VERSION 5.7 ;
BUSBITCHARS "[]" ;
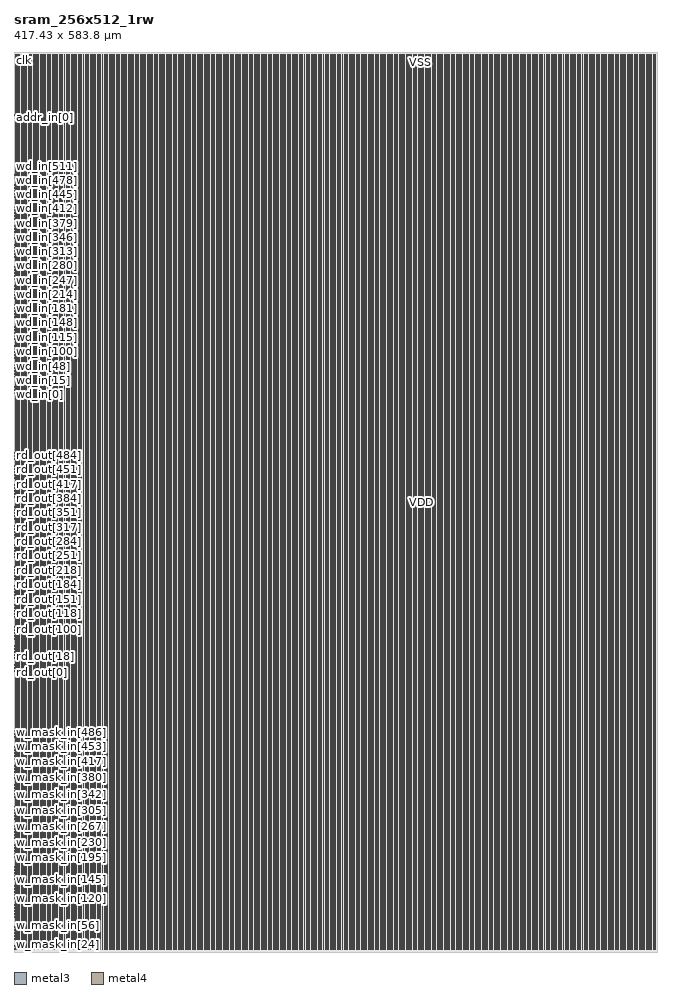
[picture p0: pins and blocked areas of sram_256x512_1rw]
MACRO sram_256x512_1rw
  FOREIGN sram_256x512_1rw 0 0 ;
  SYMMETRY X Y R90 ;
  SIZE 417.430 BY 583.800 ;
  CLASS BLOCK ;
  PIN w_mask_in[0]
    DIRECTION INPUT ;
    USE SIGNAL ;
    SHAPE ABUTMENT ;
    PORT
      LAYER metal3 ;
      RECT 0.000 1.365 0.070 1.435 ;
    END
  END w_mask_in[0]
  PIN w_mask_in[1]
    DIRECTION INPUT ;
    USE SIGNAL ;
    SHAPE ABUTMENT ;
    PORT
      LAYER metal3 ;
      RECT 0.000 1.645 0.070 1.715 ;
    END
  END w_mask_in[1]
  PIN w_mask_in[2]
    DIRECTION INPUT ;
    USE SIGNAL ;
    SHAPE ABUTMENT ;
    PORT
      LAYER metal3 ;
      RECT 0.000 1.925 0.070 1.995 ;
    END
  END w_mask_in[2]
  PIN w_mask_in[3]
    DIRECTION INPUT ;
    USE SIGNAL ;
    SHAPE ABUTMENT ;
    PORT
      LAYER metal3 ;
      RECT 0.000 2.205 0.070 2.275 ;
    END
  END w_mask_in[3]
  PIN w_mask_in[4]
    DIRECTION INPUT ;
    USE SIGNAL ;
    SHAPE ABUTMENT ;
    PORT
      LAYER metal3 ;
      RECT 0.000 2.485 0.070 2.555 ;
    END
  END w_mask_in[4]
  PIN w_mask_in[5]
    DIRECTION INPUT ;
    USE SIGNAL ;
    SHAPE ABUTMENT ;
    PORT
      LAYER metal3 ;
      RECT 0.000 2.765 0.070 2.835 ;
    END
  END w_mask_in[5]
  PIN w_mask_in[6]
    DIRECTION INPUT ;
    USE SIGNAL ;
    SHAPE ABUTMENT ;
    PORT
      LAYER metal3 ;
      RECT 0.000 3.045 0.070 3.115 ;
    END
  END w_mask_in[6]
  PIN w_mask_in[7]
    DIRECTION INPUT ;
    USE SIGNAL ;
    SHAPE ABUTMENT ;
    PORT
      LAYER metal3 ;
      RECT 0.000 3.325 0.070 3.395 ;
    END
  END w_mask_in[7]
  PIN w_mask_in[8]
    DIRECTION INPUT ;
    USE SIGNAL ;
    SHAPE ABUTMENT ;
    PORT
      LAYER metal3 ;
      RECT 0.000 3.605 0.070 3.675 ;
    END
  END w_mask_in[8]
  PIN w_mask_in[9]
    DIRECTION INPUT ;
    USE SIGNAL ;
    SHAPE ABUTMENT ;
    PORT
      LAYER metal3 ;
      RECT 0.000 3.885 0.070 3.955 ;
    END
  END w_mask_in[9]
  PIN w_mask_in[10]
    DIRECTION INPUT ;
    USE SIGNAL ;
    SHAPE ABUTMENT ;
    PORT
      LAYER metal3 ;
      RECT 0.000 4.165 0.070 4.235 ;
    END
  END w_mask_in[10]
  PIN w_mask_in[11]
    DIRECTION INPUT ;
    USE SIGNAL ;
    SHAPE ABUTMENT ;
    PORT
      LAYER metal3 ;
      RECT 0.000 4.445 0.070 4.515 ;
    END
  END w_mask_in[11]
  PIN w_mask_in[12]
    DIRECTION INPUT ;
    USE SIGNAL ;
    SHAPE ABUTMENT ;
    PORT
      LAYER metal3 ;
      RECT 0.000 4.725 0.070 4.795 ;
    END
  END w_mask_in[12]
  PIN w_mask_in[13]
    DIRECTION INPUT ;
    USE SIGNAL ;
    SHAPE ABUTMENT ;
    PORT
      LAYER metal3 ;
      RECT 0.000 5.005 0.070 5.075 ;
    END
  END w_mask_in[13]
  PIN w_mask_in[14]
    DIRECTION INPUT ;
    USE SIGNAL ;
    SHAPE ABUTMENT ;
    PORT
      LAYER metal3 ;
      RECT 0.000 5.285 0.070 5.355 ;
    END
  END w_mask_in[14]
  PIN w_mask_in[15]
    DIRECTION INPUT ;
    USE SIGNAL ;
    SHAPE ABUTMENT ;
    PORT
      LAYER metal3 ;
      RECT 0.000 5.565 0.070 5.635 ;
    END
  END w_mask_in[15]
  PIN w_mask_in[16]
    DIRECTION INPUT ;
    USE SIGNAL ;
    SHAPE ABUTMENT ;
    PORT
      LAYER metal3 ;
      RECT 0.000 5.845 0.070 5.915 ;
    END
  END w_mask_in[16]
  PIN w_mask_in[17]
    DIRECTION INPUT ;
    USE SIGNAL ;
    SHAPE ABUTMENT ;
    PORT
      LAYER metal3 ;
      RECT 0.000 6.125 0.070 6.195 ;
    END
  END w_mask_in[17]
  PIN w_mask_in[18]
    DIRECTION INPUT ;
    USE SIGNAL ;
    SHAPE ABUTMENT ;
    PORT
      LAYER metal3 ;
      RECT 0.000 6.405 0.070 6.475 ;
    END
  END w_mask_in[18]
  PIN w_mask_in[19]
    DIRECTION INPUT ;
    USE SIGNAL ;
    SHAPE ABUTMENT ;
    PORT
      LAYER metal3 ;
      RECT 0.000 6.685 0.070 6.755 ;
    END
  END w_mask_in[19]
  PIN w_mask_in[20]
    DIRECTION INPUT ;
    USE SIGNAL ;
    SHAPE ABUTMENT ;
    PORT
      LAYER metal3 ;
      RECT 0.000 6.965 0.070 7.035 ;
    END
  END w_mask_in[20]
  PIN w_mask_in[21]
    DIRECTION INPUT ;
    USE SIGNAL ;
    SHAPE ABUTMENT ;
    PORT
      LAYER metal3 ;
      RECT 0.000 7.245 0.070 7.315 ;
    END
  END w_mask_in[21]
  PIN w_mask_in[22]
    DIRECTION INPUT ;
    USE SIGNAL ;
    SHAPE ABUTMENT ;
    PORT
      LAYER metal3 ;
      RECT 0.000 7.525 0.070 7.595 ;
    END
  END w_mask_in[22]
  PIN w_mask_in[23]
    DIRECTION INPUT ;
    USE SIGNAL ;
    SHAPE ABUTMENT ;
    PORT
      LAYER metal3 ;
      RECT 0.000 7.805 0.070 7.875 ;
    END
  END w_mask_in[23]
  PIN w_mask_in[24]
    DIRECTION INPUT ;
    USE SIGNAL ;
    SHAPE ABUTMENT ;
    PORT
      LAYER metal3 ;
      RECT 0.000 8.085 0.070 8.155 ;
    END
  END w_mask_in[24]
  PIN w_mask_in[25]
    DIRECTION INPUT ;
    USE SIGNAL ;
    SHAPE ABUTMENT ;
    PORT
      LAYER metal3 ;
      RECT 0.000 8.365 0.070 8.435 ;
    END
  END w_mask_in[25]
  PIN w_mask_in[26]
    DIRECTION INPUT ;
    USE SIGNAL ;
    SHAPE ABUTMENT ;
    PORT
      LAYER metal3 ;
      RECT 0.000 8.645 0.070 8.715 ;
    END
  END w_mask_in[26]
  PIN w_mask_in[27]
    DIRECTION INPUT ;
    USE SIGNAL ;
    SHAPE ABUTMENT ;
    PORT
      LAYER metal3 ;
      RECT 0.000 8.925 0.070 8.995 ;
    END
  END w_mask_in[27]
  PIN w_mask_in[28]
    DIRECTION INPUT ;
    USE SIGNAL ;
    SHAPE ABUTMENT ;
    PORT
      LAYER metal3 ;
      RECT 0.000 9.205 0.070 9.275 ;
    END
  END w_mask_in[28]
  PIN w_mask_in[29]
    DIRECTION INPUT ;
    USE SIGNAL ;
    SHAPE ABUTMENT ;
    PORT
      LAYER metal3 ;
      RECT 0.000 9.485 0.070 9.555 ;
    END
  END w_mask_in[29]
  PIN w_mask_in[30]
    DIRECTION INPUT ;
    USE SIGNAL ;
    SHAPE ABUTMENT ;
    PORT
      LAYER metal3 ;
      RECT 0.000 9.765 0.070 9.835 ;
    END
  END w_mask_in[30]
  PIN w_mask_in[31]
    DIRECTION INPUT ;
    USE SIGNAL ;
    SHAPE ABUTMENT ;
    PORT
      LAYER metal3 ;
      RECT 0.000 10.045 0.070 10.115 ;
    END
  END w_mask_in[31]
  PIN w_mask_in[32]
    DIRECTION INPUT ;
    USE SIGNAL ;
    SHAPE ABUTMENT ;
    PORT
      LAYER metal3 ;
      RECT 0.000 10.325 0.070 10.395 ;
    END
  END w_mask_in[32]
  PIN w_mask_in[33]
    DIRECTION INPUT ;
    USE SIGNAL ;
    SHAPE ABUTMENT ;
    PORT
      LAYER metal3 ;
      RECT 0.000 10.605 0.070 10.675 ;
    END
  END w_mask_in[33]
  PIN w_mask_in[34]
    DIRECTION INPUT ;
    USE SIGNAL ;
    SHAPE ABUTMENT ;
    PORT
      LAYER metal3 ;
      RECT 0.000 10.885 0.070 10.955 ;
    END
  END w_mask_in[34]
  PIN w_mask_in[35]
    DIRECTION INPUT ;
    USE SIGNAL ;
    SHAPE ABUTMENT ;
    PORT
      LAYER metal3 ;
      RECT 0.000 11.165 0.070 11.235 ;
    END
  END w_mask_in[35]
  PIN w_mask_in[36]
    DIRECTION INPUT ;
    USE SIGNAL ;
    SHAPE ABUTMENT ;
    PORT
      LAYER metal3 ;
      RECT 0.000 11.445 0.070 11.515 ;
    END
  END w_mask_in[36]
  PIN w_mask_in[37]
    DIRECTION INPUT ;
    USE SIGNAL ;
    SHAPE ABUTMENT ;
    PORT
      LAYER metal3 ;
      RECT 0.000 11.725 0.070 11.795 ;
    END
  END w_mask_in[37]
  PIN w_mask_in[38]
    DIRECTION INPUT ;
    USE SIGNAL ;
    SHAPE ABUTMENT ;
    PORT
      LAYER metal3 ;
      RECT 0.000 12.005 0.070 12.075 ;
    END
  END w_mask_in[38]
  PIN w_mask_in[39]
    DIRECTION INPUT ;
    USE SIGNAL ;
    SHAPE ABUTMENT ;
    PORT
      LAYER metal3 ;
      RECT 0.000 12.285 0.070 12.355 ;
    END
  END w_mask_in[39]
  PIN w_mask_in[40]
    DIRECTION INPUT ;
    USE SIGNAL ;
    SHAPE ABUTMENT ;
    PORT
      LAYER metal3 ;
      RECT 0.000 12.565 0.070 12.635 ;
    END
  END w_mask_in[40]
  PIN w_mask_in[41]
    DIRECTION INPUT ;
    USE SIGNAL ;
    SHAPE ABUTMENT ;
    PORT
      LAYER metal3 ;
      RECT 0.000 12.845 0.070 12.915 ;
    END
  END w_mask_in[41]
  PIN w_mask_in[42]
    DIRECTION INPUT ;
    USE SIGNAL ;
    SHAPE ABUTMENT ;
    PORT
      LAYER metal3 ;
      RECT 0.000 13.125 0.070 13.195 ;
    END
  END w_mask_in[42]
  PIN w_mask_in[43]
    DIRECTION INPUT ;
    USE SIGNAL ;
    SHAPE ABUTMENT ;
    PORT
      LAYER metal3 ;
      RECT 0.000 13.405 0.070 13.475 ;
    END
  END w_mask_in[43]
  PIN w_mask_in[44]
    DIRECTION INPUT ;
    USE SIGNAL ;
    SHAPE ABUTMENT ;
    PORT
      LAYER metal3 ;
      RECT 0.000 13.685 0.070 13.755 ;
    END
  END w_mask_in[44]
  PIN w_mask_in[45]
    DIRECTION INPUT ;
    USE SIGNAL ;
    SHAPE ABUTMENT ;
    PORT
      LAYER metal3 ;
      RECT 0.000 13.965 0.070 14.035 ;
    END
  END w_mask_in[45]
  PIN w_mask_in[46]
    DIRECTION INPUT ;
    USE SIGNAL ;
    SHAPE ABUTMENT ;
    PORT
      LAYER metal3 ;
      RECT 0.000 14.245 0.070 14.315 ;
    END
  END w_mask_in[46]
  PIN w_mask_in[47]
    DIRECTION INPUT ;
    USE SIGNAL ;
    SHAPE ABUTMENT ;
    PORT
      LAYER metal3 ;
      RECT 0.000 14.525 0.070 14.595 ;
    END
  END w_mask_in[47]
  PIN w_mask_in[48]
    DIRECTION INPUT ;
    USE SIGNAL ;
    SHAPE ABUTMENT ;
    PORT
      LAYER metal3 ;
      RECT 0.000 14.805 0.070 14.875 ;
    END
  END w_mask_in[48]
  PIN w_mask_in[49]
    DIRECTION INPUT ;
    USE SIGNAL ;
    SHAPE ABUTMENT ;
    PORT
      LAYER metal3 ;
      RECT 0.000 15.085 0.070 15.155 ;
    END
  END w_mask_in[49]
  PIN w_mask_in[50]
    DIRECTION INPUT ;
    USE SIGNAL ;
    SHAPE ABUTMENT ;
    PORT
      LAYER metal3 ;
      RECT 0.000 15.365 0.070 15.435 ;
    END
  END w_mask_in[50]
  PIN w_mask_in[51]
    DIRECTION INPUT ;
    USE SIGNAL ;
    SHAPE ABUTMENT ;
    PORT
      LAYER metal3 ;
      RECT 0.000 15.645 0.070 15.715 ;
    END
  END w_mask_in[51]
  PIN w_mask_in[52]
    DIRECTION INPUT ;
    USE SIGNAL ;
    SHAPE ABUTMENT ;
    PORT
      LAYER metal3 ;
      RECT 0.000 15.925 0.070 15.995 ;
    END
  END w_mask_in[52]
  PIN w_mask_in[53]
    DIRECTION INPUT ;
    USE SIGNAL ;
    SHAPE ABUTMENT ;
    PORT
      LAYER metal3 ;
      RECT 0.000 16.205 0.070 16.275 ;
    END
  END w_mask_in[53]
  PIN w_mask_in[54]
    DIRECTION INPUT ;
    USE SIGNAL ;
    SHAPE ABUTMENT ;
    PORT
      LAYER metal3 ;
      RECT 0.000 16.485 0.070 16.555 ;
    END
  END w_mask_in[54]
  PIN w_mask_in[55]
    DIRECTION INPUT ;
    USE SIGNAL ;
    SHAPE ABUTMENT ;
    PORT
      LAYER metal3 ;
      RECT 0.000 16.765 0.070 16.835 ;
    END
  END w_mask_in[55]
  PIN w_mask_in[56]
    DIRECTION INPUT ;
    USE SIGNAL ;
    SHAPE ABUTMENT ;
    PORT
      LAYER metal3 ;
      RECT 0.000 17.045 0.070 17.115 ;
    END
  END w_mask_in[56]
  PIN w_mask_in[57]
    DIRECTION INPUT ;
    USE SIGNAL ;
    SHAPE ABUTMENT ;
    PORT
      LAYER metal3 ;
      RECT 0.000 17.325 0.070 17.395 ;
    END
  END w_mask_in[57]
  PIN w_mask_in[58]
    DIRECTION INPUT ;
    USE SIGNAL ;
    SHAPE ABUTMENT ;
    PORT
      LAYER metal3 ;
      RECT 0.000 17.605 0.070 17.675 ;
    END
  END w_mask_in[58]
  PIN w_mask_in[59]
    DIRECTION INPUT ;
    USE SIGNAL ;
    SHAPE ABUTMENT ;
    PORT
      LAYER metal3 ;
      RECT 0.000 17.885 0.070 17.955 ;
    END
  END w_mask_in[59]
  PIN w_mask_in[60]
    DIRECTION INPUT ;
    USE SIGNAL ;
    SHAPE ABUTMENT ;
    PORT
      LAYER metal3 ;
      RECT 0.000 18.165 0.070 18.235 ;
    END
  END w_mask_in[60]
  PIN w_mask_in[61]
    DIRECTION INPUT ;
    USE SIGNAL ;
    SHAPE ABUTMENT ;
    PORT
      LAYER metal3 ;
      RECT 0.000 18.445 0.070 18.515 ;
    END
  END w_mask_in[61]
  PIN w_mask_in[62]
    DIRECTION INPUT ;
    USE SIGNAL ;
    SHAPE ABUTMENT ;
    PORT
      LAYER metal3 ;
      RECT 0.000 18.725 0.070 18.795 ;
    END
  END w_mask_in[62]
  PIN w_mask_in[63]
    DIRECTION INPUT ;
    USE SIGNAL ;
    SHAPE ABUTMENT ;
    PORT
      LAYER metal3 ;
      RECT 0.000 19.005 0.070 19.075 ;
    END
  END w_mask_in[63]
  PIN w_mask_in[64]
    DIRECTION INPUT ;
    USE SIGNAL ;
    SHAPE ABUTMENT ;
    PORT
      LAYER metal3 ;
      RECT 0.000 19.285 0.070 19.355 ;
    END
  END w_mask_in[64]
  PIN w_mask_in[65]
    DIRECTION INPUT ;
    USE SIGNAL ;
    SHAPE ABUTMENT ;
    PORT
      LAYER metal3 ;
      RECT 0.000 19.565 0.070 19.635 ;
    END
  END w_mask_in[65]
  PIN w_mask_in[66]
    DIRECTION INPUT ;
    USE SIGNAL ;
    SHAPE ABUTMENT ;
    PORT
      LAYER metal3 ;
      RECT 0.000 19.845 0.070 19.915 ;
    END
  END w_mask_in[66]
  PIN w_mask_in[67]
    DIRECTION INPUT ;
    USE SIGNAL ;
    SHAPE ABUTMENT ;
    PORT
      LAYER metal3 ;
      RECT 0.000 20.125 0.070 20.195 ;
    END
  END w_mask_in[67]
  PIN w_mask_in[68]
    DIRECTION INPUT ;
    USE SIGNAL ;
    SHAPE ABUTMENT ;
    PORT
      LAYER metal3 ;
      RECT 0.000 20.405 0.070 20.475 ;
    END
  END w_mask_in[68]
  PIN w_mask_in[69]
    DIRECTION INPUT ;
    USE SIGNAL ;
    SHAPE ABUTMENT ;
    PORT
      LAYER metal3 ;
      RECT 0.000 20.685 0.070 20.755 ;
    END
  END w_mask_in[69]
  PIN w_mask_in[70]
    DIRECTION INPUT ;
    USE SIGNAL ;
    SHAPE ABUTMENT ;
    PORT
      LAYER metal3 ;
      RECT 0.000 20.965 0.070 21.035 ;
    END
  END w_mask_in[70]
  PIN w_mask_in[71]
    DIRECTION INPUT ;
    USE SIGNAL ;
    SHAPE ABUTMENT ;
    PORT
      LAYER metal3 ;
      RECT 0.000 21.245 0.070 21.315 ;
    END
  END w_mask_in[71]
  PIN w_mask_in[72]
    DIRECTION INPUT ;
    USE SIGNAL ;
    SHAPE ABUTMENT ;
    PORT
      LAYER metal3 ;
      RECT 0.000 21.525 0.070 21.595 ;
    END
  END w_mask_in[72]
  PIN w_mask_in[73]
    DIRECTION INPUT ;
    USE SIGNAL ;
    SHAPE ABUTMENT ;
    PORT
      LAYER metal3 ;
      RECT 0.000 21.805 0.070 21.875 ;
    END
  END w_mask_in[73]
  PIN w_mask_in[74]
    DIRECTION INPUT ;
    USE SIGNAL ;
    SHAPE ABUTMENT ;
    PORT
      LAYER metal3 ;
      RECT 0.000 22.085 0.070 22.155 ;
    END
  END w_mask_in[74]
  PIN w_mask_in[75]
    DIRECTION INPUT ;
    USE SIGNAL ;
    SHAPE ABUTMENT ;
    PORT
      LAYER metal3 ;
      RECT 0.000 22.365 0.070 22.435 ;
    END
  END w_mask_in[75]
  PIN w_mask_in[76]
    DIRECTION INPUT ;
    USE SIGNAL ;
    SHAPE ABUTMENT ;
    PORT
      LAYER metal3 ;
      RECT 0.000 22.645 0.070 22.715 ;
    END
  END w_mask_in[76]
  PIN w_mask_in[77]
    DIRECTION INPUT ;
    USE SIGNAL ;
    SHAPE ABUTMENT ;
    PORT
      LAYER metal3 ;
      RECT 0.000 22.925 0.070 22.995 ;
    END
  END w_mask_in[77]
  PIN w_mask_in[78]
    DIRECTION INPUT ;
    USE SIGNAL ;
    SHAPE ABUTMENT ;
    PORT
      LAYER metal3 ;
      RECT 0.000 23.205 0.070 23.275 ;
    END
  END w_mask_in[78]
  PIN w_mask_in[79]
    DIRECTION INPUT ;
    USE SIGNAL ;
    SHAPE ABUTMENT ;
    PORT
      LAYER metal3 ;
      RECT 0.000 23.485 0.070 23.555 ;
    END
  END w_mask_in[79]
  PIN w_mask_in[80]
    DIRECTION INPUT ;
    USE SIGNAL ;
    SHAPE ABUTMENT ;
    PORT
      LAYER metal3 ;
      RECT 0.000 23.765 0.070 23.835 ;
    END
  END w_mask_in[80]
  PIN w_mask_in[81]
    DIRECTION INPUT ;
    USE SIGNAL ;
    SHAPE ABUTMENT ;
    PORT
      LAYER metal3 ;
      RECT 0.000 24.045 0.070 24.115 ;
    END
  END w_mask_in[81]
  PIN w_mask_in[82]
    DIRECTION INPUT ;
    USE SIGNAL ;
    SHAPE ABUTMENT ;
    PORT
      LAYER metal3 ;
      RECT 0.000 24.325 0.070 24.395 ;
    END
  END w_mask_in[82]
  PIN w_mask_in[83]
    DIRECTION INPUT ;
    USE SIGNAL ;
    SHAPE ABUTMENT ;
    PORT
      LAYER metal3 ;
      RECT 0.000 24.605 0.070 24.675 ;
    END
  END w_mask_in[83]
  PIN w_mask_in[84]
    DIRECTION INPUT ;
    USE SIGNAL ;
    SHAPE ABUTMENT ;
    PORT
      LAYER metal3 ;
      RECT 0.000 24.885 0.070 24.955 ;
    END
  END w_mask_in[84]
  PIN w_mask_in[85]
    DIRECTION INPUT ;
    USE SIGNAL ;
    SHAPE ABUTMENT ;
    PORT
      LAYER metal3 ;
      RECT 0.000 25.165 0.070 25.235 ;
    END
  END w_mask_in[85]
  PIN w_mask_in[86]
    DIRECTION INPUT ;
    USE SIGNAL ;
    SHAPE ABUTMENT ;
    PORT
      LAYER metal3 ;
      RECT 0.000 25.445 0.070 25.515 ;
    END
  END w_mask_in[86]
  PIN w_mask_in[87]
    DIRECTION INPUT ;
    USE SIGNAL ;
    SHAPE ABUTMENT ;
    PORT
      LAYER metal3 ;
      RECT 0.000 25.725 0.070 25.795 ;
    END
  END w_mask_in[87]
  PIN w_mask_in[88]
    DIRECTION INPUT ;
    USE SIGNAL ;
    SHAPE ABUTMENT ;
    PORT
      LAYER metal3 ;
      RECT 0.000 26.005 0.070 26.075 ;
    END
  END w_mask_in[88]
  PIN w_mask_in[89]
    DIRECTION INPUT ;
    USE SIGNAL ;
    SHAPE ABUTMENT ;
    PORT
      LAYER metal3 ;
      RECT 0.000 26.285 0.070 26.355 ;
    END
  END w_mask_in[89]
  PIN w_mask_in[90]
    DIRECTION INPUT ;
    USE SIGNAL ;
    SHAPE ABUTMENT ;
    PORT
      LAYER metal3 ;
      RECT 0.000 26.565 0.070 26.635 ;
    END
  END w_mask_in[90]
  PIN w_mask_in[91]
    DIRECTION INPUT ;
    USE SIGNAL ;
    SHAPE ABUTMENT ;
    PORT
      LAYER metal3 ;
      RECT 0.000 26.845 0.070 26.915 ;
    END
  END w_mask_in[91]
  PIN w_mask_in[92]
    DIRECTION INPUT ;
    USE SIGNAL ;
    SHAPE ABUTMENT ;
    PORT
      LAYER metal3 ;
      RECT 0.000 27.125 0.070 27.195 ;
    END
  END w_mask_in[92]
  PIN w_mask_in[93]
    DIRECTION INPUT ;
    USE SIGNAL ;
    SHAPE ABUTMENT ;
    PORT
      LAYER metal3 ;
      RECT 0.000 27.405 0.070 27.475 ;
    END
  END w_mask_in[93]
  PIN w_mask_in[94]
    DIRECTION INPUT ;
    USE SIGNAL ;
    SHAPE ABUTMENT ;
    PORT
      LAYER metal3 ;
      RECT 0.000 27.685 0.070 27.755 ;
    END
  END w_mask_in[94]
  PIN w_mask_in[95]
    DIRECTION INPUT ;
    USE SIGNAL ;
    SHAPE ABUTMENT ;
    PORT
      LAYER metal3 ;
      RECT 0.000 27.965 0.070 28.035 ;
    END
  END w_mask_in[95]
  PIN w_mask_in[96]
    DIRECTION INPUT ;
    USE SIGNAL ;
    SHAPE ABUTMENT ;
    PORT
      LAYER metal3 ;
      RECT 0.000 28.245 0.070 28.315 ;
    END
  END w_mask_in[96]
  PIN w_mask_in[97]
    DIRECTION INPUT ;
    USE SIGNAL ;
    SHAPE ABUTMENT ;
    PORT
      LAYER metal3 ;
      RECT 0.000 28.525 0.070 28.595 ;
    END
  END w_mask_in[97]
  PIN w_mask_in[98]
    DIRECTION INPUT ;
    USE SIGNAL ;
    SHAPE ABUTMENT ;
    PORT
      LAYER metal3 ;
      RECT 0.000 28.805 0.070 28.875 ;
    END
  END w_mask_in[98]
  PIN w_mask_in[99]
    DIRECTION INPUT ;
    USE SIGNAL ;
    SHAPE ABUTMENT ;
    PORT
      LAYER metal3 ;
      RECT 0.000 29.085 0.070 29.155 ;
    END
  END w_mask_in[99]
  PIN w_mask_in[100]
    DIRECTION INPUT ;
    USE SIGNAL ;
    SHAPE ABUTMENT ;
    PORT
      LAYER metal3 ;
      RECT 0.000 29.365 0.070 29.435 ;
    END
  END w_mask_in[100]
  PIN w_mask_in[101]
    DIRECTION INPUT ;
    USE SIGNAL ;
    SHAPE ABUTMENT ;
    PORT
      LAYER metal3 ;
      RECT 0.000 29.645 0.070 29.715 ;
    END
  END w_mask_in[101]
  PIN w_mask_in[102]
    DIRECTION INPUT ;
    USE SIGNAL ;
    SHAPE ABUTMENT ;
    PORT
      LAYER metal3 ;
      RECT 0.000 29.925 0.070 29.995 ;
    END
  END w_mask_in[102]
  PIN w_mask_in[103]
    DIRECTION INPUT ;
    USE SIGNAL ;
    SHAPE ABUTMENT ;
    PORT
      LAYER metal3 ;
      RECT 0.000 30.205 0.070 30.275 ;
    END
  END w_mask_in[103]
  PIN w_mask_in[104]
    DIRECTION INPUT ;
    USE SIGNAL ;
    SHAPE ABUTMENT ;
    PORT
      LAYER metal3 ;
      RECT 0.000 30.485 0.070 30.555 ;
    END
  END w_mask_in[104]
  PIN w_mask_in[105]
    DIRECTION INPUT ;
    USE SIGNAL ;
    SHAPE ABUTMENT ;
    PORT
      LAYER metal3 ;
      RECT 0.000 30.765 0.070 30.835 ;
    END
  END w_mask_in[105]
  PIN w_mask_in[106]
    DIRECTION INPUT ;
    USE SIGNAL ;
    SHAPE ABUTMENT ;
    PORT
      LAYER metal3 ;
      RECT 0.000 31.045 0.070 31.115 ;
    END
  END w_mask_in[106]
  PIN w_mask_in[107]
    DIRECTION INPUT ;
    USE SIGNAL ;
    SHAPE ABUTMENT ;
    PORT
      LAYER metal3 ;
      RECT 0.000 31.325 0.070 31.395 ;
    END
  END w_mask_in[107]
  PIN w_mask_in[108]
    DIRECTION INPUT ;
    USE SIGNAL ;
    SHAPE ABUTMENT ;
    PORT
      LAYER metal3 ;
      RECT 0.000 31.605 0.070 31.675 ;
    END
  END w_mask_in[108]
  PIN w_mask_in[109]
    DIRECTION INPUT ;
    USE SIGNAL ;
    SHAPE ABUTMENT ;
    PORT
      LAYER metal3 ;
      RECT 0.000 31.885 0.070 31.955 ;
    END
  END w_mask_in[109]
  PIN w_mask_in[110]
    DIRECTION INPUT ;
    USE SIGNAL ;
    SHAPE ABUTMENT ;
    PORT
      LAYER metal3 ;
      RECT 0.000 32.165 0.070 32.235 ;
    END
  END w_mask_in[110]
  PIN w_mask_in[111]
    DIRECTION INPUT ;
    USE SIGNAL ;
    SHAPE ABUTMENT ;
    PORT
      LAYER metal3 ;
      RECT 0.000 32.445 0.070 32.515 ;
    END
  END w_mask_in[111]
  PIN w_mask_in[112]
    DIRECTION INPUT ;
    USE SIGNAL ;
    SHAPE ABUTMENT ;
    PORT
      LAYER metal3 ;
      RECT 0.000 32.725 0.070 32.795 ;
    END
  END w_mask_in[112]
  PIN w_mask_in[113]
    DIRECTION INPUT ;
    USE SIGNAL ;
    SHAPE ABUTMENT ;
    PORT
      LAYER metal3 ;
      RECT 0.000 33.005 0.070 33.075 ;
    END
  END w_mask_in[113]
  PIN w_mask_in[114]
    DIRECTION INPUT ;
    USE SIGNAL ;
    SHAPE ABUTMENT ;
    PORT
      LAYER metal3 ;
      RECT 0.000 33.285 0.070 33.355 ;
    END
  END w_mask_in[114]
  PIN w_mask_in[115]
    DIRECTION INPUT ;
    USE SIGNAL ;
    SHAPE ABUTMENT ;
    PORT
      LAYER metal3 ;
      RECT 0.000 33.565 0.070 33.635 ;
    END
  END w_mask_in[115]
  PIN w_mask_in[116]
    DIRECTION INPUT ;
    USE SIGNAL ;
    SHAPE ABUTMENT ;
    PORT
      LAYER metal3 ;
      RECT 0.000 33.845 0.070 33.915 ;
    END
  END w_mask_in[116]
  PIN w_mask_in[117]
    DIRECTION INPUT ;
    USE SIGNAL ;
    SHAPE ABUTMENT ;
    PORT
      LAYER metal3 ;
      RECT 0.000 34.125 0.070 34.195 ;
    END
  END w_mask_in[117]
  PIN w_mask_in[118]
    DIRECTION INPUT ;
    USE SIGNAL ;
    SHAPE ABUTMENT ;
    PORT
      LAYER metal3 ;
      RECT 0.000 34.405 0.070 34.475 ;
    END
  END w_mask_in[118]
  PIN w_mask_in[119]
    DIRECTION INPUT ;
    USE SIGNAL ;
    SHAPE ABUTMENT ;
    PORT
      LAYER metal3 ;
      RECT 0.000 34.685 0.070 34.755 ;
    END
  END w_mask_in[119]
  PIN w_mask_in[120]
    DIRECTION INPUT ;
    USE SIGNAL ;
    SHAPE ABUTMENT ;
    PORT
      LAYER metal3 ;
      RECT 0.000 34.965 0.070 35.035 ;
    END
  END w_mask_in[120]
  PIN w_mask_in[121]
    DIRECTION INPUT ;
    USE SIGNAL ;
    SHAPE ABUTMENT ;
    PORT
      LAYER metal3 ;
      RECT 0.000 35.245 0.070 35.315 ;
    END
  END w_mask_in[121]
  PIN w_mask_in[122]
    DIRECTION INPUT ;
    USE SIGNAL ;
    SHAPE ABUTMENT ;
    PORT
      LAYER metal3 ;
      RECT 0.000 35.525 0.070 35.595 ;
    END
  END w_mask_in[122]
  PIN w_mask_in[123]
    DIRECTION INPUT ;
    USE SIGNAL ;
    SHAPE ABUTMENT ;
    PORT
      LAYER metal3 ;
      RECT 0.000 35.805 0.070 35.875 ;
    END
  END w_mask_in[123]
  PIN w_mask_in[124]
    DIRECTION INPUT ;
    USE SIGNAL ;
    SHAPE ABUTMENT ;
    PORT
      LAYER metal3 ;
      RECT 0.000 36.085 0.070 36.155 ;
    END
  END w_mask_in[124]
  PIN w_mask_in[125]
    DIRECTION INPUT ;
    USE SIGNAL ;
    SHAPE ABUTMENT ;
    PORT
      LAYER metal3 ;
      RECT 0.000 36.365 0.070 36.435 ;
    END
  END w_mask_in[125]
  PIN w_mask_in[126]
    DIRECTION INPUT ;
    USE SIGNAL ;
    SHAPE ABUTMENT ;
    PORT
      LAYER metal3 ;
      RECT 0.000 36.645 0.070 36.715 ;
    END
  END w_mask_in[126]
  PIN w_mask_in[127]
    DIRECTION INPUT ;
    USE SIGNAL ;
    SHAPE ABUTMENT ;
    PORT
      LAYER metal3 ;
      RECT 0.000 36.925 0.070 36.995 ;
    END
  END w_mask_in[127]
  PIN w_mask_in[128]
    DIRECTION INPUT ;
    USE SIGNAL ;
    SHAPE ABUTMENT ;
    PORT
      LAYER metal3 ;
      RECT 0.000 37.205 0.070 37.275 ;
    END
  END w_mask_in[128]
  PIN w_mask_in[129]
    DIRECTION INPUT ;
    USE SIGNAL ;
    SHAPE ABUTMENT ;
    PORT
      LAYER metal3 ;
      RECT 0.000 37.485 0.070 37.555 ;
    END
  END w_mask_in[129]
  PIN w_mask_in[130]
    DIRECTION INPUT ;
    USE SIGNAL ;
    SHAPE ABUTMENT ;
    PORT
      LAYER metal3 ;
      RECT 0.000 37.765 0.070 37.835 ;
    END
  END w_mask_in[130]
  PIN w_mask_in[131]
    DIRECTION INPUT ;
    USE SIGNAL ;
    SHAPE ABUTMENT ;
    PORT
      LAYER metal3 ;
      RECT 0.000 38.045 0.070 38.115 ;
    END
  END w_mask_in[131]
  PIN w_mask_in[132]
    DIRECTION INPUT ;
    USE SIGNAL ;
    SHAPE ABUTMENT ;
    PORT
      LAYER metal3 ;
      RECT 0.000 38.325 0.070 38.395 ;
    END
  END w_mask_in[132]
  PIN w_mask_in[133]
    DIRECTION INPUT ;
    USE SIGNAL ;
    SHAPE ABUTMENT ;
    PORT
      LAYER metal3 ;
      RECT 0.000 38.605 0.070 38.675 ;
    END
  END w_mask_in[133]
  PIN w_mask_in[134]
    DIRECTION INPUT ;
    USE SIGNAL ;
    SHAPE ABUTMENT ;
    PORT
      LAYER metal3 ;
      RECT 0.000 38.885 0.070 38.955 ;
    END
  END w_mask_in[134]
  PIN w_mask_in[135]
    DIRECTION INPUT ;
    USE SIGNAL ;
    SHAPE ABUTMENT ;
    PORT
      LAYER metal3 ;
      RECT 0.000 39.165 0.070 39.235 ;
    END
  END w_mask_in[135]
  PIN w_mask_in[136]
    DIRECTION INPUT ;
    USE SIGNAL ;
    SHAPE ABUTMENT ;
    PORT
      LAYER metal3 ;
      RECT 0.000 39.445 0.070 39.515 ;
    END
  END w_mask_in[136]
  PIN w_mask_in[137]
    DIRECTION INPUT ;
    USE SIGNAL ;
    SHAPE ABUTMENT ;
    PORT
      LAYER metal3 ;
      RECT 0.000 39.725 0.070 39.795 ;
    END
  END w_mask_in[137]
  PIN w_mask_in[138]
    DIRECTION INPUT ;
    USE SIGNAL ;
    SHAPE ABUTMENT ;
    PORT
      LAYER metal3 ;
      RECT 0.000 40.005 0.070 40.075 ;
    END
  END w_mask_in[138]
  PIN w_mask_in[139]
    DIRECTION INPUT ;
    USE SIGNAL ;
    SHAPE ABUTMENT ;
    PORT
      LAYER metal3 ;
      RECT 0.000 40.285 0.070 40.355 ;
    END
  END w_mask_in[139]
  PIN w_mask_in[140]
    DIRECTION INPUT ;
    USE SIGNAL ;
    SHAPE ABUTMENT ;
    PORT
      LAYER metal3 ;
      RECT 0.000 40.565 0.070 40.635 ;
    END
  END w_mask_in[140]
  PIN w_mask_in[141]
    DIRECTION INPUT ;
    USE SIGNAL ;
    SHAPE ABUTMENT ;
    PORT
      LAYER metal3 ;
      RECT 0.000 40.845 0.070 40.915 ;
    END
  END w_mask_in[141]
  PIN w_mask_in[142]
    DIRECTION INPUT ;
    USE SIGNAL ;
    SHAPE ABUTMENT ;
    PORT
      LAYER metal3 ;
      RECT 0.000 41.125 0.070 41.195 ;
    END
  END w_mask_in[142]
  PIN w_mask_in[143]
    DIRECTION INPUT ;
    USE SIGNAL ;
    SHAPE ABUTMENT ;
    PORT
      LAYER metal3 ;
      RECT 0.000 41.405 0.070 41.475 ;
    END
  END w_mask_in[143]
  PIN w_mask_in[144]
    DIRECTION INPUT ;
    USE SIGNAL ;
    SHAPE ABUTMENT ;
    PORT
      LAYER metal3 ;
      RECT 0.000 41.685 0.070 41.755 ;
    END
  END w_mask_in[144]
  PIN w_mask_in[145]
    DIRECTION INPUT ;
    USE SIGNAL ;
    SHAPE ABUTMENT ;
    PORT
      LAYER metal3 ;
      RECT 0.000 41.965 0.070 42.035 ;
    END
  END w_mask_in[145]
  PIN w_mask_in[146]
    DIRECTION INPUT ;
    USE SIGNAL ;
    SHAPE ABUTMENT ;
    PORT
      LAYER metal3 ;
      RECT 0.000 42.245 0.070 42.315 ;
    END
  END w_mask_in[146]
  PIN w_mask_in[147]
    DIRECTION INPUT ;
    USE SIGNAL ;
    SHAPE ABUTMENT ;
    PORT
      LAYER metal3 ;
      RECT 0.000 42.525 0.070 42.595 ;
    END
  END w_mask_in[147]
  PIN w_mask_in[148]
    DIRECTION INPUT ;
    USE SIGNAL ;
    SHAPE ABUTMENT ;
    PORT
      LAYER metal3 ;
      RECT 0.000 42.805 0.070 42.875 ;
    END
  END w_mask_in[148]
  PIN w_mask_in[149]
    DIRECTION INPUT ;
    USE SIGNAL ;
    SHAPE ABUTMENT ;
    PORT
      LAYER metal3 ;
      RECT 0.000 43.085 0.070 43.155 ;
    END
  END w_mask_in[149]
  PIN w_mask_in[150]
    DIRECTION INPUT ;
    USE SIGNAL ;
    SHAPE ABUTMENT ;
    PORT
      LAYER metal3 ;
      RECT 0.000 43.365 0.070 43.435 ;
    END
  END w_mask_in[150]
  PIN w_mask_in[151]
    DIRECTION INPUT ;
    USE SIGNAL ;
    SHAPE ABUTMENT ;
    PORT
      LAYER metal3 ;
      RECT 0.000 43.645 0.070 43.715 ;
    END
  END w_mask_in[151]
  PIN w_mask_in[152]
    DIRECTION INPUT ;
    USE SIGNAL ;
    SHAPE ABUTMENT ;
    PORT
      LAYER metal3 ;
      RECT 0.000 43.925 0.070 43.995 ;
    END
  END w_mask_in[152]
  PIN w_mask_in[153]
    DIRECTION INPUT ;
    USE SIGNAL ;
    SHAPE ABUTMENT ;
    PORT
      LAYER metal3 ;
      RECT 0.000 44.205 0.070 44.275 ;
    END
  END w_mask_in[153]
  PIN w_mask_in[154]
    DIRECTION INPUT ;
    USE SIGNAL ;
    SHAPE ABUTMENT ;
    PORT
      LAYER metal3 ;
      RECT 0.000 44.485 0.070 44.555 ;
    END
  END w_mask_in[154]
  PIN w_mask_in[155]
    DIRECTION INPUT ;
    USE SIGNAL ;
    SHAPE ABUTMENT ;
    PORT
      LAYER metal3 ;
      RECT 0.000 44.765 0.070 44.835 ;
    END
  END w_mask_in[155]
  PIN w_mask_in[156]
    DIRECTION INPUT ;
    USE SIGNAL ;
    SHAPE ABUTMENT ;
    PORT
      LAYER metal3 ;
      RECT 0.000 45.045 0.070 45.115 ;
    END
  END w_mask_in[156]
  PIN w_mask_in[157]
    DIRECTION INPUT ;
    USE SIGNAL ;
    SHAPE ABUTMENT ;
    PORT
      LAYER metal3 ;
      RECT 0.000 45.325 0.070 45.395 ;
    END
  END w_mask_in[157]
  PIN w_mask_in[158]
    DIRECTION INPUT ;
    USE SIGNAL ;
    SHAPE ABUTMENT ;
    PORT
      LAYER metal3 ;
      RECT 0.000 45.605 0.070 45.675 ;
    END
  END w_mask_in[158]
  PIN w_mask_in[159]
    DIRECTION INPUT ;
    USE SIGNAL ;
    SHAPE ABUTMENT ;
    PORT
      LAYER metal3 ;
      RECT 0.000 45.885 0.070 45.955 ;
    END
  END w_mask_in[159]
  PIN w_mask_in[160]
    DIRECTION INPUT ;
    USE SIGNAL ;
    SHAPE ABUTMENT ;
    PORT
      LAYER metal3 ;
      RECT 0.000 46.165 0.070 46.235 ;
    END
  END w_mask_in[160]
  PIN w_mask_in[161]
    DIRECTION INPUT ;
    USE SIGNAL ;
    SHAPE ABUTMENT ;
    PORT
      LAYER metal3 ;
      RECT 0.000 46.445 0.070 46.515 ;
    END
  END w_mask_in[161]
  PIN w_mask_in[162]
    DIRECTION INPUT ;
    USE SIGNAL ;
    SHAPE ABUTMENT ;
    PORT
      LAYER metal3 ;
      RECT 0.000 46.725 0.070 46.795 ;
    END
  END w_mask_in[162]
  PIN w_mask_in[163]
    DIRECTION INPUT ;
    USE SIGNAL ;
    SHAPE ABUTMENT ;
    PORT
      LAYER metal3 ;
      RECT 0.000 47.005 0.070 47.075 ;
    END
  END w_mask_in[163]
  PIN w_mask_in[164]
    DIRECTION INPUT ;
    USE SIGNAL ;
    SHAPE ABUTMENT ;
    PORT
      LAYER metal3 ;
      RECT 0.000 47.285 0.070 47.355 ;
    END
  END w_mask_in[164]
  PIN w_mask_in[165]
    DIRECTION INPUT ;
    USE SIGNAL ;
    SHAPE ABUTMENT ;
    PORT
      LAYER metal3 ;
      RECT 0.000 47.565 0.070 47.635 ;
    END
  END w_mask_in[165]
  PIN w_mask_in[166]
    DIRECTION INPUT ;
    USE SIGNAL ;
    SHAPE ABUTMENT ;
    PORT
      LAYER metal3 ;
      RECT 0.000 47.845 0.070 47.915 ;
    END
  END w_mask_in[166]
  PIN w_mask_in[167]
    DIRECTION INPUT ;
    USE SIGNAL ;
    SHAPE ABUTMENT ;
    PORT
      LAYER metal3 ;
      RECT 0.000 48.125 0.070 48.195 ;
    END
  END w_mask_in[167]
  PIN w_mask_in[168]
    DIRECTION INPUT ;
    USE SIGNAL ;
    SHAPE ABUTMENT ;
    PORT
      LAYER metal3 ;
      RECT 0.000 48.405 0.070 48.475 ;
    END
  END w_mask_in[168]
  PIN w_mask_in[169]
    DIRECTION INPUT ;
    USE SIGNAL ;
    SHAPE ABUTMENT ;
    PORT
      LAYER metal3 ;
      RECT 0.000 48.685 0.070 48.755 ;
    END
  END w_mask_in[169]
  PIN w_mask_in[170]
    DIRECTION INPUT ;
    USE SIGNAL ;
    SHAPE ABUTMENT ;
    PORT
      LAYER metal3 ;
      RECT 0.000 48.965 0.070 49.035 ;
    END
  END w_mask_in[170]
  PIN w_mask_in[171]
    DIRECTION INPUT ;
    USE SIGNAL ;
    SHAPE ABUTMENT ;
    PORT
      LAYER metal3 ;
      RECT 0.000 49.245 0.070 49.315 ;
    END
  END w_mask_in[171]
  PIN w_mask_in[172]
    DIRECTION INPUT ;
    USE SIGNAL ;
    SHAPE ABUTMENT ;
    PORT
      LAYER metal3 ;
      RECT 0.000 49.525 0.070 49.595 ;
    END
  END w_mask_in[172]
  PIN w_mask_in[173]
    DIRECTION INPUT ;
    USE SIGNAL ;
    SHAPE ABUTMENT ;
    PORT
      LAYER metal3 ;
      RECT 0.000 49.805 0.070 49.875 ;
    END
  END w_mask_in[173]
  PIN w_mask_in[174]
    DIRECTION INPUT ;
    USE SIGNAL ;
    SHAPE ABUTMENT ;
    PORT
      LAYER metal3 ;
      RECT 0.000 50.085 0.070 50.155 ;
    END
  END w_mask_in[174]
  PIN w_mask_in[175]
    DIRECTION INPUT ;
    USE SIGNAL ;
    SHAPE ABUTMENT ;
    PORT
      LAYER metal3 ;
      RECT 0.000 50.365 0.070 50.435 ;
    END
  END w_mask_in[175]
  PIN w_mask_in[176]
    DIRECTION INPUT ;
    USE SIGNAL ;
    SHAPE ABUTMENT ;
    PORT
      LAYER metal3 ;
      RECT 0.000 50.645 0.070 50.715 ;
    END
  END w_mask_in[176]
  PIN w_mask_in[177]
    DIRECTION INPUT ;
    USE SIGNAL ;
    SHAPE ABUTMENT ;
    PORT
      LAYER metal3 ;
      RECT 0.000 50.925 0.070 50.995 ;
    END
  END w_mask_in[177]
  PIN w_mask_in[178]
    DIRECTION INPUT ;
    USE SIGNAL ;
    SHAPE ABUTMENT ;
    PORT
      LAYER metal3 ;
      RECT 0.000 51.205 0.070 51.275 ;
    END
  END w_mask_in[178]
  PIN w_mask_in[179]
    DIRECTION INPUT ;
    USE SIGNAL ;
    SHAPE ABUTMENT ;
    PORT
      LAYER metal3 ;
      RECT 0.000 51.485 0.070 51.555 ;
    END
  END w_mask_in[179]
  PIN w_mask_in[180]
    DIRECTION INPUT ;
    USE SIGNAL ;
    SHAPE ABUTMENT ;
    PORT
      LAYER metal3 ;
      RECT 0.000 51.765 0.070 51.835 ;
    END
  END w_mask_in[180]
  PIN w_mask_in[181]
    DIRECTION INPUT ;
    USE SIGNAL ;
    SHAPE ABUTMENT ;
    PORT
      LAYER metal3 ;
      RECT 0.000 52.045 0.070 52.115 ;
    END
  END w_mask_in[181]
  PIN w_mask_in[182]
    DIRECTION INPUT ;
    USE SIGNAL ;
    SHAPE ABUTMENT ;
    PORT
      LAYER metal3 ;
      RECT 0.000 52.325 0.070 52.395 ;
    END
  END w_mask_in[182]
  PIN w_mask_in[183]
    DIRECTION INPUT ;
    USE SIGNAL ;
    SHAPE ABUTMENT ;
    PORT
      LAYER metal3 ;
      RECT 0.000 52.605 0.070 52.675 ;
    END
  END w_mask_in[183]
  PIN w_mask_in[184]
    DIRECTION INPUT ;
    USE SIGNAL ;
    SHAPE ABUTMENT ;
    PORT
      LAYER metal3 ;
      RECT 0.000 52.885 0.070 52.955 ;
    END
  END w_mask_in[184]
  PIN w_mask_in[185]
    DIRECTION INPUT ;
    USE SIGNAL ;
    SHAPE ABUTMENT ;
    PORT
      LAYER metal3 ;
      RECT 0.000 53.165 0.070 53.235 ;
    END
  END w_mask_in[185]
  PIN w_mask_in[186]
    DIRECTION INPUT ;
    USE SIGNAL ;
    SHAPE ABUTMENT ;
    PORT
      LAYER metal3 ;
      RECT 0.000 53.445 0.070 53.515 ;
    END
  END w_mask_in[186]
  PIN w_mask_in[187]
    DIRECTION INPUT ;
    USE SIGNAL ;
    SHAPE ABUTMENT ;
    PORT
      LAYER metal3 ;
      RECT 0.000 53.725 0.070 53.795 ;
    END
  END w_mask_in[187]
  PIN w_mask_in[188]
    DIRECTION INPUT ;
    USE SIGNAL ;
    SHAPE ABUTMENT ;
    PORT
      LAYER metal3 ;
      RECT 0.000 54.005 0.070 54.075 ;
    END
  END w_mask_in[188]
  PIN w_mask_in[189]
    DIRECTION INPUT ;
    USE SIGNAL ;
    SHAPE ABUTMENT ;
    PORT
      LAYER metal3 ;
      RECT 0.000 54.285 0.070 54.355 ;
    END
  END w_mask_in[189]
  PIN w_mask_in[190]
    DIRECTION INPUT ;
    USE SIGNAL ;
    SHAPE ABUTMENT ;
    PORT
      LAYER metal3 ;
      RECT 0.000 54.565 0.070 54.635 ;
    END
  END w_mask_in[190]
  PIN w_mask_in[191]
    DIRECTION INPUT ;
    USE SIGNAL ;
    SHAPE ABUTMENT ;
    PORT
      LAYER metal3 ;
      RECT 0.000 54.845 0.070 54.915 ;
    END
  END w_mask_in[191]
  PIN w_mask_in[192]
    DIRECTION INPUT ;
    USE SIGNAL ;
    SHAPE ABUTMENT ;
    PORT
      LAYER metal3 ;
      RECT 0.000 55.125 0.070 55.195 ;
    END
  END w_mask_in[192]
  PIN w_mask_in[193]
    DIRECTION INPUT ;
    USE SIGNAL ;
    SHAPE ABUTMENT ;
    PORT
      LAYER metal3 ;
      RECT 0.000 55.405 0.070 55.475 ;
    END
  END w_mask_in[193]
  PIN w_mask_in[194]
    DIRECTION INPUT ;
    USE SIGNAL ;
    SHAPE ABUTMENT ;
    PORT
      LAYER metal3 ;
      RECT 0.000 55.685 0.070 55.755 ;
    END
  END w_mask_in[194]
  PIN w_mask_in[195]
    DIRECTION INPUT ;
    USE SIGNAL ;
    SHAPE ABUTMENT ;
    PORT
      LAYER metal3 ;
      RECT 0.000 55.965 0.070 56.035 ;
    END
  END w_mask_in[195]
  PIN w_mask_in[196]
    DIRECTION INPUT ;
    USE SIGNAL ;
    SHAPE ABUTMENT ;
    PORT
      LAYER metal3 ;
      RECT 0.000 56.245 0.070 56.315 ;
    END
  END w_mask_in[196]
  PIN w_mask_in[197]
    DIRECTION INPUT ;
    USE SIGNAL ;
    SHAPE ABUTMENT ;
    PORT
      LAYER metal3 ;
      RECT 0.000 56.525 0.070 56.595 ;
    END
  END w_mask_in[197]
  PIN w_mask_in[198]
    DIRECTION INPUT ;
    USE SIGNAL ;
    SHAPE ABUTMENT ;
    PORT
      LAYER metal3 ;
      RECT 0.000 56.805 0.070 56.875 ;
    END
  END w_mask_in[198]
  PIN w_mask_in[199]
    DIRECTION INPUT ;
    USE SIGNAL ;
    SHAPE ABUTMENT ;
    PORT
      LAYER metal3 ;
      RECT 0.000 57.085 0.070 57.155 ;
    END
  END w_mask_in[199]
  PIN w_mask_in[200]
    DIRECTION INPUT ;
    USE SIGNAL ;
    SHAPE ABUTMENT ;
    PORT
      LAYER metal3 ;
      RECT 0.000 57.365 0.070 57.435 ;
    END
  END w_mask_in[200]
  PIN w_mask_in[201]
    DIRECTION INPUT ;
    USE SIGNAL ;
    SHAPE ABUTMENT ;
    PORT
      LAYER metal3 ;
      RECT 0.000 57.645 0.070 57.715 ;
    END
  END w_mask_in[201]
  PIN w_mask_in[202]
    DIRECTION INPUT ;
    USE SIGNAL ;
    SHAPE ABUTMENT ;
    PORT
      LAYER metal3 ;
      RECT 0.000 57.925 0.070 57.995 ;
    END
  END w_mask_in[202]
  PIN w_mask_in[203]
    DIRECTION INPUT ;
    USE SIGNAL ;
    SHAPE ABUTMENT ;
    PORT
      LAYER metal3 ;
      RECT 0.000 58.205 0.070 58.275 ;
    END
  END w_mask_in[203]
  PIN w_mask_in[204]
    DIRECTION INPUT ;
    USE SIGNAL ;
    SHAPE ABUTMENT ;
    PORT
      LAYER metal3 ;
      RECT 0.000 58.485 0.070 58.555 ;
    END
  END w_mask_in[204]
  PIN w_mask_in[205]
    DIRECTION INPUT ;
    USE SIGNAL ;
    SHAPE ABUTMENT ;
    PORT
      LAYER metal3 ;
      RECT 0.000 58.765 0.070 58.835 ;
    END
  END w_mask_in[205]
  PIN w_mask_in[206]
    DIRECTION INPUT ;
    USE SIGNAL ;
    SHAPE ABUTMENT ;
    PORT
      LAYER metal3 ;
      RECT 0.000 59.045 0.070 59.115 ;
    END
  END w_mask_in[206]
  PIN w_mask_in[207]
    DIRECTION INPUT ;
    USE SIGNAL ;
    SHAPE ABUTMENT ;
    PORT
      LAYER metal3 ;
      RECT 0.000 59.325 0.070 59.395 ;
    END
  END w_mask_in[207]
  PIN w_mask_in[208]
    DIRECTION INPUT ;
    USE SIGNAL ;
    SHAPE ABUTMENT ;
    PORT
      LAYER metal3 ;
      RECT 0.000 59.605 0.070 59.675 ;
    END
  END w_mask_in[208]
  PIN w_mask_in[209]
    DIRECTION INPUT ;
    USE SIGNAL ;
    SHAPE ABUTMENT ;
    PORT
      LAYER metal3 ;
      RECT 0.000 59.885 0.070 59.955 ;
    END
  END w_mask_in[209]
  PIN w_mask_in[210]
    DIRECTION INPUT ;
    USE SIGNAL ;
    SHAPE ABUTMENT ;
    PORT
      LAYER metal3 ;
      RECT 0.000 60.165 0.070 60.235 ;
    END
  END w_mask_in[210]
  PIN w_mask_in[211]
    DIRECTION INPUT ;
    USE SIGNAL ;
    SHAPE ABUTMENT ;
    PORT
      LAYER metal3 ;
      RECT 0.000 60.445 0.070 60.515 ;
    END
  END w_mask_in[211]
  PIN w_mask_in[212]
    DIRECTION INPUT ;
    USE SIGNAL ;
    SHAPE ABUTMENT ;
    PORT
      LAYER metal3 ;
      RECT 0.000 60.725 0.070 60.795 ;
    END
  END w_mask_in[212]
  PIN w_mask_in[213]
    DIRECTION INPUT ;
    USE SIGNAL ;
    SHAPE ABUTMENT ;
    PORT
      LAYER metal3 ;
      RECT 0.000 61.005 0.070 61.075 ;
    END
  END w_mask_in[213]
  PIN w_mask_in[214]
    DIRECTION INPUT ;
    USE SIGNAL ;
    SHAPE ABUTMENT ;
    PORT
      LAYER metal3 ;
      RECT 0.000 61.285 0.070 61.355 ;
    END
  END w_mask_in[214]
  PIN w_mask_in[215]
    DIRECTION INPUT ;
    USE SIGNAL ;
    SHAPE ABUTMENT ;
    PORT
      LAYER metal3 ;
      RECT 0.000 61.565 0.070 61.635 ;
    END
  END w_mask_in[215]
  PIN w_mask_in[216]
    DIRECTION INPUT ;
    USE SIGNAL ;
    SHAPE ABUTMENT ;
    PORT
      LAYER metal3 ;
      RECT 0.000 61.845 0.070 61.915 ;
    END
  END w_mask_in[216]
  PIN w_mask_in[217]
    DIRECTION INPUT ;
    USE SIGNAL ;
    SHAPE ABUTMENT ;
    PORT
      LAYER metal3 ;
      RECT 0.000 62.125 0.070 62.195 ;
    END
  END w_mask_in[217]
  PIN w_mask_in[218]
    DIRECTION INPUT ;
    USE SIGNAL ;
    SHAPE ABUTMENT ;
    PORT
      LAYER metal3 ;
      RECT 0.000 62.405 0.070 62.475 ;
    END
  END w_mask_in[218]
  PIN w_mask_in[219]
    DIRECTION INPUT ;
    USE SIGNAL ;
    SHAPE ABUTMENT ;
    PORT
      LAYER metal3 ;
      RECT 0.000 62.685 0.070 62.755 ;
    END
  END w_mask_in[219]
  PIN w_mask_in[220]
    DIRECTION INPUT ;
    USE SIGNAL ;
    SHAPE ABUTMENT ;
    PORT
      LAYER metal3 ;
      RECT 0.000 62.965 0.070 63.035 ;
    END
  END w_mask_in[220]
  PIN w_mask_in[221]
    DIRECTION INPUT ;
    USE SIGNAL ;
    SHAPE ABUTMENT ;
    PORT
      LAYER metal3 ;
      RECT 0.000 63.245 0.070 63.315 ;
    END
  END w_mask_in[221]
  PIN w_mask_in[222]
    DIRECTION INPUT ;
    USE SIGNAL ;
    SHAPE ABUTMENT ;
    PORT
      LAYER metal3 ;
      RECT 0.000 63.525 0.070 63.595 ;
    END
  END w_mask_in[222]
  PIN w_mask_in[223]
    DIRECTION INPUT ;
    USE SIGNAL ;
    SHAPE ABUTMENT ;
    PORT
      LAYER metal3 ;
      RECT 0.000 63.805 0.070 63.875 ;
    END
  END w_mask_in[223]
  PIN w_mask_in[224]
    DIRECTION INPUT ;
    USE SIGNAL ;
    SHAPE ABUTMENT ;
    PORT
      LAYER metal3 ;
      RECT 0.000 64.085 0.070 64.155 ;
    END
  END w_mask_in[224]
  PIN w_mask_in[225]
    DIRECTION INPUT ;
    USE SIGNAL ;
    SHAPE ABUTMENT ;
    PORT
      LAYER metal3 ;
      RECT 0.000 64.365 0.070 64.435 ;
    END
  END w_mask_in[225]
  PIN w_mask_in[226]
    DIRECTION INPUT ;
    USE SIGNAL ;
    SHAPE ABUTMENT ;
    PORT
      LAYER metal3 ;
      RECT 0.000 64.645 0.070 64.715 ;
    END
  END w_mask_in[226]
  PIN w_mask_in[227]
    DIRECTION INPUT ;
    USE SIGNAL ;
    SHAPE ABUTMENT ;
    PORT
      LAYER metal3 ;
      RECT 0.000 64.925 0.070 64.995 ;
    END
  END w_mask_in[227]
  PIN w_mask_in[228]
    DIRECTION INPUT ;
    USE SIGNAL ;
    SHAPE ABUTMENT ;
    PORT
      LAYER metal3 ;
      RECT 0.000 65.205 0.070 65.275 ;
    END
  END w_mask_in[228]
  PIN w_mask_in[229]
    DIRECTION INPUT ;
    USE SIGNAL ;
    SHAPE ABUTMENT ;
    PORT
      LAYER metal3 ;
      RECT 0.000 65.485 0.070 65.555 ;
    END
  END w_mask_in[229]
  PIN w_mask_in[230]
    DIRECTION INPUT ;
    USE SIGNAL ;
    SHAPE ABUTMENT ;
    PORT
      LAYER metal3 ;
      RECT 0.000 65.765 0.070 65.835 ;
    END
  END w_mask_in[230]
  PIN w_mask_in[231]
    DIRECTION INPUT ;
    USE SIGNAL ;
    SHAPE ABUTMENT ;
    PORT
      LAYER metal3 ;
      RECT 0.000 66.045 0.070 66.115 ;
    END
  END w_mask_in[231]
  PIN w_mask_in[232]
    DIRECTION INPUT ;
    USE SIGNAL ;
    SHAPE ABUTMENT ;
    PORT
      LAYER metal3 ;
      RECT 0.000 66.325 0.070 66.395 ;
    END
  END w_mask_in[232]
  PIN w_mask_in[233]
    DIRECTION INPUT ;
    USE SIGNAL ;
    SHAPE ABUTMENT ;
    PORT
      LAYER metal3 ;
      RECT 0.000 66.605 0.070 66.675 ;
    END
  END w_mask_in[233]
  PIN w_mask_in[234]
    DIRECTION INPUT ;
    USE SIGNAL ;
    SHAPE ABUTMENT ;
    PORT
      LAYER metal3 ;
      RECT 0.000 66.885 0.070 66.955 ;
    END
  END w_mask_in[234]
  PIN w_mask_in[235]
    DIRECTION INPUT ;
    USE SIGNAL ;
    SHAPE ABUTMENT ;
    PORT
      LAYER metal3 ;
      RECT 0.000 67.165 0.070 67.235 ;
    END
  END w_mask_in[235]
  PIN w_mask_in[236]
    DIRECTION INPUT ;
    USE SIGNAL ;
    SHAPE ABUTMENT ;
    PORT
      LAYER metal3 ;
      RECT 0.000 67.445 0.070 67.515 ;
    END
  END w_mask_in[236]
  PIN w_mask_in[237]
    DIRECTION INPUT ;
    USE SIGNAL ;
    SHAPE ABUTMENT ;
    PORT
      LAYER metal3 ;
      RECT 0.000 67.725 0.070 67.795 ;
    END
  END w_mask_in[237]
  PIN w_mask_in[238]
    DIRECTION INPUT ;
    USE SIGNAL ;
    SHAPE ABUTMENT ;
    PORT
      LAYER metal3 ;
      RECT 0.000 68.005 0.070 68.075 ;
    END
  END w_mask_in[238]
  PIN w_mask_in[239]
    DIRECTION INPUT ;
    USE SIGNAL ;
    SHAPE ABUTMENT ;
    PORT
      LAYER metal3 ;
      RECT 0.000 68.285 0.070 68.355 ;
    END
  END w_mask_in[239]
  PIN w_mask_in[240]
    DIRECTION INPUT ;
    USE SIGNAL ;
    SHAPE ABUTMENT ;
    PORT
      LAYER metal3 ;
      RECT 0.000 68.565 0.070 68.635 ;
    END
  END w_mask_in[240]
  PIN w_mask_in[241]
    DIRECTION INPUT ;
    USE SIGNAL ;
    SHAPE ABUTMENT ;
    PORT
      LAYER metal3 ;
      RECT 0.000 68.845 0.070 68.915 ;
    END
  END w_mask_in[241]
  PIN w_mask_in[242]
    DIRECTION INPUT ;
    USE SIGNAL ;
    SHAPE ABUTMENT ;
    PORT
      LAYER metal3 ;
      RECT 0.000 69.125 0.070 69.195 ;
    END
  END w_mask_in[242]
  PIN w_mask_in[243]
    DIRECTION INPUT ;
    USE SIGNAL ;
    SHAPE ABUTMENT ;
    PORT
      LAYER metal3 ;
      RECT 0.000 69.405 0.070 69.475 ;
    END
  END w_mask_in[243]
  PIN w_mask_in[244]
    DIRECTION INPUT ;
    USE SIGNAL ;
    SHAPE ABUTMENT ;
    PORT
      LAYER metal3 ;
      RECT 0.000 69.685 0.070 69.755 ;
    END
  END w_mask_in[244]
  PIN w_mask_in[245]
    DIRECTION INPUT ;
    USE SIGNAL ;
    SHAPE ABUTMENT ;
    PORT
      LAYER metal3 ;
      RECT 0.000 69.965 0.070 70.035 ;
    END
  END w_mask_in[245]
  PIN w_mask_in[246]
    DIRECTION INPUT ;
    USE SIGNAL ;
    SHAPE ABUTMENT ;
    PORT
      LAYER metal3 ;
      RECT 0.000 70.245 0.070 70.315 ;
    END
  END w_mask_in[246]
  PIN w_mask_in[247]
    DIRECTION INPUT ;
    USE SIGNAL ;
    SHAPE ABUTMENT ;
    PORT
      LAYER metal3 ;
      RECT 0.000 70.525 0.070 70.595 ;
    END
  END w_mask_in[247]
  PIN w_mask_in[248]
    DIRECTION INPUT ;
    USE SIGNAL ;
    SHAPE ABUTMENT ;
    PORT
      LAYER metal3 ;
      RECT 0.000 70.805 0.070 70.875 ;
    END
  END w_mask_in[248]
  PIN w_mask_in[249]
    DIRECTION INPUT ;
    USE SIGNAL ;
    SHAPE ABUTMENT ;
    PORT
      LAYER metal3 ;
      RECT 0.000 71.085 0.070 71.155 ;
    END
  END w_mask_in[249]
  PIN w_mask_in[250]
    DIRECTION INPUT ;
    USE SIGNAL ;
    SHAPE ABUTMENT ;
    PORT
      LAYER metal3 ;
      RECT 0.000 71.365 0.070 71.435 ;
    END
  END w_mask_in[250]
  PIN w_mask_in[251]
    DIRECTION INPUT ;
    USE SIGNAL ;
    SHAPE ABUTMENT ;
    PORT
      LAYER metal3 ;
      RECT 0.000 71.645 0.070 71.715 ;
    END
  END w_mask_in[251]
  PIN w_mask_in[252]
    DIRECTION INPUT ;
    USE SIGNAL ;
    SHAPE ABUTMENT ;
    PORT
      LAYER metal3 ;
      RECT 0.000 71.925 0.070 71.995 ;
    END
  END w_mask_in[252]
  PIN w_mask_in[253]
    DIRECTION INPUT ;
    USE SIGNAL ;
    SHAPE ABUTMENT ;
    PORT
      LAYER metal3 ;
      RECT 0.000 72.205 0.070 72.275 ;
    END
  END w_mask_in[253]
  PIN w_mask_in[254]
    DIRECTION INPUT ;
    USE SIGNAL ;
    SHAPE ABUTMENT ;
    PORT
      LAYER metal3 ;
      RECT 0.000 72.485 0.070 72.555 ;
    END
  END w_mask_in[254]
  PIN w_mask_in[255]
    DIRECTION INPUT ;
    USE SIGNAL ;
    SHAPE ABUTMENT ;
    PORT
      LAYER metal3 ;
      RECT 0.000 72.765 0.070 72.835 ;
    END
  END w_mask_in[255]
  PIN w_mask_in[256]
    DIRECTION INPUT ;
    USE SIGNAL ;
    SHAPE ABUTMENT ;
    PORT
      LAYER metal3 ;
      RECT 0.000 73.045 0.070 73.115 ;
    END
  END w_mask_in[256]
  PIN w_mask_in[257]
    DIRECTION INPUT ;
    USE SIGNAL ;
    SHAPE ABUTMENT ;
    PORT
      LAYER metal3 ;
      RECT 0.000 73.325 0.070 73.395 ;
    END
  END w_mask_in[257]
  PIN w_mask_in[258]
    DIRECTION INPUT ;
    USE SIGNAL ;
    SHAPE ABUTMENT ;
    PORT
      LAYER metal3 ;
      RECT 0.000 73.605 0.070 73.675 ;
    END
  END w_mask_in[258]
  PIN w_mask_in[259]
    DIRECTION INPUT ;
    USE SIGNAL ;
    SHAPE ABUTMENT ;
    PORT
      LAYER metal3 ;
      RECT 0.000 73.885 0.070 73.955 ;
    END
  END w_mask_in[259]
  PIN w_mask_in[260]
    DIRECTION INPUT ;
    USE SIGNAL ;
    SHAPE ABUTMENT ;
    PORT
      LAYER metal3 ;
      RECT 0.000 74.165 0.070 74.235 ;
    END
  END w_mask_in[260]
  PIN w_mask_in[261]
    DIRECTION INPUT ;
    USE SIGNAL ;
    SHAPE ABUTMENT ;
    PORT
      LAYER metal3 ;
      RECT 0.000 74.445 0.070 74.515 ;
    END
  END w_mask_in[261]
  PIN w_mask_in[262]
    DIRECTION INPUT ;
    USE SIGNAL ;
    SHAPE ABUTMENT ;
    PORT
      LAYER metal3 ;
      RECT 0.000 74.725 0.070 74.795 ;
    END
  END w_mask_in[262]
  PIN w_mask_in[263]
    DIRECTION INPUT ;
    USE SIGNAL ;
    SHAPE ABUTMENT ;
    PORT
      LAYER metal3 ;
      RECT 0.000 75.005 0.070 75.075 ;
    END
  END w_mask_in[263]
  PIN w_mask_in[264]
    DIRECTION INPUT ;
    USE SIGNAL ;
    SHAPE ABUTMENT ;
    PORT
      LAYER metal3 ;
      RECT 0.000 75.285 0.070 75.355 ;
    END
  END w_mask_in[264]
  PIN w_mask_in[265]
    DIRECTION INPUT ;
    USE SIGNAL ;
    SHAPE ABUTMENT ;
    PORT
      LAYER metal3 ;
      RECT 0.000 75.565 0.070 75.635 ;
    END
  END w_mask_in[265]
  PIN w_mask_in[266]
    DIRECTION INPUT ;
    USE SIGNAL ;
    SHAPE ABUTMENT ;
    PORT
      LAYER metal3 ;
      RECT 0.000 75.845 0.070 75.915 ;
    END
  END w_mask_in[266]
  PIN w_mask_in[267]
    DIRECTION INPUT ;
    USE SIGNAL ;
    SHAPE ABUTMENT ;
    PORT
      LAYER metal3 ;
      RECT 0.000 76.125 0.070 76.195 ;
    END
  END w_mask_in[267]
  PIN w_mask_in[268]
    DIRECTION INPUT ;
    USE SIGNAL ;
    SHAPE ABUTMENT ;
    PORT
      LAYER metal3 ;
      RECT 0.000 76.405 0.070 76.475 ;
    END
  END w_mask_in[268]
  PIN w_mask_in[269]
    DIRECTION INPUT ;
    USE SIGNAL ;
    SHAPE ABUTMENT ;
    PORT
      LAYER metal3 ;
      RECT 0.000 76.685 0.070 76.755 ;
    END
  END w_mask_in[269]
  PIN w_mask_in[270]
    DIRECTION INPUT ;
    USE SIGNAL ;
    SHAPE ABUTMENT ;
    PORT
      LAYER metal3 ;
      RECT 0.000 76.965 0.070 77.035 ;
    END
  END w_mask_in[270]
  PIN w_mask_in[271]
    DIRECTION INPUT ;
    USE SIGNAL ;
    SHAPE ABUTMENT ;
    PORT
      LAYER metal3 ;
      RECT 0.000 77.245 0.070 77.315 ;
    END
  END w_mask_in[271]
  PIN w_mask_in[272]
    DIRECTION INPUT ;
    USE SIGNAL ;
    SHAPE ABUTMENT ;
    PORT
      LAYER metal3 ;
      RECT 0.000 77.525 0.070 77.595 ;
    END
  END w_mask_in[272]
  PIN w_mask_in[273]
    DIRECTION INPUT ;
    USE SIGNAL ;
    SHAPE ABUTMENT ;
    PORT
      LAYER metal3 ;
      RECT 0.000 77.805 0.070 77.875 ;
    END
  END w_mask_in[273]
  PIN w_mask_in[274]
    DIRECTION INPUT ;
    USE SIGNAL ;
    SHAPE ABUTMENT ;
    PORT
      LAYER metal3 ;
      RECT 0.000 78.085 0.070 78.155 ;
    END
  END w_mask_in[274]
  PIN w_mask_in[275]
    DIRECTION INPUT ;
    USE SIGNAL ;
    SHAPE ABUTMENT ;
    PORT
      LAYER metal3 ;
      RECT 0.000 78.365 0.070 78.435 ;
    END
  END w_mask_in[275]
  PIN w_mask_in[276]
    DIRECTION INPUT ;
    USE SIGNAL ;
    SHAPE ABUTMENT ;
    PORT
      LAYER metal3 ;
      RECT 0.000 78.645 0.070 78.715 ;
    END
  END w_mask_in[276]
  PIN w_mask_in[277]
    DIRECTION INPUT ;
    USE SIGNAL ;
    SHAPE ABUTMENT ;
    PORT
      LAYER metal3 ;
      RECT 0.000 78.925 0.070 78.995 ;
    END
  END w_mask_in[277]
  PIN w_mask_in[278]
    DIRECTION INPUT ;
    USE SIGNAL ;
    SHAPE ABUTMENT ;
    PORT
      LAYER metal3 ;
      RECT 0.000 79.205 0.070 79.275 ;
    END
  END w_mask_in[278]
  PIN w_mask_in[279]
    DIRECTION INPUT ;
    USE SIGNAL ;
    SHAPE ABUTMENT ;
    PORT
      LAYER metal3 ;
      RECT 0.000 79.485 0.070 79.555 ;
    END
  END w_mask_in[279]
  PIN w_mask_in[280]
    DIRECTION INPUT ;
    USE SIGNAL ;
    SHAPE ABUTMENT ;
    PORT
      LAYER metal3 ;
      RECT 0.000 79.765 0.070 79.835 ;
    END
  END w_mask_in[280]
  PIN w_mask_in[281]
    DIRECTION INPUT ;
    USE SIGNAL ;
    SHAPE ABUTMENT ;
    PORT
      LAYER metal3 ;
      RECT 0.000 80.045 0.070 80.115 ;
    END
  END w_mask_in[281]
  PIN w_mask_in[282]
    DIRECTION INPUT ;
    USE SIGNAL ;
    SHAPE ABUTMENT ;
    PORT
      LAYER metal3 ;
      RECT 0.000 80.325 0.070 80.395 ;
    END
  END w_mask_in[282]
  PIN w_mask_in[283]
    DIRECTION INPUT ;
    USE SIGNAL ;
    SHAPE ABUTMENT ;
    PORT
      LAYER metal3 ;
      RECT 0.000 80.605 0.070 80.675 ;
    END
  END w_mask_in[283]
  PIN w_mask_in[284]
    DIRECTION INPUT ;
    USE SIGNAL ;
    SHAPE ABUTMENT ;
    PORT
      LAYER metal3 ;
      RECT 0.000 80.885 0.070 80.955 ;
    END
  END w_mask_in[284]
  PIN w_mask_in[285]
    DIRECTION INPUT ;
    USE SIGNAL ;
    SHAPE ABUTMENT ;
    PORT
      LAYER metal3 ;
      RECT 0.000 81.165 0.070 81.235 ;
    END
  END w_mask_in[285]
  PIN w_mask_in[286]
    DIRECTION INPUT ;
    USE SIGNAL ;
    SHAPE ABUTMENT ;
    PORT
      LAYER metal3 ;
      RECT 0.000 81.445 0.070 81.515 ;
    END
  END w_mask_in[286]
  PIN w_mask_in[287]
    DIRECTION INPUT ;
    USE SIGNAL ;
    SHAPE ABUTMENT ;
    PORT
      LAYER metal3 ;
      RECT 0.000 81.725 0.070 81.795 ;
    END
  END w_mask_in[287]
  PIN w_mask_in[288]
    DIRECTION INPUT ;
    USE SIGNAL ;
    SHAPE ABUTMENT ;
    PORT
      LAYER metal3 ;
      RECT 0.000 82.005 0.070 82.075 ;
    END
  END w_mask_in[288]
  PIN w_mask_in[289]
    DIRECTION INPUT ;
    USE SIGNAL ;
    SHAPE ABUTMENT ;
    PORT
      LAYER metal3 ;
      RECT 0.000 82.285 0.070 82.355 ;
    END
  END w_mask_in[289]
  PIN w_mask_in[290]
    DIRECTION INPUT ;
    USE SIGNAL ;
    SHAPE ABUTMENT ;
    PORT
      LAYER metal3 ;
      RECT 0.000 82.565 0.070 82.635 ;
    END
  END w_mask_in[290]
  PIN w_mask_in[291]
    DIRECTION INPUT ;
    USE SIGNAL ;
    SHAPE ABUTMENT ;
    PORT
      LAYER metal3 ;
      RECT 0.000 82.845 0.070 82.915 ;
    END
  END w_mask_in[291]
  PIN w_mask_in[292]
    DIRECTION INPUT ;
    USE SIGNAL ;
    SHAPE ABUTMENT ;
    PORT
      LAYER metal3 ;
      RECT 0.000 83.125 0.070 83.195 ;
    END
  END w_mask_in[292]
  PIN w_mask_in[293]
    DIRECTION INPUT ;
    USE SIGNAL ;
    SHAPE ABUTMENT ;
    PORT
      LAYER metal3 ;
      RECT 0.000 83.405 0.070 83.475 ;
    END
  END w_mask_in[293]
  PIN w_mask_in[294]
    DIRECTION INPUT ;
    USE SIGNAL ;
    SHAPE ABUTMENT ;
    PORT
      LAYER metal3 ;
      RECT 0.000 83.685 0.070 83.755 ;
    END
  END w_mask_in[294]
  PIN w_mask_in[295]
    DIRECTION INPUT ;
    USE SIGNAL ;
    SHAPE ABUTMENT ;
    PORT
      LAYER metal3 ;
      RECT 0.000 83.965 0.070 84.035 ;
    END
  END w_mask_in[295]
  PIN w_mask_in[296]
    DIRECTION INPUT ;
    USE SIGNAL ;
    SHAPE ABUTMENT ;
    PORT
      LAYER metal3 ;
      RECT 0.000 84.245 0.070 84.315 ;
    END
  END w_mask_in[296]
  PIN w_mask_in[297]
    DIRECTION INPUT ;
    USE SIGNAL ;
    SHAPE ABUTMENT ;
    PORT
      LAYER metal3 ;
      RECT 0.000 84.525 0.070 84.595 ;
    END
  END w_mask_in[297]
  PIN w_mask_in[298]
    DIRECTION INPUT ;
    USE SIGNAL ;
    SHAPE ABUTMENT ;
    PORT
      LAYER metal3 ;
      RECT 0.000 84.805 0.070 84.875 ;
    END
  END w_mask_in[298]
  PIN w_mask_in[299]
    DIRECTION INPUT ;
    USE SIGNAL ;
    SHAPE ABUTMENT ;
    PORT
      LAYER metal3 ;
      RECT 0.000 85.085 0.070 85.155 ;
    END
  END w_mask_in[299]
  PIN w_mask_in[300]
    DIRECTION INPUT ;
    USE SIGNAL ;
    SHAPE ABUTMENT ;
    PORT
      LAYER metal3 ;
      RECT 0.000 85.365 0.070 85.435 ;
    END
  END w_mask_in[300]
  PIN w_mask_in[301]
    DIRECTION INPUT ;
    USE SIGNAL ;
    SHAPE ABUTMENT ;
    PORT
      LAYER metal3 ;
      RECT 0.000 85.645 0.070 85.715 ;
    END
  END w_mask_in[301]
  PIN w_mask_in[302]
    DIRECTION INPUT ;
    USE SIGNAL ;
    SHAPE ABUTMENT ;
    PORT
      LAYER metal3 ;
      RECT 0.000 85.925 0.070 85.995 ;
    END
  END w_mask_in[302]
  PIN w_mask_in[303]
    DIRECTION INPUT ;
    USE SIGNAL ;
    SHAPE ABUTMENT ;
    PORT
      LAYER metal3 ;
      RECT 0.000 86.205 0.070 86.275 ;
    END
  END w_mask_in[303]
  PIN w_mask_in[304]
    DIRECTION INPUT ;
    USE SIGNAL ;
    SHAPE ABUTMENT ;
    PORT
      LAYER metal3 ;
      RECT 0.000 86.485 0.070 86.555 ;
    END
  END w_mask_in[304]
  PIN w_mask_in[305]
    DIRECTION INPUT ;
    USE SIGNAL ;
    SHAPE ABUTMENT ;
    PORT
      LAYER metal3 ;
      RECT 0.000 86.765 0.070 86.835 ;
    END
  END w_mask_in[305]
  PIN w_mask_in[306]
    DIRECTION INPUT ;
    USE SIGNAL ;
    SHAPE ABUTMENT ;
    PORT
      LAYER metal3 ;
      RECT 0.000 87.045 0.070 87.115 ;
    END
  END w_mask_in[306]
  PIN w_mask_in[307]
    DIRECTION INPUT ;
    USE SIGNAL ;
    SHAPE ABUTMENT ;
    PORT
      LAYER metal3 ;
      RECT 0.000 87.325 0.070 87.395 ;
    END
  END w_mask_in[307]
  PIN w_mask_in[308]
    DIRECTION INPUT ;
    USE SIGNAL ;
    SHAPE ABUTMENT ;
    PORT
      LAYER metal3 ;
      RECT 0.000 87.605 0.070 87.675 ;
    END
  END w_mask_in[308]
  PIN w_mask_in[309]
    DIRECTION INPUT ;
    USE SIGNAL ;
    SHAPE ABUTMENT ;
    PORT
      LAYER metal3 ;
      RECT 0.000 87.885 0.070 87.955 ;
    END
  END w_mask_in[309]
  PIN w_mask_in[310]
    DIRECTION INPUT ;
    USE SIGNAL ;
    SHAPE ABUTMENT ;
    PORT
      LAYER metal3 ;
      RECT 0.000 88.165 0.070 88.235 ;
    END
  END w_mask_in[310]
  PIN w_mask_in[311]
    DIRECTION INPUT ;
    USE SIGNAL ;
    SHAPE ABUTMENT ;
    PORT
      LAYER metal3 ;
      RECT 0.000 88.445 0.070 88.515 ;
    END
  END w_mask_in[311]
  PIN w_mask_in[312]
    DIRECTION INPUT ;
    USE SIGNAL ;
    SHAPE ABUTMENT ;
    PORT
      LAYER metal3 ;
      RECT 0.000 88.725 0.070 88.795 ;
    END
  END w_mask_in[312]
  PIN w_mask_in[313]
    DIRECTION INPUT ;
    USE SIGNAL ;
    SHAPE ABUTMENT ;
    PORT
      LAYER metal3 ;
      RECT 0.000 89.005 0.070 89.075 ;
    END
  END w_mask_in[313]
  PIN w_mask_in[314]
    DIRECTION INPUT ;
    USE SIGNAL ;
    SHAPE ABUTMENT ;
    PORT
      LAYER metal3 ;
      RECT 0.000 89.285 0.070 89.355 ;
    END
  END w_mask_in[314]
  PIN w_mask_in[315]
    DIRECTION INPUT ;
    USE SIGNAL ;
    SHAPE ABUTMENT ;
    PORT
      LAYER metal3 ;
      RECT 0.000 89.565 0.070 89.635 ;
    END
  END w_mask_in[315]
  PIN w_mask_in[316]
    DIRECTION INPUT ;
    USE SIGNAL ;
    SHAPE ABUTMENT ;
    PORT
      LAYER metal3 ;
      RECT 0.000 89.845 0.070 89.915 ;
    END
  END w_mask_in[316]
  PIN w_mask_in[317]
    DIRECTION INPUT ;
    USE SIGNAL ;
    SHAPE ABUTMENT ;
    PORT
      LAYER metal3 ;
      RECT 0.000 90.125 0.070 90.195 ;
    END
  END w_mask_in[317]
  PIN w_mask_in[318]
    DIRECTION INPUT ;
    USE SIGNAL ;
    SHAPE ABUTMENT ;
    PORT
      LAYER metal3 ;
      RECT 0.000 90.405 0.070 90.475 ;
    END
  END w_mask_in[318]
  PIN w_mask_in[319]
    DIRECTION INPUT ;
    USE SIGNAL ;
    SHAPE ABUTMENT ;
    PORT
      LAYER metal3 ;
      RECT 0.000 90.685 0.070 90.755 ;
    END
  END w_mask_in[319]
  PIN w_mask_in[320]
    DIRECTION INPUT ;
    USE SIGNAL ;
    SHAPE ABUTMENT ;
    PORT
      LAYER metal3 ;
      RECT 0.000 90.965 0.070 91.035 ;
    END
  END w_mask_in[320]
  PIN w_mask_in[321]
    DIRECTION INPUT ;
    USE SIGNAL ;
    SHAPE ABUTMENT ;
    PORT
      LAYER metal3 ;
      RECT 0.000 91.245 0.070 91.315 ;
    END
  END w_mask_in[321]
  PIN w_mask_in[322]
    DIRECTION INPUT ;
    USE SIGNAL ;
    SHAPE ABUTMENT ;
    PORT
      LAYER metal3 ;
      RECT 0.000 91.525 0.070 91.595 ;
    END
  END w_mask_in[322]
  PIN w_mask_in[323]
    DIRECTION INPUT ;
    USE SIGNAL ;
    SHAPE ABUTMENT ;
    PORT
      LAYER metal3 ;
      RECT 0.000 91.805 0.070 91.875 ;
    END
  END w_mask_in[323]
  PIN w_mask_in[324]
    DIRECTION INPUT ;
    USE SIGNAL ;
    SHAPE ABUTMENT ;
    PORT
      LAYER metal3 ;
      RECT 0.000 92.085 0.070 92.155 ;
    END
  END w_mask_in[324]
  PIN w_mask_in[325]
    DIRECTION INPUT ;
    USE SIGNAL ;
    SHAPE ABUTMENT ;
    PORT
      LAYER metal3 ;
      RECT 0.000 92.365 0.070 92.435 ;
    END
  END w_mask_in[325]
  PIN w_mask_in[326]
    DIRECTION INPUT ;
    USE SIGNAL ;
    SHAPE ABUTMENT ;
    PORT
      LAYER metal3 ;
      RECT 0.000 92.645 0.070 92.715 ;
    END
  END w_mask_in[326]
  PIN w_mask_in[327]
    DIRECTION INPUT ;
    USE SIGNAL ;
    SHAPE ABUTMENT ;
    PORT
      LAYER metal3 ;
      RECT 0.000 92.925 0.070 92.995 ;
    END
  END w_mask_in[327]
  PIN w_mask_in[328]
    DIRECTION INPUT ;
    USE SIGNAL ;
    SHAPE ABUTMENT ;
    PORT
      LAYER metal3 ;
      RECT 0.000 93.205 0.070 93.275 ;
    END
  END w_mask_in[328]
  PIN w_mask_in[329]
    DIRECTION INPUT ;
    USE SIGNAL ;
    SHAPE ABUTMENT ;
    PORT
      LAYER metal3 ;
      RECT 0.000 93.485 0.070 93.555 ;
    END
  END w_mask_in[329]
  PIN w_mask_in[330]
    DIRECTION INPUT ;
    USE SIGNAL ;
    SHAPE ABUTMENT ;
    PORT
      LAYER metal3 ;
      RECT 0.000 93.765 0.070 93.835 ;
    END
  END w_mask_in[330]
  PIN w_mask_in[331]
    DIRECTION INPUT ;
    USE SIGNAL ;
    SHAPE ABUTMENT ;
    PORT
      LAYER metal3 ;
      RECT 0.000 94.045 0.070 94.115 ;
    END
  END w_mask_in[331]
  PIN w_mask_in[332]
    DIRECTION INPUT ;
    USE SIGNAL ;
    SHAPE ABUTMENT ;
    PORT
      LAYER metal3 ;
      RECT 0.000 94.325 0.070 94.395 ;
    END
  END w_mask_in[332]
  PIN w_mask_in[333]
    DIRECTION INPUT ;
    USE SIGNAL ;
    SHAPE ABUTMENT ;
    PORT
      LAYER metal3 ;
      RECT 0.000 94.605 0.070 94.675 ;
    END
  END w_mask_in[333]
  PIN w_mask_in[334]
    DIRECTION INPUT ;
    USE SIGNAL ;
    SHAPE ABUTMENT ;
    PORT
      LAYER metal3 ;
      RECT 0.000 94.885 0.070 94.955 ;
    END
  END w_mask_in[334]
  PIN w_mask_in[335]
    DIRECTION INPUT ;
    USE SIGNAL ;
    SHAPE ABUTMENT ;
    PORT
      LAYER metal3 ;
      RECT 0.000 95.165 0.070 95.235 ;
    END
  END w_mask_in[335]
  PIN w_mask_in[336]
    DIRECTION INPUT ;
    USE SIGNAL ;
    SHAPE ABUTMENT ;
    PORT
      LAYER metal3 ;
      RECT 0.000 95.445 0.070 95.515 ;
    END
  END w_mask_in[336]
  PIN w_mask_in[337]
    DIRECTION INPUT ;
    USE SIGNAL ;
    SHAPE ABUTMENT ;
    PORT
      LAYER metal3 ;
      RECT 0.000 95.725 0.070 95.795 ;
    END
  END w_mask_in[337]
  PIN w_mask_in[338]
    DIRECTION INPUT ;
    USE SIGNAL ;
    SHAPE ABUTMENT ;
    PORT
      LAYER metal3 ;
      RECT 0.000 96.005 0.070 96.075 ;
    END
  END w_mask_in[338]
  PIN w_mask_in[339]
    DIRECTION INPUT ;
    USE SIGNAL ;
    SHAPE ABUTMENT ;
    PORT
      LAYER metal3 ;
      RECT 0.000 96.285 0.070 96.355 ;
    END
  END w_mask_in[339]
  PIN w_mask_in[340]
    DIRECTION INPUT ;
    USE SIGNAL ;
    SHAPE ABUTMENT ;
    PORT
      LAYER metal3 ;
      RECT 0.000 96.565 0.070 96.635 ;
    END
  END w_mask_in[340]
  PIN w_mask_in[341]
    DIRECTION INPUT ;
    USE SIGNAL ;
    SHAPE ABUTMENT ;
    PORT
      LAYER metal3 ;
      RECT 0.000 96.845 0.070 96.915 ;
    END
  END w_mask_in[341]
  PIN w_mask_in[342]
    DIRECTION INPUT ;
    USE SIGNAL ;
    SHAPE ABUTMENT ;
    PORT
      LAYER metal3 ;
      RECT 0.000 97.125 0.070 97.195 ;
    END
  END w_mask_in[342]
  PIN w_mask_in[343]
    DIRECTION INPUT ;
    USE SIGNAL ;
    SHAPE ABUTMENT ;
    PORT
      LAYER metal3 ;
      RECT 0.000 97.405 0.070 97.475 ;
    END
  END w_mask_in[343]
  PIN w_mask_in[344]
    DIRECTION INPUT ;
    USE SIGNAL ;
    SHAPE ABUTMENT ;
    PORT
      LAYER metal3 ;
      RECT 0.000 97.685 0.070 97.755 ;
    END
  END w_mask_in[344]
  PIN w_mask_in[345]
    DIRECTION INPUT ;
    USE SIGNAL ;
    SHAPE ABUTMENT ;
    PORT
      LAYER metal3 ;
      RECT 0.000 97.965 0.070 98.035 ;
    END
  END w_mask_in[345]
  PIN w_mask_in[346]
    DIRECTION INPUT ;
    USE SIGNAL ;
    SHAPE ABUTMENT ;
    PORT
      LAYER metal3 ;
      RECT 0.000 98.245 0.070 98.315 ;
    END
  END w_mask_in[346]
  PIN w_mask_in[347]
    DIRECTION INPUT ;
    USE SIGNAL ;
    SHAPE ABUTMENT ;
    PORT
      LAYER metal3 ;
      RECT 0.000 98.525 0.070 98.595 ;
    END
  END w_mask_in[347]
  PIN w_mask_in[348]
    DIRECTION INPUT ;
    USE SIGNAL ;
    SHAPE ABUTMENT ;
    PORT
      LAYER metal3 ;
      RECT 0.000 98.805 0.070 98.875 ;
    END
  END w_mask_in[348]
  PIN w_mask_in[349]
    DIRECTION INPUT ;
    USE SIGNAL ;
    SHAPE ABUTMENT ;
    PORT
      LAYER metal3 ;
      RECT 0.000 99.085 0.070 99.155 ;
    END
  END w_mask_in[349]
  PIN w_mask_in[350]
    DIRECTION INPUT ;
    USE SIGNAL ;
    SHAPE ABUTMENT ;
    PORT
      LAYER metal3 ;
      RECT 0.000 99.365 0.070 99.435 ;
    END
  END w_mask_in[350]
  PIN w_mask_in[351]
    DIRECTION INPUT ;
    USE SIGNAL ;
    SHAPE ABUTMENT ;
    PORT
      LAYER metal3 ;
      RECT 0.000 99.645 0.070 99.715 ;
    END
  END w_mask_in[351]
  PIN w_mask_in[352]
    DIRECTION INPUT ;
    USE SIGNAL ;
    SHAPE ABUTMENT ;
    PORT
      LAYER metal3 ;
      RECT 0.000 99.925 0.070 99.995 ;
    END
  END w_mask_in[352]
  PIN w_mask_in[353]
    DIRECTION INPUT ;
    USE SIGNAL ;
    SHAPE ABUTMENT ;
    PORT
      LAYER metal3 ;
      RECT 0.000 100.205 0.070 100.275 ;
    END
  END w_mask_in[353]
  PIN w_mask_in[354]
    DIRECTION INPUT ;
    USE SIGNAL ;
    SHAPE ABUTMENT ;
    PORT
      LAYER metal3 ;
      RECT 0.000 100.485 0.070 100.555 ;
    END
  END w_mask_in[354]
  PIN w_mask_in[355]
    DIRECTION INPUT ;
    USE SIGNAL ;
    SHAPE ABUTMENT ;
    PORT
      LAYER metal3 ;
      RECT 0.000 100.765 0.070 100.835 ;
    END
  END w_mask_in[355]
  PIN w_mask_in[356]
    DIRECTION INPUT ;
    USE SIGNAL ;
    SHAPE ABUTMENT ;
    PORT
      LAYER metal3 ;
      RECT 0.000 101.045 0.070 101.115 ;
    END
  END w_mask_in[356]
  PIN w_mask_in[357]
    DIRECTION INPUT ;
    USE SIGNAL ;
    SHAPE ABUTMENT ;
    PORT
      LAYER metal3 ;
      RECT 0.000 101.325 0.070 101.395 ;
    END
  END w_mask_in[357]
  PIN w_mask_in[358]
    DIRECTION INPUT ;
    USE SIGNAL ;
    SHAPE ABUTMENT ;
    PORT
      LAYER metal3 ;
      RECT 0.000 101.605 0.070 101.675 ;
    END
  END w_mask_in[358]
  PIN w_mask_in[359]
    DIRECTION INPUT ;
    USE SIGNAL ;
    SHAPE ABUTMENT ;
    PORT
      LAYER metal3 ;
      RECT 0.000 101.885 0.070 101.955 ;
    END
  END w_mask_in[359]
  PIN w_mask_in[360]
    DIRECTION INPUT ;
    USE SIGNAL ;
    SHAPE ABUTMENT ;
    PORT
      LAYER metal3 ;
      RECT 0.000 102.165 0.070 102.235 ;
    END
  END w_mask_in[360]
  PIN w_mask_in[361]
    DIRECTION INPUT ;
    USE SIGNAL ;
    SHAPE ABUTMENT ;
    PORT
      LAYER metal3 ;
      RECT 0.000 102.445 0.070 102.515 ;
    END
  END w_mask_in[361]
  PIN w_mask_in[362]
    DIRECTION INPUT ;
    USE SIGNAL ;
    SHAPE ABUTMENT ;
    PORT
      LAYER metal3 ;
      RECT 0.000 102.725 0.070 102.795 ;
    END
  END w_mask_in[362]
  PIN w_mask_in[363]
    DIRECTION INPUT ;
    USE SIGNAL ;
    SHAPE ABUTMENT ;
    PORT
      LAYER metal3 ;
      RECT 0.000 103.005 0.070 103.075 ;
    END
  END w_mask_in[363]
  PIN w_mask_in[364]
    DIRECTION INPUT ;
    USE SIGNAL ;
    SHAPE ABUTMENT ;
    PORT
      LAYER metal3 ;
      RECT 0.000 103.285 0.070 103.355 ;
    END
  END w_mask_in[364]
  PIN w_mask_in[365]
    DIRECTION INPUT ;
    USE SIGNAL ;
    SHAPE ABUTMENT ;
    PORT
      LAYER metal3 ;
      RECT 0.000 103.565 0.070 103.635 ;
    END
  END w_mask_in[365]
  PIN w_mask_in[366]
    DIRECTION INPUT ;
    USE SIGNAL ;
    SHAPE ABUTMENT ;
    PORT
      LAYER metal3 ;
      RECT 0.000 103.845 0.070 103.915 ;
    END
  END w_mask_in[366]
  PIN w_mask_in[367]
    DIRECTION INPUT ;
    USE SIGNAL ;
    SHAPE ABUTMENT ;
    PORT
      LAYER metal3 ;
      RECT 0.000 104.125 0.070 104.195 ;
    END
  END w_mask_in[367]
  PIN w_mask_in[368]
    DIRECTION INPUT ;
    USE SIGNAL ;
    SHAPE ABUTMENT ;
    PORT
      LAYER metal3 ;
      RECT 0.000 104.405 0.070 104.475 ;
    END
  END w_mask_in[368]
  PIN w_mask_in[369]
    DIRECTION INPUT ;
    USE SIGNAL ;
    SHAPE ABUTMENT ;
    PORT
      LAYER metal3 ;
      RECT 0.000 104.685 0.070 104.755 ;
    END
  END w_mask_in[369]
  PIN w_mask_in[370]
    DIRECTION INPUT ;
    USE SIGNAL ;
    SHAPE ABUTMENT ;
    PORT
      LAYER metal3 ;
      RECT 0.000 104.965 0.070 105.035 ;
    END
  END w_mask_in[370]
  PIN w_mask_in[371]
    DIRECTION INPUT ;
    USE SIGNAL ;
    SHAPE ABUTMENT ;
    PORT
      LAYER metal3 ;
      RECT 0.000 105.245 0.070 105.315 ;
    END
  END w_mask_in[371]
  PIN w_mask_in[372]
    DIRECTION INPUT ;
    USE SIGNAL ;
    SHAPE ABUTMENT ;
    PORT
      LAYER metal3 ;
      RECT 0.000 105.525 0.070 105.595 ;
    END
  END w_mask_in[372]
  PIN w_mask_in[373]
    DIRECTION INPUT ;
    USE SIGNAL ;
    SHAPE ABUTMENT ;
    PORT
      LAYER metal3 ;
      RECT 0.000 105.805 0.070 105.875 ;
    END
  END w_mask_in[373]
  PIN w_mask_in[374]
    DIRECTION INPUT ;
    USE SIGNAL ;
    SHAPE ABUTMENT ;
    PORT
      LAYER metal3 ;
      RECT 0.000 106.085 0.070 106.155 ;
    END
  END w_mask_in[374]
  PIN w_mask_in[375]
    DIRECTION INPUT ;
    USE SIGNAL ;
    SHAPE ABUTMENT ;
    PORT
      LAYER metal3 ;
      RECT 0.000 106.365 0.070 106.435 ;
    END
  END w_mask_in[375]
  PIN w_mask_in[376]
    DIRECTION INPUT ;
    USE SIGNAL ;
    SHAPE ABUTMENT ;
    PORT
      LAYER metal3 ;
      RECT 0.000 106.645 0.070 106.715 ;
    END
  END w_mask_in[376]
  PIN w_mask_in[377]
    DIRECTION INPUT ;
    USE SIGNAL ;
    SHAPE ABUTMENT ;
    PORT
      LAYER metal3 ;
      RECT 0.000 106.925 0.070 106.995 ;
    END
  END w_mask_in[377]
  PIN w_mask_in[378]
    DIRECTION INPUT ;
    USE SIGNAL ;
    SHAPE ABUTMENT ;
    PORT
      LAYER metal3 ;
      RECT 0.000 107.205 0.070 107.275 ;
    END
  END w_mask_in[378]
  PIN w_mask_in[379]
    DIRECTION INPUT ;
    USE SIGNAL ;
    SHAPE ABUTMENT ;
    PORT
      LAYER metal3 ;
      RECT 0.000 107.485 0.070 107.555 ;
    END
  END w_mask_in[379]
  PIN w_mask_in[380]
    DIRECTION INPUT ;
    USE SIGNAL ;
    SHAPE ABUTMENT ;
    PORT
      LAYER metal3 ;
      RECT 0.000 107.765 0.070 107.835 ;
    END
  END w_mask_in[380]
  PIN w_mask_in[381]
    DIRECTION INPUT ;
    USE SIGNAL ;
    SHAPE ABUTMENT ;
    PORT
      LAYER metal3 ;
      RECT 0.000 108.045 0.070 108.115 ;
    END
  END w_mask_in[381]
  PIN w_mask_in[382]
    DIRECTION INPUT ;
    USE SIGNAL ;
    SHAPE ABUTMENT ;
    PORT
      LAYER metal3 ;
      RECT 0.000 108.325 0.070 108.395 ;
    END
  END w_mask_in[382]
  PIN w_mask_in[383]
    DIRECTION INPUT ;
    USE SIGNAL ;
    SHAPE ABUTMENT ;
    PORT
      LAYER metal3 ;
      RECT 0.000 108.605 0.070 108.675 ;
    END
  END w_mask_in[383]
  PIN w_mask_in[384]
    DIRECTION INPUT ;
    USE SIGNAL ;
    SHAPE ABUTMENT ;
    PORT
      LAYER metal3 ;
      RECT 0.000 108.885 0.070 108.955 ;
    END
  END w_mask_in[384]
  PIN w_mask_in[385]
    DIRECTION INPUT ;
    USE SIGNAL ;
    SHAPE ABUTMENT ;
    PORT
      LAYER metal3 ;
      RECT 0.000 109.165 0.070 109.235 ;
    END
  END w_mask_in[385]
  PIN w_mask_in[386]
    DIRECTION INPUT ;
    USE SIGNAL ;
    SHAPE ABUTMENT ;
    PORT
      LAYER metal3 ;
      RECT 0.000 109.445 0.070 109.515 ;
    END
  END w_mask_in[386]
  PIN w_mask_in[387]
    DIRECTION INPUT ;
    USE SIGNAL ;
    SHAPE ABUTMENT ;
    PORT
      LAYER metal3 ;
      RECT 0.000 109.725 0.070 109.795 ;
    END
  END w_mask_in[387]
  PIN w_mask_in[388]
    DIRECTION INPUT ;
    USE SIGNAL ;
    SHAPE ABUTMENT ;
    PORT
      LAYER metal3 ;
      RECT 0.000 110.005 0.070 110.075 ;
    END
  END w_mask_in[388]
  PIN w_mask_in[389]
    DIRECTION INPUT ;
    USE SIGNAL ;
    SHAPE ABUTMENT ;
    PORT
      LAYER metal3 ;
      RECT 0.000 110.285 0.070 110.355 ;
    END
  END w_mask_in[389]
  PIN w_mask_in[390]
    DIRECTION INPUT ;
    USE SIGNAL ;
    SHAPE ABUTMENT ;
    PORT
      LAYER metal3 ;
      RECT 0.000 110.565 0.070 110.635 ;
    END
  END w_mask_in[390]
  PIN w_mask_in[391]
    DIRECTION INPUT ;
    USE SIGNAL ;
    SHAPE ABUTMENT ;
    PORT
      LAYER metal3 ;
      RECT 0.000 110.845 0.070 110.915 ;
    END
  END w_mask_in[391]
  PIN w_mask_in[392]
    DIRECTION INPUT ;
    USE SIGNAL ;
    SHAPE ABUTMENT ;
    PORT
      LAYER metal3 ;
      RECT 0.000 111.125 0.070 111.195 ;
    END
  END w_mask_in[392]
  PIN w_mask_in[393]
    DIRECTION INPUT ;
    USE SIGNAL ;
    SHAPE ABUTMENT ;
    PORT
      LAYER metal3 ;
      RECT 0.000 111.405 0.070 111.475 ;
    END
  END w_mask_in[393]
  PIN w_mask_in[394]
    DIRECTION INPUT ;
    USE SIGNAL ;
    SHAPE ABUTMENT ;
    PORT
      LAYER metal3 ;
      RECT 0.000 111.685 0.070 111.755 ;
    END
  END w_mask_in[394]
  PIN w_mask_in[395]
    DIRECTION INPUT ;
    USE SIGNAL ;
    SHAPE ABUTMENT ;
    PORT
      LAYER metal3 ;
      RECT 0.000 111.965 0.070 112.035 ;
    END
  END w_mask_in[395]
  PIN w_mask_in[396]
    DIRECTION INPUT ;
    USE SIGNAL ;
    SHAPE ABUTMENT ;
    PORT
      LAYER metal3 ;
      RECT 0.000 112.245 0.070 112.315 ;
    END
  END w_mask_in[396]
  PIN w_mask_in[397]
    DIRECTION INPUT ;
    USE SIGNAL ;
    SHAPE ABUTMENT ;
    PORT
      LAYER metal3 ;
      RECT 0.000 112.525 0.070 112.595 ;
    END
  END w_mask_in[397]
  PIN w_mask_in[398]
    DIRECTION INPUT ;
    USE SIGNAL ;
    SHAPE ABUTMENT ;
    PORT
      LAYER metal3 ;
      RECT 0.000 112.805 0.070 112.875 ;
    END
  END w_mask_in[398]
  PIN w_mask_in[399]
    DIRECTION INPUT ;
    USE SIGNAL ;
    SHAPE ABUTMENT ;
    PORT
      LAYER metal3 ;
      RECT 0.000 113.085 0.070 113.155 ;
    END
  END w_mask_in[399]
  PIN w_mask_in[400]
    DIRECTION INPUT ;
    USE SIGNAL ;
    SHAPE ABUTMENT ;
    PORT
      LAYER metal3 ;
      RECT 0.000 113.365 0.070 113.435 ;
    END
  END w_mask_in[400]
  PIN w_mask_in[401]
    DIRECTION INPUT ;
    USE SIGNAL ;
    SHAPE ABUTMENT ;
    PORT
      LAYER metal3 ;
      RECT 0.000 113.645 0.070 113.715 ;
    END
  END w_mask_in[401]
  PIN w_mask_in[402]
    DIRECTION INPUT ;
    USE SIGNAL ;
    SHAPE ABUTMENT ;
    PORT
      LAYER metal3 ;
      RECT 0.000 113.925 0.070 113.995 ;
    END
  END w_mask_in[402]
  PIN w_mask_in[403]
    DIRECTION INPUT ;
    USE SIGNAL ;
    SHAPE ABUTMENT ;
    PORT
      LAYER metal3 ;
      RECT 0.000 114.205 0.070 114.275 ;
    END
  END w_mask_in[403]
  PIN w_mask_in[404]
    DIRECTION INPUT ;
    USE SIGNAL ;
    SHAPE ABUTMENT ;
    PORT
      LAYER metal3 ;
      RECT 0.000 114.485 0.070 114.555 ;
    END
  END w_mask_in[404]
  PIN w_mask_in[405]
    DIRECTION INPUT ;
    USE SIGNAL ;
    SHAPE ABUTMENT ;
    PORT
      LAYER metal3 ;
      RECT 0.000 114.765 0.070 114.835 ;
    END
  END w_mask_in[405]
  PIN w_mask_in[406]
    DIRECTION INPUT ;
    USE SIGNAL ;
    SHAPE ABUTMENT ;
    PORT
      LAYER metal3 ;
      RECT 0.000 115.045 0.070 115.115 ;
    END
  END w_mask_in[406]
  PIN w_mask_in[407]
    DIRECTION INPUT ;
    USE SIGNAL ;
    SHAPE ABUTMENT ;
    PORT
      LAYER metal3 ;
      RECT 0.000 115.325 0.070 115.395 ;
    END
  END w_mask_in[407]
  PIN w_mask_in[408]
    DIRECTION INPUT ;
    USE SIGNAL ;
    SHAPE ABUTMENT ;
    PORT
      LAYER metal3 ;
      RECT 0.000 115.605 0.070 115.675 ;
    END
  END w_mask_in[408]
  PIN w_mask_in[409]
    DIRECTION INPUT ;
    USE SIGNAL ;
    SHAPE ABUTMENT ;
    PORT
      LAYER metal3 ;
      RECT 0.000 115.885 0.070 115.955 ;
    END
  END w_mask_in[409]
  PIN w_mask_in[410]
    DIRECTION INPUT ;
    USE SIGNAL ;
    SHAPE ABUTMENT ;
    PORT
      LAYER metal3 ;
      RECT 0.000 116.165 0.070 116.235 ;
    END
  END w_mask_in[410]
  PIN w_mask_in[411]
    DIRECTION INPUT ;
    USE SIGNAL ;
    SHAPE ABUTMENT ;
    PORT
      LAYER metal3 ;
      RECT 0.000 116.445 0.070 116.515 ;
    END
  END w_mask_in[411]
  PIN w_mask_in[412]
    DIRECTION INPUT ;
    USE SIGNAL ;
    SHAPE ABUTMENT ;
    PORT
      LAYER metal3 ;
      RECT 0.000 116.725 0.070 116.795 ;
    END
  END w_mask_in[412]
  PIN w_mask_in[413]
    DIRECTION INPUT ;
    USE SIGNAL ;
    SHAPE ABUTMENT ;
    PORT
      LAYER metal3 ;
      RECT 0.000 117.005 0.070 117.075 ;
    END
  END w_mask_in[413]
  PIN w_mask_in[414]
    DIRECTION INPUT ;
    USE SIGNAL ;
    SHAPE ABUTMENT ;
    PORT
      LAYER metal3 ;
      RECT 0.000 117.285 0.070 117.355 ;
    END
  END w_mask_in[414]
  PIN w_mask_in[415]
    DIRECTION INPUT ;
    USE SIGNAL ;
    SHAPE ABUTMENT ;
    PORT
      LAYER metal3 ;
      RECT 0.000 117.565 0.070 117.635 ;
    END
  END w_mask_in[415]
  PIN w_mask_in[416]
    DIRECTION INPUT ;
    USE SIGNAL ;
    SHAPE ABUTMENT ;
    PORT
      LAYER metal3 ;
      RECT 0.000 117.845 0.070 117.915 ;
    END
  END w_mask_in[416]
  PIN w_mask_in[417]
    DIRECTION INPUT ;
    USE SIGNAL ;
    SHAPE ABUTMENT ;
    PORT
      LAYER metal3 ;
      RECT 0.000 118.125 0.070 118.195 ;
    END
  END w_mask_in[417]
  PIN w_mask_in[418]
    DIRECTION INPUT ;
    USE SIGNAL ;
    SHAPE ABUTMENT ;
    PORT
      LAYER metal3 ;
      RECT 0.000 118.405 0.070 118.475 ;
    END
  END w_mask_in[418]
  PIN w_mask_in[419]
    DIRECTION INPUT ;
    USE SIGNAL ;
    SHAPE ABUTMENT ;
    PORT
      LAYER metal3 ;
      RECT 0.000 118.685 0.070 118.755 ;
    END
  END w_mask_in[419]
  PIN w_mask_in[420]
    DIRECTION INPUT ;
    USE SIGNAL ;
    SHAPE ABUTMENT ;
    PORT
      LAYER metal3 ;
      RECT 0.000 118.965 0.070 119.035 ;
    END
  END w_mask_in[420]
  PIN w_mask_in[421]
    DIRECTION INPUT ;
    USE SIGNAL ;
    SHAPE ABUTMENT ;
    PORT
      LAYER metal3 ;
      RECT 0.000 119.245 0.070 119.315 ;
    END
  END w_mask_in[421]
  PIN w_mask_in[422]
    DIRECTION INPUT ;
    USE SIGNAL ;
    SHAPE ABUTMENT ;
    PORT
      LAYER metal3 ;
      RECT 0.000 119.525 0.070 119.595 ;
    END
  END w_mask_in[422]
  PIN w_mask_in[423]
    DIRECTION INPUT ;
    USE SIGNAL ;
    SHAPE ABUTMENT ;
    PORT
      LAYER metal3 ;
      RECT 0.000 119.805 0.070 119.875 ;
    END
  END w_mask_in[423]
  PIN w_mask_in[424]
    DIRECTION INPUT ;
    USE SIGNAL ;
    SHAPE ABUTMENT ;
    PORT
      LAYER metal3 ;
      RECT 0.000 120.085 0.070 120.155 ;
    END
  END w_mask_in[424]
  PIN w_mask_in[425]
    DIRECTION INPUT ;
    USE SIGNAL ;
    SHAPE ABUTMENT ;
    PORT
      LAYER metal3 ;
      RECT 0.000 120.365 0.070 120.435 ;
    END
  END w_mask_in[425]
  PIN w_mask_in[426]
    DIRECTION INPUT ;
    USE SIGNAL ;
    SHAPE ABUTMENT ;
    PORT
      LAYER metal3 ;
      RECT 0.000 120.645 0.070 120.715 ;
    END
  END w_mask_in[426]
  PIN w_mask_in[427]
    DIRECTION INPUT ;
    USE SIGNAL ;
    SHAPE ABUTMENT ;
    PORT
      LAYER metal3 ;
      RECT 0.000 120.925 0.070 120.995 ;
    END
  END w_mask_in[427]
  PIN w_mask_in[428]
    DIRECTION INPUT ;
    USE SIGNAL ;
    SHAPE ABUTMENT ;
    PORT
      LAYER metal3 ;
      RECT 0.000 121.205 0.070 121.275 ;
    END
  END w_mask_in[428]
  PIN w_mask_in[429]
    DIRECTION INPUT ;
    USE SIGNAL ;
    SHAPE ABUTMENT ;
    PORT
      LAYER metal3 ;
      RECT 0.000 121.485 0.070 121.555 ;
    END
  END w_mask_in[429]
  PIN w_mask_in[430]
    DIRECTION INPUT ;
    USE SIGNAL ;
    SHAPE ABUTMENT ;
    PORT
      LAYER metal3 ;
      RECT 0.000 121.765 0.070 121.835 ;
    END
  END w_mask_in[430]
  PIN w_mask_in[431]
    DIRECTION INPUT ;
    USE SIGNAL ;
    SHAPE ABUTMENT ;
    PORT
      LAYER metal3 ;
      RECT 0.000 122.045 0.070 122.115 ;
    END
  END w_mask_in[431]
  PIN w_mask_in[432]
    DIRECTION INPUT ;
    USE SIGNAL ;
    SHAPE ABUTMENT ;
    PORT
      LAYER metal3 ;
      RECT 0.000 122.325 0.070 122.395 ;
    END
  END w_mask_in[432]
  PIN w_mask_in[433]
    DIRECTION INPUT ;
    USE SIGNAL ;
    SHAPE ABUTMENT ;
    PORT
      LAYER metal3 ;
      RECT 0.000 122.605 0.070 122.675 ;
    END
  END w_mask_in[433]
  PIN w_mask_in[434]
    DIRECTION INPUT ;
    USE SIGNAL ;
    SHAPE ABUTMENT ;
    PORT
      LAYER metal3 ;
      RECT 0.000 122.885 0.070 122.955 ;
    END
  END w_mask_in[434]
  PIN w_mask_in[435]
    DIRECTION INPUT ;
    USE SIGNAL ;
    SHAPE ABUTMENT ;
    PORT
      LAYER metal3 ;
      RECT 0.000 123.165 0.070 123.235 ;
    END
  END w_mask_in[435]
  PIN w_mask_in[436]
    DIRECTION INPUT ;
    USE SIGNAL ;
    SHAPE ABUTMENT ;
    PORT
      LAYER metal3 ;
      RECT 0.000 123.445 0.070 123.515 ;
    END
  END w_mask_in[436]
  PIN w_mask_in[437]
    DIRECTION INPUT ;
    USE SIGNAL ;
    SHAPE ABUTMENT ;
    PORT
      LAYER metal3 ;
      RECT 0.000 123.725 0.070 123.795 ;
    END
  END w_mask_in[437]
  PIN w_mask_in[438]
    DIRECTION INPUT ;
    USE SIGNAL ;
    SHAPE ABUTMENT ;
    PORT
      LAYER metal3 ;
      RECT 0.000 124.005 0.070 124.075 ;
    END
  END w_mask_in[438]
  PIN w_mask_in[439]
    DIRECTION INPUT ;
    USE SIGNAL ;
    SHAPE ABUTMENT ;
    PORT
      LAYER metal3 ;
      RECT 0.000 124.285 0.070 124.355 ;
    END
  END w_mask_in[439]
  PIN w_mask_in[440]
    DIRECTION INPUT ;
    USE SIGNAL ;
    SHAPE ABUTMENT ;
    PORT
      LAYER metal3 ;
      RECT 0.000 124.565 0.070 124.635 ;
    END
  END w_mask_in[440]
  PIN w_mask_in[441]
    DIRECTION INPUT ;
    USE SIGNAL ;
    SHAPE ABUTMENT ;
    PORT
      LAYER metal3 ;
      RECT 0.000 124.845 0.070 124.915 ;
    END
  END w_mask_in[441]
  PIN w_mask_in[442]
    DIRECTION INPUT ;
    USE SIGNAL ;
    SHAPE ABUTMENT ;
    PORT
      LAYER metal3 ;
      RECT 0.000 125.125 0.070 125.195 ;
    END
  END w_mask_in[442]
  PIN w_mask_in[443]
    DIRECTION INPUT ;
    USE SIGNAL ;
    SHAPE ABUTMENT ;
    PORT
      LAYER metal3 ;
      RECT 0.000 125.405 0.070 125.475 ;
    END
  END w_mask_in[443]
  PIN w_mask_in[444]
    DIRECTION INPUT ;
    USE SIGNAL ;
    SHAPE ABUTMENT ;
    PORT
      LAYER metal3 ;
      RECT 0.000 125.685 0.070 125.755 ;
    END
  END w_mask_in[444]
  PIN w_mask_in[445]
    DIRECTION INPUT ;
    USE SIGNAL ;
    SHAPE ABUTMENT ;
    PORT
      LAYER metal3 ;
      RECT 0.000 125.965 0.070 126.035 ;
    END
  END w_mask_in[445]
  PIN w_mask_in[446]
    DIRECTION INPUT ;
    USE SIGNAL ;
    SHAPE ABUTMENT ;
    PORT
      LAYER metal3 ;
      RECT 0.000 126.245 0.070 126.315 ;
    END
  END w_mask_in[446]
  PIN w_mask_in[447]
    DIRECTION INPUT ;
    USE SIGNAL ;
    SHAPE ABUTMENT ;
    PORT
      LAYER metal3 ;
      RECT 0.000 126.525 0.070 126.595 ;
    END
  END w_mask_in[447]
  PIN w_mask_in[448]
    DIRECTION INPUT ;
    USE SIGNAL ;
    SHAPE ABUTMENT ;
    PORT
      LAYER metal3 ;
      RECT 0.000 126.805 0.070 126.875 ;
    END
  END w_mask_in[448]
  PIN w_mask_in[449]
    DIRECTION INPUT ;
    USE SIGNAL ;
    SHAPE ABUTMENT ;
    PORT
      LAYER metal3 ;
      RECT 0.000 127.085 0.070 127.155 ;
    END
  END w_mask_in[449]
  PIN w_mask_in[450]
    DIRECTION INPUT ;
    USE SIGNAL ;
    SHAPE ABUTMENT ;
    PORT
      LAYER metal3 ;
      RECT 0.000 127.365 0.070 127.435 ;
    END
  END w_mask_in[450]
  PIN w_mask_in[451]
    DIRECTION INPUT ;
    USE SIGNAL ;
    SHAPE ABUTMENT ;
    PORT
      LAYER metal3 ;
      RECT 0.000 127.645 0.070 127.715 ;
    END
  END w_mask_in[451]
  PIN w_mask_in[452]
    DIRECTION INPUT ;
    USE SIGNAL ;
    SHAPE ABUTMENT ;
    PORT
      LAYER metal3 ;
      RECT 0.000 127.925 0.070 127.995 ;
    END
  END w_mask_in[452]
  PIN w_mask_in[453]
    DIRECTION INPUT ;
    USE SIGNAL ;
    SHAPE ABUTMENT ;
    PORT
      LAYER metal3 ;
      RECT 0.000 128.205 0.070 128.275 ;
    END
  END w_mask_in[453]
  PIN w_mask_in[454]
    DIRECTION INPUT ;
    USE SIGNAL ;
    SHAPE ABUTMENT ;
    PORT
      LAYER metal3 ;
      RECT 0.000 128.485 0.070 128.555 ;
    END
  END w_mask_in[454]
  PIN w_mask_in[455]
    DIRECTION INPUT ;
    USE SIGNAL ;
    SHAPE ABUTMENT ;
    PORT
      LAYER metal3 ;
      RECT 0.000 128.765 0.070 128.835 ;
    END
  END w_mask_in[455]
  PIN w_mask_in[456]
    DIRECTION INPUT ;
    USE SIGNAL ;
    SHAPE ABUTMENT ;
    PORT
      LAYER metal3 ;
      RECT 0.000 129.045 0.070 129.115 ;
    END
  END w_mask_in[456]
  PIN w_mask_in[457]
    DIRECTION INPUT ;
    USE SIGNAL ;
    SHAPE ABUTMENT ;
    PORT
      LAYER metal3 ;
      RECT 0.000 129.325 0.070 129.395 ;
    END
  END w_mask_in[457]
  PIN w_mask_in[458]
    DIRECTION INPUT ;
    USE SIGNAL ;
    SHAPE ABUTMENT ;
    PORT
      LAYER metal3 ;
      RECT 0.000 129.605 0.070 129.675 ;
    END
  END w_mask_in[458]
  PIN w_mask_in[459]
    DIRECTION INPUT ;
    USE SIGNAL ;
    SHAPE ABUTMENT ;
    PORT
      LAYER metal3 ;
      RECT 0.000 129.885 0.070 129.955 ;
    END
  END w_mask_in[459]
  PIN w_mask_in[460]
    DIRECTION INPUT ;
    USE SIGNAL ;
    SHAPE ABUTMENT ;
    PORT
      LAYER metal3 ;
      RECT 0.000 130.165 0.070 130.235 ;
    END
  END w_mask_in[460]
  PIN w_mask_in[461]
    DIRECTION INPUT ;
    USE SIGNAL ;
    SHAPE ABUTMENT ;
    PORT
      LAYER metal3 ;
      RECT 0.000 130.445 0.070 130.515 ;
    END
  END w_mask_in[461]
  PIN w_mask_in[462]
    DIRECTION INPUT ;
    USE SIGNAL ;
    SHAPE ABUTMENT ;
    PORT
      LAYER metal3 ;
      RECT 0.000 130.725 0.070 130.795 ;
    END
  END w_mask_in[462]
  PIN w_mask_in[463]
    DIRECTION INPUT ;
    USE SIGNAL ;
    SHAPE ABUTMENT ;
    PORT
      LAYER metal3 ;
      RECT 0.000 131.005 0.070 131.075 ;
    END
  END w_mask_in[463]
  PIN w_mask_in[464]
    DIRECTION INPUT ;
    USE SIGNAL ;
    SHAPE ABUTMENT ;
    PORT
      LAYER metal3 ;
      RECT 0.000 131.285 0.070 131.355 ;
    END
  END w_mask_in[464]
  PIN w_mask_in[465]
    DIRECTION INPUT ;
    USE SIGNAL ;
    SHAPE ABUTMENT ;
    PORT
      LAYER metal3 ;
      RECT 0.000 131.565 0.070 131.635 ;
    END
  END w_mask_in[465]
  PIN w_mask_in[466]
    DIRECTION INPUT ;
    USE SIGNAL ;
    SHAPE ABUTMENT ;
    PORT
      LAYER metal3 ;
      RECT 0.000 131.845 0.070 131.915 ;
    END
  END w_mask_in[466]
  PIN w_mask_in[467]
    DIRECTION INPUT ;
    USE SIGNAL ;
    SHAPE ABUTMENT ;
    PORT
      LAYER metal3 ;
      RECT 0.000 132.125 0.070 132.195 ;
    END
  END w_mask_in[467]
  PIN w_mask_in[468]
    DIRECTION INPUT ;
    USE SIGNAL ;
    SHAPE ABUTMENT ;
    PORT
      LAYER metal3 ;
      RECT 0.000 132.405 0.070 132.475 ;
    END
  END w_mask_in[468]
  PIN w_mask_in[469]
    DIRECTION INPUT ;
    USE SIGNAL ;
    SHAPE ABUTMENT ;
    PORT
      LAYER metal3 ;
      RECT 0.000 132.685 0.070 132.755 ;
    END
  END w_mask_in[469]
  PIN w_mask_in[470]
    DIRECTION INPUT ;
    USE SIGNAL ;
    SHAPE ABUTMENT ;
    PORT
      LAYER metal3 ;
      RECT 0.000 132.965 0.070 133.035 ;
    END
  END w_mask_in[470]
  PIN w_mask_in[471]
    DIRECTION INPUT ;
    USE SIGNAL ;
    SHAPE ABUTMENT ;
    PORT
      LAYER metal3 ;
      RECT 0.000 133.245 0.070 133.315 ;
    END
  END w_mask_in[471]
  PIN w_mask_in[472]
    DIRECTION INPUT ;
    USE SIGNAL ;
    SHAPE ABUTMENT ;
    PORT
      LAYER metal3 ;
      RECT 0.000 133.525 0.070 133.595 ;
    END
  END w_mask_in[472]
  PIN w_mask_in[473]
    DIRECTION INPUT ;
    USE SIGNAL ;
    SHAPE ABUTMENT ;
    PORT
      LAYER metal3 ;
      RECT 0.000 133.805 0.070 133.875 ;
    END
  END w_mask_in[473]
  PIN w_mask_in[474]
    DIRECTION INPUT ;
    USE SIGNAL ;
    SHAPE ABUTMENT ;
    PORT
      LAYER metal3 ;
      RECT 0.000 134.085 0.070 134.155 ;
    END
  END w_mask_in[474]
  PIN w_mask_in[475]
    DIRECTION INPUT ;
    USE SIGNAL ;
    SHAPE ABUTMENT ;
    PORT
      LAYER metal3 ;
      RECT 0.000 134.365 0.070 134.435 ;
    END
  END w_mask_in[475]
  PIN w_mask_in[476]
    DIRECTION INPUT ;
    USE SIGNAL ;
    SHAPE ABUTMENT ;
    PORT
      LAYER metal3 ;
      RECT 0.000 134.645 0.070 134.715 ;
    END
  END w_mask_in[476]
  PIN w_mask_in[477]
    DIRECTION INPUT ;
    USE SIGNAL ;
    SHAPE ABUTMENT ;
    PORT
      LAYER metal3 ;
      RECT 0.000 134.925 0.070 134.995 ;
    END
  END w_mask_in[477]
  PIN w_mask_in[478]
    DIRECTION INPUT ;
    USE SIGNAL ;
    SHAPE ABUTMENT ;
    PORT
      LAYER metal3 ;
      RECT 0.000 135.205 0.070 135.275 ;
    END
  END w_mask_in[478]
  PIN w_mask_in[479]
    DIRECTION INPUT ;
    USE SIGNAL ;
    SHAPE ABUTMENT ;
    PORT
      LAYER metal3 ;
      RECT 0.000 135.485 0.070 135.555 ;
    END
  END w_mask_in[479]
  PIN w_mask_in[480]
    DIRECTION INPUT ;
    USE SIGNAL ;
    SHAPE ABUTMENT ;
    PORT
      LAYER metal3 ;
      RECT 0.000 135.765 0.070 135.835 ;
    END
  END w_mask_in[480]
  PIN w_mask_in[481]
    DIRECTION INPUT ;
    USE SIGNAL ;
    SHAPE ABUTMENT ;
    PORT
      LAYER metal3 ;
      RECT 0.000 136.045 0.070 136.115 ;
    END
  END w_mask_in[481]
  PIN w_mask_in[482]
    DIRECTION INPUT ;
    USE SIGNAL ;
    SHAPE ABUTMENT ;
    PORT
      LAYER metal3 ;
      RECT 0.000 136.325 0.070 136.395 ;
    END
  END w_mask_in[482]
  PIN w_mask_in[483]
    DIRECTION INPUT ;
    USE SIGNAL ;
    SHAPE ABUTMENT ;
    PORT
      LAYER metal3 ;
      RECT 0.000 136.605 0.070 136.675 ;
    END
  END w_mask_in[483]
  PIN w_mask_in[484]
    DIRECTION INPUT ;
    USE SIGNAL ;
    SHAPE ABUTMENT ;
    PORT
      LAYER metal3 ;
      RECT 0.000 136.885 0.070 136.955 ;
    END
  END w_mask_in[484]
  PIN w_mask_in[485]
    DIRECTION INPUT ;
    USE SIGNAL ;
    SHAPE ABUTMENT ;
    PORT
      LAYER metal3 ;
      RECT 0.000 137.165 0.070 137.235 ;
    END
  END w_mask_in[485]
  PIN w_mask_in[486]
    DIRECTION INPUT ;
    USE SIGNAL ;
    SHAPE ABUTMENT ;
    PORT
      LAYER metal3 ;
      RECT 0.000 137.445 0.070 137.515 ;
    END
  END w_mask_in[486]
  PIN w_mask_in[487]
    DIRECTION INPUT ;
    USE SIGNAL ;
    SHAPE ABUTMENT ;
    PORT
      LAYER metal3 ;
      RECT 0.000 137.725 0.070 137.795 ;
    END
  END w_mask_in[487]
  PIN w_mask_in[488]
    DIRECTION INPUT ;
    USE SIGNAL ;
    SHAPE ABUTMENT ;
    PORT
      LAYER metal3 ;
      RECT 0.000 138.005 0.070 138.075 ;
    END
  END w_mask_in[488]
  PIN w_mask_in[489]
    DIRECTION INPUT ;
    USE SIGNAL ;
    SHAPE ABUTMENT ;
    PORT
      LAYER metal3 ;
      RECT 0.000 138.285 0.070 138.355 ;
    END
  END w_mask_in[489]
  PIN w_mask_in[490]
    DIRECTION INPUT ;
    USE SIGNAL ;
    SHAPE ABUTMENT ;
    PORT
      LAYER metal3 ;
      RECT 0.000 138.565 0.070 138.635 ;
    END
  END w_mask_in[490]
  PIN w_mask_in[491]
    DIRECTION INPUT ;
    USE SIGNAL ;
    SHAPE ABUTMENT ;
    PORT
      LAYER metal3 ;
      RECT 0.000 138.845 0.070 138.915 ;
    END
  END w_mask_in[491]
  PIN w_mask_in[492]
    DIRECTION INPUT ;
    USE SIGNAL ;
    SHAPE ABUTMENT ;
    PORT
      LAYER metal3 ;
      RECT 0.000 139.125 0.070 139.195 ;
    END
  END w_mask_in[492]
  PIN w_mask_in[493]
    DIRECTION INPUT ;
    USE SIGNAL ;
    SHAPE ABUTMENT ;
    PORT
      LAYER metal3 ;
      RECT 0.000 139.405 0.070 139.475 ;
    END
  END w_mask_in[493]
  PIN w_mask_in[494]
    DIRECTION INPUT ;
    USE SIGNAL ;
    SHAPE ABUTMENT ;
    PORT
      LAYER metal3 ;
      RECT 0.000 139.685 0.070 139.755 ;
    END
  END w_mask_in[494]
  PIN w_mask_in[495]
    DIRECTION INPUT ;
    USE SIGNAL ;
    SHAPE ABUTMENT ;
    PORT
      LAYER metal3 ;
      RECT 0.000 139.965 0.070 140.035 ;
    END
  END w_mask_in[495]
  PIN w_mask_in[496]
    DIRECTION INPUT ;
    USE SIGNAL ;
    SHAPE ABUTMENT ;
    PORT
      LAYER metal3 ;
      RECT 0.000 140.245 0.070 140.315 ;
    END
  END w_mask_in[496]
  PIN w_mask_in[497]
    DIRECTION INPUT ;
    USE SIGNAL ;
    SHAPE ABUTMENT ;
    PORT
      LAYER metal3 ;
      RECT 0.000 140.525 0.070 140.595 ;
    END
  END w_mask_in[497]
  PIN w_mask_in[498]
    DIRECTION INPUT ;
    USE SIGNAL ;
    SHAPE ABUTMENT ;
    PORT
      LAYER metal3 ;
      RECT 0.000 140.805 0.070 140.875 ;
    END
  END w_mask_in[498]
  PIN w_mask_in[499]
    DIRECTION INPUT ;
    USE SIGNAL ;
    SHAPE ABUTMENT ;
    PORT
      LAYER metal3 ;
      RECT 0.000 141.085 0.070 141.155 ;
    END
  END w_mask_in[499]
  PIN w_mask_in[500]
    DIRECTION INPUT ;
    USE SIGNAL ;
    SHAPE ABUTMENT ;
    PORT
      LAYER metal3 ;
      RECT 0.000 141.365 0.070 141.435 ;
    END
  END w_mask_in[500]
  PIN w_mask_in[501]
    DIRECTION INPUT ;
    USE SIGNAL ;
    SHAPE ABUTMENT ;
    PORT
      LAYER metal3 ;
      RECT 0.000 141.645 0.070 141.715 ;
    END
  END w_mask_in[501]
  PIN w_mask_in[502]
    DIRECTION INPUT ;
    USE SIGNAL ;
    SHAPE ABUTMENT ;
    PORT
      LAYER metal3 ;
      RECT 0.000 141.925 0.070 141.995 ;
    END
  END w_mask_in[502]
  PIN w_mask_in[503]
    DIRECTION INPUT ;
    USE SIGNAL ;
    SHAPE ABUTMENT ;
    PORT
      LAYER metal3 ;
      RECT 0.000 142.205 0.070 142.275 ;
    END
  END w_mask_in[503]
  PIN w_mask_in[504]
    DIRECTION INPUT ;
    USE SIGNAL ;
    SHAPE ABUTMENT ;
    PORT
      LAYER metal3 ;
      RECT 0.000 142.485 0.070 142.555 ;
    END
  END w_mask_in[504]
  PIN w_mask_in[505]
    DIRECTION INPUT ;
    USE SIGNAL ;
    SHAPE ABUTMENT ;
    PORT
      LAYER metal3 ;
      RECT 0.000 142.765 0.070 142.835 ;
    END
  END w_mask_in[505]
  PIN w_mask_in[506]
    DIRECTION INPUT ;
    USE SIGNAL ;
    SHAPE ABUTMENT ;
    PORT
      LAYER metal3 ;
      RECT 0.000 143.045 0.070 143.115 ;
    END
  END w_mask_in[506]
  PIN w_mask_in[507]
    DIRECTION INPUT ;
    USE SIGNAL ;
    SHAPE ABUTMENT ;
    PORT
      LAYER metal3 ;
      RECT 0.000 143.325 0.070 143.395 ;
    END
  END w_mask_in[507]
  PIN w_mask_in[508]
    DIRECTION INPUT ;
    USE SIGNAL ;
    SHAPE ABUTMENT ;
    PORT
      LAYER metal3 ;
      RECT 0.000 143.605 0.070 143.675 ;
    END
  END w_mask_in[508]
  PIN w_mask_in[509]
    DIRECTION INPUT ;
    USE SIGNAL ;
    SHAPE ABUTMENT ;
    PORT
      LAYER metal3 ;
      RECT 0.000 143.885 0.070 143.955 ;
    END
  END w_mask_in[509]
  PIN w_mask_in[510]
    DIRECTION INPUT ;
    USE SIGNAL ;
    SHAPE ABUTMENT ;
    PORT
      LAYER metal3 ;
      RECT 0.000 144.165 0.070 144.235 ;
    END
  END w_mask_in[510]
  PIN w_mask_in[511]
    DIRECTION INPUT ;
    USE SIGNAL ;
    SHAPE ABUTMENT ;
    PORT
      LAYER metal3 ;
      RECT 0.000 144.445 0.070 144.515 ;
    END
  END w_mask_in[511]
  PIN rd_out[0]
    DIRECTION OUTPUT ;
    USE SIGNAL ;
    SHAPE ABUTMENT ;
    PORT
      LAYER metal3 ;
      RECT 0.000 181.405 0.070 181.475 ;
    END
  END rd_out[0]
  PIN rd_out[1]
    DIRECTION OUTPUT ;
    USE SIGNAL ;
    SHAPE ABUTMENT ;
    PORT
      LAYER metal3 ;
      RECT 0.000 181.685 0.070 181.755 ;
    END
  END rd_out[1]
  PIN rd_out[2]
    DIRECTION OUTPUT ;
    USE SIGNAL ;
    SHAPE ABUTMENT ;
    PORT
      LAYER metal3 ;
      RECT 0.000 181.965 0.070 182.035 ;
    END
  END rd_out[2]
  PIN rd_out[3]
    DIRECTION OUTPUT ;
    USE SIGNAL ;
    SHAPE ABUTMENT ;
    PORT
      LAYER metal3 ;
      RECT 0.000 182.245 0.070 182.315 ;
    END
  END rd_out[3]
  PIN rd_out[4]
    DIRECTION OUTPUT ;
    USE SIGNAL ;
    SHAPE ABUTMENT ;
    PORT
      LAYER metal3 ;
      RECT 0.000 182.525 0.070 182.595 ;
    END
  END rd_out[4]
  PIN rd_out[5]
    DIRECTION OUTPUT ;
    USE SIGNAL ;
    SHAPE ABUTMENT ;
    PORT
      LAYER metal3 ;
      RECT 0.000 182.805 0.070 182.875 ;
    END
  END rd_out[5]
  PIN rd_out[6]
    DIRECTION OUTPUT ;
    USE SIGNAL ;
    SHAPE ABUTMENT ;
    PORT
      LAYER metal3 ;
      RECT 0.000 183.085 0.070 183.155 ;
    END
  END rd_out[6]
  PIN rd_out[7]
    DIRECTION OUTPUT ;
    USE SIGNAL ;
    SHAPE ABUTMENT ;
    PORT
      LAYER metal3 ;
      RECT 0.000 183.365 0.070 183.435 ;
    END
  END rd_out[7]
  PIN rd_out[8]
    DIRECTION OUTPUT ;
    USE SIGNAL ;
    SHAPE ABUTMENT ;
    PORT
      LAYER metal3 ;
      RECT 0.000 183.645 0.070 183.715 ;
    END
  END rd_out[8]
  PIN rd_out[9]
    DIRECTION OUTPUT ;
    USE SIGNAL ;
    SHAPE ABUTMENT ;
    PORT
      LAYER metal3 ;
      RECT 0.000 183.925 0.070 183.995 ;
    END
  END rd_out[9]
  PIN rd_out[10]
    DIRECTION OUTPUT ;
    USE SIGNAL ;
    SHAPE ABUTMENT ;
    PORT
      LAYER metal3 ;
      RECT 0.000 184.205 0.070 184.275 ;
    END
  END rd_out[10]
  PIN rd_out[11]
    DIRECTION OUTPUT ;
    USE SIGNAL ;
    SHAPE ABUTMENT ;
    PORT
      LAYER metal3 ;
      RECT 0.000 184.485 0.070 184.555 ;
    END
  END rd_out[11]
  PIN rd_out[12]
    DIRECTION OUTPUT ;
    USE SIGNAL ;
    SHAPE ABUTMENT ;
    PORT
      LAYER metal3 ;
      RECT 0.000 184.765 0.070 184.835 ;
    END
  END rd_out[12]
  PIN rd_out[13]
    DIRECTION OUTPUT ;
    USE SIGNAL ;
    SHAPE ABUTMENT ;
    PORT
      LAYER metal3 ;
      RECT 0.000 185.045 0.070 185.115 ;
    END
  END rd_out[13]
  PIN rd_out[14]
    DIRECTION OUTPUT ;
    USE SIGNAL ;
    SHAPE ABUTMENT ;
    PORT
      LAYER metal3 ;
      RECT 0.000 185.325 0.070 185.395 ;
    END
  END rd_out[14]
  PIN rd_out[15]
    DIRECTION OUTPUT ;
    USE SIGNAL ;
    SHAPE ABUTMENT ;
    PORT
      LAYER metal3 ;
      RECT 0.000 185.605 0.070 185.675 ;
    END
  END rd_out[15]
  PIN rd_out[16]
    DIRECTION OUTPUT ;
    USE SIGNAL ;
    SHAPE ABUTMENT ;
    PORT
      LAYER metal3 ;
      RECT 0.000 185.885 0.070 185.955 ;
    END
  END rd_out[16]
  PIN rd_out[17]
    DIRECTION OUTPUT ;
    USE SIGNAL ;
    SHAPE ABUTMENT ;
    PORT
      LAYER metal3 ;
      RECT 0.000 186.165 0.070 186.235 ;
    END
  END rd_out[17]
  PIN rd_out[18]
    DIRECTION OUTPUT ;
    USE SIGNAL ;
    SHAPE ABUTMENT ;
    PORT
      LAYER metal3 ;
      RECT 0.000 186.445 0.070 186.515 ;
    END
  END rd_out[18]
  PIN rd_out[19]
    DIRECTION OUTPUT ;
    USE SIGNAL ;
    SHAPE ABUTMENT ;
    PORT
      LAYER metal3 ;
      RECT 0.000 186.725 0.070 186.795 ;
    END
  END rd_out[19]
  PIN rd_out[20]
    DIRECTION OUTPUT ;
    USE SIGNAL ;
    SHAPE ABUTMENT ;
    PORT
      LAYER metal3 ;
      RECT 0.000 187.005 0.070 187.075 ;
    END
  END rd_out[20]
  PIN rd_out[21]
    DIRECTION OUTPUT ;
    USE SIGNAL ;
    SHAPE ABUTMENT ;
    PORT
      LAYER metal3 ;
      RECT 0.000 187.285 0.070 187.355 ;
    END
  END rd_out[21]
  PIN rd_out[22]
    DIRECTION OUTPUT ;
    USE SIGNAL ;
    SHAPE ABUTMENT ;
    PORT
      LAYER metal3 ;
      RECT 0.000 187.565 0.070 187.635 ;
    END
  END rd_out[22]
  PIN rd_out[23]
    DIRECTION OUTPUT ;
    USE SIGNAL ;
    SHAPE ABUTMENT ;
    PORT
      LAYER metal3 ;
      RECT 0.000 187.845 0.070 187.915 ;
    END
  END rd_out[23]
  PIN rd_out[24]
    DIRECTION OUTPUT ;
    USE SIGNAL ;
    SHAPE ABUTMENT ;
    PORT
      LAYER metal3 ;
      RECT 0.000 188.125 0.070 188.195 ;
    END
  END rd_out[24]
  PIN rd_out[25]
    DIRECTION OUTPUT ;
    USE SIGNAL ;
    SHAPE ABUTMENT ;
    PORT
      LAYER metal3 ;
      RECT 0.000 188.405 0.070 188.475 ;
    END
  END rd_out[25]
  PIN rd_out[26]
    DIRECTION OUTPUT ;
    USE SIGNAL ;
    SHAPE ABUTMENT ;
    PORT
      LAYER metal3 ;
      RECT 0.000 188.685 0.070 188.755 ;
    END
  END rd_out[26]
  PIN rd_out[27]
    DIRECTION OUTPUT ;
    USE SIGNAL ;
    SHAPE ABUTMENT ;
    PORT
      LAYER metal3 ;
      RECT 0.000 188.965 0.070 189.035 ;
    END
  END rd_out[27]
  PIN rd_out[28]
    DIRECTION OUTPUT ;
    USE SIGNAL ;
    SHAPE ABUTMENT ;
    PORT
      LAYER metal3 ;
      RECT 0.000 189.245 0.070 189.315 ;
    END
  END rd_out[28]
  PIN rd_out[29]
    DIRECTION OUTPUT ;
    USE SIGNAL ;
    SHAPE ABUTMENT ;
    PORT
      LAYER metal3 ;
      RECT 0.000 189.525 0.070 189.595 ;
    END
  END rd_out[29]
  PIN rd_out[30]
    DIRECTION OUTPUT ;
    USE SIGNAL ;
    SHAPE ABUTMENT ;
    PORT
      LAYER metal3 ;
      RECT 0.000 189.805 0.070 189.875 ;
    END
  END rd_out[30]
  PIN rd_out[31]
    DIRECTION OUTPUT ;
    USE SIGNAL ;
    SHAPE ABUTMENT ;
    PORT
      LAYER metal3 ;
      RECT 0.000 190.085 0.070 190.155 ;
    END
  END rd_out[31]
  PIN rd_out[32]
    DIRECTION OUTPUT ;
    USE SIGNAL ;
    SHAPE ABUTMENT ;
    PORT
      LAYER metal3 ;
      RECT 0.000 190.365 0.070 190.435 ;
    END
  END rd_out[32]
  PIN rd_out[33]
    DIRECTION OUTPUT ;
    USE SIGNAL ;
    SHAPE ABUTMENT ;
    PORT
      LAYER metal3 ;
      RECT 0.000 190.645 0.070 190.715 ;
    END
  END rd_out[33]
  PIN rd_out[34]
    DIRECTION OUTPUT ;
    USE SIGNAL ;
    SHAPE ABUTMENT ;
    PORT
      LAYER metal3 ;
      RECT 0.000 190.925 0.070 190.995 ;
    END
  END rd_out[34]
  PIN rd_out[35]
    DIRECTION OUTPUT ;
    USE SIGNAL ;
    SHAPE ABUTMENT ;
    PORT
      LAYER metal3 ;
      RECT 0.000 191.205 0.070 191.275 ;
    END
  END rd_out[35]
  PIN rd_out[36]
    DIRECTION OUTPUT ;
    USE SIGNAL ;
    SHAPE ABUTMENT ;
    PORT
      LAYER metal3 ;
      RECT 0.000 191.485 0.070 191.555 ;
    END
  END rd_out[36]
  PIN rd_out[37]
    DIRECTION OUTPUT ;
    USE SIGNAL ;
    SHAPE ABUTMENT ;
    PORT
      LAYER metal3 ;
      RECT 0.000 191.765 0.070 191.835 ;
    END
  END rd_out[37]
  PIN rd_out[38]
    DIRECTION OUTPUT ;
    USE SIGNAL ;
    SHAPE ABUTMENT ;
    PORT
      LAYER metal3 ;
      RECT 0.000 192.045 0.070 192.115 ;
    END
  END rd_out[38]
  PIN rd_out[39]
    DIRECTION OUTPUT ;
    USE SIGNAL ;
    SHAPE ABUTMENT ;
    PORT
      LAYER metal3 ;
      RECT 0.000 192.325 0.070 192.395 ;
    END
  END rd_out[39]
  PIN rd_out[40]
    DIRECTION OUTPUT ;
    USE SIGNAL ;
    SHAPE ABUTMENT ;
    PORT
      LAYER metal3 ;
      RECT 0.000 192.605 0.070 192.675 ;
    END
  END rd_out[40]
  PIN rd_out[41]
    DIRECTION OUTPUT ;
    USE SIGNAL ;
    SHAPE ABUTMENT ;
    PORT
      LAYER metal3 ;
      RECT 0.000 192.885 0.070 192.955 ;
    END
  END rd_out[41]
  PIN rd_out[42]
    DIRECTION OUTPUT ;
    USE SIGNAL ;
    SHAPE ABUTMENT ;
    PORT
      LAYER metal3 ;
      RECT 0.000 193.165 0.070 193.235 ;
    END
  END rd_out[42]
  PIN rd_out[43]
    DIRECTION OUTPUT ;
    USE SIGNAL ;
    SHAPE ABUTMENT ;
    PORT
      LAYER metal3 ;
      RECT 0.000 193.445 0.070 193.515 ;
    END
  END rd_out[43]
  PIN rd_out[44]
    DIRECTION OUTPUT ;
    USE SIGNAL ;
    SHAPE ABUTMENT ;
    PORT
      LAYER metal3 ;
      RECT 0.000 193.725 0.070 193.795 ;
    END
  END rd_out[44]
  PIN rd_out[45]
    DIRECTION OUTPUT ;
    USE SIGNAL ;
    SHAPE ABUTMENT ;
    PORT
      LAYER metal3 ;
      RECT 0.000 194.005 0.070 194.075 ;
    END
  END rd_out[45]
  PIN rd_out[46]
    DIRECTION OUTPUT ;
    USE SIGNAL ;
    SHAPE ABUTMENT ;
    PORT
      LAYER metal3 ;
      RECT 0.000 194.285 0.070 194.355 ;
    END
  END rd_out[46]
  PIN rd_out[47]
    DIRECTION OUTPUT ;
    USE SIGNAL ;
    SHAPE ABUTMENT ;
    PORT
      LAYER metal3 ;
      RECT 0.000 194.565 0.070 194.635 ;
    END
  END rd_out[47]
  PIN rd_out[48]
    DIRECTION OUTPUT ;
    USE SIGNAL ;
    SHAPE ABUTMENT ;
    PORT
      LAYER metal3 ;
      RECT 0.000 194.845 0.070 194.915 ;
    END
  END rd_out[48]
  PIN rd_out[49]
    DIRECTION OUTPUT ;
    USE SIGNAL ;
    SHAPE ABUTMENT ;
    PORT
      LAYER metal3 ;
      RECT 0.000 195.125 0.070 195.195 ;
    END
  END rd_out[49]
  PIN rd_out[50]
    DIRECTION OUTPUT ;
    USE SIGNAL ;
    SHAPE ABUTMENT ;
    PORT
      LAYER metal3 ;
      RECT 0.000 195.405 0.070 195.475 ;
    END
  END rd_out[50]
  PIN rd_out[51]
    DIRECTION OUTPUT ;
    USE SIGNAL ;
    SHAPE ABUTMENT ;
    PORT
      LAYER metal3 ;
      RECT 0.000 195.685 0.070 195.755 ;
    END
  END rd_out[51]
  PIN rd_out[52]
    DIRECTION OUTPUT ;
    USE SIGNAL ;
    SHAPE ABUTMENT ;
    PORT
      LAYER metal3 ;
      RECT 0.000 195.965 0.070 196.035 ;
    END
  END rd_out[52]
  PIN rd_out[53]
    DIRECTION OUTPUT ;
    USE SIGNAL ;
    SHAPE ABUTMENT ;
    PORT
      LAYER metal3 ;
      RECT 0.000 196.245 0.070 196.315 ;
    END
  END rd_out[53]
  PIN rd_out[54]
    DIRECTION OUTPUT ;
    USE SIGNAL ;
    SHAPE ABUTMENT ;
    PORT
      LAYER metal3 ;
      RECT 0.000 196.525 0.070 196.595 ;
    END
  END rd_out[54]
  PIN rd_out[55]
    DIRECTION OUTPUT ;
    USE SIGNAL ;
    SHAPE ABUTMENT ;
    PORT
      LAYER metal3 ;
      RECT 0.000 196.805 0.070 196.875 ;
    END
  END rd_out[55]
  PIN rd_out[56]
    DIRECTION OUTPUT ;
    USE SIGNAL ;
    SHAPE ABUTMENT ;
    PORT
      LAYER metal3 ;
      RECT 0.000 197.085 0.070 197.155 ;
    END
  END rd_out[56]
  PIN rd_out[57]
    DIRECTION OUTPUT ;
    USE SIGNAL ;
    SHAPE ABUTMENT ;
    PORT
      LAYER metal3 ;
      RECT 0.000 197.365 0.070 197.435 ;
    END
  END rd_out[57]
  PIN rd_out[58]
    DIRECTION OUTPUT ;
    USE SIGNAL ;
    SHAPE ABUTMENT ;
    PORT
      LAYER metal3 ;
      RECT 0.000 197.645 0.070 197.715 ;
    END
  END rd_out[58]
  PIN rd_out[59]
    DIRECTION OUTPUT ;
    USE SIGNAL ;
    SHAPE ABUTMENT ;
    PORT
      LAYER metal3 ;
      RECT 0.000 197.925 0.070 197.995 ;
    END
  END rd_out[59]
  PIN rd_out[60]
    DIRECTION OUTPUT ;
    USE SIGNAL ;
    SHAPE ABUTMENT ;
    PORT
      LAYER metal3 ;
      RECT 0.000 198.205 0.070 198.275 ;
    END
  END rd_out[60]
  PIN rd_out[61]
    DIRECTION OUTPUT ;
    USE SIGNAL ;
    SHAPE ABUTMENT ;
    PORT
      LAYER metal3 ;
      RECT 0.000 198.485 0.070 198.555 ;
    END
  END rd_out[61]
  PIN rd_out[62]
    DIRECTION OUTPUT ;
    USE SIGNAL ;
    SHAPE ABUTMENT ;
    PORT
      LAYER metal3 ;
      RECT 0.000 198.765 0.070 198.835 ;
    END
  END rd_out[62]
  PIN rd_out[63]
    DIRECTION OUTPUT ;
    USE SIGNAL ;
    SHAPE ABUTMENT ;
    PORT
      LAYER metal3 ;
      RECT 0.000 199.045 0.070 199.115 ;
    END
  END rd_out[63]
  PIN rd_out[64]
    DIRECTION OUTPUT ;
    USE SIGNAL ;
    SHAPE ABUTMENT ;
    PORT
      LAYER metal3 ;
      RECT 0.000 199.325 0.070 199.395 ;
    END
  END rd_out[64]
  PIN rd_out[65]
    DIRECTION OUTPUT ;
    USE SIGNAL ;
    SHAPE ABUTMENT ;
    PORT
      LAYER metal3 ;
      RECT 0.000 199.605 0.070 199.675 ;
    END
  END rd_out[65]
  PIN rd_out[66]
    DIRECTION OUTPUT ;
    USE SIGNAL ;
    SHAPE ABUTMENT ;
    PORT
      LAYER metal3 ;
      RECT 0.000 199.885 0.070 199.955 ;
    END
  END rd_out[66]
  PIN rd_out[67]
    DIRECTION OUTPUT ;
    USE SIGNAL ;
    SHAPE ABUTMENT ;
    PORT
      LAYER metal3 ;
      RECT 0.000 200.165 0.070 200.235 ;
    END
  END rd_out[67]
  PIN rd_out[68]
    DIRECTION OUTPUT ;
    USE SIGNAL ;
    SHAPE ABUTMENT ;
    PORT
      LAYER metal3 ;
      RECT 0.000 200.445 0.070 200.515 ;
    END
  END rd_out[68]
  PIN rd_out[69]
    DIRECTION OUTPUT ;
    USE SIGNAL ;
    SHAPE ABUTMENT ;
    PORT
      LAYER metal3 ;
      RECT 0.000 200.725 0.070 200.795 ;
    END
  END rd_out[69]
  PIN rd_out[70]
    DIRECTION OUTPUT ;
    USE SIGNAL ;
    SHAPE ABUTMENT ;
    PORT
      LAYER metal3 ;
      RECT 0.000 201.005 0.070 201.075 ;
    END
  END rd_out[70]
  PIN rd_out[71]
    DIRECTION OUTPUT ;
    USE SIGNAL ;
    SHAPE ABUTMENT ;
    PORT
      LAYER metal3 ;
      RECT 0.000 201.285 0.070 201.355 ;
    END
  END rd_out[71]
  PIN rd_out[72]
    DIRECTION OUTPUT ;
    USE SIGNAL ;
    SHAPE ABUTMENT ;
    PORT
      LAYER metal3 ;
      RECT 0.000 201.565 0.070 201.635 ;
    END
  END rd_out[72]
  PIN rd_out[73]
    DIRECTION OUTPUT ;
    USE SIGNAL ;
    SHAPE ABUTMENT ;
    PORT
      LAYER metal3 ;
      RECT 0.000 201.845 0.070 201.915 ;
    END
  END rd_out[73]
  PIN rd_out[74]
    DIRECTION OUTPUT ;
    USE SIGNAL ;
    SHAPE ABUTMENT ;
    PORT
      LAYER metal3 ;
      RECT 0.000 202.125 0.070 202.195 ;
    END
  END rd_out[74]
  PIN rd_out[75]
    DIRECTION OUTPUT ;
    USE SIGNAL ;
    SHAPE ABUTMENT ;
    PORT
      LAYER metal3 ;
      RECT 0.000 202.405 0.070 202.475 ;
    END
  END rd_out[75]
  PIN rd_out[76]
    DIRECTION OUTPUT ;
    USE SIGNAL ;
    SHAPE ABUTMENT ;
    PORT
      LAYER metal3 ;
      RECT 0.000 202.685 0.070 202.755 ;
    END
  END rd_out[76]
  PIN rd_out[77]
    DIRECTION OUTPUT ;
    USE SIGNAL ;
    SHAPE ABUTMENT ;
    PORT
      LAYER metal3 ;
      RECT 0.000 202.965 0.070 203.035 ;
    END
  END rd_out[77]
  PIN rd_out[78]
    DIRECTION OUTPUT ;
    USE SIGNAL ;
    SHAPE ABUTMENT ;
    PORT
      LAYER metal3 ;
      RECT 0.000 203.245 0.070 203.315 ;
    END
  END rd_out[78]
  PIN rd_out[79]
    DIRECTION OUTPUT ;
    USE SIGNAL ;
    SHAPE ABUTMENT ;
    PORT
      LAYER metal3 ;
      RECT 0.000 203.525 0.070 203.595 ;
    END
  END rd_out[79]
  PIN rd_out[80]
    DIRECTION OUTPUT ;
    USE SIGNAL ;
    SHAPE ABUTMENT ;
    PORT
      LAYER metal3 ;
      RECT 0.000 203.805 0.070 203.875 ;
    END
  END rd_out[80]
  PIN rd_out[81]
    DIRECTION OUTPUT ;
    USE SIGNAL ;
    SHAPE ABUTMENT ;
    PORT
      LAYER metal3 ;
      RECT 0.000 204.085 0.070 204.155 ;
    END
  END rd_out[81]
  PIN rd_out[82]
    DIRECTION OUTPUT ;
    USE SIGNAL ;
    SHAPE ABUTMENT ;
    PORT
      LAYER metal3 ;
      RECT 0.000 204.365 0.070 204.435 ;
    END
  END rd_out[82]
  PIN rd_out[83]
    DIRECTION OUTPUT ;
    USE SIGNAL ;
    SHAPE ABUTMENT ;
    PORT
      LAYER metal3 ;
      RECT 0.000 204.645 0.070 204.715 ;
    END
  END rd_out[83]
  PIN rd_out[84]
    DIRECTION OUTPUT ;
    USE SIGNAL ;
    SHAPE ABUTMENT ;
    PORT
      LAYER metal3 ;
      RECT 0.000 204.925 0.070 204.995 ;
    END
  END rd_out[84]
  PIN rd_out[85]
    DIRECTION OUTPUT ;
    USE SIGNAL ;
    SHAPE ABUTMENT ;
    PORT
      LAYER metal3 ;
      RECT 0.000 205.205 0.070 205.275 ;
    END
  END rd_out[85]
  PIN rd_out[86]
    DIRECTION OUTPUT ;
    USE SIGNAL ;
    SHAPE ABUTMENT ;
    PORT
      LAYER metal3 ;
      RECT 0.000 205.485 0.070 205.555 ;
    END
  END rd_out[86]
  PIN rd_out[87]
    DIRECTION OUTPUT ;
    USE SIGNAL ;
    SHAPE ABUTMENT ;
    PORT
      LAYER metal3 ;
      RECT 0.000 205.765 0.070 205.835 ;
    END
  END rd_out[87]
  PIN rd_out[88]
    DIRECTION OUTPUT ;
    USE SIGNAL ;
    SHAPE ABUTMENT ;
    PORT
      LAYER metal3 ;
      RECT 0.000 206.045 0.070 206.115 ;
    END
  END rd_out[88]
  PIN rd_out[89]
    DIRECTION OUTPUT ;
    USE SIGNAL ;
    SHAPE ABUTMENT ;
    PORT
      LAYER metal3 ;
      RECT 0.000 206.325 0.070 206.395 ;
    END
  END rd_out[89]
  PIN rd_out[90]
    DIRECTION OUTPUT ;
    USE SIGNAL ;
    SHAPE ABUTMENT ;
    PORT
      LAYER metal3 ;
      RECT 0.000 206.605 0.070 206.675 ;
    END
  END rd_out[90]
  PIN rd_out[91]
    DIRECTION OUTPUT ;
    USE SIGNAL ;
    SHAPE ABUTMENT ;
    PORT
      LAYER metal3 ;
      RECT 0.000 206.885 0.070 206.955 ;
    END
  END rd_out[91]
  PIN rd_out[92]
    DIRECTION OUTPUT ;
    USE SIGNAL ;
    SHAPE ABUTMENT ;
    PORT
      LAYER metal3 ;
      RECT 0.000 207.165 0.070 207.235 ;
    END
  END rd_out[92]
  PIN rd_out[93]
    DIRECTION OUTPUT ;
    USE SIGNAL ;
    SHAPE ABUTMENT ;
    PORT
      LAYER metal3 ;
      RECT 0.000 207.445 0.070 207.515 ;
    END
  END rd_out[93]
  PIN rd_out[94]
    DIRECTION OUTPUT ;
    USE SIGNAL ;
    SHAPE ABUTMENT ;
    PORT
      LAYER metal3 ;
      RECT 0.000 207.725 0.070 207.795 ;
    END
  END rd_out[94]
  PIN rd_out[95]
    DIRECTION OUTPUT ;
    USE SIGNAL ;
    SHAPE ABUTMENT ;
    PORT
      LAYER metal3 ;
      RECT 0.000 208.005 0.070 208.075 ;
    END
  END rd_out[95]
  PIN rd_out[96]
    DIRECTION OUTPUT ;
    USE SIGNAL ;
    SHAPE ABUTMENT ;
    PORT
      LAYER metal3 ;
      RECT 0.000 208.285 0.070 208.355 ;
    END
  END rd_out[96]
  PIN rd_out[97]
    DIRECTION OUTPUT ;
    USE SIGNAL ;
    SHAPE ABUTMENT ;
    PORT
      LAYER metal3 ;
      RECT 0.000 208.565 0.070 208.635 ;
    END
  END rd_out[97]
  PIN rd_out[98]
    DIRECTION OUTPUT ;
    USE SIGNAL ;
    SHAPE ABUTMENT ;
    PORT
      LAYER metal3 ;
      RECT 0.000 208.845 0.070 208.915 ;
    END
  END rd_out[98]
  PIN rd_out[99]
    DIRECTION OUTPUT ;
    USE SIGNAL ;
    SHAPE ABUTMENT ;
    PORT
      LAYER metal3 ;
      RECT 0.000 209.125 0.070 209.195 ;
    END
  END rd_out[99]
  PIN rd_out[100]
    DIRECTION OUTPUT ;
    USE SIGNAL ;
    SHAPE ABUTMENT ;
    PORT
      LAYER metal3 ;
      RECT 0.000 209.405 0.070 209.475 ;
    END
  END rd_out[100]
  PIN rd_out[101]
    DIRECTION OUTPUT ;
    USE SIGNAL ;
    SHAPE ABUTMENT ;
    PORT
      LAYER metal3 ;
      RECT 0.000 209.685 0.070 209.755 ;
    END
  END rd_out[101]
  PIN rd_out[102]
    DIRECTION OUTPUT ;
    USE SIGNAL ;
    SHAPE ABUTMENT ;
    PORT
      LAYER metal3 ;
      RECT 0.000 209.965 0.070 210.035 ;
    END
  END rd_out[102]
  PIN rd_out[103]
    DIRECTION OUTPUT ;
    USE SIGNAL ;
    SHAPE ABUTMENT ;
    PORT
      LAYER metal3 ;
      RECT 0.000 210.245 0.070 210.315 ;
    END
  END rd_out[103]
  PIN rd_out[104]
    DIRECTION OUTPUT ;
    USE SIGNAL ;
    SHAPE ABUTMENT ;
    PORT
      LAYER metal3 ;
      RECT 0.000 210.525 0.070 210.595 ;
    END
  END rd_out[104]
  PIN rd_out[105]
    DIRECTION OUTPUT ;
    USE SIGNAL ;
    SHAPE ABUTMENT ;
    PORT
      LAYER metal3 ;
      RECT 0.000 210.805 0.070 210.875 ;
    END
  END rd_out[105]
  PIN rd_out[106]
    DIRECTION OUTPUT ;
    USE SIGNAL ;
    SHAPE ABUTMENT ;
    PORT
      LAYER metal3 ;
      RECT 0.000 211.085 0.070 211.155 ;
    END
  END rd_out[106]
  PIN rd_out[107]
    DIRECTION OUTPUT ;
    USE SIGNAL ;
    SHAPE ABUTMENT ;
    PORT
      LAYER metal3 ;
      RECT 0.000 211.365 0.070 211.435 ;
    END
  END rd_out[107]
  PIN rd_out[108]
    DIRECTION OUTPUT ;
    USE SIGNAL ;
    SHAPE ABUTMENT ;
    PORT
      LAYER metal3 ;
      RECT 0.000 211.645 0.070 211.715 ;
    END
  END rd_out[108]
  PIN rd_out[109]
    DIRECTION OUTPUT ;
    USE SIGNAL ;
    SHAPE ABUTMENT ;
    PORT
      LAYER metal3 ;
      RECT 0.000 211.925 0.070 211.995 ;
    END
  END rd_out[109]
  PIN rd_out[110]
    DIRECTION OUTPUT ;
    USE SIGNAL ;
    SHAPE ABUTMENT ;
    PORT
      LAYER metal3 ;
      RECT 0.000 212.205 0.070 212.275 ;
    END
  END rd_out[110]
  PIN rd_out[111]
    DIRECTION OUTPUT ;
    USE SIGNAL ;
    SHAPE ABUTMENT ;
    PORT
      LAYER metal3 ;
      RECT 0.000 212.485 0.070 212.555 ;
    END
  END rd_out[111]
  PIN rd_out[112]
    DIRECTION OUTPUT ;
    USE SIGNAL ;
    SHAPE ABUTMENT ;
    PORT
      LAYER metal3 ;
      RECT 0.000 212.765 0.070 212.835 ;
    END
  END rd_out[112]
  PIN rd_out[113]
    DIRECTION OUTPUT ;
    USE SIGNAL ;
    SHAPE ABUTMENT ;
    PORT
      LAYER metal3 ;
      RECT 0.000 213.045 0.070 213.115 ;
    END
  END rd_out[113]
  PIN rd_out[114]
    DIRECTION OUTPUT ;
    USE SIGNAL ;
    SHAPE ABUTMENT ;
    PORT
      LAYER metal3 ;
      RECT 0.000 213.325 0.070 213.395 ;
    END
  END rd_out[114]
  PIN rd_out[115]
    DIRECTION OUTPUT ;
    USE SIGNAL ;
    SHAPE ABUTMENT ;
    PORT
      LAYER metal3 ;
      RECT 0.000 213.605 0.070 213.675 ;
    END
  END rd_out[115]
  PIN rd_out[116]
    DIRECTION OUTPUT ;
    USE SIGNAL ;
    SHAPE ABUTMENT ;
    PORT
      LAYER metal3 ;
      RECT 0.000 213.885 0.070 213.955 ;
    END
  END rd_out[116]
  PIN rd_out[117]
    DIRECTION OUTPUT ;
    USE SIGNAL ;
    SHAPE ABUTMENT ;
    PORT
      LAYER metal3 ;
      RECT 0.000 214.165 0.070 214.235 ;
    END
  END rd_out[117]
  PIN rd_out[118]
    DIRECTION OUTPUT ;
    USE SIGNAL ;
    SHAPE ABUTMENT ;
    PORT
      LAYER metal3 ;
      RECT 0.000 214.445 0.070 214.515 ;
    END
  END rd_out[118]
  PIN rd_out[119]
    DIRECTION OUTPUT ;
    USE SIGNAL ;
    SHAPE ABUTMENT ;
    PORT
      LAYER metal3 ;
      RECT 0.000 214.725 0.070 214.795 ;
    END
  END rd_out[119]
  PIN rd_out[120]
    DIRECTION OUTPUT ;
    USE SIGNAL ;
    SHAPE ABUTMENT ;
    PORT
      LAYER metal3 ;
      RECT 0.000 215.005 0.070 215.075 ;
    END
  END rd_out[120]
  PIN rd_out[121]
    DIRECTION OUTPUT ;
    USE SIGNAL ;
    SHAPE ABUTMENT ;
    PORT
      LAYER metal3 ;
      RECT 0.000 215.285 0.070 215.355 ;
    END
  END rd_out[121]
  PIN rd_out[122]
    DIRECTION OUTPUT ;
    USE SIGNAL ;
    SHAPE ABUTMENT ;
    PORT
      LAYER metal3 ;
      RECT 0.000 215.565 0.070 215.635 ;
    END
  END rd_out[122]
  PIN rd_out[123]
    DIRECTION OUTPUT ;
    USE SIGNAL ;
    SHAPE ABUTMENT ;
    PORT
      LAYER metal3 ;
      RECT 0.000 215.845 0.070 215.915 ;
    END
  END rd_out[123]
  PIN rd_out[124]
    DIRECTION OUTPUT ;
    USE SIGNAL ;
    SHAPE ABUTMENT ;
    PORT
      LAYER metal3 ;
      RECT 0.000 216.125 0.070 216.195 ;
    END
  END rd_out[124]
  PIN rd_out[125]
    DIRECTION OUTPUT ;
    USE SIGNAL ;
    SHAPE ABUTMENT ;
    PORT
      LAYER metal3 ;
      RECT 0.000 216.405 0.070 216.475 ;
    END
  END rd_out[125]
  PIN rd_out[126]
    DIRECTION OUTPUT ;
    USE SIGNAL ;
    SHAPE ABUTMENT ;
    PORT
      LAYER metal3 ;
      RECT 0.000 216.685 0.070 216.755 ;
    END
  END rd_out[126]
  PIN rd_out[127]
    DIRECTION OUTPUT ;
    USE SIGNAL ;
    SHAPE ABUTMENT ;
    PORT
      LAYER metal3 ;
      RECT 0.000 216.965 0.070 217.035 ;
    END
  END rd_out[127]
  PIN rd_out[128]
    DIRECTION OUTPUT ;
    USE SIGNAL ;
    SHAPE ABUTMENT ;
    PORT
      LAYER metal3 ;
      RECT 0.000 217.245 0.070 217.315 ;
    END
  END rd_out[128]
  PIN rd_out[129]
    DIRECTION OUTPUT ;
    USE SIGNAL ;
    SHAPE ABUTMENT ;
    PORT
      LAYER metal3 ;
      RECT 0.000 217.525 0.070 217.595 ;
    END
  END rd_out[129]
  PIN rd_out[130]
    DIRECTION OUTPUT ;
    USE SIGNAL ;
    SHAPE ABUTMENT ;
    PORT
      LAYER metal3 ;
      RECT 0.000 217.805 0.070 217.875 ;
    END
  END rd_out[130]
  PIN rd_out[131]
    DIRECTION OUTPUT ;
    USE SIGNAL ;
    SHAPE ABUTMENT ;
    PORT
      LAYER metal3 ;
      RECT 0.000 218.085 0.070 218.155 ;
    END
  END rd_out[131]
  PIN rd_out[132]
    DIRECTION OUTPUT ;
    USE SIGNAL ;
    SHAPE ABUTMENT ;
    PORT
      LAYER metal3 ;
      RECT 0.000 218.365 0.070 218.435 ;
    END
  END rd_out[132]
  PIN rd_out[133]
    DIRECTION OUTPUT ;
    USE SIGNAL ;
    SHAPE ABUTMENT ;
    PORT
      LAYER metal3 ;
      RECT 0.000 218.645 0.070 218.715 ;
    END
  END rd_out[133]
  PIN rd_out[134]
    DIRECTION OUTPUT ;
    USE SIGNAL ;
    SHAPE ABUTMENT ;
    PORT
      LAYER metal3 ;
      RECT 0.000 218.925 0.070 218.995 ;
    END
  END rd_out[134]
  PIN rd_out[135]
    DIRECTION OUTPUT ;
    USE SIGNAL ;
    SHAPE ABUTMENT ;
    PORT
      LAYER metal3 ;
      RECT 0.000 219.205 0.070 219.275 ;
    END
  END rd_out[135]
  PIN rd_out[136]
    DIRECTION OUTPUT ;
    USE SIGNAL ;
    SHAPE ABUTMENT ;
    PORT
      LAYER metal3 ;
      RECT 0.000 219.485 0.070 219.555 ;
    END
  END rd_out[136]
  PIN rd_out[137]
    DIRECTION OUTPUT ;
    USE SIGNAL ;
    SHAPE ABUTMENT ;
    PORT
      LAYER metal3 ;
      RECT 0.000 219.765 0.070 219.835 ;
    END
  END rd_out[137]
  PIN rd_out[138]
    DIRECTION OUTPUT ;
    USE SIGNAL ;
    SHAPE ABUTMENT ;
    PORT
      LAYER metal3 ;
      RECT 0.000 220.045 0.070 220.115 ;
    END
  END rd_out[138]
  PIN rd_out[139]
    DIRECTION OUTPUT ;
    USE SIGNAL ;
    SHAPE ABUTMENT ;
    PORT
      LAYER metal3 ;
      RECT 0.000 220.325 0.070 220.395 ;
    END
  END rd_out[139]
  PIN rd_out[140]
    DIRECTION OUTPUT ;
    USE SIGNAL ;
    SHAPE ABUTMENT ;
    PORT
      LAYER metal3 ;
      RECT 0.000 220.605 0.070 220.675 ;
    END
  END rd_out[140]
  PIN rd_out[141]
    DIRECTION OUTPUT ;
    USE SIGNAL ;
    SHAPE ABUTMENT ;
    PORT
      LAYER metal3 ;
      RECT 0.000 220.885 0.070 220.955 ;
    END
  END rd_out[141]
  PIN rd_out[142]
    DIRECTION OUTPUT ;
    USE SIGNAL ;
    SHAPE ABUTMENT ;
    PORT
      LAYER metal3 ;
      RECT 0.000 221.165 0.070 221.235 ;
    END
  END rd_out[142]
  PIN rd_out[143]
    DIRECTION OUTPUT ;
    USE SIGNAL ;
    SHAPE ABUTMENT ;
    PORT
      LAYER metal3 ;
      RECT 0.000 221.445 0.070 221.515 ;
    END
  END rd_out[143]
  PIN rd_out[144]
    DIRECTION OUTPUT ;
    USE SIGNAL ;
    SHAPE ABUTMENT ;
    PORT
      LAYER metal3 ;
      RECT 0.000 221.725 0.070 221.795 ;
    END
  END rd_out[144]
  PIN rd_out[145]
    DIRECTION OUTPUT ;
    USE SIGNAL ;
    SHAPE ABUTMENT ;
    PORT
      LAYER metal3 ;
      RECT 0.000 222.005 0.070 222.075 ;
    END
  END rd_out[145]
  PIN rd_out[146]
    DIRECTION OUTPUT ;
    USE SIGNAL ;
    SHAPE ABUTMENT ;
    PORT
      LAYER metal3 ;
      RECT 0.000 222.285 0.070 222.355 ;
    END
  END rd_out[146]
  PIN rd_out[147]
    DIRECTION OUTPUT ;
    USE SIGNAL ;
    SHAPE ABUTMENT ;
    PORT
      LAYER metal3 ;
      RECT 0.000 222.565 0.070 222.635 ;
    END
  END rd_out[147]
  PIN rd_out[148]
    DIRECTION OUTPUT ;
    USE SIGNAL ;
    SHAPE ABUTMENT ;
    PORT
      LAYER metal3 ;
      RECT 0.000 222.845 0.070 222.915 ;
    END
  END rd_out[148]
  PIN rd_out[149]
    DIRECTION OUTPUT ;
    USE SIGNAL ;
    SHAPE ABUTMENT ;
    PORT
      LAYER metal3 ;
      RECT 0.000 223.125 0.070 223.195 ;
    END
  END rd_out[149]
  PIN rd_out[150]
    DIRECTION OUTPUT ;
    USE SIGNAL ;
    SHAPE ABUTMENT ;
    PORT
      LAYER metal3 ;
      RECT 0.000 223.405 0.070 223.475 ;
    END
  END rd_out[150]
  PIN rd_out[151]
    DIRECTION OUTPUT ;
    USE SIGNAL ;
    SHAPE ABUTMENT ;
    PORT
      LAYER metal3 ;
      RECT 0.000 223.685 0.070 223.755 ;
    END
  END rd_out[151]
  PIN rd_out[152]
    DIRECTION OUTPUT ;
    USE SIGNAL ;
    SHAPE ABUTMENT ;
    PORT
      LAYER metal3 ;
      RECT 0.000 223.965 0.070 224.035 ;
    END
  END rd_out[152]
  PIN rd_out[153]
    DIRECTION OUTPUT ;
    USE SIGNAL ;
    SHAPE ABUTMENT ;
    PORT
      LAYER metal3 ;
      RECT 0.000 224.245 0.070 224.315 ;
    END
  END rd_out[153]
  PIN rd_out[154]
    DIRECTION OUTPUT ;
    USE SIGNAL ;
    SHAPE ABUTMENT ;
    PORT
      LAYER metal3 ;
      RECT 0.000 224.525 0.070 224.595 ;
    END
  END rd_out[154]
  PIN rd_out[155]
    DIRECTION OUTPUT ;
    USE SIGNAL ;
    SHAPE ABUTMENT ;
    PORT
      LAYER metal3 ;
      RECT 0.000 224.805 0.070 224.875 ;
    END
  END rd_out[155]
  PIN rd_out[156]
    DIRECTION OUTPUT ;
    USE SIGNAL ;
    SHAPE ABUTMENT ;
    PORT
      LAYER metal3 ;
      RECT 0.000 225.085 0.070 225.155 ;
    END
  END rd_out[156]
  PIN rd_out[157]
    DIRECTION OUTPUT ;
    USE SIGNAL ;
    SHAPE ABUTMENT ;
    PORT
      LAYER metal3 ;
      RECT 0.000 225.365 0.070 225.435 ;
    END
  END rd_out[157]
  PIN rd_out[158]
    DIRECTION OUTPUT ;
    USE SIGNAL ;
    SHAPE ABUTMENT ;
    PORT
      LAYER metal3 ;
      RECT 0.000 225.645 0.070 225.715 ;
    END
  END rd_out[158]
  PIN rd_out[159]
    DIRECTION OUTPUT ;
    USE SIGNAL ;
    SHAPE ABUTMENT ;
    PORT
      LAYER metal3 ;
      RECT 0.000 225.925 0.070 225.995 ;
    END
  END rd_out[159]
  PIN rd_out[160]
    DIRECTION OUTPUT ;
    USE SIGNAL ;
    SHAPE ABUTMENT ;
    PORT
      LAYER metal3 ;
      RECT 0.000 226.205 0.070 226.275 ;
    END
  END rd_out[160]
  PIN rd_out[161]
    DIRECTION OUTPUT ;
    USE SIGNAL ;
    SHAPE ABUTMENT ;
    PORT
      LAYER metal3 ;
      RECT 0.000 226.485 0.070 226.555 ;
    END
  END rd_out[161]
  PIN rd_out[162]
    DIRECTION OUTPUT ;
    USE SIGNAL ;
    SHAPE ABUTMENT ;
    PORT
      LAYER metal3 ;
      RECT 0.000 226.765 0.070 226.835 ;
    END
  END rd_out[162]
  PIN rd_out[163]
    DIRECTION OUTPUT ;
    USE SIGNAL ;
    SHAPE ABUTMENT ;
    PORT
      LAYER metal3 ;
      RECT 0.000 227.045 0.070 227.115 ;
    END
  END rd_out[163]
  PIN rd_out[164]
    DIRECTION OUTPUT ;
    USE SIGNAL ;
    SHAPE ABUTMENT ;
    PORT
      LAYER metal3 ;
      RECT 0.000 227.325 0.070 227.395 ;
    END
  END rd_out[164]
  PIN rd_out[165]
    DIRECTION OUTPUT ;
    USE SIGNAL ;
    SHAPE ABUTMENT ;
    PORT
      LAYER metal3 ;
      RECT 0.000 227.605 0.070 227.675 ;
    END
  END rd_out[165]
  PIN rd_out[166]
    DIRECTION OUTPUT ;
    USE SIGNAL ;
    SHAPE ABUTMENT ;
    PORT
      LAYER metal3 ;
      RECT 0.000 227.885 0.070 227.955 ;
    END
  END rd_out[166]
  PIN rd_out[167]
    DIRECTION OUTPUT ;
    USE SIGNAL ;
    SHAPE ABUTMENT ;
    PORT
      LAYER metal3 ;
      RECT 0.000 228.165 0.070 228.235 ;
    END
  END rd_out[167]
  PIN rd_out[168]
    DIRECTION OUTPUT ;
    USE SIGNAL ;
    SHAPE ABUTMENT ;
    PORT
      LAYER metal3 ;
      RECT 0.000 228.445 0.070 228.515 ;
    END
  END rd_out[168]
  PIN rd_out[169]
    DIRECTION OUTPUT ;
    USE SIGNAL ;
    SHAPE ABUTMENT ;
    PORT
      LAYER metal3 ;
      RECT 0.000 228.725 0.070 228.795 ;
    END
  END rd_out[169]
  PIN rd_out[170]
    DIRECTION OUTPUT ;
    USE SIGNAL ;
    SHAPE ABUTMENT ;
    PORT
      LAYER metal3 ;
      RECT 0.000 229.005 0.070 229.075 ;
    END
  END rd_out[170]
  PIN rd_out[171]
    DIRECTION OUTPUT ;
    USE SIGNAL ;
    SHAPE ABUTMENT ;
    PORT
      LAYER metal3 ;
      RECT 0.000 229.285 0.070 229.355 ;
    END
  END rd_out[171]
  PIN rd_out[172]
    DIRECTION OUTPUT ;
    USE SIGNAL ;
    SHAPE ABUTMENT ;
    PORT
      LAYER metal3 ;
      RECT 0.000 229.565 0.070 229.635 ;
    END
  END rd_out[172]
  PIN rd_out[173]
    DIRECTION OUTPUT ;
    USE SIGNAL ;
    SHAPE ABUTMENT ;
    PORT
      LAYER metal3 ;
      RECT 0.000 229.845 0.070 229.915 ;
    END
  END rd_out[173]
  PIN rd_out[174]
    DIRECTION OUTPUT ;
    USE SIGNAL ;
    SHAPE ABUTMENT ;
    PORT
      LAYER metal3 ;
      RECT 0.000 230.125 0.070 230.195 ;
    END
  END rd_out[174]
  PIN rd_out[175]
    DIRECTION OUTPUT ;
    USE SIGNAL ;
    SHAPE ABUTMENT ;
    PORT
      LAYER metal3 ;
      RECT 0.000 230.405 0.070 230.475 ;
    END
  END rd_out[175]
  PIN rd_out[176]
    DIRECTION OUTPUT ;
    USE SIGNAL ;
    SHAPE ABUTMENT ;
    PORT
      LAYER metal3 ;
      RECT 0.000 230.685 0.070 230.755 ;
    END
  END rd_out[176]
  PIN rd_out[177]
    DIRECTION OUTPUT ;
    USE SIGNAL ;
    SHAPE ABUTMENT ;
    PORT
      LAYER metal3 ;
      RECT 0.000 230.965 0.070 231.035 ;
    END
  END rd_out[177]
  PIN rd_out[178]
    DIRECTION OUTPUT ;
    USE SIGNAL ;
    SHAPE ABUTMENT ;
    PORT
      LAYER metal3 ;
      RECT 0.000 231.245 0.070 231.315 ;
    END
  END rd_out[178]
  PIN rd_out[179]
    DIRECTION OUTPUT ;
    USE SIGNAL ;
    SHAPE ABUTMENT ;
    PORT
      LAYER metal3 ;
      RECT 0.000 231.525 0.070 231.595 ;
    END
  END rd_out[179]
  PIN rd_out[180]
    DIRECTION OUTPUT ;
    USE SIGNAL ;
    SHAPE ABUTMENT ;
    PORT
      LAYER metal3 ;
      RECT 0.000 231.805 0.070 231.875 ;
    END
  END rd_out[180]
  PIN rd_out[181]
    DIRECTION OUTPUT ;
    USE SIGNAL ;
    SHAPE ABUTMENT ;
    PORT
      LAYER metal3 ;
      RECT 0.000 232.085 0.070 232.155 ;
    END
  END rd_out[181]
  PIN rd_out[182]
    DIRECTION OUTPUT ;
    USE SIGNAL ;
    SHAPE ABUTMENT ;
    PORT
      LAYER metal3 ;
      RECT 0.000 232.365 0.070 232.435 ;
    END
  END rd_out[182]
  PIN rd_out[183]
    DIRECTION OUTPUT ;
    USE SIGNAL ;
    SHAPE ABUTMENT ;
    PORT
      LAYER metal3 ;
      RECT 0.000 232.645 0.070 232.715 ;
    END
  END rd_out[183]
  PIN rd_out[184]
    DIRECTION OUTPUT ;
    USE SIGNAL ;
    SHAPE ABUTMENT ;
    PORT
      LAYER metal3 ;
      RECT 0.000 232.925 0.070 232.995 ;
    END
  END rd_out[184]
  PIN rd_out[185]
    DIRECTION OUTPUT ;
    USE SIGNAL ;
    SHAPE ABUTMENT ;
    PORT
      LAYER metal3 ;
      RECT 0.000 233.205 0.070 233.275 ;
    END
  END rd_out[185]
  PIN rd_out[186]
    DIRECTION OUTPUT ;
    USE SIGNAL ;
    SHAPE ABUTMENT ;
    PORT
      LAYER metal3 ;
      RECT 0.000 233.485 0.070 233.555 ;
    END
  END rd_out[186]
  PIN rd_out[187]
    DIRECTION OUTPUT ;
    USE SIGNAL ;
    SHAPE ABUTMENT ;
    PORT
      LAYER metal3 ;
      RECT 0.000 233.765 0.070 233.835 ;
    END
  END rd_out[187]
  PIN rd_out[188]
    DIRECTION OUTPUT ;
    USE SIGNAL ;
    SHAPE ABUTMENT ;
    PORT
      LAYER metal3 ;
      RECT 0.000 234.045 0.070 234.115 ;
    END
  END rd_out[188]
  PIN rd_out[189]
    DIRECTION OUTPUT ;
    USE SIGNAL ;
    SHAPE ABUTMENT ;
    PORT
      LAYER metal3 ;
      RECT 0.000 234.325 0.070 234.395 ;
    END
  END rd_out[189]
  PIN rd_out[190]
    DIRECTION OUTPUT ;
    USE SIGNAL ;
    SHAPE ABUTMENT ;
    PORT
      LAYER metal3 ;
      RECT 0.000 234.605 0.070 234.675 ;
    END
  END rd_out[190]
  PIN rd_out[191]
    DIRECTION OUTPUT ;
    USE SIGNAL ;
    SHAPE ABUTMENT ;
    PORT
      LAYER metal3 ;
      RECT 0.000 234.885 0.070 234.955 ;
    END
  END rd_out[191]
  PIN rd_out[192]
    DIRECTION OUTPUT ;
    USE SIGNAL ;
    SHAPE ABUTMENT ;
    PORT
      LAYER metal3 ;
      RECT 0.000 235.165 0.070 235.235 ;
    END
  END rd_out[192]
  PIN rd_out[193]
    DIRECTION OUTPUT ;
    USE SIGNAL ;
    SHAPE ABUTMENT ;
    PORT
      LAYER metal3 ;
      RECT 0.000 235.445 0.070 235.515 ;
    END
  END rd_out[193]
  PIN rd_out[194]
    DIRECTION OUTPUT ;
    USE SIGNAL ;
    SHAPE ABUTMENT ;
    PORT
      LAYER metal3 ;
      RECT 0.000 235.725 0.070 235.795 ;
    END
  END rd_out[194]
  PIN rd_out[195]
    DIRECTION OUTPUT ;
    USE SIGNAL ;
    SHAPE ABUTMENT ;
    PORT
      LAYER metal3 ;
      RECT 0.000 236.005 0.070 236.075 ;
    END
  END rd_out[195]
  PIN rd_out[196]
    DIRECTION OUTPUT ;
    USE SIGNAL ;
    SHAPE ABUTMENT ;
    PORT
      LAYER metal3 ;
      RECT 0.000 236.285 0.070 236.355 ;
    END
  END rd_out[196]
  PIN rd_out[197]
    DIRECTION OUTPUT ;
    USE SIGNAL ;
    SHAPE ABUTMENT ;
    PORT
      LAYER metal3 ;
      RECT 0.000 236.565 0.070 236.635 ;
    END
  END rd_out[197]
  PIN rd_out[198]
    DIRECTION OUTPUT ;
    USE SIGNAL ;
    SHAPE ABUTMENT ;
    PORT
      LAYER metal3 ;
      RECT 0.000 236.845 0.070 236.915 ;
    END
  END rd_out[198]
  PIN rd_out[199]
    DIRECTION OUTPUT ;
    USE SIGNAL ;
    SHAPE ABUTMENT ;
    PORT
      LAYER metal3 ;
      RECT 0.000 237.125 0.070 237.195 ;
    END
  END rd_out[199]
  PIN rd_out[200]
    DIRECTION OUTPUT ;
    USE SIGNAL ;
    SHAPE ABUTMENT ;
    PORT
      LAYER metal3 ;
      RECT 0.000 237.405 0.070 237.475 ;
    END
  END rd_out[200]
  PIN rd_out[201]
    DIRECTION OUTPUT ;
    USE SIGNAL ;
    SHAPE ABUTMENT ;
    PORT
      LAYER metal3 ;
      RECT 0.000 237.685 0.070 237.755 ;
    END
  END rd_out[201]
  PIN rd_out[202]
    DIRECTION OUTPUT ;
    USE SIGNAL ;
    SHAPE ABUTMENT ;
    PORT
      LAYER metal3 ;
      RECT 0.000 237.965 0.070 238.035 ;
    END
  END rd_out[202]
  PIN rd_out[203]
    DIRECTION OUTPUT ;
    USE SIGNAL ;
    SHAPE ABUTMENT ;
    PORT
      LAYER metal3 ;
      RECT 0.000 238.245 0.070 238.315 ;
    END
  END rd_out[203]
  PIN rd_out[204]
    DIRECTION OUTPUT ;
    USE SIGNAL ;
    SHAPE ABUTMENT ;
    PORT
      LAYER metal3 ;
      RECT 0.000 238.525 0.070 238.595 ;
    END
  END rd_out[204]
  PIN rd_out[205]
    DIRECTION OUTPUT ;
    USE SIGNAL ;
    SHAPE ABUTMENT ;
    PORT
      LAYER metal3 ;
      RECT 0.000 238.805 0.070 238.875 ;
    END
  END rd_out[205]
  PIN rd_out[206]
    DIRECTION OUTPUT ;
    USE SIGNAL ;
    SHAPE ABUTMENT ;
    PORT
      LAYER metal3 ;
      RECT 0.000 239.085 0.070 239.155 ;
    END
  END rd_out[206]
  PIN rd_out[207]
    DIRECTION OUTPUT ;
    USE SIGNAL ;
    SHAPE ABUTMENT ;
    PORT
      LAYER metal3 ;
      RECT 0.000 239.365 0.070 239.435 ;
    END
  END rd_out[207]
  PIN rd_out[208]
    DIRECTION OUTPUT ;
    USE SIGNAL ;
    SHAPE ABUTMENT ;
    PORT
      LAYER metal3 ;
      RECT 0.000 239.645 0.070 239.715 ;
    END
  END rd_out[208]
  PIN rd_out[209]
    DIRECTION OUTPUT ;
    USE SIGNAL ;
    SHAPE ABUTMENT ;
    PORT
      LAYER metal3 ;
      RECT 0.000 239.925 0.070 239.995 ;
    END
  END rd_out[209]
  PIN rd_out[210]
    DIRECTION OUTPUT ;
    USE SIGNAL ;
    SHAPE ABUTMENT ;
    PORT
      LAYER metal3 ;
      RECT 0.000 240.205 0.070 240.275 ;
    END
  END rd_out[210]
  PIN rd_out[211]
    DIRECTION OUTPUT ;
    USE SIGNAL ;
    SHAPE ABUTMENT ;
    PORT
      LAYER metal3 ;
      RECT 0.000 240.485 0.070 240.555 ;
    END
  END rd_out[211]
  PIN rd_out[212]
    DIRECTION OUTPUT ;
    USE SIGNAL ;
    SHAPE ABUTMENT ;
    PORT
      LAYER metal3 ;
      RECT 0.000 240.765 0.070 240.835 ;
    END
  END rd_out[212]
  PIN rd_out[213]
    DIRECTION OUTPUT ;
    USE SIGNAL ;
    SHAPE ABUTMENT ;
    PORT
      LAYER metal3 ;
      RECT 0.000 241.045 0.070 241.115 ;
    END
  END rd_out[213]
  PIN rd_out[214]
    DIRECTION OUTPUT ;
    USE SIGNAL ;
    SHAPE ABUTMENT ;
    PORT
      LAYER metal3 ;
      RECT 0.000 241.325 0.070 241.395 ;
    END
  END rd_out[214]
  PIN rd_out[215]
    DIRECTION OUTPUT ;
    USE SIGNAL ;
    SHAPE ABUTMENT ;
    PORT
      LAYER metal3 ;
      RECT 0.000 241.605 0.070 241.675 ;
    END
  END rd_out[215]
  PIN rd_out[216]
    DIRECTION OUTPUT ;
    USE SIGNAL ;
    SHAPE ABUTMENT ;
    PORT
      LAYER metal3 ;
      RECT 0.000 241.885 0.070 241.955 ;
    END
  END rd_out[216]
  PIN rd_out[217]
    DIRECTION OUTPUT ;
    USE SIGNAL ;
    SHAPE ABUTMENT ;
    PORT
      LAYER metal3 ;
      RECT 0.000 242.165 0.070 242.235 ;
    END
  END rd_out[217]
  PIN rd_out[218]
    DIRECTION OUTPUT ;
    USE SIGNAL ;
    SHAPE ABUTMENT ;
    PORT
      LAYER metal3 ;
      RECT 0.000 242.445 0.070 242.515 ;
    END
  END rd_out[218]
  PIN rd_out[219]
    DIRECTION OUTPUT ;
    USE SIGNAL ;
    SHAPE ABUTMENT ;
    PORT
      LAYER metal3 ;
      RECT 0.000 242.725 0.070 242.795 ;
    END
  END rd_out[219]
  PIN rd_out[220]
    DIRECTION OUTPUT ;
    USE SIGNAL ;
    SHAPE ABUTMENT ;
    PORT
      LAYER metal3 ;
      RECT 0.000 243.005 0.070 243.075 ;
    END
  END rd_out[220]
  PIN rd_out[221]
    DIRECTION OUTPUT ;
    USE SIGNAL ;
    SHAPE ABUTMENT ;
    PORT
      LAYER metal3 ;
      RECT 0.000 243.285 0.070 243.355 ;
    END
  END rd_out[221]
  PIN rd_out[222]
    DIRECTION OUTPUT ;
    USE SIGNAL ;
    SHAPE ABUTMENT ;
    PORT
      LAYER metal3 ;
      RECT 0.000 243.565 0.070 243.635 ;
    END
  END rd_out[222]
  PIN rd_out[223]
    DIRECTION OUTPUT ;
    USE SIGNAL ;
    SHAPE ABUTMENT ;
    PORT
      LAYER metal3 ;
      RECT 0.000 243.845 0.070 243.915 ;
    END
  END rd_out[223]
  PIN rd_out[224]
    DIRECTION OUTPUT ;
    USE SIGNAL ;
    SHAPE ABUTMENT ;
    PORT
      LAYER metal3 ;
      RECT 0.000 244.125 0.070 244.195 ;
    END
  END rd_out[224]
  PIN rd_out[225]
    DIRECTION OUTPUT ;
    USE SIGNAL ;
    SHAPE ABUTMENT ;
    PORT
      LAYER metal3 ;
      RECT 0.000 244.405 0.070 244.475 ;
    END
  END rd_out[225]
  PIN rd_out[226]
    DIRECTION OUTPUT ;
    USE SIGNAL ;
    SHAPE ABUTMENT ;
    PORT
      LAYER metal3 ;
      RECT 0.000 244.685 0.070 244.755 ;
    END
  END rd_out[226]
  PIN rd_out[227]
    DIRECTION OUTPUT ;
    USE SIGNAL ;
    SHAPE ABUTMENT ;
    PORT
      LAYER metal3 ;
      RECT 0.000 244.965 0.070 245.035 ;
    END
  END rd_out[227]
  PIN rd_out[228]
    DIRECTION OUTPUT ;
    USE SIGNAL ;
    SHAPE ABUTMENT ;
    PORT
      LAYER metal3 ;
      RECT 0.000 245.245 0.070 245.315 ;
    END
  END rd_out[228]
  PIN rd_out[229]
    DIRECTION OUTPUT ;
    USE SIGNAL ;
    SHAPE ABUTMENT ;
    PORT
      LAYER metal3 ;
      RECT 0.000 245.525 0.070 245.595 ;
    END
  END rd_out[229]
  PIN rd_out[230]
    DIRECTION OUTPUT ;
    USE SIGNAL ;
    SHAPE ABUTMENT ;
    PORT
      LAYER metal3 ;
      RECT 0.000 245.805 0.070 245.875 ;
    END
  END rd_out[230]
  PIN rd_out[231]
    DIRECTION OUTPUT ;
    USE SIGNAL ;
    SHAPE ABUTMENT ;
    PORT
      LAYER metal3 ;
      RECT 0.000 246.085 0.070 246.155 ;
    END
  END rd_out[231]
  PIN rd_out[232]
    DIRECTION OUTPUT ;
    USE SIGNAL ;
    SHAPE ABUTMENT ;
    PORT
      LAYER metal3 ;
      RECT 0.000 246.365 0.070 246.435 ;
    END
  END rd_out[232]
  PIN rd_out[233]
    DIRECTION OUTPUT ;
    USE SIGNAL ;
    SHAPE ABUTMENT ;
    PORT
      LAYER metal3 ;
      RECT 0.000 246.645 0.070 246.715 ;
    END
  END rd_out[233]
  PIN rd_out[234]
    DIRECTION OUTPUT ;
    USE SIGNAL ;
    SHAPE ABUTMENT ;
    PORT
      LAYER metal3 ;
      RECT 0.000 246.925 0.070 246.995 ;
    END
  END rd_out[234]
  PIN rd_out[235]
    DIRECTION OUTPUT ;
    USE SIGNAL ;
    SHAPE ABUTMENT ;
    PORT
      LAYER metal3 ;
      RECT 0.000 247.205 0.070 247.275 ;
    END
  END rd_out[235]
  PIN rd_out[236]
    DIRECTION OUTPUT ;
    USE SIGNAL ;
    SHAPE ABUTMENT ;
    PORT
      LAYER metal3 ;
      RECT 0.000 247.485 0.070 247.555 ;
    END
  END rd_out[236]
  PIN rd_out[237]
    DIRECTION OUTPUT ;
    USE SIGNAL ;
    SHAPE ABUTMENT ;
    PORT
      LAYER metal3 ;
      RECT 0.000 247.765 0.070 247.835 ;
    END
  END rd_out[237]
  PIN rd_out[238]
    DIRECTION OUTPUT ;
    USE SIGNAL ;
    SHAPE ABUTMENT ;
    PORT
      LAYER metal3 ;
      RECT 0.000 248.045 0.070 248.115 ;
    END
  END rd_out[238]
  PIN rd_out[239]
    DIRECTION OUTPUT ;
    USE SIGNAL ;
    SHAPE ABUTMENT ;
    PORT
      LAYER metal3 ;
      RECT 0.000 248.325 0.070 248.395 ;
    END
  END rd_out[239]
  PIN rd_out[240]
    DIRECTION OUTPUT ;
    USE SIGNAL ;
    SHAPE ABUTMENT ;
    PORT
      LAYER metal3 ;
      RECT 0.000 248.605 0.070 248.675 ;
    END
  END rd_out[240]
  PIN rd_out[241]
    DIRECTION OUTPUT ;
    USE SIGNAL ;
    SHAPE ABUTMENT ;
    PORT
      LAYER metal3 ;
      RECT 0.000 248.885 0.070 248.955 ;
    END
  END rd_out[241]
  PIN rd_out[242]
    DIRECTION OUTPUT ;
    USE SIGNAL ;
    SHAPE ABUTMENT ;
    PORT
      LAYER metal3 ;
      RECT 0.000 249.165 0.070 249.235 ;
    END
  END rd_out[242]
  PIN rd_out[243]
    DIRECTION OUTPUT ;
    USE SIGNAL ;
    SHAPE ABUTMENT ;
    PORT
      LAYER metal3 ;
      RECT 0.000 249.445 0.070 249.515 ;
    END
  END rd_out[243]
  PIN rd_out[244]
    DIRECTION OUTPUT ;
    USE SIGNAL ;
    SHAPE ABUTMENT ;
    PORT
      LAYER metal3 ;
      RECT 0.000 249.725 0.070 249.795 ;
    END
  END rd_out[244]
  PIN rd_out[245]
    DIRECTION OUTPUT ;
    USE SIGNAL ;
    SHAPE ABUTMENT ;
    PORT
      LAYER metal3 ;
      RECT 0.000 250.005 0.070 250.075 ;
    END
  END rd_out[245]
  PIN rd_out[246]
    DIRECTION OUTPUT ;
    USE SIGNAL ;
    SHAPE ABUTMENT ;
    PORT
      LAYER metal3 ;
      RECT 0.000 250.285 0.070 250.355 ;
    END
  END rd_out[246]
  PIN rd_out[247]
    DIRECTION OUTPUT ;
    USE SIGNAL ;
    SHAPE ABUTMENT ;
    PORT
      LAYER metal3 ;
      RECT 0.000 250.565 0.070 250.635 ;
    END
  END rd_out[247]
  PIN rd_out[248]
    DIRECTION OUTPUT ;
    USE SIGNAL ;
    SHAPE ABUTMENT ;
    PORT
      LAYER metal3 ;
      RECT 0.000 250.845 0.070 250.915 ;
    END
  END rd_out[248]
  PIN rd_out[249]
    DIRECTION OUTPUT ;
    USE SIGNAL ;
    SHAPE ABUTMENT ;
    PORT
      LAYER metal3 ;
      RECT 0.000 251.125 0.070 251.195 ;
    END
  END rd_out[249]
  PIN rd_out[250]
    DIRECTION OUTPUT ;
    USE SIGNAL ;
    SHAPE ABUTMENT ;
    PORT
      LAYER metal3 ;
      RECT 0.000 251.405 0.070 251.475 ;
    END
  END rd_out[250]
  PIN rd_out[251]
    DIRECTION OUTPUT ;
    USE SIGNAL ;
    SHAPE ABUTMENT ;
    PORT
      LAYER metal3 ;
      RECT 0.000 251.685 0.070 251.755 ;
    END
  END rd_out[251]
  PIN rd_out[252]
    DIRECTION OUTPUT ;
    USE SIGNAL ;
    SHAPE ABUTMENT ;
    PORT
      LAYER metal3 ;
      RECT 0.000 251.965 0.070 252.035 ;
    END
  END rd_out[252]
  PIN rd_out[253]
    DIRECTION OUTPUT ;
    USE SIGNAL ;
    SHAPE ABUTMENT ;
    PORT
      LAYER metal3 ;
      RECT 0.000 252.245 0.070 252.315 ;
    END
  END rd_out[253]
  PIN rd_out[254]
    DIRECTION OUTPUT ;
    USE SIGNAL ;
    SHAPE ABUTMENT ;
    PORT
      LAYER metal3 ;
      RECT 0.000 252.525 0.070 252.595 ;
    END
  END rd_out[254]
  PIN rd_out[255]
    DIRECTION OUTPUT ;
    USE SIGNAL ;
    SHAPE ABUTMENT ;
    PORT
      LAYER metal3 ;
      RECT 0.000 252.805 0.070 252.875 ;
    END
  END rd_out[255]
  PIN rd_out[256]
    DIRECTION OUTPUT ;
    USE SIGNAL ;
    SHAPE ABUTMENT ;
    PORT
      LAYER metal3 ;
      RECT 0.000 253.085 0.070 253.155 ;
    END
  END rd_out[256]
  PIN rd_out[257]
    DIRECTION OUTPUT ;
    USE SIGNAL ;
    SHAPE ABUTMENT ;
    PORT
      LAYER metal3 ;
      RECT 0.000 253.365 0.070 253.435 ;
    END
  END rd_out[257]
  PIN rd_out[258]
    DIRECTION OUTPUT ;
    USE SIGNAL ;
    SHAPE ABUTMENT ;
    PORT
      LAYER metal3 ;
      RECT 0.000 253.645 0.070 253.715 ;
    END
  END rd_out[258]
  PIN rd_out[259]
    DIRECTION OUTPUT ;
    USE SIGNAL ;
    SHAPE ABUTMENT ;
    PORT
      LAYER metal3 ;
      RECT 0.000 253.925 0.070 253.995 ;
    END
  END rd_out[259]
  PIN rd_out[260]
    DIRECTION OUTPUT ;
    USE SIGNAL ;
    SHAPE ABUTMENT ;
    PORT
      LAYER metal3 ;
      RECT 0.000 254.205 0.070 254.275 ;
    END
  END rd_out[260]
  PIN rd_out[261]
    DIRECTION OUTPUT ;
    USE SIGNAL ;
    SHAPE ABUTMENT ;
    PORT
      LAYER metal3 ;
      RECT 0.000 254.485 0.070 254.555 ;
    END
  END rd_out[261]
  PIN rd_out[262]
    DIRECTION OUTPUT ;
    USE SIGNAL ;
    SHAPE ABUTMENT ;
    PORT
      LAYER metal3 ;
      RECT 0.000 254.765 0.070 254.835 ;
    END
  END rd_out[262]
  PIN rd_out[263]
    DIRECTION OUTPUT ;
    USE SIGNAL ;
    SHAPE ABUTMENT ;
    PORT
      LAYER metal3 ;
      RECT 0.000 255.045 0.070 255.115 ;
    END
  END rd_out[263]
  PIN rd_out[264]
    DIRECTION OUTPUT ;
    USE SIGNAL ;
    SHAPE ABUTMENT ;
    PORT
      LAYER metal3 ;
      RECT 0.000 255.325 0.070 255.395 ;
    END
  END rd_out[264]
  PIN rd_out[265]
    DIRECTION OUTPUT ;
    USE SIGNAL ;
    SHAPE ABUTMENT ;
    PORT
      LAYER metal3 ;
      RECT 0.000 255.605 0.070 255.675 ;
    END
  END rd_out[265]
  PIN rd_out[266]
    DIRECTION OUTPUT ;
    USE SIGNAL ;
    SHAPE ABUTMENT ;
    PORT
      LAYER metal3 ;
      RECT 0.000 255.885 0.070 255.955 ;
    END
  END rd_out[266]
  PIN rd_out[267]
    DIRECTION OUTPUT ;
    USE SIGNAL ;
    SHAPE ABUTMENT ;
    PORT
      LAYER metal3 ;
      RECT 0.000 256.165 0.070 256.235 ;
    END
  END rd_out[267]
  PIN rd_out[268]
    DIRECTION OUTPUT ;
    USE SIGNAL ;
    SHAPE ABUTMENT ;
    PORT
      LAYER metal3 ;
      RECT 0.000 256.445 0.070 256.515 ;
    END
  END rd_out[268]
  PIN rd_out[269]
    DIRECTION OUTPUT ;
    USE SIGNAL ;
    SHAPE ABUTMENT ;
    PORT
      LAYER metal3 ;
      RECT 0.000 256.725 0.070 256.795 ;
    END
  END rd_out[269]
  PIN rd_out[270]
    DIRECTION OUTPUT ;
    USE SIGNAL ;
    SHAPE ABUTMENT ;
    PORT
      LAYER metal3 ;
      RECT 0.000 257.005 0.070 257.075 ;
    END
  END rd_out[270]
  PIN rd_out[271]
    DIRECTION OUTPUT ;
    USE SIGNAL ;
    SHAPE ABUTMENT ;
    PORT
      LAYER metal3 ;
      RECT 0.000 257.285 0.070 257.355 ;
    END
  END rd_out[271]
  PIN rd_out[272]
    DIRECTION OUTPUT ;
    USE SIGNAL ;
    SHAPE ABUTMENT ;
    PORT
      LAYER metal3 ;
      RECT 0.000 257.565 0.070 257.635 ;
    END
  END rd_out[272]
  PIN rd_out[273]
    DIRECTION OUTPUT ;
    USE SIGNAL ;
    SHAPE ABUTMENT ;
    PORT
      LAYER metal3 ;
      RECT 0.000 257.845 0.070 257.915 ;
    END
  END rd_out[273]
  PIN rd_out[274]
    DIRECTION OUTPUT ;
    USE SIGNAL ;
    SHAPE ABUTMENT ;
    PORT
      LAYER metal3 ;
      RECT 0.000 258.125 0.070 258.195 ;
    END
  END rd_out[274]
  PIN rd_out[275]
    DIRECTION OUTPUT ;
    USE SIGNAL ;
    SHAPE ABUTMENT ;
    PORT
      LAYER metal3 ;
      RECT 0.000 258.405 0.070 258.475 ;
    END
  END rd_out[275]
  PIN rd_out[276]
    DIRECTION OUTPUT ;
    USE SIGNAL ;
    SHAPE ABUTMENT ;
    PORT
      LAYER metal3 ;
      RECT 0.000 258.685 0.070 258.755 ;
    END
  END rd_out[276]
  PIN rd_out[277]
    DIRECTION OUTPUT ;
    USE SIGNAL ;
    SHAPE ABUTMENT ;
    PORT
      LAYER metal3 ;
      RECT 0.000 258.965 0.070 259.035 ;
    END
  END rd_out[277]
  PIN rd_out[278]
    DIRECTION OUTPUT ;
    USE SIGNAL ;
    SHAPE ABUTMENT ;
    PORT
      LAYER metal3 ;
      RECT 0.000 259.245 0.070 259.315 ;
    END
  END rd_out[278]
  PIN rd_out[279]
    DIRECTION OUTPUT ;
    USE SIGNAL ;
    SHAPE ABUTMENT ;
    PORT
      LAYER metal3 ;
      RECT 0.000 259.525 0.070 259.595 ;
    END
  END rd_out[279]
  PIN rd_out[280]
    DIRECTION OUTPUT ;
    USE SIGNAL ;
    SHAPE ABUTMENT ;
    PORT
      LAYER metal3 ;
      RECT 0.000 259.805 0.070 259.875 ;
    END
  END rd_out[280]
  PIN rd_out[281]
    DIRECTION OUTPUT ;
    USE SIGNAL ;
    SHAPE ABUTMENT ;
    PORT
      LAYER metal3 ;
      RECT 0.000 260.085 0.070 260.155 ;
    END
  END rd_out[281]
  PIN rd_out[282]
    DIRECTION OUTPUT ;
    USE SIGNAL ;
    SHAPE ABUTMENT ;
    PORT
      LAYER metal3 ;
      RECT 0.000 260.365 0.070 260.435 ;
    END
  END rd_out[282]
  PIN rd_out[283]
    DIRECTION OUTPUT ;
    USE SIGNAL ;
    SHAPE ABUTMENT ;
    PORT
      LAYER metal3 ;
      RECT 0.000 260.645 0.070 260.715 ;
    END
  END rd_out[283]
  PIN rd_out[284]
    DIRECTION OUTPUT ;
    USE SIGNAL ;
    SHAPE ABUTMENT ;
    PORT
      LAYER metal3 ;
      RECT 0.000 260.925 0.070 260.995 ;
    END
  END rd_out[284]
  PIN rd_out[285]
    DIRECTION OUTPUT ;
    USE SIGNAL ;
    SHAPE ABUTMENT ;
    PORT
      LAYER metal3 ;
      RECT 0.000 261.205 0.070 261.275 ;
    END
  END rd_out[285]
  PIN rd_out[286]
    DIRECTION OUTPUT ;
    USE SIGNAL ;
    SHAPE ABUTMENT ;
    PORT
      LAYER metal3 ;
      RECT 0.000 261.485 0.070 261.555 ;
    END
  END rd_out[286]
  PIN rd_out[287]
    DIRECTION OUTPUT ;
    USE SIGNAL ;
    SHAPE ABUTMENT ;
    PORT
      LAYER metal3 ;
      RECT 0.000 261.765 0.070 261.835 ;
    END
  END rd_out[287]
  PIN rd_out[288]
    DIRECTION OUTPUT ;
    USE SIGNAL ;
    SHAPE ABUTMENT ;
    PORT
      LAYER metal3 ;
      RECT 0.000 262.045 0.070 262.115 ;
    END
  END rd_out[288]
  PIN rd_out[289]
    DIRECTION OUTPUT ;
    USE SIGNAL ;
    SHAPE ABUTMENT ;
    PORT
      LAYER metal3 ;
      RECT 0.000 262.325 0.070 262.395 ;
    END
  END rd_out[289]
  PIN rd_out[290]
    DIRECTION OUTPUT ;
    USE SIGNAL ;
    SHAPE ABUTMENT ;
    PORT
      LAYER metal3 ;
      RECT 0.000 262.605 0.070 262.675 ;
    END
  END rd_out[290]
  PIN rd_out[291]
    DIRECTION OUTPUT ;
    USE SIGNAL ;
    SHAPE ABUTMENT ;
    PORT
      LAYER metal3 ;
      RECT 0.000 262.885 0.070 262.955 ;
    END
  END rd_out[291]
  PIN rd_out[292]
    DIRECTION OUTPUT ;
    USE SIGNAL ;
    SHAPE ABUTMENT ;
    PORT
      LAYER metal3 ;
      RECT 0.000 263.165 0.070 263.235 ;
    END
  END rd_out[292]
  PIN rd_out[293]
    DIRECTION OUTPUT ;
    USE SIGNAL ;
    SHAPE ABUTMENT ;
    PORT
      LAYER metal3 ;
      RECT 0.000 263.445 0.070 263.515 ;
    END
  END rd_out[293]
  PIN rd_out[294]
    DIRECTION OUTPUT ;
    USE SIGNAL ;
    SHAPE ABUTMENT ;
    PORT
      LAYER metal3 ;
      RECT 0.000 263.725 0.070 263.795 ;
    END
  END rd_out[294]
  PIN rd_out[295]
    DIRECTION OUTPUT ;
    USE SIGNAL ;
    SHAPE ABUTMENT ;
    PORT
      LAYER metal3 ;
      RECT 0.000 264.005 0.070 264.075 ;
    END
  END rd_out[295]
  PIN rd_out[296]
    DIRECTION OUTPUT ;
    USE SIGNAL ;
    SHAPE ABUTMENT ;
    PORT
      LAYER metal3 ;
      RECT 0.000 264.285 0.070 264.355 ;
    END
  END rd_out[296]
  PIN rd_out[297]
    DIRECTION OUTPUT ;
    USE SIGNAL ;
    SHAPE ABUTMENT ;
    PORT
      LAYER metal3 ;
      RECT 0.000 264.565 0.070 264.635 ;
    END
  END rd_out[297]
  PIN rd_out[298]
    DIRECTION OUTPUT ;
    USE SIGNAL ;
    SHAPE ABUTMENT ;
    PORT
      LAYER metal3 ;
      RECT 0.000 264.845 0.070 264.915 ;
    END
  END rd_out[298]
  PIN rd_out[299]
    DIRECTION OUTPUT ;
    USE SIGNAL ;
    SHAPE ABUTMENT ;
    PORT
      LAYER metal3 ;
      RECT 0.000 265.125 0.070 265.195 ;
    END
  END rd_out[299]
  PIN rd_out[300]
    DIRECTION OUTPUT ;
    USE SIGNAL ;
    SHAPE ABUTMENT ;
    PORT
      LAYER metal3 ;
      RECT 0.000 265.405 0.070 265.475 ;
    END
  END rd_out[300]
  PIN rd_out[301]
    DIRECTION OUTPUT ;
    USE SIGNAL ;
    SHAPE ABUTMENT ;
    PORT
      LAYER metal3 ;
      RECT 0.000 265.685 0.070 265.755 ;
    END
  END rd_out[301]
  PIN rd_out[302]
    DIRECTION OUTPUT ;
    USE SIGNAL ;
    SHAPE ABUTMENT ;
    PORT
      LAYER metal3 ;
      RECT 0.000 265.965 0.070 266.035 ;
    END
  END rd_out[302]
  PIN rd_out[303]
    DIRECTION OUTPUT ;
    USE SIGNAL ;
    SHAPE ABUTMENT ;
    PORT
      LAYER metal3 ;
      RECT 0.000 266.245 0.070 266.315 ;
    END
  END rd_out[303]
  PIN rd_out[304]
    DIRECTION OUTPUT ;
    USE SIGNAL ;
    SHAPE ABUTMENT ;
    PORT
      LAYER metal3 ;
      RECT 0.000 266.525 0.070 266.595 ;
    END
  END rd_out[304]
  PIN rd_out[305]
    DIRECTION OUTPUT ;
    USE SIGNAL ;
    SHAPE ABUTMENT ;
    PORT
      LAYER metal3 ;
      RECT 0.000 266.805 0.070 266.875 ;
    END
  END rd_out[305]
  PIN rd_out[306]
    DIRECTION OUTPUT ;
    USE SIGNAL ;
    SHAPE ABUTMENT ;
    PORT
      LAYER metal3 ;
      RECT 0.000 267.085 0.070 267.155 ;
    END
  END rd_out[306]
  PIN rd_out[307]
    DIRECTION OUTPUT ;
    USE SIGNAL ;
    SHAPE ABUTMENT ;
    PORT
      LAYER metal3 ;
      RECT 0.000 267.365 0.070 267.435 ;
    END
  END rd_out[307]
  PIN rd_out[308]
    DIRECTION OUTPUT ;
    USE SIGNAL ;
    SHAPE ABUTMENT ;
    PORT
      LAYER metal3 ;
      RECT 0.000 267.645 0.070 267.715 ;
    END
  END rd_out[308]
  PIN rd_out[309]
    DIRECTION OUTPUT ;
    USE SIGNAL ;
    SHAPE ABUTMENT ;
    PORT
      LAYER metal3 ;
      RECT 0.000 267.925 0.070 267.995 ;
    END
  END rd_out[309]
  PIN rd_out[310]
    DIRECTION OUTPUT ;
    USE SIGNAL ;
    SHAPE ABUTMENT ;
    PORT
      LAYER metal3 ;
      RECT 0.000 268.205 0.070 268.275 ;
    END
  END rd_out[310]
  PIN rd_out[311]
    DIRECTION OUTPUT ;
    USE SIGNAL ;
    SHAPE ABUTMENT ;
    PORT
      LAYER metal3 ;
      RECT 0.000 268.485 0.070 268.555 ;
    END
  END rd_out[311]
  PIN rd_out[312]
    DIRECTION OUTPUT ;
    USE SIGNAL ;
    SHAPE ABUTMENT ;
    PORT
      LAYER metal3 ;
      RECT 0.000 268.765 0.070 268.835 ;
    END
  END rd_out[312]
  PIN rd_out[313]
    DIRECTION OUTPUT ;
    USE SIGNAL ;
    SHAPE ABUTMENT ;
    PORT
      LAYER metal3 ;
      RECT 0.000 269.045 0.070 269.115 ;
    END
  END rd_out[313]
  PIN rd_out[314]
    DIRECTION OUTPUT ;
    USE SIGNAL ;
    SHAPE ABUTMENT ;
    PORT
      LAYER metal3 ;
      RECT 0.000 269.325 0.070 269.395 ;
    END
  END rd_out[314]
  PIN rd_out[315]
    DIRECTION OUTPUT ;
    USE SIGNAL ;
    SHAPE ABUTMENT ;
    PORT
      LAYER metal3 ;
      RECT 0.000 269.605 0.070 269.675 ;
    END
  END rd_out[315]
  PIN rd_out[316]
    DIRECTION OUTPUT ;
    USE SIGNAL ;
    SHAPE ABUTMENT ;
    PORT
      LAYER metal3 ;
      RECT 0.000 269.885 0.070 269.955 ;
    END
  END rd_out[316]
  PIN rd_out[317]
    DIRECTION OUTPUT ;
    USE SIGNAL ;
    SHAPE ABUTMENT ;
    PORT
      LAYER metal3 ;
      RECT 0.000 270.165 0.070 270.235 ;
    END
  END rd_out[317]
  PIN rd_out[318]
    DIRECTION OUTPUT ;
    USE SIGNAL ;
    SHAPE ABUTMENT ;
    PORT
      LAYER metal3 ;
      RECT 0.000 270.445 0.070 270.515 ;
    END
  END rd_out[318]
  PIN rd_out[319]
    DIRECTION OUTPUT ;
    USE SIGNAL ;
    SHAPE ABUTMENT ;
    PORT
      LAYER metal3 ;
      RECT 0.000 270.725 0.070 270.795 ;
    END
  END rd_out[319]
  PIN rd_out[320]
    DIRECTION OUTPUT ;
    USE SIGNAL ;
    SHAPE ABUTMENT ;
    PORT
      LAYER metal3 ;
      RECT 0.000 271.005 0.070 271.075 ;
    END
  END rd_out[320]
  PIN rd_out[321]
    DIRECTION OUTPUT ;
    USE SIGNAL ;
    SHAPE ABUTMENT ;
    PORT
      LAYER metal3 ;
      RECT 0.000 271.285 0.070 271.355 ;
    END
  END rd_out[321]
  PIN rd_out[322]
    DIRECTION OUTPUT ;
    USE SIGNAL ;
    SHAPE ABUTMENT ;
    PORT
      LAYER metal3 ;
      RECT 0.000 271.565 0.070 271.635 ;
    END
  END rd_out[322]
  PIN rd_out[323]
    DIRECTION OUTPUT ;
    USE SIGNAL ;
    SHAPE ABUTMENT ;
    PORT
      LAYER metal3 ;
      RECT 0.000 271.845 0.070 271.915 ;
    END
  END rd_out[323]
  PIN rd_out[324]
    DIRECTION OUTPUT ;
    USE SIGNAL ;
    SHAPE ABUTMENT ;
    PORT
      LAYER metal3 ;
      RECT 0.000 272.125 0.070 272.195 ;
    END
  END rd_out[324]
  PIN rd_out[325]
    DIRECTION OUTPUT ;
    USE SIGNAL ;
    SHAPE ABUTMENT ;
    PORT
      LAYER metal3 ;
      RECT 0.000 272.405 0.070 272.475 ;
    END
  END rd_out[325]
  PIN rd_out[326]
    DIRECTION OUTPUT ;
    USE SIGNAL ;
    SHAPE ABUTMENT ;
    PORT
      LAYER metal3 ;
      RECT 0.000 272.685 0.070 272.755 ;
    END
  END rd_out[326]
  PIN rd_out[327]
    DIRECTION OUTPUT ;
    USE SIGNAL ;
    SHAPE ABUTMENT ;
    PORT
      LAYER metal3 ;
      RECT 0.000 272.965 0.070 273.035 ;
    END
  END rd_out[327]
  PIN rd_out[328]
    DIRECTION OUTPUT ;
    USE SIGNAL ;
    SHAPE ABUTMENT ;
    PORT
      LAYER metal3 ;
      RECT 0.000 273.245 0.070 273.315 ;
    END
  END rd_out[328]
  PIN rd_out[329]
    DIRECTION OUTPUT ;
    USE SIGNAL ;
    SHAPE ABUTMENT ;
    PORT
      LAYER metal3 ;
      RECT 0.000 273.525 0.070 273.595 ;
    END
  END rd_out[329]
  PIN rd_out[330]
    DIRECTION OUTPUT ;
    USE SIGNAL ;
    SHAPE ABUTMENT ;
    PORT
      LAYER metal3 ;
      RECT 0.000 273.805 0.070 273.875 ;
    END
  END rd_out[330]
  PIN rd_out[331]
    DIRECTION OUTPUT ;
    USE SIGNAL ;
    SHAPE ABUTMENT ;
    PORT
      LAYER metal3 ;
      RECT 0.000 274.085 0.070 274.155 ;
    END
  END rd_out[331]
  PIN rd_out[332]
    DIRECTION OUTPUT ;
    USE SIGNAL ;
    SHAPE ABUTMENT ;
    PORT
      LAYER metal3 ;
      RECT 0.000 274.365 0.070 274.435 ;
    END
  END rd_out[332]
  PIN rd_out[333]
    DIRECTION OUTPUT ;
    USE SIGNAL ;
    SHAPE ABUTMENT ;
    PORT
      LAYER metal3 ;
      RECT 0.000 274.645 0.070 274.715 ;
    END
  END rd_out[333]
  PIN rd_out[334]
    DIRECTION OUTPUT ;
    USE SIGNAL ;
    SHAPE ABUTMENT ;
    PORT
      LAYER metal3 ;
      RECT 0.000 274.925 0.070 274.995 ;
    END
  END rd_out[334]
  PIN rd_out[335]
    DIRECTION OUTPUT ;
    USE SIGNAL ;
    SHAPE ABUTMENT ;
    PORT
      LAYER metal3 ;
      RECT 0.000 275.205 0.070 275.275 ;
    END
  END rd_out[335]
  PIN rd_out[336]
    DIRECTION OUTPUT ;
    USE SIGNAL ;
    SHAPE ABUTMENT ;
    PORT
      LAYER metal3 ;
      RECT 0.000 275.485 0.070 275.555 ;
    END
  END rd_out[336]
  PIN rd_out[337]
    DIRECTION OUTPUT ;
    USE SIGNAL ;
    SHAPE ABUTMENT ;
    PORT
      LAYER metal3 ;
      RECT 0.000 275.765 0.070 275.835 ;
    END
  END rd_out[337]
  PIN rd_out[338]
    DIRECTION OUTPUT ;
    USE SIGNAL ;
    SHAPE ABUTMENT ;
    PORT
      LAYER metal3 ;
      RECT 0.000 276.045 0.070 276.115 ;
    END
  END rd_out[338]
  PIN rd_out[339]
    DIRECTION OUTPUT ;
    USE SIGNAL ;
    SHAPE ABUTMENT ;
    PORT
      LAYER metal3 ;
      RECT 0.000 276.325 0.070 276.395 ;
    END
  END rd_out[339]
  PIN rd_out[340]
    DIRECTION OUTPUT ;
    USE SIGNAL ;
    SHAPE ABUTMENT ;
    PORT
      LAYER metal3 ;
      RECT 0.000 276.605 0.070 276.675 ;
    END
  END rd_out[340]
  PIN rd_out[341]
    DIRECTION OUTPUT ;
    USE SIGNAL ;
    SHAPE ABUTMENT ;
    PORT
      LAYER metal3 ;
      RECT 0.000 276.885 0.070 276.955 ;
    END
  END rd_out[341]
  PIN rd_out[342]
    DIRECTION OUTPUT ;
    USE SIGNAL ;
    SHAPE ABUTMENT ;
    PORT
      LAYER metal3 ;
      RECT 0.000 277.165 0.070 277.235 ;
    END
  END rd_out[342]
  PIN rd_out[343]
    DIRECTION OUTPUT ;
    USE SIGNAL ;
    SHAPE ABUTMENT ;
    PORT
      LAYER metal3 ;
      RECT 0.000 277.445 0.070 277.515 ;
    END
  END rd_out[343]
  PIN rd_out[344]
    DIRECTION OUTPUT ;
    USE SIGNAL ;
    SHAPE ABUTMENT ;
    PORT
      LAYER metal3 ;
      RECT 0.000 277.725 0.070 277.795 ;
    END
  END rd_out[344]
  PIN rd_out[345]
    DIRECTION OUTPUT ;
    USE SIGNAL ;
    SHAPE ABUTMENT ;
    PORT
      LAYER metal3 ;
      RECT 0.000 278.005 0.070 278.075 ;
    END
  END rd_out[345]
  PIN rd_out[346]
    DIRECTION OUTPUT ;
    USE SIGNAL ;
    SHAPE ABUTMENT ;
    PORT
      LAYER metal3 ;
      RECT 0.000 278.285 0.070 278.355 ;
    END
  END rd_out[346]
  PIN rd_out[347]
    DIRECTION OUTPUT ;
    USE SIGNAL ;
    SHAPE ABUTMENT ;
    PORT
      LAYER metal3 ;
      RECT 0.000 278.565 0.070 278.635 ;
    END
  END rd_out[347]
  PIN rd_out[348]
    DIRECTION OUTPUT ;
    USE SIGNAL ;
    SHAPE ABUTMENT ;
    PORT
      LAYER metal3 ;
      RECT 0.000 278.845 0.070 278.915 ;
    END
  END rd_out[348]
  PIN rd_out[349]
    DIRECTION OUTPUT ;
    USE SIGNAL ;
    SHAPE ABUTMENT ;
    PORT
      LAYER metal3 ;
      RECT 0.000 279.125 0.070 279.195 ;
    END
  END rd_out[349]
  PIN rd_out[350]
    DIRECTION OUTPUT ;
    USE SIGNAL ;
    SHAPE ABUTMENT ;
    PORT
      LAYER metal3 ;
      RECT 0.000 279.405 0.070 279.475 ;
    END
  END rd_out[350]
  PIN rd_out[351]
    DIRECTION OUTPUT ;
    USE SIGNAL ;
    SHAPE ABUTMENT ;
    PORT
      LAYER metal3 ;
      RECT 0.000 279.685 0.070 279.755 ;
    END
  END rd_out[351]
  PIN rd_out[352]
    DIRECTION OUTPUT ;
    USE SIGNAL ;
    SHAPE ABUTMENT ;
    PORT
      LAYER metal3 ;
      RECT 0.000 279.965 0.070 280.035 ;
    END
  END rd_out[352]
  PIN rd_out[353]
    DIRECTION OUTPUT ;
    USE SIGNAL ;
    SHAPE ABUTMENT ;
    PORT
      LAYER metal3 ;
      RECT 0.000 280.245 0.070 280.315 ;
    END
  END rd_out[353]
  PIN rd_out[354]
    DIRECTION OUTPUT ;
    USE SIGNAL ;
    SHAPE ABUTMENT ;
    PORT
      LAYER metal3 ;
      RECT 0.000 280.525 0.070 280.595 ;
    END
  END rd_out[354]
  PIN rd_out[355]
    DIRECTION OUTPUT ;
    USE SIGNAL ;
    SHAPE ABUTMENT ;
    PORT
      LAYER metal3 ;
      RECT 0.000 280.805 0.070 280.875 ;
    END
  END rd_out[355]
  PIN rd_out[356]
    DIRECTION OUTPUT ;
    USE SIGNAL ;
    SHAPE ABUTMENT ;
    PORT
      LAYER metal3 ;
      RECT 0.000 281.085 0.070 281.155 ;
    END
  END rd_out[356]
  PIN rd_out[357]
    DIRECTION OUTPUT ;
    USE SIGNAL ;
    SHAPE ABUTMENT ;
    PORT
      LAYER metal3 ;
      RECT 0.000 281.365 0.070 281.435 ;
    END
  END rd_out[357]
  PIN rd_out[358]
    DIRECTION OUTPUT ;
    USE SIGNAL ;
    SHAPE ABUTMENT ;
    PORT
      LAYER metal3 ;
      RECT 0.000 281.645 0.070 281.715 ;
    END
  END rd_out[358]
  PIN rd_out[359]
    DIRECTION OUTPUT ;
    USE SIGNAL ;
    SHAPE ABUTMENT ;
    PORT
      LAYER metal3 ;
      RECT 0.000 281.925 0.070 281.995 ;
    END
  END rd_out[359]
  PIN rd_out[360]
    DIRECTION OUTPUT ;
    USE SIGNAL ;
    SHAPE ABUTMENT ;
    PORT
      LAYER metal3 ;
      RECT 0.000 282.205 0.070 282.275 ;
    END
  END rd_out[360]
  PIN rd_out[361]
    DIRECTION OUTPUT ;
    USE SIGNAL ;
    SHAPE ABUTMENT ;
    PORT
      LAYER metal3 ;
      RECT 0.000 282.485 0.070 282.555 ;
    END
  END rd_out[361]
  PIN rd_out[362]
    DIRECTION OUTPUT ;
    USE SIGNAL ;
    SHAPE ABUTMENT ;
    PORT
      LAYER metal3 ;
      RECT 0.000 282.765 0.070 282.835 ;
    END
  END rd_out[362]
  PIN rd_out[363]
    DIRECTION OUTPUT ;
    USE SIGNAL ;
    SHAPE ABUTMENT ;
    PORT
      LAYER metal3 ;
      RECT 0.000 283.045 0.070 283.115 ;
    END
  END rd_out[363]
  PIN rd_out[364]
    DIRECTION OUTPUT ;
    USE SIGNAL ;
    SHAPE ABUTMENT ;
    PORT
      LAYER metal3 ;
      RECT 0.000 283.325 0.070 283.395 ;
    END
  END rd_out[364]
  PIN rd_out[365]
    DIRECTION OUTPUT ;
    USE SIGNAL ;
    SHAPE ABUTMENT ;
    PORT
      LAYER metal3 ;
      RECT 0.000 283.605 0.070 283.675 ;
    END
  END rd_out[365]
  PIN rd_out[366]
    DIRECTION OUTPUT ;
    USE SIGNAL ;
    SHAPE ABUTMENT ;
    PORT
      LAYER metal3 ;
      RECT 0.000 283.885 0.070 283.955 ;
    END
  END rd_out[366]
  PIN rd_out[367]
    DIRECTION OUTPUT ;
    USE SIGNAL ;
    SHAPE ABUTMENT ;
    PORT
      LAYER metal3 ;
      RECT 0.000 284.165 0.070 284.235 ;
    END
  END rd_out[367]
  PIN rd_out[368]
    DIRECTION OUTPUT ;
    USE SIGNAL ;
    SHAPE ABUTMENT ;
    PORT
      LAYER metal3 ;
      RECT 0.000 284.445 0.070 284.515 ;
    END
  END rd_out[368]
  PIN rd_out[369]
    DIRECTION OUTPUT ;
    USE SIGNAL ;
    SHAPE ABUTMENT ;
    PORT
      LAYER metal3 ;
      RECT 0.000 284.725 0.070 284.795 ;
    END
  END rd_out[369]
  PIN rd_out[370]
    DIRECTION OUTPUT ;
    USE SIGNAL ;
    SHAPE ABUTMENT ;
    PORT
      LAYER metal3 ;
      RECT 0.000 285.005 0.070 285.075 ;
    END
  END rd_out[370]
  PIN rd_out[371]
    DIRECTION OUTPUT ;
    USE SIGNAL ;
    SHAPE ABUTMENT ;
    PORT
      LAYER metal3 ;
      RECT 0.000 285.285 0.070 285.355 ;
    END
  END rd_out[371]
  PIN rd_out[372]
    DIRECTION OUTPUT ;
    USE SIGNAL ;
    SHAPE ABUTMENT ;
    PORT
      LAYER metal3 ;
      RECT 0.000 285.565 0.070 285.635 ;
    END
  END rd_out[372]
  PIN rd_out[373]
    DIRECTION OUTPUT ;
    USE SIGNAL ;
    SHAPE ABUTMENT ;
    PORT
      LAYER metal3 ;
      RECT 0.000 285.845 0.070 285.915 ;
    END
  END rd_out[373]
  PIN rd_out[374]
    DIRECTION OUTPUT ;
    USE SIGNAL ;
    SHAPE ABUTMENT ;
    PORT
      LAYER metal3 ;
      RECT 0.000 286.125 0.070 286.195 ;
    END
  END rd_out[374]
  PIN rd_out[375]
    DIRECTION OUTPUT ;
    USE SIGNAL ;
    SHAPE ABUTMENT ;
    PORT
      LAYER metal3 ;
      RECT 0.000 286.405 0.070 286.475 ;
    END
  END rd_out[375]
  PIN rd_out[376]
    DIRECTION OUTPUT ;
    USE SIGNAL ;
    SHAPE ABUTMENT ;
    PORT
      LAYER metal3 ;
      RECT 0.000 286.685 0.070 286.755 ;
    END
  END rd_out[376]
  PIN rd_out[377]
    DIRECTION OUTPUT ;
    USE SIGNAL ;
    SHAPE ABUTMENT ;
    PORT
      LAYER metal3 ;
      RECT 0.000 286.965 0.070 287.035 ;
    END
  END rd_out[377]
  PIN rd_out[378]
    DIRECTION OUTPUT ;
    USE SIGNAL ;
    SHAPE ABUTMENT ;
    PORT
      LAYER metal3 ;
      RECT 0.000 287.245 0.070 287.315 ;
    END
  END rd_out[378]
  PIN rd_out[379]
    DIRECTION OUTPUT ;
    USE SIGNAL ;
    SHAPE ABUTMENT ;
    PORT
      LAYER metal3 ;
      RECT 0.000 287.525 0.070 287.595 ;
    END
  END rd_out[379]
  PIN rd_out[380]
    DIRECTION OUTPUT ;
    USE SIGNAL ;
    SHAPE ABUTMENT ;
    PORT
      LAYER metal3 ;
      RECT 0.000 287.805 0.070 287.875 ;
    END
  END rd_out[380]
  PIN rd_out[381]
    DIRECTION OUTPUT ;
    USE SIGNAL ;
    SHAPE ABUTMENT ;
    PORT
      LAYER metal3 ;
      RECT 0.000 288.085 0.070 288.155 ;
    END
  END rd_out[381]
  PIN rd_out[382]
    DIRECTION OUTPUT ;
    USE SIGNAL ;
    SHAPE ABUTMENT ;
    PORT
      LAYER metal3 ;
      RECT 0.000 288.365 0.070 288.435 ;
    END
  END rd_out[382]
  PIN rd_out[383]
    DIRECTION OUTPUT ;
    USE SIGNAL ;
    SHAPE ABUTMENT ;
    PORT
      LAYER metal3 ;
      RECT 0.000 288.645 0.070 288.715 ;
    END
  END rd_out[383]
  PIN rd_out[384]
    DIRECTION OUTPUT ;
    USE SIGNAL ;
    SHAPE ABUTMENT ;
    PORT
      LAYER metal3 ;
      RECT 0.000 288.925 0.070 288.995 ;
    END
  END rd_out[384]
  PIN rd_out[385]
    DIRECTION OUTPUT ;
    USE SIGNAL ;
    SHAPE ABUTMENT ;
    PORT
      LAYER metal3 ;
      RECT 0.000 289.205 0.070 289.275 ;
    END
  END rd_out[385]
  PIN rd_out[386]
    DIRECTION OUTPUT ;
    USE SIGNAL ;
    SHAPE ABUTMENT ;
    PORT
      LAYER metal3 ;
      RECT 0.000 289.485 0.070 289.555 ;
    END
  END rd_out[386]
  PIN rd_out[387]
    DIRECTION OUTPUT ;
    USE SIGNAL ;
    SHAPE ABUTMENT ;
    PORT
      LAYER metal3 ;
      RECT 0.000 289.765 0.070 289.835 ;
    END
  END rd_out[387]
  PIN rd_out[388]
    DIRECTION OUTPUT ;
    USE SIGNAL ;
    SHAPE ABUTMENT ;
    PORT
      LAYER metal3 ;
      RECT 0.000 290.045 0.070 290.115 ;
    END
  END rd_out[388]
  PIN rd_out[389]
    DIRECTION OUTPUT ;
    USE SIGNAL ;
    SHAPE ABUTMENT ;
    PORT
      LAYER metal3 ;
      RECT 0.000 290.325 0.070 290.395 ;
    END
  END rd_out[389]
  PIN rd_out[390]
    DIRECTION OUTPUT ;
    USE SIGNAL ;
    SHAPE ABUTMENT ;
    PORT
      LAYER metal3 ;
      RECT 0.000 290.605 0.070 290.675 ;
    END
  END rd_out[390]
  PIN rd_out[391]
    DIRECTION OUTPUT ;
    USE SIGNAL ;
    SHAPE ABUTMENT ;
    PORT
      LAYER metal3 ;
      RECT 0.000 290.885 0.070 290.955 ;
    END
  END rd_out[391]
  PIN rd_out[392]
    DIRECTION OUTPUT ;
    USE SIGNAL ;
    SHAPE ABUTMENT ;
    PORT
      LAYER metal3 ;
      RECT 0.000 291.165 0.070 291.235 ;
    END
  END rd_out[392]
  PIN rd_out[393]
    DIRECTION OUTPUT ;
    USE SIGNAL ;
    SHAPE ABUTMENT ;
    PORT
      LAYER metal3 ;
      RECT 0.000 291.445 0.070 291.515 ;
    END
  END rd_out[393]
  PIN rd_out[394]
    DIRECTION OUTPUT ;
    USE SIGNAL ;
    SHAPE ABUTMENT ;
    PORT
      LAYER metal3 ;
      RECT 0.000 291.725 0.070 291.795 ;
    END
  END rd_out[394]
  PIN rd_out[395]
    DIRECTION OUTPUT ;
    USE SIGNAL ;
    SHAPE ABUTMENT ;
    PORT
      LAYER metal3 ;
      RECT 0.000 292.005 0.070 292.075 ;
    END
  END rd_out[395]
  PIN rd_out[396]
    DIRECTION OUTPUT ;
    USE SIGNAL ;
    SHAPE ABUTMENT ;
    PORT
      LAYER metal3 ;
      RECT 0.000 292.285 0.070 292.355 ;
    END
  END rd_out[396]
  PIN rd_out[397]
    DIRECTION OUTPUT ;
    USE SIGNAL ;
    SHAPE ABUTMENT ;
    PORT
      LAYER metal3 ;
      RECT 0.000 292.565 0.070 292.635 ;
    END
  END rd_out[397]
  PIN rd_out[398]
    DIRECTION OUTPUT ;
    USE SIGNAL ;
    SHAPE ABUTMENT ;
    PORT
      LAYER metal3 ;
      RECT 0.000 292.845 0.070 292.915 ;
    END
  END rd_out[398]
  PIN rd_out[399]
    DIRECTION OUTPUT ;
    USE SIGNAL ;
    SHAPE ABUTMENT ;
    PORT
      LAYER metal3 ;
      RECT 0.000 293.125 0.070 293.195 ;
    END
  END rd_out[399]
  PIN rd_out[400]
    DIRECTION OUTPUT ;
    USE SIGNAL ;
    SHAPE ABUTMENT ;
    PORT
      LAYER metal3 ;
      RECT 0.000 293.405 0.070 293.475 ;
    END
  END rd_out[400]
  PIN rd_out[401]
    DIRECTION OUTPUT ;
    USE SIGNAL ;
    SHAPE ABUTMENT ;
    PORT
      LAYER metal3 ;
      RECT 0.000 293.685 0.070 293.755 ;
    END
  END rd_out[401]
  PIN rd_out[402]
    DIRECTION OUTPUT ;
    USE SIGNAL ;
    SHAPE ABUTMENT ;
    PORT
      LAYER metal3 ;
      RECT 0.000 293.965 0.070 294.035 ;
    END
  END rd_out[402]
  PIN rd_out[403]
    DIRECTION OUTPUT ;
    USE SIGNAL ;
    SHAPE ABUTMENT ;
    PORT
      LAYER metal3 ;
      RECT 0.000 294.245 0.070 294.315 ;
    END
  END rd_out[403]
  PIN rd_out[404]
    DIRECTION OUTPUT ;
    USE SIGNAL ;
    SHAPE ABUTMENT ;
    PORT
      LAYER metal3 ;
      RECT 0.000 294.525 0.070 294.595 ;
    END
  END rd_out[404]
  PIN rd_out[405]
    DIRECTION OUTPUT ;
    USE SIGNAL ;
    SHAPE ABUTMENT ;
    PORT
      LAYER metal3 ;
      RECT 0.000 294.805 0.070 294.875 ;
    END
  END rd_out[405]
  PIN rd_out[406]
    DIRECTION OUTPUT ;
    USE SIGNAL ;
    SHAPE ABUTMENT ;
    PORT
      LAYER metal3 ;
      RECT 0.000 295.085 0.070 295.155 ;
    END
  END rd_out[406]
  PIN rd_out[407]
    DIRECTION OUTPUT ;
    USE SIGNAL ;
    SHAPE ABUTMENT ;
    PORT
      LAYER metal3 ;
      RECT 0.000 295.365 0.070 295.435 ;
    END
  END rd_out[407]
  PIN rd_out[408]
    DIRECTION OUTPUT ;
    USE SIGNAL ;
    SHAPE ABUTMENT ;
    PORT
      LAYER metal3 ;
      RECT 0.000 295.645 0.070 295.715 ;
    END
  END rd_out[408]
  PIN rd_out[409]
    DIRECTION OUTPUT ;
    USE SIGNAL ;
    SHAPE ABUTMENT ;
    PORT
      LAYER metal3 ;
      RECT 0.000 295.925 0.070 295.995 ;
    END
  END rd_out[409]
  PIN rd_out[410]
    DIRECTION OUTPUT ;
    USE SIGNAL ;
    SHAPE ABUTMENT ;
    PORT
      LAYER metal3 ;
      RECT 0.000 296.205 0.070 296.275 ;
    END
  END rd_out[410]
  PIN rd_out[411]
    DIRECTION OUTPUT ;
    USE SIGNAL ;
    SHAPE ABUTMENT ;
    PORT
      LAYER metal3 ;
      RECT 0.000 296.485 0.070 296.555 ;
    END
  END rd_out[411]
  PIN rd_out[412]
    DIRECTION OUTPUT ;
    USE SIGNAL ;
    SHAPE ABUTMENT ;
    PORT
      LAYER metal3 ;
      RECT 0.000 296.765 0.070 296.835 ;
    END
  END rd_out[412]
  PIN rd_out[413]
    DIRECTION OUTPUT ;
    USE SIGNAL ;
    SHAPE ABUTMENT ;
    PORT
      LAYER metal3 ;
      RECT 0.000 297.045 0.070 297.115 ;
    END
  END rd_out[413]
  PIN rd_out[414]
    DIRECTION OUTPUT ;
    USE SIGNAL ;
    SHAPE ABUTMENT ;
    PORT
      LAYER metal3 ;
      RECT 0.000 297.325 0.070 297.395 ;
    END
  END rd_out[414]
  PIN rd_out[415]
    DIRECTION OUTPUT ;
    USE SIGNAL ;
    SHAPE ABUTMENT ;
    PORT
      LAYER metal3 ;
      RECT 0.000 297.605 0.070 297.675 ;
    END
  END rd_out[415]
  PIN rd_out[416]
    DIRECTION OUTPUT ;
    USE SIGNAL ;
    SHAPE ABUTMENT ;
    PORT
      LAYER metal3 ;
      RECT 0.000 297.885 0.070 297.955 ;
    END
  END rd_out[416]
  PIN rd_out[417]
    DIRECTION OUTPUT ;
    USE SIGNAL ;
    SHAPE ABUTMENT ;
    PORT
      LAYER metal3 ;
      RECT 0.000 298.165 0.070 298.235 ;
    END
  END rd_out[417]
  PIN rd_out[418]
    DIRECTION OUTPUT ;
    USE SIGNAL ;
    SHAPE ABUTMENT ;
    PORT
      LAYER metal3 ;
      RECT 0.000 298.445 0.070 298.515 ;
    END
  END rd_out[418]
  PIN rd_out[419]
    DIRECTION OUTPUT ;
    USE SIGNAL ;
    SHAPE ABUTMENT ;
    PORT
      LAYER metal3 ;
      RECT 0.000 298.725 0.070 298.795 ;
    END
  END rd_out[419]
  PIN rd_out[420]
    DIRECTION OUTPUT ;
    USE SIGNAL ;
    SHAPE ABUTMENT ;
    PORT
      LAYER metal3 ;
      RECT 0.000 299.005 0.070 299.075 ;
    END
  END rd_out[420]
  PIN rd_out[421]
    DIRECTION OUTPUT ;
    USE SIGNAL ;
    SHAPE ABUTMENT ;
    PORT
      LAYER metal3 ;
      RECT 0.000 299.285 0.070 299.355 ;
    END
  END rd_out[421]
  PIN rd_out[422]
    DIRECTION OUTPUT ;
    USE SIGNAL ;
    SHAPE ABUTMENT ;
    PORT
      LAYER metal3 ;
      RECT 0.000 299.565 0.070 299.635 ;
    END
  END rd_out[422]
  PIN rd_out[423]
    DIRECTION OUTPUT ;
    USE SIGNAL ;
    SHAPE ABUTMENT ;
    PORT
      LAYER metal3 ;
      RECT 0.000 299.845 0.070 299.915 ;
    END
  END rd_out[423]
  PIN rd_out[424]
    DIRECTION OUTPUT ;
    USE SIGNAL ;
    SHAPE ABUTMENT ;
    PORT
      LAYER metal3 ;
      RECT 0.000 300.125 0.070 300.195 ;
    END
  END rd_out[424]
  PIN rd_out[425]
    DIRECTION OUTPUT ;
    USE SIGNAL ;
    SHAPE ABUTMENT ;
    PORT
      LAYER metal3 ;
      RECT 0.000 300.405 0.070 300.475 ;
    END
  END rd_out[425]
  PIN rd_out[426]
    DIRECTION OUTPUT ;
    USE SIGNAL ;
    SHAPE ABUTMENT ;
    PORT
      LAYER metal3 ;
      RECT 0.000 300.685 0.070 300.755 ;
    END
  END rd_out[426]
  PIN rd_out[427]
    DIRECTION OUTPUT ;
    USE SIGNAL ;
    SHAPE ABUTMENT ;
    PORT
      LAYER metal3 ;
      RECT 0.000 300.965 0.070 301.035 ;
    END
  END rd_out[427]
  PIN rd_out[428]
    DIRECTION OUTPUT ;
    USE SIGNAL ;
    SHAPE ABUTMENT ;
    PORT
      LAYER metal3 ;
      RECT 0.000 301.245 0.070 301.315 ;
    END
  END rd_out[428]
  PIN rd_out[429]
    DIRECTION OUTPUT ;
    USE SIGNAL ;
    SHAPE ABUTMENT ;
    PORT
      LAYER metal3 ;
      RECT 0.000 301.525 0.070 301.595 ;
    END
  END rd_out[429]
  PIN rd_out[430]
    DIRECTION OUTPUT ;
    USE SIGNAL ;
    SHAPE ABUTMENT ;
    PORT
      LAYER metal3 ;
      RECT 0.000 301.805 0.070 301.875 ;
    END
  END rd_out[430]
  PIN rd_out[431]
    DIRECTION OUTPUT ;
    USE SIGNAL ;
    SHAPE ABUTMENT ;
    PORT
      LAYER metal3 ;
      RECT 0.000 302.085 0.070 302.155 ;
    END
  END rd_out[431]
  PIN rd_out[432]
    DIRECTION OUTPUT ;
    USE SIGNAL ;
    SHAPE ABUTMENT ;
    PORT
      LAYER metal3 ;
      RECT 0.000 302.365 0.070 302.435 ;
    END
  END rd_out[432]
  PIN rd_out[433]
    DIRECTION OUTPUT ;
    USE SIGNAL ;
    SHAPE ABUTMENT ;
    PORT
      LAYER metal3 ;
      RECT 0.000 302.645 0.070 302.715 ;
    END
  END rd_out[433]
  PIN rd_out[434]
    DIRECTION OUTPUT ;
    USE SIGNAL ;
    SHAPE ABUTMENT ;
    PORT
      LAYER metal3 ;
      RECT 0.000 302.925 0.070 302.995 ;
    END
  END rd_out[434]
  PIN rd_out[435]
    DIRECTION OUTPUT ;
    USE SIGNAL ;
    SHAPE ABUTMENT ;
    PORT
      LAYER metal3 ;
      RECT 0.000 303.205 0.070 303.275 ;
    END
  END rd_out[435]
  PIN rd_out[436]
    DIRECTION OUTPUT ;
    USE SIGNAL ;
    SHAPE ABUTMENT ;
    PORT
      LAYER metal3 ;
      RECT 0.000 303.485 0.070 303.555 ;
    END
  END rd_out[436]
  PIN rd_out[437]
    DIRECTION OUTPUT ;
    USE SIGNAL ;
    SHAPE ABUTMENT ;
    PORT
      LAYER metal3 ;
      RECT 0.000 303.765 0.070 303.835 ;
    END
  END rd_out[437]
  PIN rd_out[438]
    DIRECTION OUTPUT ;
    USE SIGNAL ;
    SHAPE ABUTMENT ;
    PORT
      LAYER metal3 ;
      RECT 0.000 304.045 0.070 304.115 ;
    END
  END rd_out[438]
  PIN rd_out[439]
    DIRECTION OUTPUT ;
    USE SIGNAL ;
    SHAPE ABUTMENT ;
    PORT
      LAYER metal3 ;
      RECT 0.000 304.325 0.070 304.395 ;
    END
  END rd_out[439]
  PIN rd_out[440]
    DIRECTION OUTPUT ;
    USE SIGNAL ;
    SHAPE ABUTMENT ;
    PORT
      LAYER metal3 ;
      RECT 0.000 304.605 0.070 304.675 ;
    END
  END rd_out[440]
  PIN rd_out[441]
    DIRECTION OUTPUT ;
    USE SIGNAL ;
    SHAPE ABUTMENT ;
    PORT
      LAYER metal3 ;
      RECT 0.000 304.885 0.070 304.955 ;
    END
  END rd_out[441]
  PIN rd_out[442]
    DIRECTION OUTPUT ;
    USE SIGNAL ;
    SHAPE ABUTMENT ;
    PORT
      LAYER metal3 ;
      RECT 0.000 305.165 0.070 305.235 ;
    END
  END rd_out[442]
  PIN rd_out[443]
    DIRECTION OUTPUT ;
    USE SIGNAL ;
    SHAPE ABUTMENT ;
    PORT
      LAYER metal3 ;
      RECT 0.000 305.445 0.070 305.515 ;
    END
  END rd_out[443]
  PIN rd_out[444]
    DIRECTION OUTPUT ;
    USE SIGNAL ;
    SHAPE ABUTMENT ;
    PORT
      LAYER metal3 ;
      RECT 0.000 305.725 0.070 305.795 ;
    END
  END rd_out[444]
  PIN rd_out[445]
    DIRECTION OUTPUT ;
    USE SIGNAL ;
    SHAPE ABUTMENT ;
    PORT
      LAYER metal3 ;
      RECT 0.000 306.005 0.070 306.075 ;
    END
  END rd_out[445]
  PIN rd_out[446]
    DIRECTION OUTPUT ;
    USE SIGNAL ;
    SHAPE ABUTMENT ;
    PORT
      LAYER metal3 ;
      RECT 0.000 306.285 0.070 306.355 ;
    END
  END rd_out[446]
  PIN rd_out[447]
    DIRECTION OUTPUT ;
    USE SIGNAL ;
    SHAPE ABUTMENT ;
    PORT
      LAYER metal3 ;
      RECT 0.000 306.565 0.070 306.635 ;
    END
  END rd_out[447]
  PIN rd_out[448]
    DIRECTION OUTPUT ;
    USE SIGNAL ;
    SHAPE ABUTMENT ;
    PORT
      LAYER metal3 ;
      RECT 0.000 306.845 0.070 306.915 ;
    END
  END rd_out[448]
  PIN rd_out[449]
    DIRECTION OUTPUT ;
    USE SIGNAL ;
    SHAPE ABUTMENT ;
    PORT
      LAYER metal3 ;
      RECT 0.000 307.125 0.070 307.195 ;
    END
  END rd_out[449]
  PIN rd_out[450]
    DIRECTION OUTPUT ;
    USE SIGNAL ;
    SHAPE ABUTMENT ;
    PORT
      LAYER metal3 ;
      RECT 0.000 307.405 0.070 307.475 ;
    END
  END rd_out[450]
  PIN rd_out[451]
    DIRECTION OUTPUT ;
    USE SIGNAL ;
    SHAPE ABUTMENT ;
    PORT
      LAYER metal3 ;
      RECT 0.000 307.685 0.070 307.755 ;
    END
  END rd_out[451]
  PIN rd_out[452]
    DIRECTION OUTPUT ;
    USE SIGNAL ;
    SHAPE ABUTMENT ;
    PORT
      LAYER metal3 ;
      RECT 0.000 307.965 0.070 308.035 ;
    END
  END rd_out[452]
  PIN rd_out[453]
    DIRECTION OUTPUT ;
    USE SIGNAL ;
    SHAPE ABUTMENT ;
    PORT
      LAYER metal3 ;
      RECT 0.000 308.245 0.070 308.315 ;
    END
  END rd_out[453]
  PIN rd_out[454]
    DIRECTION OUTPUT ;
    USE SIGNAL ;
    SHAPE ABUTMENT ;
    PORT
      LAYER metal3 ;
      RECT 0.000 308.525 0.070 308.595 ;
    END
  END rd_out[454]
  PIN rd_out[455]
    DIRECTION OUTPUT ;
    USE SIGNAL ;
    SHAPE ABUTMENT ;
    PORT
      LAYER metal3 ;
      RECT 0.000 308.805 0.070 308.875 ;
    END
  END rd_out[455]
  PIN rd_out[456]
    DIRECTION OUTPUT ;
    USE SIGNAL ;
    SHAPE ABUTMENT ;
    PORT
      LAYER metal3 ;
      RECT 0.000 309.085 0.070 309.155 ;
    END
  END rd_out[456]
  PIN rd_out[457]
    DIRECTION OUTPUT ;
    USE SIGNAL ;
    SHAPE ABUTMENT ;
    PORT
      LAYER metal3 ;
      RECT 0.000 309.365 0.070 309.435 ;
    END
  END rd_out[457]
  PIN rd_out[458]
    DIRECTION OUTPUT ;
    USE SIGNAL ;
    SHAPE ABUTMENT ;
    PORT
      LAYER metal3 ;
      RECT 0.000 309.645 0.070 309.715 ;
    END
  END rd_out[458]
  PIN rd_out[459]
    DIRECTION OUTPUT ;
    USE SIGNAL ;
    SHAPE ABUTMENT ;
    PORT
      LAYER metal3 ;
      RECT 0.000 309.925 0.070 309.995 ;
    END
  END rd_out[459]
  PIN rd_out[460]
    DIRECTION OUTPUT ;
    USE SIGNAL ;
    SHAPE ABUTMENT ;
    PORT
      LAYER metal3 ;
      RECT 0.000 310.205 0.070 310.275 ;
    END
  END rd_out[460]
  PIN rd_out[461]
    DIRECTION OUTPUT ;
    USE SIGNAL ;
    SHAPE ABUTMENT ;
    PORT
      LAYER metal3 ;
      RECT 0.000 310.485 0.070 310.555 ;
    END
  END rd_out[461]
  PIN rd_out[462]
    DIRECTION OUTPUT ;
    USE SIGNAL ;
    SHAPE ABUTMENT ;
    PORT
      LAYER metal3 ;
      RECT 0.000 310.765 0.070 310.835 ;
    END
  END rd_out[462]
  PIN rd_out[463]
    DIRECTION OUTPUT ;
    USE SIGNAL ;
    SHAPE ABUTMENT ;
    PORT
      LAYER metal3 ;
      RECT 0.000 311.045 0.070 311.115 ;
    END
  END rd_out[463]
  PIN rd_out[464]
    DIRECTION OUTPUT ;
    USE SIGNAL ;
    SHAPE ABUTMENT ;
    PORT
      LAYER metal3 ;
      RECT 0.000 311.325 0.070 311.395 ;
    END
  END rd_out[464]
  PIN rd_out[465]
    DIRECTION OUTPUT ;
    USE SIGNAL ;
    SHAPE ABUTMENT ;
    PORT
      LAYER metal3 ;
      RECT 0.000 311.605 0.070 311.675 ;
    END
  END rd_out[465]
  PIN rd_out[466]
    DIRECTION OUTPUT ;
    USE SIGNAL ;
    SHAPE ABUTMENT ;
    PORT
      LAYER metal3 ;
      RECT 0.000 311.885 0.070 311.955 ;
    END
  END rd_out[466]
  PIN rd_out[467]
    DIRECTION OUTPUT ;
    USE SIGNAL ;
    SHAPE ABUTMENT ;
    PORT
      LAYER metal3 ;
      RECT 0.000 312.165 0.070 312.235 ;
    END
  END rd_out[467]
  PIN rd_out[468]
    DIRECTION OUTPUT ;
    USE SIGNAL ;
    SHAPE ABUTMENT ;
    PORT
      LAYER metal3 ;
      RECT 0.000 312.445 0.070 312.515 ;
    END
  END rd_out[468]
  PIN rd_out[469]
    DIRECTION OUTPUT ;
    USE SIGNAL ;
    SHAPE ABUTMENT ;
    PORT
      LAYER metal3 ;
      RECT 0.000 312.725 0.070 312.795 ;
    END
  END rd_out[469]
  PIN rd_out[470]
    DIRECTION OUTPUT ;
    USE SIGNAL ;
    SHAPE ABUTMENT ;
    PORT
      LAYER metal3 ;
      RECT 0.000 313.005 0.070 313.075 ;
    END
  END rd_out[470]
  PIN rd_out[471]
    DIRECTION OUTPUT ;
    USE SIGNAL ;
    SHAPE ABUTMENT ;
    PORT
      LAYER metal3 ;
      RECT 0.000 313.285 0.070 313.355 ;
    END
  END rd_out[471]
  PIN rd_out[472]
    DIRECTION OUTPUT ;
    USE SIGNAL ;
    SHAPE ABUTMENT ;
    PORT
      LAYER metal3 ;
      RECT 0.000 313.565 0.070 313.635 ;
    END
  END rd_out[472]
  PIN rd_out[473]
    DIRECTION OUTPUT ;
    USE SIGNAL ;
    SHAPE ABUTMENT ;
    PORT
      LAYER metal3 ;
      RECT 0.000 313.845 0.070 313.915 ;
    END
  END rd_out[473]
  PIN rd_out[474]
    DIRECTION OUTPUT ;
    USE SIGNAL ;
    SHAPE ABUTMENT ;
    PORT
      LAYER metal3 ;
      RECT 0.000 314.125 0.070 314.195 ;
    END
  END rd_out[474]
  PIN rd_out[475]
    DIRECTION OUTPUT ;
    USE SIGNAL ;
    SHAPE ABUTMENT ;
    PORT
      LAYER metal3 ;
      RECT 0.000 314.405 0.070 314.475 ;
    END
  END rd_out[475]
  PIN rd_out[476]
    DIRECTION OUTPUT ;
    USE SIGNAL ;
    SHAPE ABUTMENT ;
    PORT
      LAYER metal3 ;
      RECT 0.000 314.685 0.070 314.755 ;
    END
  END rd_out[476]
  PIN rd_out[477]
    DIRECTION OUTPUT ;
    USE SIGNAL ;
    SHAPE ABUTMENT ;
    PORT
      LAYER metal3 ;
      RECT 0.000 314.965 0.070 315.035 ;
    END
  END rd_out[477]
  PIN rd_out[478]
    DIRECTION OUTPUT ;
    USE SIGNAL ;
    SHAPE ABUTMENT ;
    PORT
      LAYER metal3 ;
      RECT 0.000 315.245 0.070 315.315 ;
    END
  END rd_out[478]
  PIN rd_out[479]
    DIRECTION OUTPUT ;
    USE SIGNAL ;
    SHAPE ABUTMENT ;
    PORT
      LAYER metal3 ;
      RECT 0.000 315.525 0.070 315.595 ;
    END
  END rd_out[479]
  PIN rd_out[480]
    DIRECTION OUTPUT ;
    USE SIGNAL ;
    SHAPE ABUTMENT ;
    PORT
      LAYER metal3 ;
      RECT 0.000 315.805 0.070 315.875 ;
    END
  END rd_out[480]
  PIN rd_out[481]
    DIRECTION OUTPUT ;
    USE SIGNAL ;
    SHAPE ABUTMENT ;
    PORT
      LAYER metal3 ;
      RECT 0.000 316.085 0.070 316.155 ;
    END
  END rd_out[481]
  PIN rd_out[482]
    DIRECTION OUTPUT ;
    USE SIGNAL ;
    SHAPE ABUTMENT ;
    PORT
      LAYER metal3 ;
      RECT 0.000 316.365 0.070 316.435 ;
    END
  END rd_out[482]
  PIN rd_out[483]
    DIRECTION OUTPUT ;
    USE SIGNAL ;
    SHAPE ABUTMENT ;
    PORT
      LAYER metal3 ;
      RECT 0.000 316.645 0.070 316.715 ;
    END
  END rd_out[483]
  PIN rd_out[484]
    DIRECTION OUTPUT ;
    USE SIGNAL ;
    SHAPE ABUTMENT ;
    PORT
      LAYER metal3 ;
      RECT 0.000 316.925 0.070 316.995 ;
    END
  END rd_out[484]
  PIN rd_out[485]
    DIRECTION OUTPUT ;
    USE SIGNAL ;
    SHAPE ABUTMENT ;
    PORT
      LAYER metal3 ;
      RECT 0.000 317.205 0.070 317.275 ;
    END
  END rd_out[485]
  PIN rd_out[486]
    DIRECTION OUTPUT ;
    USE SIGNAL ;
    SHAPE ABUTMENT ;
    PORT
      LAYER metal3 ;
      RECT 0.000 317.485 0.070 317.555 ;
    END
  END rd_out[486]
  PIN rd_out[487]
    DIRECTION OUTPUT ;
    USE SIGNAL ;
    SHAPE ABUTMENT ;
    PORT
      LAYER metal3 ;
      RECT 0.000 317.765 0.070 317.835 ;
    END
  END rd_out[487]
  PIN rd_out[488]
    DIRECTION OUTPUT ;
    USE SIGNAL ;
    SHAPE ABUTMENT ;
    PORT
      LAYER metal3 ;
      RECT 0.000 318.045 0.070 318.115 ;
    END
  END rd_out[488]
  PIN rd_out[489]
    DIRECTION OUTPUT ;
    USE SIGNAL ;
    SHAPE ABUTMENT ;
    PORT
      LAYER metal3 ;
      RECT 0.000 318.325 0.070 318.395 ;
    END
  END rd_out[489]
  PIN rd_out[490]
    DIRECTION OUTPUT ;
    USE SIGNAL ;
    SHAPE ABUTMENT ;
    PORT
      LAYER metal3 ;
      RECT 0.000 318.605 0.070 318.675 ;
    END
  END rd_out[490]
  PIN rd_out[491]
    DIRECTION OUTPUT ;
    USE SIGNAL ;
    SHAPE ABUTMENT ;
    PORT
      LAYER metal3 ;
      RECT 0.000 318.885 0.070 318.955 ;
    END
  END rd_out[491]
  PIN rd_out[492]
    DIRECTION OUTPUT ;
    USE SIGNAL ;
    SHAPE ABUTMENT ;
    PORT
      LAYER metal3 ;
      RECT 0.000 319.165 0.070 319.235 ;
    END
  END rd_out[492]
  PIN rd_out[493]
    DIRECTION OUTPUT ;
    USE SIGNAL ;
    SHAPE ABUTMENT ;
    PORT
      LAYER metal3 ;
      RECT 0.000 319.445 0.070 319.515 ;
    END
  END rd_out[493]
  PIN rd_out[494]
    DIRECTION OUTPUT ;
    USE SIGNAL ;
    SHAPE ABUTMENT ;
    PORT
      LAYER metal3 ;
      RECT 0.000 319.725 0.070 319.795 ;
    END
  END rd_out[494]
  PIN rd_out[495]
    DIRECTION OUTPUT ;
    USE SIGNAL ;
    SHAPE ABUTMENT ;
    PORT
      LAYER metal3 ;
      RECT 0.000 320.005 0.070 320.075 ;
    END
  END rd_out[495]
  PIN rd_out[496]
    DIRECTION OUTPUT ;
    USE SIGNAL ;
    SHAPE ABUTMENT ;
    PORT
      LAYER metal3 ;
      RECT 0.000 320.285 0.070 320.355 ;
    END
  END rd_out[496]
  PIN rd_out[497]
    DIRECTION OUTPUT ;
    USE SIGNAL ;
    SHAPE ABUTMENT ;
    PORT
      LAYER metal3 ;
      RECT 0.000 320.565 0.070 320.635 ;
    END
  END rd_out[497]
  PIN rd_out[498]
    DIRECTION OUTPUT ;
    USE SIGNAL ;
    SHAPE ABUTMENT ;
    PORT
      LAYER metal3 ;
      RECT 0.000 320.845 0.070 320.915 ;
    END
  END rd_out[498]
  PIN rd_out[499]
    DIRECTION OUTPUT ;
    USE SIGNAL ;
    SHAPE ABUTMENT ;
    PORT
      LAYER metal3 ;
      RECT 0.000 321.125 0.070 321.195 ;
    END
  END rd_out[499]
  PIN rd_out[500]
    DIRECTION OUTPUT ;
    USE SIGNAL ;
    SHAPE ABUTMENT ;
    PORT
      LAYER metal3 ;
      RECT 0.000 321.405 0.070 321.475 ;
    END
  END rd_out[500]
  PIN rd_out[501]
    DIRECTION OUTPUT ;
    USE SIGNAL ;
    SHAPE ABUTMENT ;
    PORT
      LAYER metal3 ;
      RECT 0.000 321.685 0.070 321.755 ;
    END
  END rd_out[501]
  PIN rd_out[502]
    DIRECTION OUTPUT ;
    USE SIGNAL ;
    SHAPE ABUTMENT ;
    PORT
      LAYER metal3 ;
      RECT 0.000 321.965 0.070 322.035 ;
    END
  END rd_out[502]
  PIN rd_out[503]
    DIRECTION OUTPUT ;
    USE SIGNAL ;
    SHAPE ABUTMENT ;
    PORT
      LAYER metal3 ;
      RECT 0.000 322.245 0.070 322.315 ;
    END
  END rd_out[503]
  PIN rd_out[504]
    DIRECTION OUTPUT ;
    USE SIGNAL ;
    SHAPE ABUTMENT ;
    PORT
      LAYER metal3 ;
      RECT 0.000 322.525 0.070 322.595 ;
    END
  END rd_out[504]
  PIN rd_out[505]
    DIRECTION OUTPUT ;
    USE SIGNAL ;
    SHAPE ABUTMENT ;
    PORT
      LAYER metal3 ;
      RECT 0.000 322.805 0.070 322.875 ;
    END
  END rd_out[505]
  PIN rd_out[506]
    DIRECTION OUTPUT ;
    USE SIGNAL ;
    SHAPE ABUTMENT ;
    PORT
      LAYER metal3 ;
      RECT 0.000 323.085 0.070 323.155 ;
    END
  END rd_out[506]
  PIN rd_out[507]
    DIRECTION OUTPUT ;
    USE SIGNAL ;
    SHAPE ABUTMENT ;
    PORT
      LAYER metal3 ;
      RECT 0.000 323.365 0.070 323.435 ;
    END
  END rd_out[507]
  PIN rd_out[508]
    DIRECTION OUTPUT ;
    USE SIGNAL ;
    SHAPE ABUTMENT ;
    PORT
      LAYER metal3 ;
      RECT 0.000 323.645 0.070 323.715 ;
    END
  END rd_out[508]
  PIN rd_out[509]
    DIRECTION OUTPUT ;
    USE SIGNAL ;
    SHAPE ABUTMENT ;
    PORT
      LAYER metal3 ;
      RECT 0.000 323.925 0.070 323.995 ;
    END
  END rd_out[509]
  PIN rd_out[510]
    DIRECTION OUTPUT ;
    USE SIGNAL ;
    SHAPE ABUTMENT ;
    PORT
      LAYER metal3 ;
      RECT 0.000 324.205 0.070 324.275 ;
    END
  END rd_out[510]
  PIN rd_out[511]
    DIRECTION OUTPUT ;
    USE SIGNAL ;
    SHAPE ABUTMENT ;
    PORT
      LAYER metal3 ;
      RECT 0.000 324.485 0.070 324.555 ;
    END
  END rd_out[511]
  PIN wd_in[0]
    DIRECTION INPUT ;
    USE SIGNAL ;
    SHAPE ABUTMENT ;
    PORT
      LAYER metal3 ;
      RECT 0.000 361.445 0.070 361.515 ;
    END
  END wd_in[0]
  PIN wd_in[1]
    DIRECTION INPUT ;
    USE SIGNAL ;
    SHAPE ABUTMENT ;
    PORT
      LAYER metal3 ;
      RECT 0.000 361.725 0.070 361.795 ;
    END
  END wd_in[1]
  PIN wd_in[2]
    DIRECTION INPUT ;
    USE SIGNAL ;
    SHAPE ABUTMENT ;
    PORT
      LAYER metal3 ;
      RECT 0.000 362.005 0.070 362.075 ;
    END
  END wd_in[2]
  PIN wd_in[3]
    DIRECTION INPUT ;
    USE SIGNAL ;
    SHAPE ABUTMENT ;
    PORT
      LAYER metal3 ;
      RECT 0.000 362.285 0.070 362.355 ;
    END
  END wd_in[3]
  PIN wd_in[4]
    DIRECTION INPUT ;
    USE SIGNAL ;
    SHAPE ABUTMENT ;
    PORT
      LAYER metal3 ;
      RECT 0.000 362.565 0.070 362.635 ;
    END
  END wd_in[4]
  PIN wd_in[5]
    DIRECTION INPUT ;
    USE SIGNAL ;
    SHAPE ABUTMENT ;
    PORT
      LAYER metal3 ;
      RECT 0.000 362.845 0.070 362.915 ;
    END
  END wd_in[5]
  PIN wd_in[6]
    DIRECTION INPUT ;
    USE SIGNAL ;
    SHAPE ABUTMENT ;
    PORT
      LAYER metal3 ;
      RECT 0.000 363.125 0.070 363.195 ;
    END
  END wd_in[6]
  PIN wd_in[7]
    DIRECTION INPUT ;
    USE SIGNAL ;
    SHAPE ABUTMENT ;
    PORT
      LAYER metal3 ;
      RECT 0.000 363.405 0.070 363.475 ;
    END
  END wd_in[7]
  PIN wd_in[8]
    DIRECTION INPUT ;
    USE SIGNAL ;
    SHAPE ABUTMENT ;
    PORT
      LAYER metal3 ;
      RECT 0.000 363.685 0.070 363.755 ;
    END
  END wd_in[8]
  PIN wd_in[9]
    DIRECTION INPUT ;
    USE SIGNAL ;
    SHAPE ABUTMENT ;
    PORT
      LAYER metal3 ;
      RECT 0.000 363.965 0.070 364.035 ;
    END
  END wd_in[9]
  PIN wd_in[10]
    DIRECTION INPUT ;
    USE SIGNAL ;
    SHAPE ABUTMENT ;
    PORT
      LAYER metal3 ;
      RECT 0.000 364.245 0.070 364.315 ;
    END
  END wd_in[10]
  PIN wd_in[11]
    DIRECTION INPUT ;
    USE SIGNAL ;
    SHAPE ABUTMENT ;
    PORT
      LAYER metal3 ;
      RECT 0.000 364.525 0.070 364.595 ;
    END
  END wd_in[11]
  PIN wd_in[12]
    DIRECTION INPUT ;
    USE SIGNAL ;
    SHAPE ABUTMENT ;
    PORT
      LAYER metal3 ;
      RECT 0.000 364.805 0.070 364.875 ;
    END
  END wd_in[12]
  PIN wd_in[13]
    DIRECTION INPUT ;
    USE SIGNAL ;
    SHAPE ABUTMENT ;
    PORT
      LAYER metal3 ;
      RECT 0.000 365.085 0.070 365.155 ;
    END
  END wd_in[13]
  PIN wd_in[14]
    DIRECTION INPUT ;
    USE SIGNAL ;
    SHAPE ABUTMENT ;
    PORT
      LAYER metal3 ;
      RECT 0.000 365.365 0.070 365.435 ;
    END
  END wd_in[14]
  PIN wd_in[15]
    DIRECTION INPUT ;
    USE SIGNAL ;
    SHAPE ABUTMENT ;
    PORT
      LAYER metal3 ;
      RECT 0.000 365.645 0.070 365.715 ;
    END
  END wd_in[15]
  PIN wd_in[16]
    DIRECTION INPUT ;
    USE SIGNAL ;
    SHAPE ABUTMENT ;
    PORT
      LAYER metal3 ;
      RECT 0.000 365.925 0.070 365.995 ;
    END
  END wd_in[16]
  PIN wd_in[17]
    DIRECTION INPUT ;
    USE SIGNAL ;
    SHAPE ABUTMENT ;
    PORT
      LAYER metal3 ;
      RECT 0.000 366.205 0.070 366.275 ;
    END
  END wd_in[17]
  PIN wd_in[18]
    DIRECTION INPUT ;
    USE SIGNAL ;
    SHAPE ABUTMENT ;
    PORT
      LAYER metal3 ;
      RECT 0.000 366.485 0.070 366.555 ;
    END
  END wd_in[18]
  PIN wd_in[19]
    DIRECTION INPUT ;
    USE SIGNAL ;
    SHAPE ABUTMENT ;
    PORT
      LAYER metal3 ;
      RECT 0.000 366.765 0.070 366.835 ;
    END
  END wd_in[19]
  PIN wd_in[20]
    DIRECTION INPUT ;
    USE SIGNAL ;
    SHAPE ABUTMENT ;
    PORT
      LAYER metal3 ;
      RECT 0.000 367.045 0.070 367.115 ;
    END
  END wd_in[20]
  PIN wd_in[21]
    DIRECTION INPUT ;
    USE SIGNAL ;
    SHAPE ABUTMENT ;
    PORT
      LAYER metal3 ;
      RECT 0.000 367.325 0.070 367.395 ;
    END
  END wd_in[21]
  PIN wd_in[22]
    DIRECTION INPUT ;
    USE SIGNAL ;
    SHAPE ABUTMENT ;
    PORT
      LAYER metal3 ;
      RECT 0.000 367.605 0.070 367.675 ;
    END
  END wd_in[22]
  PIN wd_in[23]
    DIRECTION INPUT ;
    USE SIGNAL ;
    SHAPE ABUTMENT ;
    PORT
      LAYER metal3 ;
      RECT 0.000 367.885 0.070 367.955 ;
    END
  END wd_in[23]
  PIN wd_in[24]
    DIRECTION INPUT ;
    USE SIGNAL ;
    SHAPE ABUTMENT ;
    PORT
      LAYER metal3 ;
      RECT 0.000 368.165 0.070 368.235 ;
    END
  END wd_in[24]
  PIN wd_in[25]
    DIRECTION INPUT ;
    USE SIGNAL ;
    SHAPE ABUTMENT ;
    PORT
      LAYER metal3 ;
      RECT 0.000 368.445 0.070 368.515 ;
    END
  END wd_in[25]
  PIN wd_in[26]
    DIRECTION INPUT ;
    USE SIGNAL ;
    SHAPE ABUTMENT ;
    PORT
      LAYER metal3 ;
      RECT 0.000 368.725 0.070 368.795 ;
    END
  END wd_in[26]
  PIN wd_in[27]
    DIRECTION INPUT ;
    USE SIGNAL ;
    SHAPE ABUTMENT ;
    PORT
      LAYER metal3 ;
      RECT 0.000 369.005 0.070 369.075 ;
    END
  END wd_in[27]
  PIN wd_in[28]
    DIRECTION INPUT ;
    USE SIGNAL ;
    SHAPE ABUTMENT ;
    PORT
      LAYER metal3 ;
      RECT 0.000 369.285 0.070 369.355 ;
    END
  END wd_in[28]
  PIN wd_in[29]
    DIRECTION INPUT ;
    USE SIGNAL ;
    SHAPE ABUTMENT ;
    PORT
      LAYER metal3 ;
      RECT 0.000 369.565 0.070 369.635 ;
    END
  END wd_in[29]
  PIN wd_in[30]
    DIRECTION INPUT ;
    USE SIGNAL ;
    SHAPE ABUTMENT ;
    PORT
      LAYER metal3 ;
      RECT 0.000 369.845 0.070 369.915 ;
    END
  END wd_in[30]
  PIN wd_in[31]
    DIRECTION INPUT ;
    USE SIGNAL ;
    SHAPE ABUTMENT ;
    PORT
      LAYER metal3 ;
      RECT 0.000 370.125 0.070 370.195 ;
    END
  END wd_in[31]
  PIN wd_in[32]
    DIRECTION INPUT ;
    USE SIGNAL ;
    SHAPE ABUTMENT ;
    PORT
      LAYER metal3 ;
      RECT 0.000 370.405 0.070 370.475 ;
    END
  END wd_in[32]
  PIN wd_in[33]
    DIRECTION INPUT ;
    USE SIGNAL ;
    SHAPE ABUTMENT ;
    PORT
      LAYER metal3 ;
      RECT 0.000 370.685 0.070 370.755 ;
    END
  END wd_in[33]
  PIN wd_in[34]
    DIRECTION INPUT ;
    USE SIGNAL ;
    SHAPE ABUTMENT ;
    PORT
      LAYER metal3 ;
      RECT 0.000 370.965 0.070 371.035 ;
    END
  END wd_in[34]
  PIN wd_in[35]
    DIRECTION INPUT ;
    USE SIGNAL ;
    SHAPE ABUTMENT ;
    PORT
      LAYER metal3 ;
      RECT 0.000 371.245 0.070 371.315 ;
    END
  END wd_in[35]
  PIN wd_in[36]
    DIRECTION INPUT ;
    USE SIGNAL ;
    SHAPE ABUTMENT ;
    PORT
      LAYER metal3 ;
      RECT 0.000 371.525 0.070 371.595 ;
    END
  END wd_in[36]
  PIN wd_in[37]
    DIRECTION INPUT ;
    USE SIGNAL ;
    SHAPE ABUTMENT ;
    PORT
      LAYER metal3 ;
      RECT 0.000 371.805 0.070 371.875 ;
    END
  END wd_in[37]
  PIN wd_in[38]
    DIRECTION INPUT ;
    USE SIGNAL ;
    SHAPE ABUTMENT ;
    PORT
      LAYER metal3 ;
      RECT 0.000 372.085 0.070 372.155 ;
    END
  END wd_in[38]
  PIN wd_in[39]
    DIRECTION INPUT ;
    USE SIGNAL ;
    SHAPE ABUTMENT ;
    PORT
      LAYER metal3 ;
      RECT 0.000 372.365 0.070 372.435 ;
    END
  END wd_in[39]
  PIN wd_in[40]
    DIRECTION INPUT ;
    USE SIGNAL ;
    SHAPE ABUTMENT ;
    PORT
      LAYER metal3 ;
      RECT 0.000 372.645 0.070 372.715 ;
    END
  END wd_in[40]
  PIN wd_in[41]
    DIRECTION INPUT ;
    USE SIGNAL ;
    SHAPE ABUTMENT ;
    PORT
      LAYER metal3 ;
      RECT 0.000 372.925 0.070 372.995 ;
    END
  END wd_in[41]
  PIN wd_in[42]
    DIRECTION INPUT ;
    USE SIGNAL ;
    SHAPE ABUTMENT ;
    PORT
      LAYER metal3 ;
      RECT 0.000 373.205 0.070 373.275 ;
    END
  END wd_in[42]
  PIN wd_in[43]
    DIRECTION INPUT ;
    USE SIGNAL ;
    SHAPE ABUTMENT ;
    PORT
      LAYER metal3 ;
      RECT 0.000 373.485 0.070 373.555 ;
    END
  END wd_in[43]
  PIN wd_in[44]
    DIRECTION INPUT ;
    USE SIGNAL ;
    SHAPE ABUTMENT ;
    PORT
      LAYER metal3 ;
      RECT 0.000 373.765 0.070 373.835 ;
    END
  END wd_in[44]
  PIN wd_in[45]
    DIRECTION INPUT ;
    USE SIGNAL ;
    SHAPE ABUTMENT ;
    PORT
      LAYER metal3 ;
      RECT 0.000 374.045 0.070 374.115 ;
    END
  END wd_in[45]
  PIN wd_in[46]
    DIRECTION INPUT ;
    USE SIGNAL ;
    SHAPE ABUTMENT ;
    PORT
      LAYER metal3 ;
      RECT 0.000 374.325 0.070 374.395 ;
    END
  END wd_in[46]
  PIN wd_in[47]
    DIRECTION INPUT ;
    USE SIGNAL ;
    SHAPE ABUTMENT ;
    PORT
      LAYER metal3 ;
      RECT 0.000 374.605 0.070 374.675 ;
    END
  END wd_in[47]
  PIN wd_in[48]
    DIRECTION INPUT ;
    USE SIGNAL ;
    SHAPE ABUTMENT ;
    PORT
      LAYER metal3 ;
      RECT 0.000 374.885 0.070 374.955 ;
    END
  END wd_in[48]
  PIN wd_in[49]
    DIRECTION INPUT ;
    USE SIGNAL ;
    SHAPE ABUTMENT ;
    PORT
      LAYER metal3 ;
      RECT 0.000 375.165 0.070 375.235 ;
    END
  END wd_in[49]
  PIN wd_in[50]
    DIRECTION INPUT ;
    USE SIGNAL ;
    SHAPE ABUTMENT ;
    PORT
      LAYER metal3 ;
      RECT 0.000 375.445 0.070 375.515 ;
    END
  END wd_in[50]
  PIN wd_in[51]
    DIRECTION INPUT ;
    USE SIGNAL ;
    SHAPE ABUTMENT ;
    PORT
      LAYER metal3 ;
      RECT 0.000 375.725 0.070 375.795 ;
    END
  END wd_in[51]
  PIN wd_in[52]
    DIRECTION INPUT ;
    USE SIGNAL ;
    SHAPE ABUTMENT ;
    PORT
      LAYER metal3 ;
      RECT 0.000 376.005 0.070 376.075 ;
    END
  END wd_in[52]
  PIN wd_in[53]
    DIRECTION INPUT ;
    USE SIGNAL ;
    SHAPE ABUTMENT ;
    PORT
      LAYER metal3 ;
      RECT 0.000 376.285 0.070 376.355 ;
    END
  END wd_in[53]
  PIN wd_in[54]
    DIRECTION INPUT ;
    USE SIGNAL ;
    SHAPE ABUTMENT ;
    PORT
      LAYER metal3 ;
      RECT 0.000 376.565 0.070 376.635 ;
    END
  END wd_in[54]
  PIN wd_in[55]
    DIRECTION INPUT ;
    USE SIGNAL ;
    SHAPE ABUTMENT ;
    PORT
      LAYER metal3 ;
      RECT 0.000 376.845 0.070 376.915 ;
    END
  END wd_in[55]
  PIN wd_in[56]
    DIRECTION INPUT ;
    USE SIGNAL ;
    SHAPE ABUTMENT ;
    PORT
      LAYER metal3 ;
      RECT 0.000 377.125 0.070 377.195 ;
    END
  END wd_in[56]
  PIN wd_in[57]
    DIRECTION INPUT ;
    USE SIGNAL ;
    SHAPE ABUTMENT ;
    PORT
      LAYER metal3 ;
      RECT 0.000 377.405 0.070 377.475 ;
    END
  END wd_in[57]
  PIN wd_in[58]
    DIRECTION INPUT ;
    USE SIGNAL ;
    SHAPE ABUTMENT ;
    PORT
      LAYER metal3 ;
      RECT 0.000 377.685 0.070 377.755 ;
    END
  END wd_in[58]
  PIN wd_in[59]
    DIRECTION INPUT ;
    USE SIGNAL ;
    SHAPE ABUTMENT ;
    PORT
      LAYER metal3 ;
      RECT 0.000 377.965 0.070 378.035 ;
    END
  END wd_in[59]
  PIN wd_in[60]
    DIRECTION INPUT ;
    USE SIGNAL ;
    SHAPE ABUTMENT ;
    PORT
      LAYER metal3 ;
      RECT 0.000 378.245 0.070 378.315 ;
    END
  END wd_in[60]
  PIN wd_in[61]
    DIRECTION INPUT ;
    USE SIGNAL ;
    SHAPE ABUTMENT ;
    PORT
      LAYER metal3 ;
      RECT 0.000 378.525 0.070 378.595 ;
    END
  END wd_in[61]
  PIN wd_in[62]
    DIRECTION INPUT ;
    USE SIGNAL ;
    SHAPE ABUTMENT ;
    PORT
      LAYER metal3 ;
      RECT 0.000 378.805 0.070 378.875 ;
    END
  END wd_in[62]
  PIN wd_in[63]
    DIRECTION INPUT ;
    USE SIGNAL ;
    SHAPE ABUTMENT ;
    PORT
      LAYER metal3 ;
      RECT 0.000 379.085 0.070 379.155 ;
    END
  END wd_in[63]
  PIN wd_in[64]
    DIRECTION INPUT ;
    USE SIGNAL ;
    SHAPE ABUTMENT ;
    PORT
      LAYER metal3 ;
      RECT 0.000 379.365 0.070 379.435 ;
    END
  END wd_in[64]
  PIN wd_in[65]
    DIRECTION INPUT ;
    USE SIGNAL ;
    SHAPE ABUTMENT ;
    PORT
      LAYER metal3 ;
      RECT 0.000 379.645 0.070 379.715 ;
    END
  END wd_in[65]
  PIN wd_in[66]
    DIRECTION INPUT ;
    USE SIGNAL ;
    SHAPE ABUTMENT ;
    PORT
      LAYER metal3 ;
      RECT 0.000 379.925 0.070 379.995 ;
    END
  END wd_in[66]
  PIN wd_in[67]
    DIRECTION INPUT ;
    USE SIGNAL ;
    SHAPE ABUTMENT ;
    PORT
      LAYER metal3 ;
      RECT 0.000 380.205 0.070 380.275 ;
    END
  END wd_in[67]
  PIN wd_in[68]
    DIRECTION INPUT ;
    USE SIGNAL ;
    SHAPE ABUTMENT ;
    PORT
      LAYER metal3 ;
      RECT 0.000 380.485 0.070 380.555 ;
    END
  END wd_in[68]
  PIN wd_in[69]
    DIRECTION INPUT ;
    USE SIGNAL ;
    SHAPE ABUTMENT ;
    PORT
      LAYER metal3 ;
      RECT 0.000 380.765 0.070 380.835 ;
    END
  END wd_in[69]
  PIN wd_in[70]
    DIRECTION INPUT ;
    USE SIGNAL ;
    SHAPE ABUTMENT ;
    PORT
      LAYER metal3 ;
      RECT 0.000 381.045 0.070 381.115 ;
    END
  END wd_in[70]
  PIN wd_in[71]
    DIRECTION INPUT ;
    USE SIGNAL ;
    SHAPE ABUTMENT ;
    PORT
      LAYER metal3 ;
      RECT 0.000 381.325 0.070 381.395 ;
    END
  END wd_in[71]
  PIN wd_in[72]
    DIRECTION INPUT ;
    USE SIGNAL ;
    SHAPE ABUTMENT ;
    PORT
      LAYER metal3 ;
      RECT 0.000 381.605 0.070 381.675 ;
    END
  END wd_in[72]
  PIN wd_in[73]
    DIRECTION INPUT ;
    USE SIGNAL ;
    SHAPE ABUTMENT ;
    PORT
      LAYER metal3 ;
      RECT 0.000 381.885 0.070 381.955 ;
    END
  END wd_in[73]
  PIN wd_in[74]
    DIRECTION INPUT ;
    USE SIGNAL ;
    SHAPE ABUTMENT ;
    PORT
      LAYER metal3 ;
      RECT 0.000 382.165 0.070 382.235 ;
    END
  END wd_in[74]
  PIN wd_in[75]
    DIRECTION INPUT ;
    USE SIGNAL ;
    SHAPE ABUTMENT ;
    PORT
      LAYER metal3 ;
      RECT 0.000 382.445 0.070 382.515 ;
    END
  END wd_in[75]
  PIN wd_in[76]
    DIRECTION INPUT ;
    USE SIGNAL ;
    SHAPE ABUTMENT ;
    PORT
      LAYER metal3 ;
      RECT 0.000 382.725 0.070 382.795 ;
    END
  END wd_in[76]
  PIN wd_in[77]
    DIRECTION INPUT ;
    USE SIGNAL ;
    SHAPE ABUTMENT ;
    PORT
      LAYER metal3 ;
      RECT 0.000 383.005 0.070 383.075 ;
    END
  END wd_in[77]
  PIN wd_in[78]
    DIRECTION INPUT ;
    USE SIGNAL ;
    SHAPE ABUTMENT ;
    PORT
      LAYER metal3 ;
      RECT 0.000 383.285 0.070 383.355 ;
    END
  END wd_in[78]
  PIN wd_in[79]
    DIRECTION INPUT ;
    USE SIGNAL ;
    SHAPE ABUTMENT ;
    PORT
      LAYER metal3 ;
      RECT 0.000 383.565 0.070 383.635 ;
    END
  END wd_in[79]
  PIN wd_in[80]
    DIRECTION INPUT ;
    USE SIGNAL ;
    SHAPE ABUTMENT ;
    PORT
      LAYER metal3 ;
      RECT 0.000 383.845 0.070 383.915 ;
    END
  END wd_in[80]
  PIN wd_in[81]
    DIRECTION INPUT ;
    USE SIGNAL ;
    SHAPE ABUTMENT ;
    PORT
      LAYER metal3 ;
      RECT 0.000 384.125 0.070 384.195 ;
    END
  END wd_in[81]
  PIN wd_in[82]
    DIRECTION INPUT ;
    USE SIGNAL ;
    SHAPE ABUTMENT ;
    PORT
      LAYER metal3 ;
      RECT 0.000 384.405 0.070 384.475 ;
    END
  END wd_in[82]
  PIN wd_in[83]
    DIRECTION INPUT ;
    USE SIGNAL ;
    SHAPE ABUTMENT ;
    PORT
      LAYER metal3 ;
      RECT 0.000 384.685 0.070 384.755 ;
    END
  END wd_in[83]
  PIN wd_in[84]
    DIRECTION INPUT ;
    USE SIGNAL ;
    SHAPE ABUTMENT ;
    PORT
      LAYER metal3 ;
      RECT 0.000 384.965 0.070 385.035 ;
    END
  END wd_in[84]
  PIN wd_in[85]
    DIRECTION INPUT ;
    USE SIGNAL ;
    SHAPE ABUTMENT ;
    PORT
      LAYER metal3 ;
      RECT 0.000 385.245 0.070 385.315 ;
    END
  END wd_in[85]
  PIN wd_in[86]
    DIRECTION INPUT ;
    USE SIGNAL ;
    SHAPE ABUTMENT ;
    PORT
      LAYER metal3 ;
      RECT 0.000 385.525 0.070 385.595 ;
    END
  END wd_in[86]
  PIN wd_in[87]
    DIRECTION INPUT ;
    USE SIGNAL ;
    SHAPE ABUTMENT ;
    PORT
      LAYER metal3 ;
      RECT 0.000 385.805 0.070 385.875 ;
    END
  END wd_in[87]
  PIN wd_in[88]
    DIRECTION INPUT ;
    USE SIGNAL ;
    SHAPE ABUTMENT ;
    PORT
      LAYER metal3 ;
      RECT 0.000 386.085 0.070 386.155 ;
    END
  END wd_in[88]
  PIN wd_in[89]
    DIRECTION INPUT ;
    USE SIGNAL ;
    SHAPE ABUTMENT ;
    PORT
      LAYER metal3 ;
      RECT 0.000 386.365 0.070 386.435 ;
    END
  END wd_in[89]
  PIN wd_in[90]
    DIRECTION INPUT ;
    USE SIGNAL ;
    SHAPE ABUTMENT ;
    PORT
      LAYER metal3 ;
      RECT 0.000 386.645 0.070 386.715 ;
    END
  END wd_in[90]
  PIN wd_in[91]
    DIRECTION INPUT ;
    USE SIGNAL ;
    SHAPE ABUTMENT ;
    PORT
      LAYER metal3 ;
      RECT 0.000 386.925 0.070 386.995 ;
    END
  END wd_in[91]
  PIN wd_in[92]
    DIRECTION INPUT ;
    USE SIGNAL ;
    SHAPE ABUTMENT ;
    PORT
      LAYER metal3 ;
      RECT 0.000 387.205 0.070 387.275 ;
    END
  END wd_in[92]
  PIN wd_in[93]
    DIRECTION INPUT ;
    USE SIGNAL ;
    SHAPE ABUTMENT ;
    PORT
      LAYER metal3 ;
      RECT 0.000 387.485 0.070 387.555 ;
    END
  END wd_in[93]
  PIN wd_in[94]
    DIRECTION INPUT ;
    USE SIGNAL ;
    SHAPE ABUTMENT ;
    PORT
      LAYER metal3 ;
      RECT 0.000 387.765 0.070 387.835 ;
    END
  END wd_in[94]
  PIN wd_in[95]
    DIRECTION INPUT ;
    USE SIGNAL ;
    SHAPE ABUTMENT ;
    PORT
      LAYER metal3 ;
      RECT 0.000 388.045 0.070 388.115 ;
    END
  END wd_in[95]
  PIN wd_in[96]
    DIRECTION INPUT ;
    USE SIGNAL ;
    SHAPE ABUTMENT ;
    PORT
      LAYER metal3 ;
      RECT 0.000 388.325 0.070 388.395 ;
    END
  END wd_in[96]
  PIN wd_in[97]
    DIRECTION INPUT ;
    USE SIGNAL ;
    SHAPE ABUTMENT ;
    PORT
      LAYER metal3 ;
      RECT 0.000 388.605 0.070 388.675 ;
    END
  END wd_in[97]
  PIN wd_in[98]
    DIRECTION INPUT ;
    USE SIGNAL ;
    SHAPE ABUTMENT ;
    PORT
      LAYER metal3 ;
      RECT 0.000 388.885 0.070 388.955 ;
    END
  END wd_in[98]
  PIN wd_in[99]
    DIRECTION INPUT ;
    USE SIGNAL ;
    SHAPE ABUTMENT ;
    PORT
      LAYER metal3 ;
      RECT 0.000 389.165 0.070 389.235 ;
    END
  END wd_in[99]
  PIN wd_in[100]
    DIRECTION INPUT ;
    USE SIGNAL ;
    SHAPE ABUTMENT ;
    PORT
      LAYER metal3 ;
      RECT 0.000 389.445 0.070 389.515 ;
    END
  END wd_in[100]
  PIN wd_in[101]
    DIRECTION INPUT ;
    USE SIGNAL ;
    SHAPE ABUTMENT ;
    PORT
      LAYER metal3 ;
      RECT 0.000 389.725 0.070 389.795 ;
    END
  END wd_in[101]
  PIN wd_in[102]
    DIRECTION INPUT ;
    USE SIGNAL ;
    SHAPE ABUTMENT ;
    PORT
      LAYER metal3 ;
      RECT 0.000 390.005 0.070 390.075 ;
    END
  END wd_in[102]
  PIN wd_in[103]
    DIRECTION INPUT ;
    USE SIGNAL ;
    SHAPE ABUTMENT ;
    PORT
      LAYER metal3 ;
      RECT 0.000 390.285 0.070 390.355 ;
    END
  END wd_in[103]
  PIN wd_in[104]
    DIRECTION INPUT ;
    USE SIGNAL ;
    SHAPE ABUTMENT ;
    PORT
      LAYER metal3 ;
      RECT 0.000 390.565 0.070 390.635 ;
    END
  END wd_in[104]
  PIN wd_in[105]
    DIRECTION INPUT ;
    USE SIGNAL ;
    SHAPE ABUTMENT ;
    PORT
      LAYER metal3 ;
      RECT 0.000 390.845 0.070 390.915 ;
    END
  END wd_in[105]
  PIN wd_in[106]
    DIRECTION INPUT ;
    USE SIGNAL ;
    SHAPE ABUTMENT ;
    PORT
      LAYER metal3 ;
      RECT 0.000 391.125 0.070 391.195 ;
    END
  END wd_in[106]
  PIN wd_in[107]
    DIRECTION INPUT ;
    USE SIGNAL ;
    SHAPE ABUTMENT ;
    PORT
      LAYER metal3 ;
      RECT 0.000 391.405 0.070 391.475 ;
    END
  END wd_in[107]
  PIN wd_in[108]
    DIRECTION INPUT ;
    USE SIGNAL ;
    SHAPE ABUTMENT ;
    PORT
      LAYER metal3 ;
      RECT 0.000 391.685 0.070 391.755 ;
    END
  END wd_in[108]
  PIN wd_in[109]
    DIRECTION INPUT ;
    USE SIGNAL ;
    SHAPE ABUTMENT ;
    PORT
      LAYER metal3 ;
      RECT 0.000 391.965 0.070 392.035 ;
    END
  END wd_in[109]
  PIN wd_in[110]
    DIRECTION INPUT ;
    USE SIGNAL ;
    SHAPE ABUTMENT ;
    PORT
      LAYER metal3 ;
      RECT 0.000 392.245 0.070 392.315 ;
    END
  END wd_in[110]
  PIN wd_in[111]
    DIRECTION INPUT ;
    USE SIGNAL ;
    SHAPE ABUTMENT ;
    PORT
      LAYER metal3 ;
      RECT 0.000 392.525 0.070 392.595 ;
    END
  END wd_in[111]
  PIN wd_in[112]
    DIRECTION INPUT ;
    USE SIGNAL ;
    SHAPE ABUTMENT ;
    PORT
      LAYER metal3 ;
      RECT 0.000 392.805 0.070 392.875 ;
    END
  END wd_in[112]
  PIN wd_in[113]
    DIRECTION INPUT ;
    USE SIGNAL ;
    SHAPE ABUTMENT ;
    PORT
      LAYER metal3 ;
      RECT 0.000 393.085 0.070 393.155 ;
    END
  END wd_in[113]
  PIN wd_in[114]
    DIRECTION INPUT ;
    USE SIGNAL ;
    SHAPE ABUTMENT ;
    PORT
      LAYER metal3 ;
      RECT 0.000 393.365 0.070 393.435 ;
    END
  END wd_in[114]
  PIN wd_in[115]
    DIRECTION INPUT ;
    USE SIGNAL ;
    SHAPE ABUTMENT ;
    PORT
      LAYER metal3 ;
      RECT 0.000 393.645 0.070 393.715 ;
    END
  END wd_in[115]
  PIN wd_in[116]
    DIRECTION INPUT ;
    USE SIGNAL ;
    SHAPE ABUTMENT ;
    PORT
      LAYER metal3 ;
      RECT 0.000 393.925 0.070 393.995 ;
    END
  END wd_in[116]
  PIN wd_in[117]
    DIRECTION INPUT ;
    USE SIGNAL ;
    SHAPE ABUTMENT ;
    PORT
      LAYER metal3 ;
      RECT 0.000 394.205 0.070 394.275 ;
    END
  END wd_in[117]
  PIN wd_in[118]
    DIRECTION INPUT ;
    USE SIGNAL ;
    SHAPE ABUTMENT ;
    PORT
      LAYER metal3 ;
      RECT 0.000 394.485 0.070 394.555 ;
    END
  END wd_in[118]
  PIN wd_in[119]
    DIRECTION INPUT ;
    USE SIGNAL ;
    SHAPE ABUTMENT ;
    PORT
      LAYER metal3 ;
      RECT 0.000 394.765 0.070 394.835 ;
    END
  END wd_in[119]
  PIN wd_in[120]
    DIRECTION INPUT ;
    USE SIGNAL ;
    SHAPE ABUTMENT ;
    PORT
      LAYER metal3 ;
      RECT 0.000 395.045 0.070 395.115 ;
    END
  END wd_in[120]
  PIN wd_in[121]
    DIRECTION INPUT ;
    USE SIGNAL ;
    SHAPE ABUTMENT ;
    PORT
      LAYER metal3 ;
      RECT 0.000 395.325 0.070 395.395 ;
    END
  END wd_in[121]
  PIN wd_in[122]
    DIRECTION INPUT ;
    USE SIGNAL ;
    SHAPE ABUTMENT ;
    PORT
      LAYER metal3 ;
      RECT 0.000 395.605 0.070 395.675 ;
    END
  END wd_in[122]
  PIN wd_in[123]
    DIRECTION INPUT ;
    USE SIGNAL ;
    SHAPE ABUTMENT ;
    PORT
      LAYER metal3 ;
      RECT 0.000 395.885 0.070 395.955 ;
    END
  END wd_in[123]
  PIN wd_in[124]
    DIRECTION INPUT ;
    USE SIGNAL ;
    SHAPE ABUTMENT ;
    PORT
      LAYER metal3 ;
      RECT 0.000 396.165 0.070 396.235 ;
    END
  END wd_in[124]
  PIN wd_in[125]
    DIRECTION INPUT ;
    USE SIGNAL ;
    SHAPE ABUTMENT ;
    PORT
      LAYER metal3 ;
      RECT 0.000 396.445 0.070 396.515 ;
    END
  END wd_in[125]
  PIN wd_in[126]
    DIRECTION INPUT ;
    USE SIGNAL ;
    SHAPE ABUTMENT ;
    PORT
      LAYER metal3 ;
      RECT 0.000 396.725 0.070 396.795 ;
    END
  END wd_in[126]
  PIN wd_in[127]
    DIRECTION INPUT ;
    USE SIGNAL ;
    SHAPE ABUTMENT ;
    PORT
      LAYER metal3 ;
      RECT 0.000 397.005 0.070 397.075 ;
    END
  END wd_in[127]
  PIN wd_in[128]
    DIRECTION INPUT ;
    USE SIGNAL ;
    SHAPE ABUTMENT ;
    PORT
      LAYER metal3 ;
      RECT 0.000 397.285 0.070 397.355 ;
    END
  END wd_in[128]
  PIN wd_in[129]
    DIRECTION INPUT ;
    USE SIGNAL ;
    SHAPE ABUTMENT ;
    PORT
      LAYER metal3 ;
      RECT 0.000 397.565 0.070 397.635 ;
    END
  END wd_in[129]
  PIN wd_in[130]
    DIRECTION INPUT ;
    USE SIGNAL ;
    SHAPE ABUTMENT ;
    PORT
      LAYER metal3 ;
      RECT 0.000 397.845 0.070 397.915 ;
    END
  END wd_in[130]
  PIN wd_in[131]
    DIRECTION INPUT ;
    USE SIGNAL ;
    SHAPE ABUTMENT ;
    PORT
      LAYER metal3 ;
      RECT 0.000 398.125 0.070 398.195 ;
    END
  END wd_in[131]
  PIN wd_in[132]
    DIRECTION INPUT ;
    USE SIGNAL ;
    SHAPE ABUTMENT ;
    PORT
      LAYER metal3 ;
      RECT 0.000 398.405 0.070 398.475 ;
    END
  END wd_in[132]
  PIN wd_in[133]
    DIRECTION INPUT ;
    USE SIGNAL ;
    SHAPE ABUTMENT ;
    PORT
      LAYER metal3 ;
      RECT 0.000 398.685 0.070 398.755 ;
    END
  END wd_in[133]
  PIN wd_in[134]
    DIRECTION INPUT ;
    USE SIGNAL ;
    SHAPE ABUTMENT ;
    PORT
      LAYER metal3 ;
      RECT 0.000 398.965 0.070 399.035 ;
    END
  END wd_in[134]
  PIN wd_in[135]
    DIRECTION INPUT ;
    USE SIGNAL ;
    SHAPE ABUTMENT ;
    PORT
      LAYER metal3 ;
      RECT 0.000 399.245 0.070 399.315 ;
    END
  END wd_in[135]
  PIN wd_in[136]
    DIRECTION INPUT ;
    USE SIGNAL ;
    SHAPE ABUTMENT ;
    PORT
      LAYER metal3 ;
      RECT 0.000 399.525 0.070 399.595 ;
    END
  END wd_in[136]
  PIN wd_in[137]
    DIRECTION INPUT ;
    USE SIGNAL ;
    SHAPE ABUTMENT ;
    PORT
      LAYER metal3 ;
      RECT 0.000 399.805 0.070 399.875 ;
    END
  END wd_in[137]
  PIN wd_in[138]
    DIRECTION INPUT ;
    USE SIGNAL ;
    SHAPE ABUTMENT ;
    PORT
      LAYER metal3 ;
      RECT 0.000 400.085 0.070 400.155 ;
    END
  END wd_in[138]
  PIN wd_in[139]
    DIRECTION INPUT ;
    USE SIGNAL ;
    SHAPE ABUTMENT ;
    PORT
      LAYER metal3 ;
      RECT 0.000 400.365 0.070 400.435 ;
    END
  END wd_in[139]
  PIN wd_in[140]
    DIRECTION INPUT ;
    USE SIGNAL ;
    SHAPE ABUTMENT ;
    PORT
      LAYER metal3 ;
      RECT 0.000 400.645 0.070 400.715 ;
    END
  END wd_in[140]
  PIN wd_in[141]
    DIRECTION INPUT ;
    USE SIGNAL ;
    SHAPE ABUTMENT ;
    PORT
      LAYER metal3 ;
      RECT 0.000 400.925 0.070 400.995 ;
    END
  END wd_in[141]
  PIN wd_in[142]
    DIRECTION INPUT ;
    USE SIGNAL ;
    SHAPE ABUTMENT ;
    PORT
      LAYER metal3 ;
      RECT 0.000 401.205 0.070 401.275 ;
    END
  END wd_in[142]
  PIN wd_in[143]
    DIRECTION INPUT ;
    USE SIGNAL ;
    SHAPE ABUTMENT ;
    PORT
      LAYER metal3 ;
      RECT 0.000 401.485 0.070 401.555 ;
    END
  END wd_in[143]
  PIN wd_in[144]
    DIRECTION INPUT ;
    USE SIGNAL ;
    SHAPE ABUTMENT ;
    PORT
      LAYER metal3 ;
      RECT 0.000 401.765 0.070 401.835 ;
    END
  END wd_in[144]
  PIN wd_in[145]
    DIRECTION INPUT ;
    USE SIGNAL ;
    SHAPE ABUTMENT ;
    PORT
      LAYER metal3 ;
      RECT 0.000 402.045 0.070 402.115 ;
    END
  END wd_in[145]
  PIN wd_in[146]
    DIRECTION INPUT ;
    USE SIGNAL ;
    SHAPE ABUTMENT ;
    PORT
      LAYER metal3 ;
      RECT 0.000 402.325 0.070 402.395 ;
    END
  END wd_in[146]
  PIN wd_in[147]
    DIRECTION INPUT ;
    USE SIGNAL ;
    SHAPE ABUTMENT ;
    PORT
      LAYER metal3 ;
      RECT 0.000 402.605 0.070 402.675 ;
    END
  END wd_in[147]
  PIN wd_in[148]
    DIRECTION INPUT ;
    USE SIGNAL ;
    SHAPE ABUTMENT ;
    PORT
      LAYER metal3 ;
      RECT 0.000 402.885 0.070 402.955 ;
    END
  END wd_in[148]
  PIN wd_in[149]
    DIRECTION INPUT ;
    USE SIGNAL ;
    SHAPE ABUTMENT ;
    PORT
      LAYER metal3 ;
      RECT 0.000 403.165 0.070 403.235 ;
    END
  END wd_in[149]
  PIN wd_in[150]
    DIRECTION INPUT ;
    USE SIGNAL ;
    SHAPE ABUTMENT ;
    PORT
      LAYER metal3 ;
      RECT 0.000 403.445 0.070 403.515 ;
    END
  END wd_in[150]
  PIN wd_in[151]
    DIRECTION INPUT ;
    USE SIGNAL ;
    SHAPE ABUTMENT ;
    PORT
      LAYER metal3 ;
      RECT 0.000 403.725 0.070 403.795 ;
    END
  END wd_in[151]
  PIN wd_in[152]
    DIRECTION INPUT ;
    USE SIGNAL ;
    SHAPE ABUTMENT ;
    PORT
      LAYER metal3 ;
      RECT 0.000 404.005 0.070 404.075 ;
    END
  END wd_in[152]
  PIN wd_in[153]
    DIRECTION INPUT ;
    USE SIGNAL ;
    SHAPE ABUTMENT ;
    PORT
      LAYER metal3 ;
      RECT 0.000 404.285 0.070 404.355 ;
    END
  END wd_in[153]
  PIN wd_in[154]
    DIRECTION INPUT ;
    USE SIGNAL ;
    SHAPE ABUTMENT ;
    PORT
      LAYER metal3 ;
      RECT 0.000 404.565 0.070 404.635 ;
    END
  END wd_in[154]
  PIN wd_in[155]
    DIRECTION INPUT ;
    USE SIGNAL ;
    SHAPE ABUTMENT ;
    PORT
      LAYER metal3 ;
      RECT 0.000 404.845 0.070 404.915 ;
    END
  END wd_in[155]
  PIN wd_in[156]
    DIRECTION INPUT ;
    USE SIGNAL ;
    SHAPE ABUTMENT ;
    PORT
      LAYER metal3 ;
      RECT 0.000 405.125 0.070 405.195 ;
    END
  END wd_in[156]
  PIN wd_in[157]
    DIRECTION INPUT ;
    USE SIGNAL ;
    SHAPE ABUTMENT ;
    PORT
      LAYER metal3 ;
      RECT 0.000 405.405 0.070 405.475 ;
    END
  END wd_in[157]
  PIN wd_in[158]
    DIRECTION INPUT ;
    USE SIGNAL ;
    SHAPE ABUTMENT ;
    PORT
      LAYER metal3 ;
      RECT 0.000 405.685 0.070 405.755 ;
    END
  END wd_in[158]
  PIN wd_in[159]
    DIRECTION INPUT ;
    USE SIGNAL ;
    SHAPE ABUTMENT ;
    PORT
      LAYER metal3 ;
      RECT 0.000 405.965 0.070 406.035 ;
    END
  END wd_in[159]
  PIN wd_in[160]
    DIRECTION INPUT ;
    USE SIGNAL ;
    SHAPE ABUTMENT ;
    PORT
      LAYER metal3 ;
      RECT 0.000 406.245 0.070 406.315 ;
    END
  END wd_in[160]
  PIN wd_in[161]
    DIRECTION INPUT ;
    USE SIGNAL ;
    SHAPE ABUTMENT ;
    PORT
      LAYER metal3 ;
      RECT 0.000 406.525 0.070 406.595 ;
    END
  END wd_in[161]
  PIN wd_in[162]
    DIRECTION INPUT ;
    USE SIGNAL ;
    SHAPE ABUTMENT ;
    PORT
      LAYER metal3 ;
      RECT 0.000 406.805 0.070 406.875 ;
    END
  END wd_in[162]
  PIN wd_in[163]
    DIRECTION INPUT ;
    USE SIGNAL ;
    SHAPE ABUTMENT ;
    PORT
      LAYER metal3 ;
      RECT 0.000 407.085 0.070 407.155 ;
    END
  END wd_in[163]
  PIN wd_in[164]
    DIRECTION INPUT ;
    USE SIGNAL ;
    SHAPE ABUTMENT ;
    PORT
      LAYER metal3 ;
      RECT 0.000 407.365 0.070 407.435 ;
    END
  END wd_in[164]
  PIN wd_in[165]
    DIRECTION INPUT ;
    USE SIGNAL ;
    SHAPE ABUTMENT ;
    PORT
      LAYER metal3 ;
      RECT 0.000 407.645 0.070 407.715 ;
    END
  END wd_in[165]
  PIN wd_in[166]
    DIRECTION INPUT ;
    USE SIGNAL ;
    SHAPE ABUTMENT ;
    PORT
      LAYER metal3 ;
      RECT 0.000 407.925 0.070 407.995 ;
    END
  END wd_in[166]
  PIN wd_in[167]
    DIRECTION INPUT ;
    USE SIGNAL ;
    SHAPE ABUTMENT ;
    PORT
      LAYER metal3 ;
      RECT 0.000 408.205 0.070 408.275 ;
    END
  END wd_in[167]
  PIN wd_in[168]
    DIRECTION INPUT ;
    USE SIGNAL ;
    SHAPE ABUTMENT ;
    PORT
      LAYER metal3 ;
      RECT 0.000 408.485 0.070 408.555 ;
    END
  END wd_in[168]
  PIN wd_in[169]
    DIRECTION INPUT ;
    USE SIGNAL ;
    SHAPE ABUTMENT ;
    PORT
      LAYER metal3 ;
      RECT 0.000 408.765 0.070 408.835 ;
    END
  END wd_in[169]
  PIN wd_in[170]
    DIRECTION INPUT ;
    USE SIGNAL ;
    SHAPE ABUTMENT ;
    PORT
      LAYER metal3 ;
      RECT 0.000 409.045 0.070 409.115 ;
    END
  END wd_in[170]
  PIN wd_in[171]
    DIRECTION INPUT ;
    USE SIGNAL ;
    SHAPE ABUTMENT ;
    PORT
      LAYER metal3 ;
      RECT 0.000 409.325 0.070 409.395 ;
    END
  END wd_in[171]
  PIN wd_in[172]
    DIRECTION INPUT ;
    USE SIGNAL ;
    SHAPE ABUTMENT ;
    PORT
      LAYER metal3 ;
      RECT 0.000 409.605 0.070 409.675 ;
    END
  END wd_in[172]
  PIN wd_in[173]
    DIRECTION INPUT ;
    USE SIGNAL ;
    SHAPE ABUTMENT ;
    PORT
      LAYER metal3 ;
      RECT 0.000 409.885 0.070 409.955 ;
    END
  END wd_in[173]
  PIN wd_in[174]
    DIRECTION INPUT ;
    USE SIGNAL ;
    SHAPE ABUTMENT ;
    PORT
      LAYER metal3 ;
      RECT 0.000 410.165 0.070 410.235 ;
    END
  END wd_in[174]
  PIN wd_in[175]
    DIRECTION INPUT ;
    USE SIGNAL ;
    SHAPE ABUTMENT ;
    PORT
      LAYER metal3 ;
      RECT 0.000 410.445 0.070 410.515 ;
    END
  END wd_in[175]
  PIN wd_in[176]
    DIRECTION INPUT ;
    USE SIGNAL ;
    SHAPE ABUTMENT ;
    PORT
      LAYER metal3 ;
      RECT 0.000 410.725 0.070 410.795 ;
    END
  END wd_in[176]
  PIN wd_in[177]
    DIRECTION INPUT ;
    USE SIGNAL ;
    SHAPE ABUTMENT ;
    PORT
      LAYER metal3 ;
      RECT 0.000 411.005 0.070 411.075 ;
    END
  END wd_in[177]
  PIN wd_in[178]
    DIRECTION INPUT ;
    USE SIGNAL ;
    SHAPE ABUTMENT ;
    PORT
      LAYER metal3 ;
      RECT 0.000 411.285 0.070 411.355 ;
    END
  END wd_in[178]
  PIN wd_in[179]
    DIRECTION INPUT ;
    USE SIGNAL ;
    SHAPE ABUTMENT ;
    PORT
      LAYER metal3 ;
      RECT 0.000 411.565 0.070 411.635 ;
    END
  END wd_in[179]
  PIN wd_in[180]
    DIRECTION INPUT ;
    USE SIGNAL ;
    SHAPE ABUTMENT ;
    PORT
      LAYER metal3 ;
      RECT 0.000 411.845 0.070 411.915 ;
    END
  END wd_in[180]
  PIN wd_in[181]
    DIRECTION INPUT ;
    USE SIGNAL ;
    SHAPE ABUTMENT ;
    PORT
      LAYER metal3 ;
      RECT 0.000 412.125 0.070 412.195 ;
    END
  END wd_in[181]
  PIN wd_in[182]
    DIRECTION INPUT ;
    USE SIGNAL ;
    SHAPE ABUTMENT ;
    PORT
      LAYER metal3 ;
      RECT 0.000 412.405 0.070 412.475 ;
    END
  END wd_in[182]
  PIN wd_in[183]
    DIRECTION INPUT ;
    USE SIGNAL ;
    SHAPE ABUTMENT ;
    PORT
      LAYER metal3 ;
      RECT 0.000 412.685 0.070 412.755 ;
    END
  END wd_in[183]
  PIN wd_in[184]
    DIRECTION INPUT ;
    USE SIGNAL ;
    SHAPE ABUTMENT ;
    PORT
      LAYER metal3 ;
      RECT 0.000 412.965 0.070 413.035 ;
    END
  END wd_in[184]
  PIN wd_in[185]
    DIRECTION INPUT ;
    USE SIGNAL ;
    SHAPE ABUTMENT ;
    PORT
      LAYER metal3 ;
      RECT 0.000 413.245 0.070 413.315 ;
    END
  END wd_in[185]
  PIN wd_in[186]
    DIRECTION INPUT ;
    USE SIGNAL ;
    SHAPE ABUTMENT ;
    PORT
      LAYER metal3 ;
      RECT 0.000 413.525 0.070 413.595 ;
    END
  END wd_in[186]
  PIN wd_in[187]
    DIRECTION INPUT ;
    USE SIGNAL ;
    SHAPE ABUTMENT ;
    PORT
      LAYER metal3 ;
      RECT 0.000 413.805 0.070 413.875 ;
    END
  END wd_in[187]
  PIN wd_in[188]
    DIRECTION INPUT ;
    USE SIGNAL ;
    SHAPE ABUTMENT ;
    PORT
      LAYER metal3 ;
      RECT 0.000 414.085 0.070 414.155 ;
    END
  END wd_in[188]
  PIN wd_in[189]
    DIRECTION INPUT ;
    USE SIGNAL ;
    SHAPE ABUTMENT ;
    PORT
      LAYER metal3 ;
      RECT 0.000 414.365 0.070 414.435 ;
    END
  END wd_in[189]
  PIN wd_in[190]
    DIRECTION INPUT ;
    USE SIGNAL ;
    SHAPE ABUTMENT ;
    PORT
      LAYER metal3 ;
      RECT 0.000 414.645 0.070 414.715 ;
    END
  END wd_in[190]
  PIN wd_in[191]
    DIRECTION INPUT ;
    USE SIGNAL ;
    SHAPE ABUTMENT ;
    PORT
      LAYER metal3 ;
      RECT 0.000 414.925 0.070 414.995 ;
    END
  END wd_in[191]
  PIN wd_in[192]
    DIRECTION INPUT ;
    USE SIGNAL ;
    SHAPE ABUTMENT ;
    PORT
      LAYER metal3 ;
      RECT 0.000 415.205 0.070 415.275 ;
    END
  END wd_in[192]
  PIN wd_in[193]
    DIRECTION INPUT ;
    USE SIGNAL ;
    SHAPE ABUTMENT ;
    PORT
      LAYER metal3 ;
      RECT 0.000 415.485 0.070 415.555 ;
    END
  END wd_in[193]
  PIN wd_in[194]
    DIRECTION INPUT ;
    USE SIGNAL ;
    SHAPE ABUTMENT ;
    PORT
      LAYER metal3 ;
      RECT 0.000 415.765 0.070 415.835 ;
    END
  END wd_in[194]
  PIN wd_in[195]
    DIRECTION INPUT ;
    USE SIGNAL ;
    SHAPE ABUTMENT ;
    PORT
      LAYER metal3 ;
      RECT 0.000 416.045 0.070 416.115 ;
    END
  END wd_in[195]
  PIN wd_in[196]
    DIRECTION INPUT ;
    USE SIGNAL ;
    SHAPE ABUTMENT ;
    PORT
      LAYER metal3 ;
      RECT 0.000 416.325 0.070 416.395 ;
    END
  END wd_in[196]
  PIN wd_in[197]
    DIRECTION INPUT ;
    USE SIGNAL ;
    SHAPE ABUTMENT ;
    PORT
      LAYER metal3 ;
      RECT 0.000 416.605 0.070 416.675 ;
    END
  END wd_in[197]
  PIN wd_in[198]
    DIRECTION INPUT ;
    USE SIGNAL ;
    SHAPE ABUTMENT ;
    PORT
      LAYER metal3 ;
      RECT 0.000 416.885 0.070 416.955 ;
    END
  END wd_in[198]
  PIN wd_in[199]
    DIRECTION INPUT ;
    USE SIGNAL ;
    SHAPE ABUTMENT ;
    PORT
      LAYER metal3 ;
      RECT 0.000 417.165 0.070 417.235 ;
    END
  END wd_in[199]
  PIN wd_in[200]
    DIRECTION INPUT ;
    USE SIGNAL ;
    SHAPE ABUTMENT ;
    PORT
      LAYER metal3 ;
      RECT 0.000 417.445 0.070 417.515 ;
    END
  END wd_in[200]
  PIN wd_in[201]
    DIRECTION INPUT ;
    USE SIGNAL ;
    SHAPE ABUTMENT ;
    PORT
      LAYER metal3 ;
      RECT 0.000 417.725 0.070 417.795 ;
    END
  END wd_in[201]
  PIN wd_in[202]
    DIRECTION INPUT ;
    USE SIGNAL ;
    SHAPE ABUTMENT ;
    PORT
      LAYER metal3 ;
      RECT 0.000 418.005 0.070 418.075 ;
    END
  END wd_in[202]
  PIN wd_in[203]
    DIRECTION INPUT ;
    USE SIGNAL ;
    SHAPE ABUTMENT ;
    PORT
      LAYER metal3 ;
      RECT 0.000 418.285 0.070 418.355 ;
    END
  END wd_in[203]
  PIN wd_in[204]
    DIRECTION INPUT ;
    USE SIGNAL ;
    SHAPE ABUTMENT ;
    PORT
      LAYER metal3 ;
      RECT 0.000 418.565 0.070 418.635 ;
    END
  END wd_in[204]
  PIN wd_in[205]
    DIRECTION INPUT ;
    USE SIGNAL ;
    SHAPE ABUTMENT ;
    PORT
      LAYER metal3 ;
      RECT 0.000 418.845 0.070 418.915 ;
    END
  END wd_in[205]
  PIN wd_in[206]
    DIRECTION INPUT ;
    USE SIGNAL ;
    SHAPE ABUTMENT ;
    PORT
      LAYER metal3 ;
      RECT 0.000 419.125 0.070 419.195 ;
    END
  END wd_in[206]
  PIN wd_in[207]
    DIRECTION INPUT ;
    USE SIGNAL ;
    SHAPE ABUTMENT ;
    PORT
      LAYER metal3 ;
      RECT 0.000 419.405 0.070 419.475 ;
    END
  END wd_in[207]
  PIN wd_in[208]
    DIRECTION INPUT ;
    USE SIGNAL ;
    SHAPE ABUTMENT ;
    PORT
      LAYER metal3 ;
      RECT 0.000 419.685 0.070 419.755 ;
    END
  END wd_in[208]
  PIN wd_in[209]
    DIRECTION INPUT ;
    USE SIGNAL ;
    SHAPE ABUTMENT ;
    PORT
      LAYER metal3 ;
      RECT 0.000 419.965 0.070 420.035 ;
    END
  END wd_in[209]
  PIN wd_in[210]
    DIRECTION INPUT ;
    USE SIGNAL ;
    SHAPE ABUTMENT ;
    PORT
      LAYER metal3 ;
      RECT 0.000 420.245 0.070 420.315 ;
    END
  END wd_in[210]
  PIN wd_in[211]
    DIRECTION INPUT ;
    USE SIGNAL ;
    SHAPE ABUTMENT ;
    PORT
      LAYER metal3 ;
      RECT 0.000 420.525 0.070 420.595 ;
    END
  END wd_in[211]
  PIN wd_in[212]
    DIRECTION INPUT ;
    USE SIGNAL ;
    SHAPE ABUTMENT ;
    PORT
      LAYER metal3 ;
      RECT 0.000 420.805 0.070 420.875 ;
    END
  END wd_in[212]
  PIN wd_in[213]
    DIRECTION INPUT ;
    USE SIGNAL ;
    SHAPE ABUTMENT ;
    PORT
      LAYER metal3 ;
      RECT 0.000 421.085 0.070 421.155 ;
    END
  END wd_in[213]
  PIN wd_in[214]
    DIRECTION INPUT ;
    USE SIGNAL ;
    SHAPE ABUTMENT ;
    PORT
      LAYER metal3 ;
      RECT 0.000 421.365 0.070 421.435 ;
    END
  END wd_in[214]
  PIN wd_in[215]
    DIRECTION INPUT ;
    USE SIGNAL ;
    SHAPE ABUTMENT ;
    PORT
      LAYER metal3 ;
      RECT 0.000 421.645 0.070 421.715 ;
    END
  END wd_in[215]
  PIN wd_in[216]
    DIRECTION INPUT ;
    USE SIGNAL ;
    SHAPE ABUTMENT ;
    PORT
      LAYER metal3 ;
      RECT 0.000 421.925 0.070 421.995 ;
    END
  END wd_in[216]
  PIN wd_in[217]
    DIRECTION INPUT ;
    USE SIGNAL ;
    SHAPE ABUTMENT ;
    PORT
      LAYER metal3 ;
      RECT 0.000 422.205 0.070 422.275 ;
    END
  END wd_in[217]
  PIN wd_in[218]
    DIRECTION INPUT ;
    USE SIGNAL ;
    SHAPE ABUTMENT ;
    PORT
      LAYER metal3 ;
      RECT 0.000 422.485 0.070 422.555 ;
    END
  END wd_in[218]
  PIN wd_in[219]
    DIRECTION INPUT ;
    USE SIGNAL ;
    SHAPE ABUTMENT ;
    PORT
      LAYER metal3 ;
      RECT 0.000 422.765 0.070 422.835 ;
    END
  END wd_in[219]
  PIN wd_in[220]
    DIRECTION INPUT ;
    USE SIGNAL ;
    SHAPE ABUTMENT ;
    PORT
      LAYER metal3 ;
      RECT 0.000 423.045 0.070 423.115 ;
    END
  END wd_in[220]
  PIN wd_in[221]
    DIRECTION INPUT ;
    USE SIGNAL ;
    SHAPE ABUTMENT ;
    PORT
      LAYER metal3 ;
      RECT 0.000 423.325 0.070 423.395 ;
    END
  END wd_in[221]
  PIN wd_in[222]
    DIRECTION INPUT ;
    USE SIGNAL ;
    SHAPE ABUTMENT ;
    PORT
      LAYER metal3 ;
      RECT 0.000 423.605 0.070 423.675 ;
    END
  END wd_in[222]
  PIN wd_in[223]
    DIRECTION INPUT ;
    USE SIGNAL ;
    SHAPE ABUTMENT ;
    PORT
      LAYER metal3 ;
      RECT 0.000 423.885 0.070 423.955 ;
    END
  END wd_in[223]
  PIN wd_in[224]
    DIRECTION INPUT ;
    USE SIGNAL ;
    SHAPE ABUTMENT ;
    PORT
      LAYER metal3 ;
      RECT 0.000 424.165 0.070 424.235 ;
    END
  END wd_in[224]
  PIN wd_in[225]
    DIRECTION INPUT ;
    USE SIGNAL ;
    SHAPE ABUTMENT ;
    PORT
      LAYER metal3 ;
      RECT 0.000 424.445 0.070 424.515 ;
    END
  END wd_in[225]
  PIN wd_in[226]
    DIRECTION INPUT ;
    USE SIGNAL ;
    SHAPE ABUTMENT ;
    PORT
      LAYER metal3 ;
      RECT 0.000 424.725 0.070 424.795 ;
    END
  END wd_in[226]
  PIN wd_in[227]
    DIRECTION INPUT ;
    USE SIGNAL ;
    SHAPE ABUTMENT ;
    PORT
      LAYER metal3 ;
      RECT 0.000 425.005 0.070 425.075 ;
    END
  END wd_in[227]
  PIN wd_in[228]
    DIRECTION INPUT ;
    USE SIGNAL ;
    SHAPE ABUTMENT ;
    PORT
      LAYER metal3 ;
      RECT 0.000 425.285 0.070 425.355 ;
    END
  END wd_in[228]
  PIN wd_in[229]
    DIRECTION INPUT ;
    USE SIGNAL ;
    SHAPE ABUTMENT ;
    PORT
      LAYER metal3 ;
      RECT 0.000 425.565 0.070 425.635 ;
    END
  END wd_in[229]
  PIN wd_in[230]
    DIRECTION INPUT ;
    USE SIGNAL ;
    SHAPE ABUTMENT ;
    PORT
      LAYER metal3 ;
      RECT 0.000 425.845 0.070 425.915 ;
    END
  END wd_in[230]
  PIN wd_in[231]
    DIRECTION INPUT ;
    USE SIGNAL ;
    SHAPE ABUTMENT ;
    PORT
      LAYER metal3 ;
      RECT 0.000 426.125 0.070 426.195 ;
    END
  END wd_in[231]
  PIN wd_in[232]
    DIRECTION INPUT ;
    USE SIGNAL ;
    SHAPE ABUTMENT ;
    PORT
      LAYER metal3 ;
      RECT 0.000 426.405 0.070 426.475 ;
    END
  END wd_in[232]
  PIN wd_in[233]
    DIRECTION INPUT ;
    USE SIGNAL ;
    SHAPE ABUTMENT ;
    PORT
      LAYER metal3 ;
      RECT 0.000 426.685 0.070 426.755 ;
    END
  END wd_in[233]
  PIN wd_in[234]
    DIRECTION INPUT ;
    USE SIGNAL ;
    SHAPE ABUTMENT ;
    PORT
      LAYER metal3 ;
      RECT 0.000 426.965 0.070 427.035 ;
    END
  END wd_in[234]
  PIN wd_in[235]
    DIRECTION INPUT ;
    USE SIGNAL ;
    SHAPE ABUTMENT ;
    PORT
      LAYER metal3 ;
      RECT 0.000 427.245 0.070 427.315 ;
    END
  END wd_in[235]
  PIN wd_in[236]
    DIRECTION INPUT ;
    USE SIGNAL ;
    SHAPE ABUTMENT ;
    PORT
      LAYER metal3 ;
      RECT 0.000 427.525 0.070 427.595 ;
    END
  END wd_in[236]
  PIN wd_in[237]
    DIRECTION INPUT ;
    USE SIGNAL ;
    SHAPE ABUTMENT ;
    PORT
      LAYER metal3 ;
      RECT 0.000 427.805 0.070 427.875 ;
    END
  END wd_in[237]
  PIN wd_in[238]
    DIRECTION INPUT ;
    USE SIGNAL ;
    SHAPE ABUTMENT ;
    PORT
      LAYER metal3 ;
      RECT 0.000 428.085 0.070 428.155 ;
    END
  END wd_in[238]
  PIN wd_in[239]
    DIRECTION INPUT ;
    USE SIGNAL ;
    SHAPE ABUTMENT ;
    PORT
      LAYER metal3 ;
      RECT 0.000 428.365 0.070 428.435 ;
    END
  END wd_in[239]
  PIN wd_in[240]
    DIRECTION INPUT ;
    USE SIGNAL ;
    SHAPE ABUTMENT ;
    PORT
      LAYER metal3 ;
      RECT 0.000 428.645 0.070 428.715 ;
    END
  END wd_in[240]
  PIN wd_in[241]
    DIRECTION INPUT ;
    USE SIGNAL ;
    SHAPE ABUTMENT ;
    PORT
      LAYER metal3 ;
      RECT 0.000 428.925 0.070 428.995 ;
    END
  END wd_in[241]
  PIN wd_in[242]
    DIRECTION INPUT ;
    USE SIGNAL ;
    SHAPE ABUTMENT ;
    PORT
      LAYER metal3 ;
      RECT 0.000 429.205 0.070 429.275 ;
    END
  END wd_in[242]
  PIN wd_in[243]
    DIRECTION INPUT ;
    USE SIGNAL ;
    SHAPE ABUTMENT ;
    PORT
      LAYER metal3 ;
      RECT 0.000 429.485 0.070 429.555 ;
    END
  END wd_in[243]
  PIN wd_in[244]
    DIRECTION INPUT ;
    USE SIGNAL ;
    SHAPE ABUTMENT ;
    PORT
      LAYER metal3 ;
      RECT 0.000 429.765 0.070 429.835 ;
    END
  END wd_in[244]
  PIN wd_in[245]
    DIRECTION INPUT ;
    USE SIGNAL ;
    SHAPE ABUTMENT ;
    PORT
      LAYER metal3 ;
      RECT 0.000 430.045 0.070 430.115 ;
    END
  END wd_in[245]
  PIN wd_in[246]
    DIRECTION INPUT ;
    USE SIGNAL ;
    SHAPE ABUTMENT ;
    PORT
      LAYER metal3 ;
      RECT 0.000 430.325 0.070 430.395 ;
    END
  END wd_in[246]
  PIN wd_in[247]
    DIRECTION INPUT ;
    USE SIGNAL ;
    SHAPE ABUTMENT ;
    PORT
      LAYER metal3 ;
      RECT 0.000 430.605 0.070 430.675 ;
    END
  END wd_in[247]
  PIN wd_in[248]
    DIRECTION INPUT ;
    USE SIGNAL ;
    SHAPE ABUTMENT ;
    PORT
      LAYER metal3 ;
      RECT 0.000 430.885 0.070 430.955 ;
    END
  END wd_in[248]
  PIN wd_in[249]
    DIRECTION INPUT ;
    USE SIGNAL ;
    SHAPE ABUTMENT ;
    PORT
      LAYER metal3 ;
      RECT 0.000 431.165 0.070 431.235 ;
    END
  END wd_in[249]
  PIN wd_in[250]
    DIRECTION INPUT ;
    USE SIGNAL ;
    SHAPE ABUTMENT ;
    PORT
      LAYER metal3 ;
      RECT 0.000 431.445 0.070 431.515 ;
    END
  END wd_in[250]
  PIN wd_in[251]
    DIRECTION INPUT ;
    USE SIGNAL ;
    SHAPE ABUTMENT ;
    PORT
      LAYER metal3 ;
      RECT 0.000 431.725 0.070 431.795 ;
    END
  END wd_in[251]
  PIN wd_in[252]
    DIRECTION INPUT ;
    USE SIGNAL ;
    SHAPE ABUTMENT ;
    PORT
      LAYER metal3 ;
      RECT 0.000 432.005 0.070 432.075 ;
    END
  END wd_in[252]
  PIN wd_in[253]
    DIRECTION INPUT ;
    USE SIGNAL ;
    SHAPE ABUTMENT ;
    PORT
      LAYER metal3 ;
      RECT 0.000 432.285 0.070 432.355 ;
    END
  END wd_in[253]
  PIN wd_in[254]
    DIRECTION INPUT ;
    USE SIGNAL ;
    SHAPE ABUTMENT ;
    PORT
      LAYER metal3 ;
      RECT 0.000 432.565 0.070 432.635 ;
    END
  END wd_in[254]
  PIN wd_in[255]
    DIRECTION INPUT ;
    USE SIGNAL ;
    SHAPE ABUTMENT ;
    PORT
      LAYER metal3 ;
      RECT 0.000 432.845 0.070 432.915 ;
    END
  END wd_in[255]
  PIN wd_in[256]
    DIRECTION INPUT ;
    USE SIGNAL ;
    SHAPE ABUTMENT ;
    PORT
      LAYER metal3 ;
      RECT 0.000 433.125 0.070 433.195 ;
    END
  END wd_in[256]
  PIN wd_in[257]
    DIRECTION INPUT ;
    USE SIGNAL ;
    SHAPE ABUTMENT ;
    PORT
      LAYER metal3 ;
      RECT 0.000 433.405 0.070 433.475 ;
    END
  END wd_in[257]
  PIN wd_in[258]
    DIRECTION INPUT ;
    USE SIGNAL ;
    SHAPE ABUTMENT ;
    PORT
      LAYER metal3 ;
      RECT 0.000 433.685 0.070 433.755 ;
    END
  END wd_in[258]
  PIN wd_in[259]
    DIRECTION INPUT ;
    USE SIGNAL ;
    SHAPE ABUTMENT ;
    PORT
      LAYER metal3 ;
      RECT 0.000 433.965 0.070 434.035 ;
    END
  END wd_in[259]
  PIN wd_in[260]
    DIRECTION INPUT ;
    USE SIGNAL ;
    SHAPE ABUTMENT ;
    PORT
      LAYER metal3 ;
      RECT 0.000 434.245 0.070 434.315 ;
    END
  END wd_in[260]
  PIN wd_in[261]
    DIRECTION INPUT ;
    USE SIGNAL ;
    SHAPE ABUTMENT ;
    PORT
      LAYER metal3 ;
      RECT 0.000 434.525 0.070 434.595 ;
    END
  END wd_in[261]
  PIN wd_in[262]
    DIRECTION INPUT ;
    USE SIGNAL ;
    SHAPE ABUTMENT ;
    PORT
      LAYER metal3 ;
      RECT 0.000 434.805 0.070 434.875 ;
    END
  END wd_in[262]
  PIN wd_in[263]
    DIRECTION INPUT ;
    USE SIGNAL ;
    SHAPE ABUTMENT ;
    PORT
      LAYER metal3 ;
      RECT 0.000 435.085 0.070 435.155 ;
    END
  END wd_in[263]
  PIN wd_in[264]
    DIRECTION INPUT ;
    USE SIGNAL ;
    SHAPE ABUTMENT ;
    PORT
      LAYER metal3 ;
      RECT 0.000 435.365 0.070 435.435 ;
    END
  END wd_in[264]
  PIN wd_in[265]
    DIRECTION INPUT ;
    USE SIGNAL ;
    SHAPE ABUTMENT ;
    PORT
      LAYER metal3 ;
      RECT 0.000 435.645 0.070 435.715 ;
    END
  END wd_in[265]
  PIN wd_in[266]
    DIRECTION INPUT ;
    USE SIGNAL ;
    SHAPE ABUTMENT ;
    PORT
      LAYER metal3 ;
      RECT 0.000 435.925 0.070 435.995 ;
    END
  END wd_in[266]
  PIN wd_in[267]
    DIRECTION INPUT ;
    USE SIGNAL ;
    SHAPE ABUTMENT ;
    PORT
      LAYER metal3 ;
      RECT 0.000 436.205 0.070 436.275 ;
    END
  END wd_in[267]
  PIN wd_in[268]
    DIRECTION INPUT ;
    USE SIGNAL ;
    SHAPE ABUTMENT ;
    PORT
      LAYER metal3 ;
      RECT 0.000 436.485 0.070 436.555 ;
    END
  END wd_in[268]
  PIN wd_in[269]
    DIRECTION INPUT ;
    USE SIGNAL ;
    SHAPE ABUTMENT ;
    PORT
      LAYER metal3 ;
      RECT 0.000 436.765 0.070 436.835 ;
    END
  END wd_in[269]
  PIN wd_in[270]
    DIRECTION INPUT ;
    USE SIGNAL ;
    SHAPE ABUTMENT ;
    PORT
      LAYER metal3 ;
      RECT 0.000 437.045 0.070 437.115 ;
    END
  END wd_in[270]
  PIN wd_in[271]
    DIRECTION INPUT ;
    USE SIGNAL ;
    SHAPE ABUTMENT ;
    PORT
      LAYER metal3 ;
      RECT 0.000 437.325 0.070 437.395 ;
    END
  END wd_in[271]
  PIN wd_in[272]
    DIRECTION INPUT ;
    USE SIGNAL ;
    SHAPE ABUTMENT ;
    PORT
      LAYER metal3 ;
      RECT 0.000 437.605 0.070 437.675 ;
    END
  END wd_in[272]
  PIN wd_in[273]
    DIRECTION INPUT ;
    USE SIGNAL ;
    SHAPE ABUTMENT ;
    PORT
      LAYER metal3 ;
      RECT 0.000 437.885 0.070 437.955 ;
    END
  END wd_in[273]
  PIN wd_in[274]
    DIRECTION INPUT ;
    USE SIGNAL ;
    SHAPE ABUTMENT ;
    PORT
      LAYER metal3 ;
      RECT 0.000 438.165 0.070 438.235 ;
    END
  END wd_in[274]
  PIN wd_in[275]
    DIRECTION INPUT ;
    USE SIGNAL ;
    SHAPE ABUTMENT ;
    PORT
      LAYER metal3 ;
      RECT 0.000 438.445 0.070 438.515 ;
    END
  END wd_in[275]
  PIN wd_in[276]
    DIRECTION INPUT ;
    USE SIGNAL ;
    SHAPE ABUTMENT ;
    PORT
      LAYER metal3 ;
      RECT 0.000 438.725 0.070 438.795 ;
    END
  END wd_in[276]
  PIN wd_in[277]
    DIRECTION INPUT ;
    USE SIGNAL ;
    SHAPE ABUTMENT ;
    PORT
      LAYER metal3 ;
      RECT 0.000 439.005 0.070 439.075 ;
    END
  END wd_in[277]
  PIN wd_in[278]
    DIRECTION INPUT ;
    USE SIGNAL ;
    SHAPE ABUTMENT ;
    PORT
      LAYER metal3 ;
      RECT 0.000 439.285 0.070 439.355 ;
    END
  END wd_in[278]
  PIN wd_in[279]
    DIRECTION INPUT ;
    USE SIGNAL ;
    SHAPE ABUTMENT ;
    PORT
      LAYER metal3 ;
      RECT 0.000 439.565 0.070 439.635 ;
    END
  END wd_in[279]
  PIN wd_in[280]
    DIRECTION INPUT ;
    USE SIGNAL ;
    SHAPE ABUTMENT ;
    PORT
      LAYER metal3 ;
      RECT 0.000 439.845 0.070 439.915 ;
    END
  END wd_in[280]
  PIN wd_in[281]
    DIRECTION INPUT ;
    USE SIGNAL ;
    SHAPE ABUTMENT ;
    PORT
      LAYER metal3 ;
      RECT 0.000 440.125 0.070 440.195 ;
    END
  END wd_in[281]
  PIN wd_in[282]
    DIRECTION INPUT ;
    USE SIGNAL ;
    SHAPE ABUTMENT ;
    PORT
      LAYER metal3 ;
      RECT 0.000 440.405 0.070 440.475 ;
    END
  END wd_in[282]
  PIN wd_in[283]
    DIRECTION INPUT ;
    USE SIGNAL ;
    SHAPE ABUTMENT ;
    PORT
      LAYER metal3 ;
      RECT 0.000 440.685 0.070 440.755 ;
    END
  END wd_in[283]
  PIN wd_in[284]
    DIRECTION INPUT ;
    USE SIGNAL ;
    SHAPE ABUTMENT ;
    PORT
      LAYER metal3 ;
      RECT 0.000 440.965 0.070 441.035 ;
    END
  END wd_in[284]
  PIN wd_in[285]
    DIRECTION INPUT ;
    USE SIGNAL ;
    SHAPE ABUTMENT ;
    PORT
      LAYER metal3 ;
      RECT 0.000 441.245 0.070 441.315 ;
    END
  END wd_in[285]
  PIN wd_in[286]
    DIRECTION INPUT ;
    USE SIGNAL ;
    SHAPE ABUTMENT ;
    PORT
      LAYER metal3 ;
      RECT 0.000 441.525 0.070 441.595 ;
    END
  END wd_in[286]
  PIN wd_in[287]
    DIRECTION INPUT ;
    USE SIGNAL ;
    SHAPE ABUTMENT ;
    PORT
      LAYER metal3 ;
      RECT 0.000 441.805 0.070 441.875 ;
    END
  END wd_in[287]
  PIN wd_in[288]
    DIRECTION INPUT ;
    USE SIGNAL ;
    SHAPE ABUTMENT ;
    PORT
      LAYER metal3 ;
      RECT 0.000 442.085 0.070 442.155 ;
    END
  END wd_in[288]
  PIN wd_in[289]
    DIRECTION INPUT ;
    USE SIGNAL ;
    SHAPE ABUTMENT ;
    PORT
      LAYER metal3 ;
      RECT 0.000 442.365 0.070 442.435 ;
    END
  END wd_in[289]
  PIN wd_in[290]
    DIRECTION INPUT ;
    USE SIGNAL ;
    SHAPE ABUTMENT ;
    PORT
      LAYER metal3 ;
      RECT 0.000 442.645 0.070 442.715 ;
    END
  END wd_in[290]
  PIN wd_in[291]
    DIRECTION INPUT ;
    USE SIGNAL ;
    SHAPE ABUTMENT ;
    PORT
      LAYER metal3 ;
      RECT 0.000 442.925 0.070 442.995 ;
    END
  END wd_in[291]
  PIN wd_in[292]
    DIRECTION INPUT ;
    USE SIGNAL ;
    SHAPE ABUTMENT ;
    PORT
      LAYER metal3 ;
      RECT 0.000 443.205 0.070 443.275 ;
    END
  END wd_in[292]
  PIN wd_in[293]
    DIRECTION INPUT ;
    USE SIGNAL ;
    SHAPE ABUTMENT ;
    PORT
      LAYER metal3 ;
      RECT 0.000 443.485 0.070 443.555 ;
    END
  END wd_in[293]
  PIN wd_in[294]
    DIRECTION INPUT ;
    USE SIGNAL ;
    SHAPE ABUTMENT ;
    PORT
      LAYER metal3 ;
      RECT 0.000 443.765 0.070 443.835 ;
    END
  END wd_in[294]
  PIN wd_in[295]
    DIRECTION INPUT ;
    USE SIGNAL ;
    SHAPE ABUTMENT ;
    PORT
      LAYER metal3 ;
      RECT 0.000 444.045 0.070 444.115 ;
    END
  END wd_in[295]
  PIN wd_in[296]
    DIRECTION INPUT ;
    USE SIGNAL ;
    SHAPE ABUTMENT ;
    PORT
      LAYER metal3 ;
      RECT 0.000 444.325 0.070 444.395 ;
    END
  END wd_in[296]
  PIN wd_in[297]
    DIRECTION INPUT ;
    USE SIGNAL ;
    SHAPE ABUTMENT ;
    PORT
      LAYER metal3 ;
      RECT 0.000 444.605 0.070 444.675 ;
    END
  END wd_in[297]
  PIN wd_in[298]
    DIRECTION INPUT ;
    USE SIGNAL ;
    SHAPE ABUTMENT ;
    PORT
      LAYER metal3 ;
      RECT 0.000 444.885 0.070 444.955 ;
    END
  END wd_in[298]
  PIN wd_in[299]
    DIRECTION INPUT ;
    USE SIGNAL ;
    SHAPE ABUTMENT ;
    PORT
      LAYER metal3 ;
      RECT 0.000 445.165 0.070 445.235 ;
    END
  END wd_in[299]
  PIN wd_in[300]
    DIRECTION INPUT ;
    USE SIGNAL ;
    SHAPE ABUTMENT ;
    PORT
      LAYER metal3 ;
      RECT 0.000 445.445 0.070 445.515 ;
    END
  END wd_in[300]
  PIN wd_in[301]
    DIRECTION INPUT ;
    USE SIGNAL ;
    SHAPE ABUTMENT ;
    PORT
      LAYER metal3 ;
      RECT 0.000 445.725 0.070 445.795 ;
    END
  END wd_in[301]
  PIN wd_in[302]
    DIRECTION INPUT ;
    USE SIGNAL ;
    SHAPE ABUTMENT ;
    PORT
      LAYER metal3 ;
      RECT 0.000 446.005 0.070 446.075 ;
    END
  END wd_in[302]
  PIN wd_in[303]
    DIRECTION INPUT ;
    USE SIGNAL ;
    SHAPE ABUTMENT ;
    PORT
      LAYER metal3 ;
      RECT 0.000 446.285 0.070 446.355 ;
    END
  END wd_in[303]
  PIN wd_in[304]
    DIRECTION INPUT ;
    USE SIGNAL ;
    SHAPE ABUTMENT ;
    PORT
      LAYER metal3 ;
      RECT 0.000 446.565 0.070 446.635 ;
    END
  END wd_in[304]
  PIN wd_in[305]
    DIRECTION INPUT ;
    USE SIGNAL ;
    SHAPE ABUTMENT ;
    PORT
      LAYER metal3 ;
      RECT 0.000 446.845 0.070 446.915 ;
    END
  END wd_in[305]
  PIN wd_in[306]
    DIRECTION INPUT ;
    USE SIGNAL ;
    SHAPE ABUTMENT ;
    PORT
      LAYER metal3 ;
      RECT 0.000 447.125 0.070 447.195 ;
    END
  END wd_in[306]
  PIN wd_in[307]
    DIRECTION INPUT ;
    USE SIGNAL ;
    SHAPE ABUTMENT ;
    PORT
      LAYER metal3 ;
      RECT 0.000 447.405 0.070 447.475 ;
    END
  END wd_in[307]
  PIN wd_in[308]
    DIRECTION INPUT ;
    USE SIGNAL ;
    SHAPE ABUTMENT ;
    PORT
      LAYER metal3 ;
      RECT 0.000 447.685 0.070 447.755 ;
    END
  END wd_in[308]
  PIN wd_in[309]
    DIRECTION INPUT ;
    USE SIGNAL ;
    SHAPE ABUTMENT ;
    PORT
      LAYER metal3 ;
      RECT 0.000 447.965 0.070 448.035 ;
    END
  END wd_in[309]
  PIN wd_in[310]
    DIRECTION INPUT ;
    USE SIGNAL ;
    SHAPE ABUTMENT ;
    PORT
      LAYER metal3 ;
      RECT 0.000 448.245 0.070 448.315 ;
    END
  END wd_in[310]
  PIN wd_in[311]
    DIRECTION INPUT ;
    USE SIGNAL ;
    SHAPE ABUTMENT ;
    PORT
      LAYER metal3 ;
      RECT 0.000 448.525 0.070 448.595 ;
    END
  END wd_in[311]
  PIN wd_in[312]
    DIRECTION INPUT ;
    USE SIGNAL ;
    SHAPE ABUTMENT ;
    PORT
      LAYER metal3 ;
      RECT 0.000 448.805 0.070 448.875 ;
    END
  END wd_in[312]
  PIN wd_in[313]
    DIRECTION INPUT ;
    USE SIGNAL ;
    SHAPE ABUTMENT ;
    PORT
      LAYER metal3 ;
      RECT 0.000 449.085 0.070 449.155 ;
    END
  END wd_in[313]
  PIN wd_in[314]
    DIRECTION INPUT ;
    USE SIGNAL ;
    SHAPE ABUTMENT ;
    PORT
      LAYER metal3 ;
      RECT 0.000 449.365 0.070 449.435 ;
    END
  END wd_in[314]
  PIN wd_in[315]
    DIRECTION INPUT ;
    USE SIGNAL ;
    SHAPE ABUTMENT ;
    PORT
      LAYER metal3 ;
      RECT 0.000 449.645 0.070 449.715 ;
    END
  END wd_in[315]
  PIN wd_in[316]
    DIRECTION INPUT ;
    USE SIGNAL ;
    SHAPE ABUTMENT ;
    PORT
      LAYER metal3 ;
      RECT 0.000 449.925 0.070 449.995 ;
    END
  END wd_in[316]
  PIN wd_in[317]
    DIRECTION INPUT ;
    USE SIGNAL ;
    SHAPE ABUTMENT ;
    PORT
      LAYER metal3 ;
      RECT 0.000 450.205 0.070 450.275 ;
    END
  END wd_in[317]
  PIN wd_in[318]
    DIRECTION INPUT ;
    USE SIGNAL ;
    SHAPE ABUTMENT ;
    PORT
      LAYER metal3 ;
      RECT 0.000 450.485 0.070 450.555 ;
    END
  END wd_in[318]
  PIN wd_in[319]
    DIRECTION INPUT ;
    USE SIGNAL ;
    SHAPE ABUTMENT ;
    PORT
      LAYER metal3 ;
      RECT 0.000 450.765 0.070 450.835 ;
    END
  END wd_in[319]
  PIN wd_in[320]
    DIRECTION INPUT ;
    USE SIGNAL ;
    SHAPE ABUTMENT ;
    PORT
      LAYER metal3 ;
      RECT 0.000 451.045 0.070 451.115 ;
    END
  END wd_in[320]
  PIN wd_in[321]
    DIRECTION INPUT ;
    USE SIGNAL ;
    SHAPE ABUTMENT ;
    PORT
      LAYER metal3 ;
      RECT 0.000 451.325 0.070 451.395 ;
    END
  END wd_in[321]
  PIN wd_in[322]
    DIRECTION INPUT ;
    USE SIGNAL ;
    SHAPE ABUTMENT ;
    PORT
      LAYER metal3 ;
      RECT 0.000 451.605 0.070 451.675 ;
    END
  END wd_in[322]
  PIN wd_in[323]
    DIRECTION INPUT ;
    USE SIGNAL ;
    SHAPE ABUTMENT ;
    PORT
      LAYER metal3 ;
      RECT 0.000 451.885 0.070 451.955 ;
    END
  END wd_in[323]
  PIN wd_in[324]
    DIRECTION INPUT ;
    USE SIGNAL ;
    SHAPE ABUTMENT ;
    PORT
      LAYER metal3 ;
      RECT 0.000 452.165 0.070 452.235 ;
    END
  END wd_in[324]
  PIN wd_in[325]
    DIRECTION INPUT ;
    USE SIGNAL ;
    SHAPE ABUTMENT ;
    PORT
      LAYER metal3 ;
      RECT 0.000 452.445 0.070 452.515 ;
    END
  END wd_in[325]
  PIN wd_in[326]
    DIRECTION INPUT ;
    USE SIGNAL ;
    SHAPE ABUTMENT ;
    PORT
      LAYER metal3 ;
      RECT 0.000 452.725 0.070 452.795 ;
    END
  END wd_in[326]
  PIN wd_in[327]
    DIRECTION INPUT ;
    USE SIGNAL ;
    SHAPE ABUTMENT ;
    PORT
      LAYER metal3 ;
      RECT 0.000 453.005 0.070 453.075 ;
    END
  END wd_in[327]
  PIN wd_in[328]
    DIRECTION INPUT ;
    USE SIGNAL ;
    SHAPE ABUTMENT ;
    PORT
      LAYER metal3 ;
      RECT 0.000 453.285 0.070 453.355 ;
    END
  END wd_in[328]
  PIN wd_in[329]
    DIRECTION INPUT ;
    USE SIGNAL ;
    SHAPE ABUTMENT ;
    PORT
      LAYER metal3 ;
      RECT 0.000 453.565 0.070 453.635 ;
    END
  END wd_in[329]
  PIN wd_in[330]
    DIRECTION INPUT ;
    USE SIGNAL ;
    SHAPE ABUTMENT ;
    PORT
      LAYER metal3 ;
      RECT 0.000 453.845 0.070 453.915 ;
    END
  END wd_in[330]
  PIN wd_in[331]
    DIRECTION INPUT ;
    USE SIGNAL ;
    SHAPE ABUTMENT ;
    PORT
      LAYER metal3 ;
      RECT 0.000 454.125 0.070 454.195 ;
    END
  END wd_in[331]
  PIN wd_in[332]
    DIRECTION INPUT ;
    USE SIGNAL ;
    SHAPE ABUTMENT ;
    PORT
      LAYER metal3 ;
      RECT 0.000 454.405 0.070 454.475 ;
    END
  END wd_in[332]
  PIN wd_in[333]
    DIRECTION INPUT ;
    USE SIGNAL ;
    SHAPE ABUTMENT ;
    PORT
      LAYER metal3 ;
      RECT 0.000 454.685 0.070 454.755 ;
    END
  END wd_in[333]
  PIN wd_in[334]
    DIRECTION INPUT ;
    USE SIGNAL ;
    SHAPE ABUTMENT ;
    PORT
      LAYER metal3 ;
      RECT 0.000 454.965 0.070 455.035 ;
    END
  END wd_in[334]
  PIN wd_in[335]
    DIRECTION INPUT ;
    USE SIGNAL ;
    SHAPE ABUTMENT ;
    PORT
      LAYER metal3 ;
      RECT 0.000 455.245 0.070 455.315 ;
    END
  END wd_in[335]
  PIN wd_in[336]
    DIRECTION INPUT ;
    USE SIGNAL ;
    SHAPE ABUTMENT ;
    PORT
      LAYER metal3 ;
      RECT 0.000 455.525 0.070 455.595 ;
    END
  END wd_in[336]
  PIN wd_in[337]
    DIRECTION INPUT ;
    USE SIGNAL ;
    SHAPE ABUTMENT ;
    PORT
      LAYER metal3 ;
      RECT 0.000 455.805 0.070 455.875 ;
    END
  END wd_in[337]
  PIN wd_in[338]
    DIRECTION INPUT ;
    USE SIGNAL ;
    SHAPE ABUTMENT ;
    PORT
      LAYER metal3 ;
      RECT 0.000 456.085 0.070 456.155 ;
    END
  END wd_in[338]
  PIN wd_in[339]
    DIRECTION INPUT ;
    USE SIGNAL ;
    SHAPE ABUTMENT ;
    PORT
      LAYER metal3 ;
      RECT 0.000 456.365 0.070 456.435 ;
    END
  END wd_in[339]
  PIN wd_in[340]
    DIRECTION INPUT ;
    USE SIGNAL ;
    SHAPE ABUTMENT ;
    PORT
      LAYER metal3 ;
      RECT 0.000 456.645 0.070 456.715 ;
    END
  END wd_in[340]
  PIN wd_in[341]
    DIRECTION INPUT ;
    USE SIGNAL ;
    SHAPE ABUTMENT ;
    PORT
      LAYER metal3 ;
      RECT 0.000 456.925 0.070 456.995 ;
    END
  END wd_in[341]
  PIN wd_in[342]
    DIRECTION INPUT ;
    USE SIGNAL ;
    SHAPE ABUTMENT ;
    PORT
      LAYER metal3 ;
      RECT 0.000 457.205 0.070 457.275 ;
    END
  END wd_in[342]
  PIN wd_in[343]
    DIRECTION INPUT ;
    USE SIGNAL ;
    SHAPE ABUTMENT ;
    PORT
      LAYER metal3 ;
      RECT 0.000 457.485 0.070 457.555 ;
    END
  END wd_in[343]
  PIN wd_in[344]
    DIRECTION INPUT ;
    USE SIGNAL ;
    SHAPE ABUTMENT ;
    PORT
      LAYER metal3 ;
      RECT 0.000 457.765 0.070 457.835 ;
    END
  END wd_in[344]
  PIN wd_in[345]
    DIRECTION INPUT ;
    USE SIGNAL ;
    SHAPE ABUTMENT ;
    PORT
      LAYER metal3 ;
      RECT 0.000 458.045 0.070 458.115 ;
    END
  END wd_in[345]
  PIN wd_in[346]
    DIRECTION INPUT ;
    USE SIGNAL ;
    SHAPE ABUTMENT ;
    PORT
      LAYER metal3 ;
      RECT 0.000 458.325 0.070 458.395 ;
    END
  END wd_in[346]
  PIN wd_in[347]
    DIRECTION INPUT ;
    USE SIGNAL ;
    SHAPE ABUTMENT ;
    PORT
      LAYER metal3 ;
      RECT 0.000 458.605 0.070 458.675 ;
    END
  END wd_in[347]
  PIN wd_in[348]
    DIRECTION INPUT ;
    USE SIGNAL ;
    SHAPE ABUTMENT ;
    PORT
      LAYER metal3 ;
      RECT 0.000 458.885 0.070 458.955 ;
    END
  END wd_in[348]
  PIN wd_in[349]
    DIRECTION INPUT ;
    USE SIGNAL ;
    SHAPE ABUTMENT ;
    PORT
      LAYER metal3 ;
      RECT 0.000 459.165 0.070 459.235 ;
    END
  END wd_in[349]
  PIN wd_in[350]
    DIRECTION INPUT ;
    USE SIGNAL ;
    SHAPE ABUTMENT ;
    PORT
      LAYER metal3 ;
      RECT 0.000 459.445 0.070 459.515 ;
    END
  END wd_in[350]
  PIN wd_in[351]
    DIRECTION INPUT ;
    USE SIGNAL ;
    SHAPE ABUTMENT ;
    PORT
      LAYER metal3 ;
      RECT 0.000 459.725 0.070 459.795 ;
    END
  END wd_in[351]
  PIN wd_in[352]
    DIRECTION INPUT ;
    USE SIGNAL ;
    SHAPE ABUTMENT ;
    PORT
      LAYER metal3 ;
      RECT 0.000 460.005 0.070 460.075 ;
    END
  END wd_in[352]
  PIN wd_in[353]
    DIRECTION INPUT ;
    USE SIGNAL ;
    SHAPE ABUTMENT ;
    PORT
      LAYER metal3 ;
      RECT 0.000 460.285 0.070 460.355 ;
    END
  END wd_in[353]
  PIN wd_in[354]
    DIRECTION INPUT ;
    USE SIGNAL ;
    SHAPE ABUTMENT ;
    PORT
      LAYER metal3 ;
      RECT 0.000 460.565 0.070 460.635 ;
    END
  END wd_in[354]
  PIN wd_in[355]
    DIRECTION INPUT ;
    USE SIGNAL ;
    SHAPE ABUTMENT ;
    PORT
      LAYER metal3 ;
      RECT 0.000 460.845 0.070 460.915 ;
    END
  END wd_in[355]
  PIN wd_in[356]
    DIRECTION INPUT ;
    USE SIGNAL ;
    SHAPE ABUTMENT ;
    PORT
      LAYER metal3 ;
      RECT 0.000 461.125 0.070 461.195 ;
    END
  END wd_in[356]
  PIN wd_in[357]
    DIRECTION INPUT ;
    USE SIGNAL ;
    SHAPE ABUTMENT ;
    PORT
      LAYER metal3 ;
      RECT 0.000 461.405 0.070 461.475 ;
    END
  END wd_in[357]
  PIN wd_in[358]
    DIRECTION INPUT ;
    USE SIGNAL ;
    SHAPE ABUTMENT ;
    PORT
      LAYER metal3 ;
      RECT 0.000 461.685 0.070 461.755 ;
    END
  END wd_in[358]
  PIN wd_in[359]
    DIRECTION INPUT ;
    USE SIGNAL ;
    SHAPE ABUTMENT ;
    PORT
      LAYER metal3 ;
      RECT 0.000 461.965 0.070 462.035 ;
    END
  END wd_in[359]
  PIN wd_in[360]
    DIRECTION INPUT ;
    USE SIGNAL ;
    SHAPE ABUTMENT ;
    PORT
      LAYER metal3 ;
      RECT 0.000 462.245 0.070 462.315 ;
    END
  END wd_in[360]
  PIN wd_in[361]
    DIRECTION INPUT ;
    USE SIGNAL ;
    SHAPE ABUTMENT ;
    PORT
      LAYER metal3 ;
      RECT 0.000 462.525 0.070 462.595 ;
    END
  END wd_in[361]
  PIN wd_in[362]
    DIRECTION INPUT ;
    USE SIGNAL ;
    SHAPE ABUTMENT ;
    PORT
      LAYER metal3 ;
      RECT 0.000 462.805 0.070 462.875 ;
    END
  END wd_in[362]
  PIN wd_in[363]
    DIRECTION INPUT ;
    USE SIGNAL ;
    SHAPE ABUTMENT ;
    PORT
      LAYER metal3 ;
      RECT 0.000 463.085 0.070 463.155 ;
    END
  END wd_in[363]
  PIN wd_in[364]
    DIRECTION INPUT ;
    USE SIGNAL ;
    SHAPE ABUTMENT ;
    PORT
      LAYER metal3 ;
      RECT 0.000 463.365 0.070 463.435 ;
    END
  END wd_in[364]
  PIN wd_in[365]
    DIRECTION INPUT ;
    USE SIGNAL ;
    SHAPE ABUTMENT ;
    PORT
      LAYER metal3 ;
      RECT 0.000 463.645 0.070 463.715 ;
    END
  END wd_in[365]
  PIN wd_in[366]
    DIRECTION INPUT ;
    USE SIGNAL ;
    SHAPE ABUTMENT ;
    PORT
      LAYER metal3 ;
      RECT 0.000 463.925 0.070 463.995 ;
    END
  END wd_in[366]
  PIN wd_in[367]
    DIRECTION INPUT ;
    USE SIGNAL ;
    SHAPE ABUTMENT ;
    PORT
      LAYER metal3 ;
      RECT 0.000 464.205 0.070 464.275 ;
    END
  END wd_in[367]
  PIN wd_in[368]
    DIRECTION INPUT ;
    USE SIGNAL ;
    SHAPE ABUTMENT ;
    PORT
      LAYER metal3 ;
      RECT 0.000 464.485 0.070 464.555 ;
    END
  END wd_in[368]
  PIN wd_in[369]
    DIRECTION INPUT ;
    USE SIGNAL ;
    SHAPE ABUTMENT ;
    PORT
      LAYER metal3 ;
      RECT 0.000 464.765 0.070 464.835 ;
    END
  END wd_in[369]
  PIN wd_in[370]
    DIRECTION INPUT ;
    USE SIGNAL ;
    SHAPE ABUTMENT ;
    PORT
      LAYER metal3 ;
      RECT 0.000 465.045 0.070 465.115 ;
    END
  END wd_in[370]
  PIN wd_in[371]
    DIRECTION INPUT ;
    USE SIGNAL ;
    SHAPE ABUTMENT ;
    PORT
      LAYER metal3 ;
      RECT 0.000 465.325 0.070 465.395 ;
    END
  END wd_in[371]
  PIN wd_in[372]
    DIRECTION INPUT ;
    USE SIGNAL ;
    SHAPE ABUTMENT ;
    PORT
      LAYER metal3 ;
      RECT 0.000 465.605 0.070 465.675 ;
    END
  END wd_in[372]
  PIN wd_in[373]
    DIRECTION INPUT ;
    USE SIGNAL ;
    SHAPE ABUTMENT ;
    PORT
      LAYER metal3 ;
      RECT 0.000 465.885 0.070 465.955 ;
    END
  END wd_in[373]
  PIN wd_in[374]
    DIRECTION INPUT ;
    USE SIGNAL ;
    SHAPE ABUTMENT ;
    PORT
      LAYER metal3 ;
      RECT 0.000 466.165 0.070 466.235 ;
    END
  END wd_in[374]
  PIN wd_in[375]
    DIRECTION INPUT ;
    USE SIGNAL ;
    SHAPE ABUTMENT ;
    PORT
      LAYER metal3 ;
      RECT 0.000 466.445 0.070 466.515 ;
    END
  END wd_in[375]
  PIN wd_in[376]
    DIRECTION INPUT ;
    USE SIGNAL ;
    SHAPE ABUTMENT ;
    PORT
      LAYER metal3 ;
      RECT 0.000 466.725 0.070 466.795 ;
    END
  END wd_in[376]
  PIN wd_in[377]
    DIRECTION INPUT ;
    USE SIGNAL ;
    SHAPE ABUTMENT ;
    PORT
      LAYER metal3 ;
      RECT 0.000 467.005 0.070 467.075 ;
    END
  END wd_in[377]
  PIN wd_in[378]
    DIRECTION INPUT ;
    USE SIGNAL ;
    SHAPE ABUTMENT ;
    PORT
      LAYER metal3 ;
      RECT 0.000 467.285 0.070 467.355 ;
    END
  END wd_in[378]
  PIN wd_in[379]
    DIRECTION INPUT ;
    USE SIGNAL ;
    SHAPE ABUTMENT ;
    PORT
      LAYER metal3 ;
      RECT 0.000 467.565 0.070 467.635 ;
    END
  END wd_in[379]
  PIN wd_in[380]
    DIRECTION INPUT ;
    USE SIGNAL ;
    SHAPE ABUTMENT ;
    PORT
      LAYER metal3 ;
      RECT 0.000 467.845 0.070 467.915 ;
    END
  END wd_in[380]
  PIN wd_in[381]
    DIRECTION INPUT ;
    USE SIGNAL ;
    SHAPE ABUTMENT ;
    PORT
      LAYER metal3 ;
      RECT 0.000 468.125 0.070 468.195 ;
    END
  END wd_in[381]
  PIN wd_in[382]
    DIRECTION INPUT ;
    USE SIGNAL ;
    SHAPE ABUTMENT ;
    PORT
      LAYER metal3 ;
      RECT 0.000 468.405 0.070 468.475 ;
    END
  END wd_in[382]
  PIN wd_in[383]
    DIRECTION INPUT ;
    USE SIGNAL ;
    SHAPE ABUTMENT ;
    PORT
      LAYER metal3 ;
      RECT 0.000 468.685 0.070 468.755 ;
    END
  END wd_in[383]
  PIN wd_in[384]
    DIRECTION INPUT ;
    USE SIGNAL ;
    SHAPE ABUTMENT ;
    PORT
      LAYER metal3 ;
      RECT 0.000 468.965 0.070 469.035 ;
    END
  END wd_in[384]
  PIN wd_in[385]
    DIRECTION INPUT ;
    USE SIGNAL ;
    SHAPE ABUTMENT ;
    PORT
      LAYER metal3 ;
      RECT 0.000 469.245 0.070 469.315 ;
    END
  END wd_in[385]
  PIN wd_in[386]
    DIRECTION INPUT ;
    USE SIGNAL ;
    SHAPE ABUTMENT ;
    PORT
      LAYER metal3 ;
      RECT 0.000 469.525 0.070 469.595 ;
    END
  END wd_in[386]
  PIN wd_in[387]
    DIRECTION INPUT ;
    USE SIGNAL ;
    SHAPE ABUTMENT ;
    PORT
      LAYER metal3 ;
      RECT 0.000 469.805 0.070 469.875 ;
    END
  END wd_in[387]
  PIN wd_in[388]
    DIRECTION INPUT ;
    USE SIGNAL ;
    SHAPE ABUTMENT ;
    PORT
      LAYER metal3 ;
      RECT 0.000 470.085 0.070 470.155 ;
    END
  END wd_in[388]
  PIN wd_in[389]
    DIRECTION INPUT ;
    USE SIGNAL ;
    SHAPE ABUTMENT ;
    PORT
      LAYER metal3 ;
      RECT 0.000 470.365 0.070 470.435 ;
    END
  END wd_in[389]
  PIN wd_in[390]
    DIRECTION INPUT ;
    USE SIGNAL ;
    SHAPE ABUTMENT ;
    PORT
      LAYER metal3 ;
      RECT 0.000 470.645 0.070 470.715 ;
    END
  END wd_in[390]
  PIN wd_in[391]
    DIRECTION INPUT ;
    USE SIGNAL ;
    SHAPE ABUTMENT ;
    PORT
      LAYER metal3 ;
      RECT 0.000 470.925 0.070 470.995 ;
    END
  END wd_in[391]
  PIN wd_in[392]
    DIRECTION INPUT ;
    USE SIGNAL ;
    SHAPE ABUTMENT ;
    PORT
      LAYER metal3 ;
      RECT 0.000 471.205 0.070 471.275 ;
    END
  END wd_in[392]
  PIN wd_in[393]
    DIRECTION INPUT ;
    USE SIGNAL ;
    SHAPE ABUTMENT ;
    PORT
      LAYER metal3 ;
      RECT 0.000 471.485 0.070 471.555 ;
    END
  END wd_in[393]
  PIN wd_in[394]
    DIRECTION INPUT ;
    USE SIGNAL ;
    SHAPE ABUTMENT ;
    PORT
      LAYER metal3 ;
      RECT 0.000 471.765 0.070 471.835 ;
    END
  END wd_in[394]
  PIN wd_in[395]
    DIRECTION INPUT ;
    USE SIGNAL ;
    SHAPE ABUTMENT ;
    PORT
      LAYER metal3 ;
      RECT 0.000 472.045 0.070 472.115 ;
    END
  END wd_in[395]
  PIN wd_in[396]
    DIRECTION INPUT ;
    USE SIGNAL ;
    SHAPE ABUTMENT ;
    PORT
      LAYER metal3 ;
      RECT 0.000 472.325 0.070 472.395 ;
    END
  END wd_in[396]
  PIN wd_in[397]
    DIRECTION INPUT ;
    USE SIGNAL ;
    SHAPE ABUTMENT ;
    PORT
      LAYER metal3 ;
      RECT 0.000 472.605 0.070 472.675 ;
    END
  END wd_in[397]
  PIN wd_in[398]
    DIRECTION INPUT ;
    USE SIGNAL ;
    SHAPE ABUTMENT ;
    PORT
      LAYER metal3 ;
      RECT 0.000 472.885 0.070 472.955 ;
    END
  END wd_in[398]
  PIN wd_in[399]
    DIRECTION INPUT ;
    USE SIGNAL ;
    SHAPE ABUTMENT ;
    PORT
      LAYER metal3 ;
      RECT 0.000 473.165 0.070 473.235 ;
    END
  END wd_in[399]
  PIN wd_in[400]
    DIRECTION INPUT ;
    USE SIGNAL ;
    SHAPE ABUTMENT ;
    PORT
      LAYER metal3 ;
      RECT 0.000 473.445 0.070 473.515 ;
    END
  END wd_in[400]
  PIN wd_in[401]
    DIRECTION INPUT ;
    USE SIGNAL ;
    SHAPE ABUTMENT ;
    PORT
      LAYER metal3 ;
      RECT 0.000 473.725 0.070 473.795 ;
    END
  END wd_in[401]
  PIN wd_in[402]
    DIRECTION INPUT ;
    USE SIGNAL ;
    SHAPE ABUTMENT ;
    PORT
      LAYER metal3 ;
      RECT 0.000 474.005 0.070 474.075 ;
    END
  END wd_in[402]
  PIN wd_in[403]
    DIRECTION INPUT ;
    USE SIGNAL ;
    SHAPE ABUTMENT ;
    PORT
      LAYER metal3 ;
      RECT 0.000 474.285 0.070 474.355 ;
    END
  END wd_in[403]
  PIN wd_in[404]
    DIRECTION INPUT ;
    USE SIGNAL ;
    SHAPE ABUTMENT ;
    PORT
      LAYER metal3 ;
      RECT 0.000 474.565 0.070 474.635 ;
    END
  END wd_in[404]
  PIN wd_in[405]
    DIRECTION INPUT ;
    USE SIGNAL ;
    SHAPE ABUTMENT ;
    PORT
      LAYER metal3 ;
      RECT 0.000 474.845 0.070 474.915 ;
    END
  END wd_in[405]
  PIN wd_in[406]
    DIRECTION INPUT ;
    USE SIGNAL ;
    SHAPE ABUTMENT ;
    PORT
      LAYER metal3 ;
      RECT 0.000 475.125 0.070 475.195 ;
    END
  END wd_in[406]
  PIN wd_in[407]
    DIRECTION INPUT ;
    USE SIGNAL ;
    SHAPE ABUTMENT ;
    PORT
      LAYER metal3 ;
      RECT 0.000 475.405 0.070 475.475 ;
    END
  END wd_in[407]
  PIN wd_in[408]
    DIRECTION INPUT ;
    USE SIGNAL ;
    SHAPE ABUTMENT ;
    PORT
      LAYER metal3 ;
      RECT 0.000 475.685 0.070 475.755 ;
    END
  END wd_in[408]
  PIN wd_in[409]
    DIRECTION INPUT ;
    USE SIGNAL ;
    SHAPE ABUTMENT ;
    PORT
      LAYER metal3 ;
      RECT 0.000 475.965 0.070 476.035 ;
    END
  END wd_in[409]
  PIN wd_in[410]
    DIRECTION INPUT ;
    USE SIGNAL ;
    SHAPE ABUTMENT ;
    PORT
      LAYER metal3 ;
      RECT 0.000 476.245 0.070 476.315 ;
    END
  END wd_in[410]
  PIN wd_in[411]
    DIRECTION INPUT ;
    USE SIGNAL ;
    SHAPE ABUTMENT ;
    PORT
      LAYER metal3 ;
      RECT 0.000 476.525 0.070 476.595 ;
    END
  END wd_in[411]
  PIN wd_in[412]
    DIRECTION INPUT ;
    USE SIGNAL ;
    SHAPE ABUTMENT ;
    PORT
      LAYER metal3 ;
      RECT 0.000 476.805 0.070 476.875 ;
    END
  END wd_in[412]
  PIN wd_in[413]
    DIRECTION INPUT ;
    USE SIGNAL ;
    SHAPE ABUTMENT ;
    PORT
      LAYER metal3 ;
      RECT 0.000 477.085 0.070 477.155 ;
    END
  END wd_in[413]
  PIN wd_in[414]
    DIRECTION INPUT ;
    USE SIGNAL ;
    SHAPE ABUTMENT ;
    PORT
      LAYER metal3 ;
      RECT 0.000 477.365 0.070 477.435 ;
    END
  END wd_in[414]
  PIN wd_in[415]
    DIRECTION INPUT ;
    USE SIGNAL ;
    SHAPE ABUTMENT ;
    PORT
      LAYER metal3 ;
      RECT 0.000 477.645 0.070 477.715 ;
    END
  END wd_in[415]
  PIN wd_in[416]
    DIRECTION INPUT ;
    USE SIGNAL ;
    SHAPE ABUTMENT ;
    PORT
      LAYER metal3 ;
      RECT 0.000 477.925 0.070 477.995 ;
    END
  END wd_in[416]
  PIN wd_in[417]
    DIRECTION INPUT ;
    USE SIGNAL ;
    SHAPE ABUTMENT ;
    PORT
      LAYER metal3 ;
      RECT 0.000 478.205 0.070 478.275 ;
    END
  END wd_in[417]
  PIN wd_in[418]
    DIRECTION INPUT ;
    USE SIGNAL ;
    SHAPE ABUTMENT ;
    PORT
      LAYER metal3 ;
      RECT 0.000 478.485 0.070 478.555 ;
    END
  END wd_in[418]
  PIN wd_in[419]
    DIRECTION INPUT ;
    USE SIGNAL ;
    SHAPE ABUTMENT ;
    PORT
      LAYER metal3 ;
      RECT 0.000 478.765 0.070 478.835 ;
    END
  END wd_in[419]
  PIN wd_in[420]
    DIRECTION INPUT ;
    USE SIGNAL ;
    SHAPE ABUTMENT ;
    PORT
      LAYER metal3 ;
      RECT 0.000 479.045 0.070 479.115 ;
    END
  END wd_in[420]
  PIN wd_in[421]
    DIRECTION INPUT ;
    USE SIGNAL ;
    SHAPE ABUTMENT ;
    PORT
      LAYER metal3 ;
      RECT 0.000 479.325 0.070 479.395 ;
    END
  END wd_in[421]
  PIN wd_in[422]
    DIRECTION INPUT ;
    USE SIGNAL ;
    SHAPE ABUTMENT ;
    PORT
      LAYER metal3 ;
      RECT 0.000 479.605 0.070 479.675 ;
    END
  END wd_in[422]
  PIN wd_in[423]
    DIRECTION INPUT ;
    USE SIGNAL ;
    SHAPE ABUTMENT ;
    PORT
      LAYER metal3 ;
      RECT 0.000 479.885 0.070 479.955 ;
    END
  END wd_in[423]
  PIN wd_in[424]
    DIRECTION INPUT ;
    USE SIGNAL ;
    SHAPE ABUTMENT ;
    PORT
      LAYER metal3 ;
      RECT 0.000 480.165 0.070 480.235 ;
    END
  END wd_in[424]
  PIN wd_in[425]
    DIRECTION INPUT ;
    USE SIGNAL ;
    SHAPE ABUTMENT ;
    PORT
      LAYER metal3 ;
      RECT 0.000 480.445 0.070 480.515 ;
    END
  END wd_in[425]
  PIN wd_in[426]
    DIRECTION INPUT ;
    USE SIGNAL ;
    SHAPE ABUTMENT ;
    PORT
      LAYER metal3 ;
      RECT 0.000 480.725 0.070 480.795 ;
    END
  END wd_in[426]
  PIN wd_in[427]
    DIRECTION INPUT ;
    USE SIGNAL ;
    SHAPE ABUTMENT ;
    PORT
      LAYER metal3 ;
      RECT 0.000 481.005 0.070 481.075 ;
    END
  END wd_in[427]
  PIN wd_in[428]
    DIRECTION INPUT ;
    USE SIGNAL ;
    SHAPE ABUTMENT ;
    PORT
      LAYER metal3 ;
      RECT 0.000 481.285 0.070 481.355 ;
    END
  END wd_in[428]
  PIN wd_in[429]
    DIRECTION INPUT ;
    USE SIGNAL ;
    SHAPE ABUTMENT ;
    PORT
      LAYER metal3 ;
      RECT 0.000 481.565 0.070 481.635 ;
    END
  END wd_in[429]
  PIN wd_in[430]
    DIRECTION INPUT ;
    USE SIGNAL ;
    SHAPE ABUTMENT ;
    PORT
      LAYER metal3 ;
      RECT 0.000 481.845 0.070 481.915 ;
    END
  END wd_in[430]
  PIN wd_in[431]
    DIRECTION INPUT ;
    USE SIGNAL ;
    SHAPE ABUTMENT ;
    PORT
      LAYER metal3 ;
      RECT 0.000 482.125 0.070 482.195 ;
    END
  END wd_in[431]
  PIN wd_in[432]
    DIRECTION INPUT ;
    USE SIGNAL ;
    SHAPE ABUTMENT ;
    PORT
      LAYER metal3 ;
      RECT 0.000 482.405 0.070 482.475 ;
    END
  END wd_in[432]
  PIN wd_in[433]
    DIRECTION INPUT ;
    USE SIGNAL ;
    SHAPE ABUTMENT ;
    PORT
      LAYER metal3 ;
      RECT 0.000 482.685 0.070 482.755 ;
    END
  END wd_in[433]
  PIN wd_in[434]
    DIRECTION INPUT ;
    USE SIGNAL ;
    SHAPE ABUTMENT ;
    PORT
      LAYER metal3 ;
      RECT 0.000 482.965 0.070 483.035 ;
    END
  END wd_in[434]
  PIN wd_in[435]
    DIRECTION INPUT ;
    USE SIGNAL ;
    SHAPE ABUTMENT ;
    PORT
      LAYER metal3 ;
      RECT 0.000 483.245 0.070 483.315 ;
    END
  END wd_in[435]
  PIN wd_in[436]
    DIRECTION INPUT ;
    USE SIGNAL ;
    SHAPE ABUTMENT ;
    PORT
      LAYER metal3 ;
      RECT 0.000 483.525 0.070 483.595 ;
    END
  END wd_in[436]
  PIN wd_in[437]
    DIRECTION INPUT ;
    USE SIGNAL ;
    SHAPE ABUTMENT ;
    PORT
      LAYER metal3 ;
      RECT 0.000 483.805 0.070 483.875 ;
    END
  END wd_in[437]
  PIN wd_in[438]
    DIRECTION INPUT ;
    USE SIGNAL ;
    SHAPE ABUTMENT ;
    PORT
      LAYER metal3 ;
      RECT 0.000 484.085 0.070 484.155 ;
    END
  END wd_in[438]
  PIN wd_in[439]
    DIRECTION INPUT ;
    USE SIGNAL ;
    SHAPE ABUTMENT ;
    PORT
      LAYER metal3 ;
      RECT 0.000 484.365 0.070 484.435 ;
    END
  END wd_in[439]
  PIN wd_in[440]
    DIRECTION INPUT ;
    USE SIGNAL ;
    SHAPE ABUTMENT ;
    PORT
      LAYER metal3 ;
      RECT 0.000 484.645 0.070 484.715 ;
    END
  END wd_in[440]
  PIN wd_in[441]
    DIRECTION INPUT ;
    USE SIGNAL ;
    SHAPE ABUTMENT ;
    PORT
      LAYER metal3 ;
      RECT 0.000 484.925 0.070 484.995 ;
    END
  END wd_in[441]
  PIN wd_in[442]
    DIRECTION INPUT ;
    USE SIGNAL ;
    SHAPE ABUTMENT ;
    PORT
      LAYER metal3 ;
      RECT 0.000 485.205 0.070 485.275 ;
    END
  END wd_in[442]
  PIN wd_in[443]
    DIRECTION INPUT ;
    USE SIGNAL ;
    SHAPE ABUTMENT ;
    PORT
      LAYER metal3 ;
      RECT 0.000 485.485 0.070 485.555 ;
    END
  END wd_in[443]
  PIN wd_in[444]
    DIRECTION INPUT ;
    USE SIGNAL ;
    SHAPE ABUTMENT ;
    PORT
      LAYER metal3 ;
      RECT 0.000 485.765 0.070 485.835 ;
    END
  END wd_in[444]
  PIN wd_in[445]
    DIRECTION INPUT ;
    USE SIGNAL ;
    SHAPE ABUTMENT ;
    PORT
      LAYER metal3 ;
      RECT 0.000 486.045 0.070 486.115 ;
    END
  END wd_in[445]
  PIN wd_in[446]
    DIRECTION INPUT ;
    USE SIGNAL ;
    SHAPE ABUTMENT ;
    PORT
      LAYER metal3 ;
      RECT 0.000 486.325 0.070 486.395 ;
    END
  END wd_in[446]
  PIN wd_in[447]
    DIRECTION INPUT ;
    USE SIGNAL ;
    SHAPE ABUTMENT ;
    PORT
      LAYER metal3 ;
      RECT 0.000 486.605 0.070 486.675 ;
    END
  END wd_in[447]
  PIN wd_in[448]
    DIRECTION INPUT ;
    USE SIGNAL ;
    SHAPE ABUTMENT ;
    PORT
      LAYER metal3 ;
      RECT 0.000 486.885 0.070 486.955 ;
    END
  END wd_in[448]
  PIN wd_in[449]
    DIRECTION INPUT ;
    USE SIGNAL ;
    SHAPE ABUTMENT ;
    PORT
      LAYER metal3 ;
      RECT 0.000 487.165 0.070 487.235 ;
    END
  END wd_in[449]
  PIN wd_in[450]
    DIRECTION INPUT ;
    USE SIGNAL ;
    SHAPE ABUTMENT ;
    PORT
      LAYER metal3 ;
      RECT 0.000 487.445 0.070 487.515 ;
    END
  END wd_in[450]
  PIN wd_in[451]
    DIRECTION INPUT ;
    USE SIGNAL ;
    SHAPE ABUTMENT ;
    PORT
      LAYER metal3 ;
      RECT 0.000 487.725 0.070 487.795 ;
    END
  END wd_in[451]
  PIN wd_in[452]
    DIRECTION INPUT ;
    USE SIGNAL ;
    SHAPE ABUTMENT ;
    PORT
      LAYER metal3 ;
      RECT 0.000 488.005 0.070 488.075 ;
    END
  END wd_in[452]
  PIN wd_in[453]
    DIRECTION INPUT ;
    USE SIGNAL ;
    SHAPE ABUTMENT ;
    PORT
      LAYER metal3 ;
      RECT 0.000 488.285 0.070 488.355 ;
    END
  END wd_in[453]
  PIN wd_in[454]
    DIRECTION INPUT ;
    USE SIGNAL ;
    SHAPE ABUTMENT ;
    PORT
      LAYER metal3 ;
      RECT 0.000 488.565 0.070 488.635 ;
    END
  END wd_in[454]
  PIN wd_in[455]
    DIRECTION INPUT ;
    USE SIGNAL ;
    SHAPE ABUTMENT ;
    PORT
      LAYER metal3 ;
      RECT 0.000 488.845 0.070 488.915 ;
    END
  END wd_in[455]
  PIN wd_in[456]
    DIRECTION INPUT ;
    USE SIGNAL ;
    SHAPE ABUTMENT ;
    PORT
      LAYER metal3 ;
      RECT 0.000 489.125 0.070 489.195 ;
    END
  END wd_in[456]
  PIN wd_in[457]
    DIRECTION INPUT ;
    USE SIGNAL ;
    SHAPE ABUTMENT ;
    PORT
      LAYER metal3 ;
      RECT 0.000 489.405 0.070 489.475 ;
    END
  END wd_in[457]
  PIN wd_in[458]
    DIRECTION INPUT ;
    USE SIGNAL ;
    SHAPE ABUTMENT ;
    PORT
      LAYER metal3 ;
      RECT 0.000 489.685 0.070 489.755 ;
    END
  END wd_in[458]
  PIN wd_in[459]
    DIRECTION INPUT ;
    USE SIGNAL ;
    SHAPE ABUTMENT ;
    PORT
      LAYER metal3 ;
      RECT 0.000 489.965 0.070 490.035 ;
    END
  END wd_in[459]
  PIN wd_in[460]
    DIRECTION INPUT ;
    USE SIGNAL ;
    SHAPE ABUTMENT ;
    PORT
      LAYER metal3 ;
      RECT 0.000 490.245 0.070 490.315 ;
    END
  END wd_in[460]
  PIN wd_in[461]
    DIRECTION INPUT ;
    USE SIGNAL ;
    SHAPE ABUTMENT ;
    PORT
      LAYER metal3 ;
      RECT 0.000 490.525 0.070 490.595 ;
    END
  END wd_in[461]
  PIN wd_in[462]
    DIRECTION INPUT ;
    USE SIGNAL ;
    SHAPE ABUTMENT ;
    PORT
      LAYER metal3 ;
      RECT 0.000 490.805 0.070 490.875 ;
    END
  END wd_in[462]
  PIN wd_in[463]
    DIRECTION INPUT ;
    USE SIGNAL ;
    SHAPE ABUTMENT ;
    PORT
      LAYER metal3 ;
      RECT 0.000 491.085 0.070 491.155 ;
    END
  END wd_in[463]
  PIN wd_in[464]
    DIRECTION INPUT ;
    USE SIGNAL ;
    SHAPE ABUTMENT ;
    PORT
      LAYER metal3 ;
      RECT 0.000 491.365 0.070 491.435 ;
    END
  END wd_in[464]
  PIN wd_in[465]
    DIRECTION INPUT ;
    USE SIGNAL ;
    SHAPE ABUTMENT ;
    PORT
      LAYER metal3 ;
      RECT 0.000 491.645 0.070 491.715 ;
    END
  END wd_in[465]
  PIN wd_in[466]
    DIRECTION INPUT ;
    USE SIGNAL ;
    SHAPE ABUTMENT ;
    PORT
      LAYER metal3 ;
      RECT 0.000 491.925 0.070 491.995 ;
    END
  END wd_in[466]
  PIN wd_in[467]
    DIRECTION INPUT ;
    USE SIGNAL ;
    SHAPE ABUTMENT ;
    PORT
      LAYER metal3 ;
      RECT 0.000 492.205 0.070 492.275 ;
    END
  END wd_in[467]
  PIN wd_in[468]
    DIRECTION INPUT ;
    USE SIGNAL ;
    SHAPE ABUTMENT ;
    PORT
      LAYER metal3 ;
      RECT 0.000 492.485 0.070 492.555 ;
    END
  END wd_in[468]
  PIN wd_in[469]
    DIRECTION INPUT ;
    USE SIGNAL ;
    SHAPE ABUTMENT ;
    PORT
      LAYER metal3 ;
      RECT 0.000 492.765 0.070 492.835 ;
    END
  END wd_in[469]
  PIN wd_in[470]
    DIRECTION INPUT ;
    USE SIGNAL ;
    SHAPE ABUTMENT ;
    PORT
      LAYER metal3 ;
      RECT 0.000 493.045 0.070 493.115 ;
    END
  END wd_in[470]
  PIN wd_in[471]
    DIRECTION INPUT ;
    USE SIGNAL ;
    SHAPE ABUTMENT ;
    PORT
      LAYER metal3 ;
      RECT 0.000 493.325 0.070 493.395 ;
    END
  END wd_in[471]
  PIN wd_in[472]
    DIRECTION INPUT ;
    USE SIGNAL ;
    SHAPE ABUTMENT ;
    PORT
      LAYER metal3 ;
      RECT 0.000 493.605 0.070 493.675 ;
    END
  END wd_in[472]
  PIN wd_in[473]
    DIRECTION INPUT ;
    USE SIGNAL ;
    SHAPE ABUTMENT ;
    PORT
      LAYER metal3 ;
      RECT 0.000 493.885 0.070 493.955 ;
    END
  END wd_in[473]
  PIN wd_in[474]
    DIRECTION INPUT ;
    USE SIGNAL ;
    SHAPE ABUTMENT ;
    PORT
      LAYER metal3 ;
      RECT 0.000 494.165 0.070 494.235 ;
    END
  END wd_in[474]
  PIN wd_in[475]
    DIRECTION INPUT ;
    USE SIGNAL ;
    SHAPE ABUTMENT ;
    PORT
      LAYER metal3 ;
      RECT 0.000 494.445 0.070 494.515 ;
    END
  END wd_in[475]
  PIN wd_in[476]
    DIRECTION INPUT ;
    USE SIGNAL ;
    SHAPE ABUTMENT ;
    PORT
      LAYER metal3 ;
      RECT 0.000 494.725 0.070 494.795 ;
    END
  END wd_in[476]
  PIN wd_in[477]
    DIRECTION INPUT ;
    USE SIGNAL ;
    SHAPE ABUTMENT ;
    PORT
      LAYER metal3 ;
      RECT 0.000 495.005 0.070 495.075 ;
    END
  END wd_in[477]
  PIN wd_in[478]
    DIRECTION INPUT ;
    USE SIGNAL ;
    SHAPE ABUTMENT ;
    PORT
      LAYER metal3 ;
      RECT 0.000 495.285 0.070 495.355 ;
    END
  END wd_in[478]
  PIN wd_in[479]
    DIRECTION INPUT ;
    USE SIGNAL ;
    SHAPE ABUTMENT ;
    PORT
      LAYER metal3 ;
      RECT 0.000 495.565 0.070 495.635 ;
    END
  END wd_in[479]
  PIN wd_in[480]
    DIRECTION INPUT ;
    USE SIGNAL ;
    SHAPE ABUTMENT ;
    PORT
      LAYER metal3 ;
      RECT 0.000 495.845 0.070 495.915 ;
    END
  END wd_in[480]
  PIN wd_in[481]
    DIRECTION INPUT ;
    USE SIGNAL ;
    SHAPE ABUTMENT ;
    PORT
      LAYER metal3 ;
      RECT 0.000 496.125 0.070 496.195 ;
    END
  END wd_in[481]
  PIN wd_in[482]
    DIRECTION INPUT ;
    USE SIGNAL ;
    SHAPE ABUTMENT ;
    PORT
      LAYER metal3 ;
      RECT 0.000 496.405 0.070 496.475 ;
    END
  END wd_in[482]
  PIN wd_in[483]
    DIRECTION INPUT ;
    USE SIGNAL ;
    SHAPE ABUTMENT ;
    PORT
      LAYER metal3 ;
      RECT 0.000 496.685 0.070 496.755 ;
    END
  END wd_in[483]
  PIN wd_in[484]
    DIRECTION INPUT ;
    USE SIGNAL ;
    SHAPE ABUTMENT ;
    PORT
      LAYER metal3 ;
      RECT 0.000 496.965 0.070 497.035 ;
    END
  END wd_in[484]
  PIN wd_in[485]
    DIRECTION INPUT ;
    USE SIGNAL ;
    SHAPE ABUTMENT ;
    PORT
      LAYER metal3 ;
      RECT 0.000 497.245 0.070 497.315 ;
    END
  END wd_in[485]
  PIN wd_in[486]
    DIRECTION INPUT ;
    USE SIGNAL ;
    SHAPE ABUTMENT ;
    PORT
      LAYER metal3 ;
      RECT 0.000 497.525 0.070 497.595 ;
    END
  END wd_in[486]
  PIN wd_in[487]
    DIRECTION INPUT ;
    USE SIGNAL ;
    SHAPE ABUTMENT ;
    PORT
      LAYER metal3 ;
      RECT 0.000 497.805 0.070 497.875 ;
    END
  END wd_in[487]
  PIN wd_in[488]
    DIRECTION INPUT ;
    USE SIGNAL ;
    SHAPE ABUTMENT ;
    PORT
      LAYER metal3 ;
      RECT 0.000 498.085 0.070 498.155 ;
    END
  END wd_in[488]
  PIN wd_in[489]
    DIRECTION INPUT ;
    USE SIGNAL ;
    SHAPE ABUTMENT ;
    PORT
      LAYER metal3 ;
      RECT 0.000 498.365 0.070 498.435 ;
    END
  END wd_in[489]
  PIN wd_in[490]
    DIRECTION INPUT ;
    USE SIGNAL ;
    SHAPE ABUTMENT ;
    PORT
      LAYER metal3 ;
      RECT 0.000 498.645 0.070 498.715 ;
    END
  END wd_in[490]
  PIN wd_in[491]
    DIRECTION INPUT ;
    USE SIGNAL ;
    SHAPE ABUTMENT ;
    PORT
      LAYER metal3 ;
      RECT 0.000 498.925 0.070 498.995 ;
    END
  END wd_in[491]
  PIN wd_in[492]
    DIRECTION INPUT ;
    USE SIGNAL ;
    SHAPE ABUTMENT ;
    PORT
      LAYER metal3 ;
      RECT 0.000 499.205 0.070 499.275 ;
    END
  END wd_in[492]
  PIN wd_in[493]
    DIRECTION INPUT ;
    USE SIGNAL ;
    SHAPE ABUTMENT ;
    PORT
      LAYER metal3 ;
      RECT 0.000 499.485 0.070 499.555 ;
    END
  END wd_in[493]
  PIN wd_in[494]
    DIRECTION INPUT ;
    USE SIGNAL ;
    SHAPE ABUTMENT ;
    PORT
      LAYER metal3 ;
      RECT 0.000 499.765 0.070 499.835 ;
    END
  END wd_in[494]
  PIN wd_in[495]
    DIRECTION INPUT ;
    USE SIGNAL ;
    SHAPE ABUTMENT ;
    PORT
      LAYER metal3 ;
      RECT 0.000 500.045 0.070 500.115 ;
    END
  END wd_in[495]
  PIN wd_in[496]
    DIRECTION INPUT ;
    USE SIGNAL ;
    SHAPE ABUTMENT ;
    PORT
      LAYER metal3 ;
      RECT 0.000 500.325 0.070 500.395 ;
    END
  END wd_in[496]
  PIN wd_in[497]
    DIRECTION INPUT ;
    USE SIGNAL ;
    SHAPE ABUTMENT ;
    PORT
      LAYER metal3 ;
      RECT 0.000 500.605 0.070 500.675 ;
    END
  END wd_in[497]
  PIN wd_in[498]
    DIRECTION INPUT ;
    USE SIGNAL ;
    SHAPE ABUTMENT ;
    PORT
      LAYER metal3 ;
      RECT 0.000 500.885 0.070 500.955 ;
    END
  END wd_in[498]
  PIN wd_in[499]
    DIRECTION INPUT ;
    USE SIGNAL ;
    SHAPE ABUTMENT ;
    PORT
      LAYER metal3 ;
      RECT 0.000 501.165 0.070 501.235 ;
    END
  END wd_in[499]
  PIN wd_in[500]
    DIRECTION INPUT ;
    USE SIGNAL ;
    SHAPE ABUTMENT ;
    PORT
      LAYER metal3 ;
      RECT 0.000 501.445 0.070 501.515 ;
    END
  END wd_in[500]
  PIN wd_in[501]
    DIRECTION INPUT ;
    USE SIGNAL ;
    SHAPE ABUTMENT ;
    PORT
      LAYER metal3 ;
      RECT 0.000 501.725 0.070 501.795 ;
    END
  END wd_in[501]
  PIN wd_in[502]
    DIRECTION INPUT ;
    USE SIGNAL ;
    SHAPE ABUTMENT ;
    PORT
      LAYER metal3 ;
      RECT 0.000 502.005 0.070 502.075 ;
    END
  END wd_in[502]
  PIN wd_in[503]
    DIRECTION INPUT ;
    USE SIGNAL ;
    SHAPE ABUTMENT ;
    PORT
      LAYER metal3 ;
      RECT 0.000 502.285 0.070 502.355 ;
    END
  END wd_in[503]
  PIN wd_in[504]
    DIRECTION INPUT ;
    USE SIGNAL ;
    SHAPE ABUTMENT ;
    PORT
      LAYER metal3 ;
      RECT 0.000 502.565 0.070 502.635 ;
    END
  END wd_in[504]
  PIN wd_in[505]
    DIRECTION INPUT ;
    USE SIGNAL ;
    SHAPE ABUTMENT ;
    PORT
      LAYER metal3 ;
      RECT 0.000 502.845 0.070 502.915 ;
    END
  END wd_in[505]
  PIN wd_in[506]
    DIRECTION INPUT ;
    USE SIGNAL ;
    SHAPE ABUTMENT ;
    PORT
      LAYER metal3 ;
      RECT 0.000 503.125 0.070 503.195 ;
    END
  END wd_in[506]
  PIN wd_in[507]
    DIRECTION INPUT ;
    USE SIGNAL ;
    SHAPE ABUTMENT ;
    PORT
      LAYER metal3 ;
      RECT 0.000 503.405 0.070 503.475 ;
    END
  END wd_in[507]
  PIN wd_in[508]
    DIRECTION INPUT ;
    USE SIGNAL ;
    SHAPE ABUTMENT ;
    PORT
      LAYER metal3 ;
      RECT 0.000 503.685 0.070 503.755 ;
    END
  END wd_in[508]
  PIN wd_in[509]
    DIRECTION INPUT ;
    USE SIGNAL ;
    SHAPE ABUTMENT ;
    PORT
      LAYER metal3 ;
      RECT 0.000 503.965 0.070 504.035 ;
    END
  END wd_in[509]
  PIN wd_in[510]
    DIRECTION INPUT ;
    USE SIGNAL ;
    SHAPE ABUTMENT ;
    PORT
      LAYER metal3 ;
      RECT 0.000 504.245 0.070 504.315 ;
    END
  END wd_in[510]
  PIN wd_in[511]
    DIRECTION INPUT ;
    USE SIGNAL ;
    SHAPE ABUTMENT ;
    PORT
      LAYER metal3 ;
      RECT 0.000 504.525 0.070 504.595 ;
    END
  END wd_in[511]
  PIN addr_in[0]
    DIRECTION INPUT ;
    USE SIGNAL ;
    SHAPE ABUTMENT ;
    PORT
      LAYER metal3 ;
      RECT 0.000 541.485 0.070 541.555 ;
    END
  END addr_in[0]
  PIN addr_in[1]
    DIRECTION INPUT ;
    USE SIGNAL ;
    SHAPE ABUTMENT ;
    PORT
      LAYER metal3 ;
      RECT 0.000 541.765 0.070 541.835 ;
    END
  END addr_in[1]
  PIN addr_in[2]
    DIRECTION INPUT ;
    USE SIGNAL ;
    SHAPE ABUTMENT ;
    PORT
      LAYER metal3 ;
      RECT 0.000 542.045 0.070 542.115 ;
    END
  END addr_in[2]
  PIN addr_in[3]
    DIRECTION INPUT ;
    USE SIGNAL ;
    SHAPE ABUTMENT ;
    PORT
      LAYER metal3 ;
      RECT 0.000 542.325 0.070 542.395 ;
    END
  END addr_in[3]
  PIN addr_in[4]
    DIRECTION INPUT ;
    USE SIGNAL ;
    SHAPE ABUTMENT ;
    PORT
      LAYER metal3 ;
      RECT 0.000 542.605 0.070 542.675 ;
    END
  END addr_in[4]
  PIN addr_in[5]
    DIRECTION INPUT ;
    USE SIGNAL ;
    SHAPE ABUTMENT ;
    PORT
      LAYER metal3 ;
      RECT 0.000 542.885 0.070 542.955 ;
    END
  END addr_in[5]
  PIN addr_in[6]
    DIRECTION INPUT ;
    USE SIGNAL ;
    SHAPE ABUTMENT ;
    PORT
      LAYER metal3 ;
      RECT 0.000 543.165 0.070 543.235 ;
    END
  END addr_in[6]
  PIN addr_in[7]
    DIRECTION INPUT ;
    USE SIGNAL ;
    SHAPE ABUTMENT ;
    PORT
      LAYER metal3 ;
      RECT 0.000 543.445 0.070 543.515 ;
    END
  END addr_in[7]
  PIN we_in
    DIRECTION INPUT ;
    USE SIGNAL ;
    SHAPE ABUTMENT ;
    PORT
      LAYER metal3 ;
      RECT 0.000 580.405 0.070 580.475 ;
    END
  END we_in
  PIN ce_in
    DIRECTION INPUT ;
    USE SIGNAL ;
    SHAPE ABUTMENT ;
    PORT
      LAYER metal3 ;
      RECT 0.000 580.685 0.070 580.755 ;
    END
  END ce_in
  PIN clk
    DIRECTION INPUT ;
    USE SIGNAL ;
    SHAPE ABUTMENT ;
    PORT
      LAYER metal3 ;
      RECT 0.000 580.965 0.070 581.035 ;
    END
  END clk
  PIN VSS
    DIRECTION INOUT ;
    USE GROUND ;
    PORT
      LAYER metal4 ;
      RECT 1.260 1.400 1.540 582.400 ;
      RECT 3.500 1.400 3.780 582.400 ;
      RECT 5.740 1.400 6.020 582.400 ;
      RECT 7.980 1.400 8.260 582.400 ;
      RECT 10.220 1.400 10.500 582.400 ;
      RECT 12.460 1.400 12.740 582.400 ;
      RECT 14.700 1.400 14.980 582.400 ;
      RECT 16.940 1.400 17.220 582.400 ;
      RECT 19.180 1.400 19.460 582.400 ;
      RECT 21.420 1.400 21.700 582.400 ;
      RECT 23.660 1.400 23.940 582.400 ;
      RECT 25.900 1.400 26.180 582.400 ;
      RECT 28.140 1.400 28.420 582.400 ;
      RECT 30.380 1.400 30.660 582.400 ;
      RECT 32.620 1.400 32.900 582.400 ;
      RECT 34.860 1.400 35.140 582.400 ;
      RECT 37.100 1.400 37.380 582.400 ;
      RECT 39.340 1.400 39.620 582.400 ;
      RECT 41.580 1.400 41.860 582.400 ;
      RECT 43.820 1.400 44.100 582.400 ;
      RECT 46.060 1.400 46.340 582.400 ;
      RECT 48.300 1.400 48.580 582.400 ;
      RECT 50.540 1.400 50.820 582.400 ;
      RECT 52.780 1.400 53.060 582.400 ;
      RECT 55.020 1.400 55.300 582.400 ;
      RECT 57.260 1.400 57.540 582.400 ;
      RECT 59.500 1.400 59.780 582.400 ;
      RECT 61.740 1.400 62.020 582.400 ;
      RECT 63.980 1.400 64.260 582.400 ;
      RECT 66.220 1.400 66.500 582.400 ;
      RECT 68.460 1.400 68.740 582.400 ;
      RECT 70.700 1.400 70.980 582.400 ;
      RECT 72.940 1.400 73.220 582.400 ;
      RECT 75.180 1.400 75.460 582.400 ;
      RECT 77.420 1.400 77.700 582.400 ;
      RECT 79.660 1.400 79.940 582.400 ;
      RECT 81.900 1.400 82.180 582.400 ;
      RECT 84.140 1.400 84.420 582.400 ;
      RECT 86.380 1.400 86.660 582.400 ;
      RECT 88.620 1.400 88.900 582.400 ;
      RECT 90.860 1.400 91.140 582.400 ;
      RECT 93.100 1.400 93.380 582.400 ;
      RECT 95.340 1.400 95.620 582.400 ;
      RECT 97.580 1.400 97.860 582.400 ;
      RECT 99.820 1.400 100.100 582.400 ;
      RECT 102.060 1.400 102.340 582.400 ;
      RECT 104.300 1.400 104.580 582.400 ;
      RECT 106.540 1.400 106.820 582.400 ;
      RECT 108.780 1.400 109.060 582.400 ;
      RECT 111.020 1.400 111.300 582.400 ;
      RECT 113.260 1.400 113.540 582.400 ;
      RECT 115.500 1.400 115.780 582.400 ;
      RECT 117.740 1.400 118.020 582.400 ;
      RECT 119.980 1.400 120.260 582.400 ;
      RECT 122.220 1.400 122.500 582.400 ;
      RECT 124.460 1.400 124.740 582.400 ;
      RECT 126.700 1.400 126.980 582.400 ;
      RECT 128.940 1.400 129.220 582.400 ;
      RECT 131.180 1.400 131.460 582.400 ;
      RECT 133.420 1.400 133.700 582.400 ;
      RECT 135.660 1.400 135.940 582.400 ;
      RECT 137.900 1.400 138.180 582.400 ;
      RECT 140.140 1.400 140.420 582.400 ;
      RECT 142.380 1.400 142.660 582.400 ;
      RECT 144.620 1.400 144.900 582.400 ;
      RECT 146.860 1.400 147.140 582.400 ;
      RECT 149.100 1.400 149.380 582.400 ;
      RECT 151.340 1.400 151.620 582.400 ;
      RECT 153.580 1.400 153.860 582.400 ;
      RECT 155.820 1.400 156.100 582.400 ;
      RECT 158.060 1.400 158.340 582.400 ;
      RECT 160.300 1.400 160.580 582.400 ;
      RECT 162.540 1.400 162.820 582.400 ;
      RECT 164.780 1.400 165.060 582.400 ;
      RECT 167.020 1.400 167.300 582.400 ;
      RECT 169.260 1.400 169.540 582.400 ;
      RECT 171.500 1.400 171.780 582.400 ;
      RECT 173.740 1.400 174.020 582.400 ;
      RECT 175.980 1.400 176.260 582.400 ;
      RECT 178.220 1.400 178.500 582.400 ;
      RECT 180.460 1.400 180.740 582.400 ;
      RECT 182.700 1.400 182.980 582.400 ;
      RECT 184.940 1.400 185.220 582.400 ;
      RECT 187.180 1.400 187.460 582.400 ;
      RECT 189.420 1.400 189.700 582.400 ;
      RECT 191.660 1.400 191.940 582.400 ;
      RECT 193.900 1.400 194.180 582.400 ;
      RECT 196.140 1.400 196.420 582.400 ;
      RECT 198.380 1.400 198.660 582.400 ;
      RECT 200.620 1.400 200.900 582.400 ;
      RECT 202.860 1.400 203.140 582.400 ;
      RECT 205.100 1.400 205.380 582.400 ;
      RECT 207.340 1.400 207.620 582.400 ;
      RECT 209.580 1.400 209.860 582.400 ;
      RECT 211.820 1.400 212.100 582.400 ;
      RECT 214.060 1.400 214.340 582.400 ;
      RECT 216.300 1.400 216.580 582.400 ;
      RECT 218.540 1.400 218.820 582.400 ;
      RECT 220.780 1.400 221.060 582.400 ;
      RECT 223.020 1.400 223.300 582.400 ;
      RECT 225.260 1.400 225.540 582.400 ;
      RECT 227.500 1.400 227.780 582.400 ;
      RECT 229.740 1.400 230.020 582.400 ;
      RECT 231.980 1.400 232.260 582.400 ;
      RECT 234.220 1.400 234.500 582.400 ;
      RECT 236.460 1.400 236.740 582.400 ;
      RECT 238.700 1.400 238.980 582.400 ;
      RECT 240.940 1.400 241.220 582.400 ;
      RECT 243.180 1.400 243.460 582.400 ;
      RECT 245.420 1.400 245.700 582.400 ;
      RECT 247.660 1.400 247.940 582.400 ;
      RECT 249.900 1.400 250.180 582.400 ;
      RECT 252.140 1.400 252.420 582.400 ;
      RECT 254.380 1.400 254.660 582.400 ;
      RECT 256.620 1.400 256.900 582.400 ;
      RECT 258.860 1.400 259.140 582.400 ;
      RECT 261.100 1.400 261.380 582.400 ;
      RECT 263.340 1.400 263.620 582.400 ;
      RECT 265.580 1.400 265.860 582.400 ;
      RECT 267.820 1.400 268.100 582.400 ;
      RECT 270.060 1.400 270.340 582.400 ;
      RECT 272.300 1.400 272.580 582.400 ;
      RECT 274.540 1.400 274.820 582.400 ;
      RECT 276.780 1.400 277.060 582.400 ;
      RECT 279.020 1.400 279.300 582.400 ;
      RECT 281.260 1.400 281.540 582.400 ;
      RECT 283.500 1.400 283.780 582.400 ;
      RECT 285.740 1.400 286.020 582.400 ;
      RECT 287.980 1.400 288.260 582.400 ;
      RECT 290.220 1.400 290.500 582.400 ;
      RECT 292.460 1.400 292.740 582.400 ;
      RECT 294.700 1.400 294.980 582.400 ;
      RECT 296.940 1.400 297.220 582.400 ;
      RECT 299.180 1.400 299.460 582.400 ;
      RECT 301.420 1.400 301.700 582.400 ;
      RECT 303.660 1.400 303.940 582.400 ;
      RECT 305.900 1.400 306.180 582.400 ;
      RECT 308.140 1.400 308.420 582.400 ;
      RECT 310.380 1.400 310.660 582.400 ;
      RECT 312.620 1.400 312.900 582.400 ;
      RECT 314.860 1.400 315.140 582.400 ;
      RECT 317.100 1.400 317.380 582.400 ;
      RECT 319.340 1.400 319.620 582.400 ;
      RECT 321.580 1.400 321.860 582.400 ;
      RECT 323.820 1.400 324.100 582.400 ;
      RECT 326.060 1.400 326.340 582.400 ;
      RECT 328.300 1.400 328.580 582.400 ;
      RECT 330.540 1.400 330.820 582.400 ;
      RECT 332.780 1.400 333.060 582.400 ;
      RECT 335.020 1.400 335.300 582.400 ;
      RECT 337.260 1.400 337.540 582.400 ;
      RECT 339.500 1.400 339.780 582.400 ;
      RECT 341.740 1.400 342.020 582.400 ;
      RECT 343.980 1.400 344.260 582.400 ;
      RECT 346.220 1.400 346.500 582.400 ;
      RECT 348.460 1.400 348.740 582.400 ;
      RECT 350.700 1.400 350.980 582.400 ;
      RECT 352.940 1.400 353.220 582.400 ;
      RECT 355.180 1.400 355.460 582.400 ;
      RECT 357.420 1.400 357.700 582.400 ;
      RECT 359.660 1.400 359.940 582.400 ;
      RECT 361.900 1.400 362.180 582.400 ;
      RECT 364.140 1.400 364.420 582.400 ;
      RECT 366.380 1.400 366.660 582.400 ;
      RECT 368.620 1.400 368.900 582.400 ;
      RECT 370.860 1.400 371.140 582.400 ;
      RECT 373.100 1.400 373.380 582.400 ;
      RECT 375.340 1.400 375.620 582.400 ;
      RECT 377.580 1.400 377.860 582.400 ;
      RECT 379.820 1.400 380.100 582.400 ;
      RECT 382.060 1.400 382.340 582.400 ;
      RECT 384.300 1.400 384.580 582.400 ;
      RECT 386.540 1.400 386.820 582.400 ;
      RECT 388.780 1.400 389.060 582.400 ;
      RECT 391.020 1.400 391.300 582.400 ;
      RECT 393.260 1.400 393.540 582.400 ;
      RECT 395.500 1.400 395.780 582.400 ;
      RECT 397.740 1.400 398.020 582.400 ;
      RECT 399.980 1.400 400.260 582.400 ;
      RECT 402.220 1.400 402.500 582.400 ;
      RECT 404.460 1.400 404.740 582.400 ;
      RECT 406.700 1.400 406.980 582.400 ;
      RECT 408.940 1.400 409.220 582.400 ;
      RECT 411.180 1.400 411.460 582.400 ;
      RECT 413.420 1.400 413.700 582.400 ;
      RECT 415.660 1.400 415.940 582.400 ;
    END
  END VSS
  PIN VDD
    DIRECTION INOUT ;
    USE POWER ;
    PORT
      LAYER metal4 ;
      RECT 2.380 1.400 2.660 582.400 ;
      RECT 4.620 1.400 4.900 582.400 ;
      RECT 6.860 1.400 7.140 582.400 ;
      RECT 9.100 1.400 9.380 582.400 ;
      RECT 11.340 1.400 11.620 582.400 ;
      RECT 13.580 1.400 13.860 582.400 ;
      RECT 15.820 1.400 16.100 582.400 ;
      RECT 18.060 1.400 18.340 582.400 ;
      RECT 20.300 1.400 20.580 582.400 ;
      RECT 22.540 1.400 22.820 582.400 ;
      RECT 24.780 1.400 25.060 582.400 ;
      RECT 27.020 1.400 27.300 582.400 ;
      RECT 29.260 1.400 29.540 582.400 ;
      RECT 31.500 1.400 31.780 582.400 ;
      RECT 33.740 1.400 34.020 582.400 ;
      RECT 35.980 1.400 36.260 582.400 ;
      RECT 38.220 1.400 38.500 582.400 ;
      RECT 40.460 1.400 40.740 582.400 ;
      RECT 42.700 1.400 42.980 582.400 ;
      RECT 44.940 1.400 45.220 582.400 ;
      RECT 47.180 1.400 47.460 582.400 ;
      RECT 49.420 1.400 49.700 582.400 ;
      RECT 51.660 1.400 51.940 582.400 ;
      RECT 53.900 1.400 54.180 582.400 ;
      RECT 56.140 1.400 56.420 582.400 ;
      RECT 58.380 1.400 58.660 582.400 ;
      RECT 60.620 1.400 60.900 582.400 ;
      RECT 62.860 1.400 63.140 582.400 ;
      RECT 65.100 1.400 65.380 582.400 ;
      RECT 67.340 1.400 67.620 582.400 ;
      RECT 69.580 1.400 69.860 582.400 ;
      RECT 71.820 1.400 72.100 582.400 ;
      RECT 74.060 1.400 74.340 582.400 ;
      RECT 76.300 1.400 76.580 582.400 ;
      RECT 78.540 1.400 78.820 582.400 ;
      RECT 80.780 1.400 81.060 582.400 ;
      RECT 83.020 1.400 83.300 582.400 ;
      RECT 85.260 1.400 85.540 582.400 ;
      RECT 87.500 1.400 87.780 582.400 ;
      RECT 89.740 1.400 90.020 582.400 ;
      RECT 91.980 1.400 92.260 582.400 ;
      RECT 94.220 1.400 94.500 582.400 ;
      RECT 96.460 1.400 96.740 582.400 ;
      RECT 98.700 1.400 98.980 582.400 ;
      RECT 100.940 1.400 101.220 582.400 ;
      RECT 103.180 1.400 103.460 582.400 ;
      RECT 105.420 1.400 105.700 582.400 ;
      RECT 107.660 1.400 107.940 582.400 ;
      RECT 109.900 1.400 110.180 582.400 ;
      RECT 112.140 1.400 112.420 582.400 ;
      RECT 114.380 1.400 114.660 582.400 ;
      RECT 116.620 1.400 116.900 582.400 ;
      RECT 118.860 1.400 119.140 582.400 ;
      RECT 121.100 1.400 121.380 582.400 ;
      RECT 123.340 1.400 123.620 582.400 ;
      RECT 125.580 1.400 125.860 582.400 ;
      RECT 127.820 1.400 128.100 582.400 ;
      RECT 130.060 1.400 130.340 582.400 ;
      RECT 132.300 1.400 132.580 582.400 ;
      RECT 134.540 1.400 134.820 582.400 ;
      RECT 136.780 1.400 137.060 582.400 ;
      RECT 139.020 1.400 139.300 582.400 ;
      RECT 141.260 1.400 141.540 582.400 ;
      RECT 143.500 1.400 143.780 582.400 ;
      RECT 145.740 1.400 146.020 582.400 ;
      RECT 147.980 1.400 148.260 582.400 ;
      RECT 150.220 1.400 150.500 582.400 ;
      RECT 152.460 1.400 152.740 582.400 ;
      RECT 154.700 1.400 154.980 582.400 ;
      RECT 156.940 1.400 157.220 582.400 ;
      RECT 159.180 1.400 159.460 582.400 ;
      RECT 161.420 1.400 161.700 582.400 ;
      RECT 163.660 1.400 163.940 582.400 ;
      RECT 165.900 1.400 166.180 582.400 ;
      RECT 168.140 1.400 168.420 582.400 ;
      RECT 170.380 1.400 170.660 582.400 ;
      RECT 172.620 1.400 172.900 582.400 ;
      RECT 174.860 1.400 175.140 582.400 ;
      RECT 177.100 1.400 177.380 582.400 ;
      RECT 179.340 1.400 179.620 582.400 ;
      RECT 181.580 1.400 181.860 582.400 ;
      RECT 183.820 1.400 184.100 582.400 ;
      RECT 186.060 1.400 186.340 582.400 ;
      RECT 188.300 1.400 188.580 582.400 ;
      RECT 190.540 1.400 190.820 582.400 ;
      RECT 192.780 1.400 193.060 582.400 ;
      RECT 195.020 1.400 195.300 582.400 ;
      RECT 197.260 1.400 197.540 582.400 ;
      RECT 199.500 1.400 199.780 582.400 ;
      RECT 201.740 1.400 202.020 582.400 ;
      RECT 203.980 1.400 204.260 582.400 ;
      RECT 206.220 1.400 206.500 582.400 ;
      RECT 208.460 1.400 208.740 582.400 ;
      RECT 210.700 1.400 210.980 582.400 ;
      RECT 212.940 1.400 213.220 582.400 ;
      RECT 215.180 1.400 215.460 582.400 ;
      RECT 217.420 1.400 217.700 582.400 ;
      RECT 219.660 1.400 219.940 582.400 ;
      RECT 221.900 1.400 222.180 582.400 ;
      RECT 224.140 1.400 224.420 582.400 ;
      RECT 226.380 1.400 226.660 582.400 ;
      RECT 228.620 1.400 228.900 582.400 ;
      RECT 230.860 1.400 231.140 582.400 ;
      RECT 233.100 1.400 233.380 582.400 ;
      RECT 235.340 1.400 235.620 582.400 ;
      RECT 237.580 1.400 237.860 582.400 ;
      RECT 239.820 1.400 240.100 582.400 ;
      RECT 242.060 1.400 242.340 582.400 ;
      RECT 244.300 1.400 244.580 582.400 ;
      RECT 246.540 1.400 246.820 582.400 ;
      RECT 248.780 1.400 249.060 582.400 ;
      RECT 251.020 1.400 251.300 582.400 ;
      RECT 253.260 1.400 253.540 582.400 ;
      RECT 255.500 1.400 255.780 582.400 ;
      RECT 257.740 1.400 258.020 582.400 ;
      RECT 259.980 1.400 260.260 582.400 ;
      RECT 262.220 1.400 262.500 582.400 ;
      RECT 264.460 1.400 264.740 582.400 ;
      RECT 266.700 1.400 266.980 582.400 ;
      RECT 268.940 1.400 269.220 582.400 ;
      RECT 271.180 1.400 271.460 582.400 ;
      RECT 273.420 1.400 273.700 582.400 ;
      RECT 275.660 1.400 275.940 582.400 ;
      RECT 277.900 1.400 278.180 582.400 ;
      RECT 280.140 1.400 280.420 582.400 ;
      RECT 282.380 1.400 282.660 582.400 ;
      RECT 284.620 1.400 284.900 582.400 ;
      RECT 286.860 1.400 287.140 582.400 ;
      RECT 289.100 1.400 289.380 582.400 ;
      RECT 291.340 1.400 291.620 582.400 ;
      RECT 293.580 1.400 293.860 582.400 ;
      RECT 295.820 1.400 296.100 582.400 ;
      RECT 298.060 1.400 298.340 582.400 ;
      RECT 300.300 1.400 300.580 582.400 ;
      RECT 302.540 1.400 302.820 582.400 ;
      RECT 304.780 1.400 305.060 582.400 ;
      RECT 307.020 1.400 307.300 582.400 ;
      RECT 309.260 1.400 309.540 582.400 ;
      RECT 311.500 1.400 311.780 582.400 ;
      RECT 313.740 1.400 314.020 582.400 ;
      RECT 315.980 1.400 316.260 582.400 ;
      RECT 318.220 1.400 318.500 582.400 ;
      RECT 320.460 1.400 320.740 582.400 ;
      RECT 322.700 1.400 322.980 582.400 ;
      RECT 324.940 1.400 325.220 582.400 ;
      RECT 327.180 1.400 327.460 582.400 ;
      RECT 329.420 1.400 329.700 582.400 ;
      RECT 331.660 1.400 331.940 582.400 ;
      RECT 333.900 1.400 334.180 582.400 ;
      RECT 336.140 1.400 336.420 582.400 ;
      RECT 338.380 1.400 338.660 582.400 ;
      RECT 340.620 1.400 340.900 582.400 ;
      RECT 342.860 1.400 343.140 582.400 ;
      RECT 345.100 1.400 345.380 582.400 ;
      RECT 347.340 1.400 347.620 582.400 ;
      RECT 349.580 1.400 349.860 582.400 ;
      RECT 351.820 1.400 352.100 582.400 ;
      RECT 354.060 1.400 354.340 582.400 ;
      RECT 356.300 1.400 356.580 582.400 ;
      RECT 358.540 1.400 358.820 582.400 ;
      RECT 360.780 1.400 361.060 582.400 ;
      RECT 363.020 1.400 363.300 582.400 ;
      RECT 365.260 1.400 365.540 582.400 ;
      RECT 367.500 1.400 367.780 582.400 ;
      RECT 369.740 1.400 370.020 582.400 ;
      RECT 371.980 1.400 372.260 582.400 ;
      RECT 374.220 1.400 374.500 582.400 ;
      RECT 376.460 1.400 376.740 582.400 ;
      RECT 378.700 1.400 378.980 582.400 ;
      RECT 380.940 1.400 381.220 582.400 ;
      RECT 383.180 1.400 383.460 582.400 ;
      RECT 385.420 1.400 385.700 582.400 ;
      RECT 387.660 1.400 387.940 582.400 ;
      RECT 389.900 1.400 390.180 582.400 ;
      RECT 392.140 1.400 392.420 582.400 ;
      RECT 394.380 1.400 394.660 582.400 ;
      RECT 396.620 1.400 396.900 582.400 ;
      RECT 398.860 1.400 399.140 582.400 ;
      RECT 401.100 1.400 401.380 582.400 ;
      RECT 403.340 1.400 403.620 582.400 ;
      RECT 405.580 1.400 405.860 582.400 ;
      RECT 407.820 1.400 408.100 582.400 ;
      RECT 410.060 1.400 410.340 582.400 ;
      RECT 412.300 1.400 412.580 582.400 ;
      RECT 414.540 1.400 414.820 582.400 ;
    END
  END VDD
  OBS
    LAYER metal1 ;
    RECT 0 0 417.430 583.800 ;
    LAYER metal2 ;
    RECT 0 0 417.430 583.800 ;
    LAYER metal3 ;
    RECT 0.070 0 417.430 583.800 ;
    RECT 0 0.000 0.070 1.365 ;
    RECT 0 1.435 0.070 1.645 ;
    RECT 0 1.715 0.070 1.925 ;
    RECT 0 1.995 0.070 2.205 ;
    RECT 0 2.275 0.070 2.485 ;
    RECT 0 2.555 0.070 2.765 ;
    RECT 0 2.835 0.070 3.045 ;
    RECT 0 3.115 0.070 3.325 ;
    RECT 0 3.395 0.070 3.605 ;
    RECT 0 3.675 0.070 3.885 ;
    RECT 0 3.955 0.070 4.165 ;
    RECT 0 4.235 0.070 4.445 ;
    RECT 0 4.515 0.070 4.725 ;
    RECT 0 4.795 0.070 5.005 ;
    RECT 0 5.075 0.070 5.285 ;
    RECT 0 5.355 0.070 5.565 ;
    RECT 0 5.635 0.070 5.845 ;
    RECT 0 5.915 0.070 6.125 ;
    RECT 0 6.195 0.070 6.405 ;
    RECT 0 6.475 0.070 6.685 ;
    RECT 0 6.755 0.070 6.965 ;
    RECT 0 7.035 0.070 7.245 ;
    RECT 0 7.315 0.070 7.525 ;
    RECT 0 7.595 0.070 7.805 ;
    RECT 0 7.875 0.070 8.085 ;
    RECT 0 8.155 0.070 8.365 ;
    RECT 0 8.435 0.070 8.645 ;
    RECT 0 8.715 0.070 8.925 ;
    RECT 0 8.995 0.070 9.205 ;
    RECT 0 9.275 0.070 9.485 ;
    RECT 0 9.555 0.070 9.765 ;
    RECT 0 9.835 0.070 10.045 ;
    RECT 0 10.115 0.070 10.325 ;
    RECT 0 10.395 0.070 10.605 ;
    RECT 0 10.675 0.070 10.885 ;
    RECT 0 10.955 0.070 11.165 ;
    RECT 0 11.235 0.070 11.445 ;
    RECT 0 11.515 0.070 11.725 ;
    RECT 0 11.795 0.070 12.005 ;
    RECT 0 12.075 0.070 12.285 ;
    RECT 0 12.355 0.070 12.565 ;
    RECT 0 12.635 0.070 12.845 ;
    RECT 0 12.915 0.070 13.125 ;
    RECT 0 13.195 0.070 13.405 ;
    RECT 0 13.475 0.070 13.685 ;
    RECT 0 13.755 0.070 13.965 ;
    RECT 0 14.035 0.070 14.245 ;
    RECT 0 14.315 0.070 14.525 ;
    RECT 0 14.595 0.070 14.805 ;
    RECT 0 14.875 0.070 15.085 ;
    RECT 0 15.155 0.070 15.365 ;
    RECT 0 15.435 0.070 15.645 ;
    RECT 0 15.715 0.070 15.925 ;
    RECT 0 15.995 0.070 16.205 ;
    RECT 0 16.275 0.070 16.485 ;
    RECT 0 16.555 0.070 16.765 ;
    RECT 0 16.835 0.070 17.045 ;
    RECT 0 17.115 0.070 17.325 ;
    RECT 0 17.395 0.070 17.605 ;
    RECT 0 17.675 0.070 17.885 ;
    RECT 0 17.955 0.070 18.165 ;
    RECT 0 18.235 0.070 18.445 ;
    RECT 0 18.515 0.070 18.725 ;
    RECT 0 18.795 0.070 19.005 ;
    RECT 0 19.075 0.070 19.285 ;
    RECT 0 19.355 0.070 19.565 ;
    RECT 0 19.635 0.070 19.845 ;
    RECT 0 19.915 0.070 20.125 ;
    RECT 0 20.195 0.070 20.405 ;
    RECT 0 20.475 0.070 20.685 ;
    RECT 0 20.755 0.070 20.965 ;
    RECT 0 21.035 0.070 21.245 ;
    RECT 0 21.315 0.070 21.525 ;
    RECT 0 21.595 0.070 21.805 ;
    RECT 0 21.875 0.070 22.085 ;
    RECT 0 22.155 0.070 22.365 ;
    RECT 0 22.435 0.070 22.645 ;
    RECT 0 22.715 0.070 22.925 ;
    RECT 0 22.995 0.070 23.205 ;
    RECT 0 23.275 0.070 23.485 ;
    RECT 0 23.555 0.070 23.765 ;
    RECT 0 23.835 0.070 24.045 ;
    RECT 0 24.115 0.070 24.325 ;
    RECT 0 24.395 0.070 24.605 ;
    RECT 0 24.675 0.070 24.885 ;
    RECT 0 24.955 0.070 25.165 ;
    RECT 0 25.235 0.070 25.445 ;
    RECT 0 25.515 0.070 25.725 ;
    RECT 0 25.795 0.070 26.005 ;
    RECT 0 26.075 0.070 26.285 ;
    RECT 0 26.355 0.070 26.565 ;
    RECT 0 26.635 0.070 26.845 ;
    RECT 0 26.915 0.070 27.125 ;
    RECT 0 27.195 0.070 27.405 ;
    RECT 0 27.475 0.070 27.685 ;
    RECT 0 27.755 0.070 27.965 ;
    RECT 0 28.035 0.070 28.245 ;
    RECT 0 28.315 0.070 28.525 ;
    RECT 0 28.595 0.070 28.805 ;
    RECT 0 28.875 0.070 29.085 ;
    RECT 0 29.155 0.070 29.365 ;
    RECT 0 29.435 0.070 29.645 ;
    RECT 0 29.715 0.070 29.925 ;
    RECT 0 29.995 0.070 30.205 ;
    RECT 0 30.275 0.070 30.485 ;
    RECT 0 30.555 0.070 30.765 ;
    RECT 0 30.835 0.070 31.045 ;
    RECT 0 31.115 0.070 31.325 ;
    RECT 0 31.395 0.070 31.605 ;
    RECT 0 31.675 0.070 31.885 ;
    RECT 0 31.955 0.070 32.165 ;
    RECT 0 32.235 0.070 32.445 ;
    RECT 0 32.515 0.070 32.725 ;
    RECT 0 32.795 0.070 33.005 ;
    RECT 0 33.075 0.070 33.285 ;
    RECT 0 33.355 0.070 33.565 ;
    RECT 0 33.635 0.070 33.845 ;
    RECT 0 33.915 0.070 34.125 ;
    RECT 0 34.195 0.070 34.405 ;
    RECT 0 34.475 0.070 34.685 ;
    RECT 0 34.755 0.070 34.965 ;
    RECT 0 35.035 0.070 35.245 ;
    RECT 0 35.315 0.070 35.525 ;
    RECT 0 35.595 0.070 35.805 ;
    RECT 0 35.875 0.070 36.085 ;
    RECT 0 36.155 0.070 36.365 ;
    RECT 0 36.435 0.070 36.645 ;
    RECT 0 36.715 0.070 36.925 ;
    RECT 0 36.995 0.070 37.205 ;
    RECT 0 37.275 0.070 37.485 ;
    RECT 0 37.555 0.070 37.765 ;
    RECT 0 37.835 0.070 38.045 ;
    RECT 0 38.115 0.070 38.325 ;
    RECT 0 38.395 0.070 38.605 ;
    RECT 0 38.675 0.070 38.885 ;
    RECT 0 38.955 0.070 39.165 ;
    RECT 0 39.235 0.070 39.445 ;
    RECT 0 39.515 0.070 39.725 ;
    RECT 0 39.795 0.070 40.005 ;
    RECT 0 40.075 0.070 40.285 ;
    RECT 0 40.355 0.070 40.565 ;
    RECT 0 40.635 0.070 40.845 ;
    RECT 0 40.915 0.070 41.125 ;
    RECT 0 41.195 0.070 41.405 ;
    RECT 0 41.475 0.070 41.685 ;
    RECT 0 41.755 0.070 41.965 ;
    RECT 0 42.035 0.070 42.245 ;
    RECT 0 42.315 0.070 42.525 ;
    RECT 0 42.595 0.070 42.805 ;
    RECT 0 42.875 0.070 43.085 ;
    RECT 0 43.155 0.070 43.365 ;
    RECT 0 43.435 0.070 43.645 ;
    RECT 0 43.715 0.070 43.925 ;
    RECT 0 43.995 0.070 44.205 ;
    RECT 0 44.275 0.070 44.485 ;
    RECT 0 44.555 0.070 44.765 ;
    RECT 0 44.835 0.070 45.045 ;
    RECT 0 45.115 0.070 45.325 ;
    RECT 0 45.395 0.070 45.605 ;
    RECT 0 45.675 0.070 45.885 ;
    RECT 0 45.955 0.070 46.165 ;
    RECT 0 46.235 0.070 46.445 ;
    RECT 0 46.515 0.070 46.725 ;
    RECT 0 46.795 0.070 47.005 ;
    RECT 0 47.075 0.070 47.285 ;
    RECT 0 47.355 0.070 47.565 ;
    RECT 0 47.635 0.070 47.845 ;
    RECT 0 47.915 0.070 48.125 ;
    RECT 0 48.195 0.070 48.405 ;
    RECT 0 48.475 0.070 48.685 ;
    RECT 0 48.755 0.070 48.965 ;
    RECT 0 49.035 0.070 49.245 ;
    RECT 0 49.315 0.070 49.525 ;
    RECT 0 49.595 0.070 49.805 ;
    RECT 0 49.875 0.070 50.085 ;
    RECT 0 50.155 0.070 50.365 ;
    RECT 0 50.435 0.070 50.645 ;
    RECT 0 50.715 0.070 50.925 ;
    RECT 0 50.995 0.070 51.205 ;
    RECT 0 51.275 0.070 51.485 ;
    RECT 0 51.555 0.070 51.765 ;
    RECT 0 51.835 0.070 52.045 ;
    RECT 0 52.115 0.070 52.325 ;
    RECT 0 52.395 0.070 52.605 ;
    RECT 0 52.675 0.070 52.885 ;
    RECT 0 52.955 0.070 53.165 ;
    RECT 0 53.235 0.070 53.445 ;
    RECT 0 53.515 0.070 53.725 ;
    RECT 0 53.795 0.070 54.005 ;
    RECT 0 54.075 0.070 54.285 ;
    RECT 0 54.355 0.070 54.565 ;
    RECT 0 54.635 0.070 54.845 ;
    RECT 0 54.915 0.070 55.125 ;
    RECT 0 55.195 0.070 55.405 ;
    RECT 0 55.475 0.070 55.685 ;
    RECT 0 55.755 0.070 55.965 ;
    RECT 0 56.035 0.070 56.245 ;
    RECT 0 56.315 0.070 56.525 ;
    RECT 0 56.595 0.070 56.805 ;
    RECT 0 56.875 0.070 57.085 ;
    RECT 0 57.155 0.070 57.365 ;
    RECT 0 57.435 0.070 57.645 ;
    RECT 0 57.715 0.070 57.925 ;
    RECT 0 57.995 0.070 58.205 ;
    RECT 0 58.275 0.070 58.485 ;
    RECT 0 58.555 0.070 58.765 ;
    RECT 0 58.835 0.070 59.045 ;
    RECT 0 59.115 0.070 59.325 ;
    RECT 0 59.395 0.070 59.605 ;
    RECT 0 59.675 0.070 59.885 ;
    RECT 0 59.955 0.070 60.165 ;
    RECT 0 60.235 0.070 60.445 ;
    RECT 0 60.515 0.070 60.725 ;
    RECT 0 60.795 0.070 61.005 ;
    RECT 0 61.075 0.070 61.285 ;
    RECT 0 61.355 0.070 61.565 ;
    RECT 0 61.635 0.070 61.845 ;
    RECT 0 61.915 0.070 62.125 ;
    RECT 0 62.195 0.070 62.405 ;
    RECT 0 62.475 0.070 62.685 ;
    RECT 0 62.755 0.070 62.965 ;
    RECT 0 63.035 0.070 63.245 ;
    RECT 0 63.315 0.070 63.525 ;
    RECT 0 63.595 0.070 63.805 ;
    RECT 0 63.875 0.070 64.085 ;
    RECT 0 64.155 0.070 64.365 ;
    RECT 0 64.435 0.070 64.645 ;
    RECT 0 64.715 0.070 64.925 ;
    RECT 0 64.995 0.070 65.205 ;
    RECT 0 65.275 0.070 65.485 ;
    RECT 0 65.555 0.070 65.765 ;
    RECT 0 65.835 0.070 66.045 ;
    RECT 0 66.115 0.070 66.325 ;
    RECT 0 66.395 0.070 66.605 ;
    RECT 0 66.675 0.070 66.885 ;
    RECT 0 66.955 0.070 67.165 ;
    RECT 0 67.235 0.070 67.445 ;
    RECT 0 67.515 0.070 67.725 ;
    RECT 0 67.795 0.070 68.005 ;
    RECT 0 68.075 0.070 68.285 ;
    RECT 0 68.355 0.070 68.565 ;
    RECT 0 68.635 0.070 68.845 ;
    RECT 0 68.915 0.070 69.125 ;
    RECT 0 69.195 0.070 69.405 ;
    RECT 0 69.475 0.070 69.685 ;
    RECT 0 69.755 0.070 69.965 ;
    RECT 0 70.035 0.070 70.245 ;
    RECT 0 70.315 0.070 70.525 ;
    RECT 0 70.595 0.070 70.805 ;
    RECT 0 70.875 0.070 71.085 ;
    RECT 0 71.155 0.070 71.365 ;
    RECT 0 71.435 0.070 71.645 ;
    RECT 0 71.715 0.070 71.925 ;
    RECT 0 71.995 0.070 72.205 ;
    RECT 0 72.275 0.070 72.485 ;
    RECT 0 72.555 0.070 72.765 ;
    RECT 0 72.835 0.070 73.045 ;
    RECT 0 73.115 0.070 73.325 ;
    RECT 0 73.395 0.070 73.605 ;
    RECT 0 73.675 0.070 73.885 ;
    RECT 0 73.955 0.070 74.165 ;
    RECT 0 74.235 0.070 74.445 ;
    RECT 0 74.515 0.070 74.725 ;
    RECT 0 74.795 0.070 75.005 ;
    RECT 0 75.075 0.070 75.285 ;
    RECT 0 75.355 0.070 75.565 ;
    RECT 0 75.635 0.070 75.845 ;
    RECT 0 75.915 0.070 76.125 ;
    RECT 0 76.195 0.070 76.405 ;
    RECT 0 76.475 0.070 76.685 ;
    RECT 0 76.755 0.070 76.965 ;
    RECT 0 77.035 0.070 77.245 ;
    RECT 0 77.315 0.070 77.525 ;
    RECT 0 77.595 0.070 77.805 ;
    RECT 0 77.875 0.070 78.085 ;
    RECT 0 78.155 0.070 78.365 ;
    RECT 0 78.435 0.070 78.645 ;
    RECT 0 78.715 0.070 78.925 ;
    RECT 0 78.995 0.070 79.205 ;
    RECT 0 79.275 0.070 79.485 ;
    RECT 0 79.555 0.070 79.765 ;
    RECT 0 79.835 0.070 80.045 ;
    RECT 0 80.115 0.070 80.325 ;
    RECT 0 80.395 0.070 80.605 ;
    RECT 0 80.675 0.070 80.885 ;
    RECT 0 80.955 0.070 81.165 ;
    RECT 0 81.235 0.070 81.445 ;
    RECT 0 81.515 0.070 81.725 ;
    RECT 0 81.795 0.070 82.005 ;
    RECT 0 82.075 0.070 82.285 ;
    RECT 0 82.355 0.070 82.565 ;
    RECT 0 82.635 0.070 82.845 ;
    RECT 0 82.915 0.070 83.125 ;
    RECT 0 83.195 0.070 83.405 ;
    RECT 0 83.475 0.070 83.685 ;
    RECT 0 83.755 0.070 83.965 ;
    RECT 0 84.035 0.070 84.245 ;
    RECT 0 84.315 0.070 84.525 ;
    RECT 0 84.595 0.070 84.805 ;
    RECT 0 84.875 0.070 85.085 ;
    RECT 0 85.155 0.070 85.365 ;
    RECT 0 85.435 0.070 85.645 ;
    RECT 0 85.715 0.070 85.925 ;
    RECT 0 85.995 0.070 86.205 ;
    RECT 0 86.275 0.070 86.485 ;
    RECT 0 86.555 0.070 86.765 ;
    RECT 0 86.835 0.070 87.045 ;
    RECT 0 87.115 0.070 87.325 ;
    RECT 0 87.395 0.070 87.605 ;
    RECT 0 87.675 0.070 87.885 ;
    RECT 0 87.955 0.070 88.165 ;
    RECT 0 88.235 0.070 88.445 ;
    RECT 0 88.515 0.070 88.725 ;
    RECT 0 88.795 0.070 89.005 ;
    RECT 0 89.075 0.070 89.285 ;
    RECT 0 89.355 0.070 89.565 ;
    RECT 0 89.635 0.070 89.845 ;
    RECT 0 89.915 0.070 90.125 ;
    RECT 0 90.195 0.070 90.405 ;
    RECT 0 90.475 0.070 90.685 ;
    RECT 0 90.755 0.070 90.965 ;
    RECT 0 91.035 0.070 91.245 ;
    RECT 0 91.315 0.070 91.525 ;
    RECT 0 91.595 0.070 91.805 ;
    RECT 0 91.875 0.070 92.085 ;
    RECT 0 92.155 0.070 92.365 ;
    RECT 0 92.435 0.070 92.645 ;
    RECT 0 92.715 0.070 92.925 ;
    RECT 0 92.995 0.070 93.205 ;
    RECT 0 93.275 0.070 93.485 ;
    RECT 0 93.555 0.070 93.765 ;
    RECT 0 93.835 0.070 94.045 ;
    RECT 0 94.115 0.070 94.325 ;
    RECT 0 94.395 0.070 94.605 ;
    RECT 0 94.675 0.070 94.885 ;
    RECT 0 94.955 0.070 95.165 ;
    RECT 0 95.235 0.070 95.445 ;
    RECT 0 95.515 0.070 95.725 ;
    RECT 0 95.795 0.070 96.005 ;
    RECT 0 96.075 0.070 96.285 ;
    RECT 0 96.355 0.070 96.565 ;
    RECT 0 96.635 0.070 96.845 ;
    RECT 0 96.915 0.070 97.125 ;
    RECT 0 97.195 0.070 97.405 ;
    RECT 0 97.475 0.070 97.685 ;
    RECT 0 97.755 0.070 97.965 ;
    RECT 0 98.035 0.070 98.245 ;
    RECT 0 98.315 0.070 98.525 ;
    RECT 0 98.595 0.070 98.805 ;
    RECT 0 98.875 0.070 99.085 ;
    RECT 0 99.155 0.070 99.365 ;
    RECT 0 99.435 0.070 99.645 ;
    RECT 0 99.715 0.070 99.925 ;
    RECT 0 99.995 0.070 100.205 ;
    RECT 0 100.275 0.070 100.485 ;
    RECT 0 100.555 0.070 100.765 ;
    RECT 0 100.835 0.070 101.045 ;
    RECT 0 101.115 0.070 101.325 ;
    RECT 0 101.395 0.070 101.605 ;
    RECT 0 101.675 0.070 101.885 ;
    RECT 0 101.955 0.070 102.165 ;
    RECT 0 102.235 0.070 102.445 ;
    RECT 0 102.515 0.070 102.725 ;
    RECT 0 102.795 0.070 103.005 ;
    RECT 0 103.075 0.070 103.285 ;
    RECT 0 103.355 0.070 103.565 ;
    RECT 0 103.635 0.070 103.845 ;
    RECT 0 103.915 0.070 104.125 ;
    RECT 0 104.195 0.070 104.405 ;
    RECT 0 104.475 0.070 104.685 ;
    RECT 0 104.755 0.070 104.965 ;
    RECT 0 105.035 0.070 105.245 ;
    RECT 0 105.315 0.070 105.525 ;
    RECT 0 105.595 0.070 105.805 ;
    RECT 0 105.875 0.070 106.085 ;
    RECT 0 106.155 0.070 106.365 ;
    RECT 0 106.435 0.070 106.645 ;
    RECT 0 106.715 0.070 106.925 ;
    RECT 0 106.995 0.070 107.205 ;
    RECT 0 107.275 0.070 107.485 ;
    RECT 0 107.555 0.070 107.765 ;
    RECT 0 107.835 0.070 108.045 ;
    RECT 0 108.115 0.070 108.325 ;
    RECT 0 108.395 0.070 108.605 ;
    RECT 0 108.675 0.070 108.885 ;
    RECT 0 108.955 0.070 109.165 ;
    RECT 0 109.235 0.070 109.445 ;
    RECT 0 109.515 0.070 109.725 ;
    RECT 0 109.795 0.070 110.005 ;
    RECT 0 110.075 0.070 110.285 ;
    RECT 0 110.355 0.070 110.565 ;
    RECT 0 110.635 0.070 110.845 ;
    RECT 0 110.915 0.070 111.125 ;
    RECT 0 111.195 0.070 111.405 ;
    RECT 0 111.475 0.070 111.685 ;
    RECT 0 111.755 0.070 111.965 ;
    RECT 0 112.035 0.070 112.245 ;
    RECT 0 112.315 0.070 112.525 ;
    RECT 0 112.595 0.070 112.805 ;
    RECT 0 112.875 0.070 113.085 ;
    RECT 0 113.155 0.070 113.365 ;
    RECT 0 113.435 0.070 113.645 ;
    RECT 0 113.715 0.070 113.925 ;
    RECT 0 113.995 0.070 114.205 ;
    RECT 0 114.275 0.070 114.485 ;
    RECT 0 114.555 0.070 114.765 ;
    RECT 0 114.835 0.070 115.045 ;
    RECT 0 115.115 0.070 115.325 ;
    RECT 0 115.395 0.070 115.605 ;
    RECT 0 115.675 0.070 115.885 ;
    RECT 0 115.955 0.070 116.165 ;
    RECT 0 116.235 0.070 116.445 ;
    RECT 0 116.515 0.070 116.725 ;
    RECT 0 116.795 0.070 117.005 ;
    RECT 0 117.075 0.070 117.285 ;
    RECT 0 117.355 0.070 117.565 ;
    RECT 0 117.635 0.070 117.845 ;
    RECT 0 117.915 0.070 118.125 ;
    RECT 0 118.195 0.070 118.405 ;
    RECT 0 118.475 0.070 118.685 ;
    RECT 0 118.755 0.070 118.965 ;
    RECT 0 119.035 0.070 119.245 ;
    RECT 0 119.315 0.070 119.525 ;
    RECT 0 119.595 0.070 119.805 ;
    RECT 0 119.875 0.070 120.085 ;
    RECT 0 120.155 0.070 120.365 ;
    RECT 0 120.435 0.070 120.645 ;
    RECT 0 120.715 0.070 120.925 ;
    RECT 0 120.995 0.070 121.205 ;
    RECT 0 121.275 0.070 121.485 ;
    RECT 0 121.555 0.070 121.765 ;
    RECT 0 121.835 0.070 122.045 ;
    RECT 0 122.115 0.070 122.325 ;
    RECT 0 122.395 0.070 122.605 ;
    RECT 0 122.675 0.070 122.885 ;
    RECT 0 122.955 0.070 123.165 ;
    RECT 0 123.235 0.070 123.445 ;
    RECT 0 123.515 0.070 123.725 ;
    RECT 0 123.795 0.070 124.005 ;
    RECT 0 124.075 0.070 124.285 ;
    RECT 0 124.355 0.070 124.565 ;
    RECT 0 124.635 0.070 124.845 ;
    RECT 0 124.915 0.070 125.125 ;
    RECT 0 125.195 0.070 125.405 ;
    RECT 0 125.475 0.070 125.685 ;
    RECT 0 125.755 0.070 125.965 ;
    RECT 0 126.035 0.070 126.245 ;
    RECT 0 126.315 0.070 126.525 ;
    RECT 0 126.595 0.070 126.805 ;
    RECT 0 126.875 0.070 127.085 ;
    RECT 0 127.155 0.070 127.365 ;
    RECT 0 127.435 0.070 127.645 ;
    RECT 0 127.715 0.070 127.925 ;
    RECT 0 127.995 0.070 128.205 ;
    RECT 0 128.275 0.070 128.485 ;
    RECT 0 128.555 0.070 128.765 ;
    RECT 0 128.835 0.070 129.045 ;
    RECT 0 129.115 0.070 129.325 ;
    RECT 0 129.395 0.070 129.605 ;
    RECT 0 129.675 0.070 129.885 ;
    RECT 0 129.955 0.070 130.165 ;
    RECT 0 130.235 0.070 130.445 ;
    RECT 0 130.515 0.070 130.725 ;
    RECT 0 130.795 0.070 131.005 ;
    RECT 0 131.075 0.070 131.285 ;
    RECT 0 131.355 0.070 131.565 ;
    RECT 0 131.635 0.070 131.845 ;
    RECT 0 131.915 0.070 132.125 ;
    RECT 0 132.195 0.070 132.405 ;
    RECT 0 132.475 0.070 132.685 ;
    RECT 0 132.755 0.070 132.965 ;
    RECT 0 133.035 0.070 133.245 ;
    RECT 0 133.315 0.070 133.525 ;
    RECT 0 133.595 0.070 133.805 ;
    RECT 0 133.875 0.070 134.085 ;
    RECT 0 134.155 0.070 134.365 ;
    RECT 0 134.435 0.070 134.645 ;
    RECT 0 134.715 0.070 134.925 ;
    RECT 0 134.995 0.070 135.205 ;
    RECT 0 135.275 0.070 135.485 ;
    RECT 0 135.555 0.070 135.765 ;
    RECT 0 135.835 0.070 136.045 ;
    RECT 0 136.115 0.070 136.325 ;
    RECT 0 136.395 0.070 136.605 ;
    RECT 0 136.675 0.070 136.885 ;
    RECT 0 136.955 0.070 137.165 ;
    RECT 0 137.235 0.070 137.445 ;
    RECT 0 137.515 0.070 137.725 ;
    RECT 0 137.795 0.070 138.005 ;
    RECT 0 138.075 0.070 138.285 ;
    RECT 0 138.355 0.070 138.565 ;
    RECT 0 138.635 0.070 138.845 ;
    RECT 0 138.915 0.070 139.125 ;
    RECT 0 139.195 0.070 139.405 ;
    RECT 0 139.475 0.070 139.685 ;
    RECT 0 139.755 0.070 139.965 ;
    RECT 0 140.035 0.070 140.245 ;
    RECT 0 140.315 0.070 140.525 ;
    RECT 0 140.595 0.070 140.805 ;
    RECT 0 140.875 0.070 141.085 ;
    RECT 0 141.155 0.070 141.365 ;
    RECT 0 141.435 0.070 141.645 ;
    RECT 0 141.715 0.070 141.925 ;
    RECT 0 141.995 0.070 142.205 ;
    RECT 0 142.275 0.070 142.485 ;
    RECT 0 142.555 0.070 142.765 ;
    RECT 0 142.835 0.070 143.045 ;
    RECT 0 143.115 0.070 143.325 ;
    RECT 0 143.395 0.070 143.605 ;
    RECT 0 143.675 0.070 143.885 ;
    RECT 0 143.955 0.070 144.165 ;
    RECT 0 144.235 0.070 144.445 ;
    RECT 0 144.515 0.070 181.405 ;
    RECT 0 181.475 0.070 181.685 ;
    RECT 0 181.755 0.070 181.965 ;
    RECT 0 182.035 0.070 182.245 ;
    RECT 0 182.315 0.070 182.525 ;
    RECT 0 182.595 0.070 182.805 ;
    RECT 0 182.875 0.070 183.085 ;
    RECT 0 183.155 0.070 183.365 ;
    RECT 0 183.435 0.070 183.645 ;
    RECT 0 183.715 0.070 183.925 ;
    RECT 0 183.995 0.070 184.205 ;
    RECT 0 184.275 0.070 184.485 ;
    RECT 0 184.555 0.070 184.765 ;
    RECT 0 184.835 0.070 185.045 ;
    RECT 0 185.115 0.070 185.325 ;
    RECT 0 185.395 0.070 185.605 ;
    RECT 0 185.675 0.070 185.885 ;
    RECT 0 185.955 0.070 186.165 ;
    RECT 0 186.235 0.070 186.445 ;
    RECT 0 186.515 0.070 186.725 ;
    RECT 0 186.795 0.070 187.005 ;
    RECT 0 187.075 0.070 187.285 ;
    RECT 0 187.355 0.070 187.565 ;
    RECT 0 187.635 0.070 187.845 ;
    RECT 0 187.915 0.070 188.125 ;
    RECT 0 188.195 0.070 188.405 ;
    RECT 0 188.475 0.070 188.685 ;
    RECT 0 188.755 0.070 188.965 ;
    RECT 0 189.035 0.070 189.245 ;
    RECT 0 189.315 0.070 189.525 ;
    RECT 0 189.595 0.070 189.805 ;
    RECT 0 189.875 0.070 190.085 ;
    RECT 0 190.155 0.070 190.365 ;
    RECT 0 190.435 0.070 190.645 ;
    RECT 0 190.715 0.070 190.925 ;
    RECT 0 190.995 0.070 191.205 ;
    RECT 0 191.275 0.070 191.485 ;
    RECT 0 191.555 0.070 191.765 ;
    RECT 0 191.835 0.070 192.045 ;
    RECT 0 192.115 0.070 192.325 ;
    RECT 0 192.395 0.070 192.605 ;
    RECT 0 192.675 0.070 192.885 ;
    RECT 0 192.955 0.070 193.165 ;
    RECT 0 193.235 0.070 193.445 ;
    RECT 0 193.515 0.070 193.725 ;
    RECT 0 193.795 0.070 194.005 ;
    RECT 0 194.075 0.070 194.285 ;
    RECT 0 194.355 0.070 194.565 ;
    RECT 0 194.635 0.070 194.845 ;
    RECT 0 194.915 0.070 195.125 ;
    RECT 0 195.195 0.070 195.405 ;
    RECT 0 195.475 0.070 195.685 ;
    RECT 0 195.755 0.070 195.965 ;
    RECT 0 196.035 0.070 196.245 ;
    RECT 0 196.315 0.070 196.525 ;
    RECT 0 196.595 0.070 196.805 ;
    RECT 0 196.875 0.070 197.085 ;
    RECT 0 197.155 0.070 197.365 ;
    RECT 0 197.435 0.070 197.645 ;
    RECT 0 197.715 0.070 197.925 ;
    RECT 0 197.995 0.070 198.205 ;
    RECT 0 198.275 0.070 198.485 ;
    RECT 0 198.555 0.070 198.765 ;
    RECT 0 198.835 0.070 199.045 ;
    RECT 0 199.115 0.070 199.325 ;
    RECT 0 199.395 0.070 199.605 ;
    RECT 0 199.675 0.070 199.885 ;
    RECT 0 199.955 0.070 200.165 ;
    RECT 0 200.235 0.070 200.445 ;
    RECT 0 200.515 0.070 200.725 ;
    RECT 0 200.795 0.070 201.005 ;
    RECT 0 201.075 0.070 201.285 ;
    RECT 0 201.355 0.070 201.565 ;
    RECT 0 201.635 0.070 201.845 ;
    RECT 0 201.915 0.070 202.125 ;
    RECT 0 202.195 0.070 202.405 ;
    RECT 0 202.475 0.070 202.685 ;
    RECT 0 202.755 0.070 202.965 ;
    RECT 0 203.035 0.070 203.245 ;
    RECT 0 203.315 0.070 203.525 ;
    RECT 0 203.595 0.070 203.805 ;
    RECT 0 203.875 0.070 204.085 ;
    RECT 0 204.155 0.070 204.365 ;
    RECT 0 204.435 0.070 204.645 ;
    RECT 0 204.715 0.070 204.925 ;
    RECT 0 204.995 0.070 205.205 ;
    RECT 0 205.275 0.070 205.485 ;
    RECT 0 205.555 0.070 205.765 ;
    RECT 0 205.835 0.070 206.045 ;
    RECT 0 206.115 0.070 206.325 ;
    RECT 0 206.395 0.070 206.605 ;
    RECT 0 206.675 0.070 206.885 ;
    RECT 0 206.955 0.070 207.165 ;
    RECT 0 207.235 0.070 207.445 ;
    RECT 0 207.515 0.070 207.725 ;
    RECT 0 207.795 0.070 208.005 ;
    RECT 0 208.075 0.070 208.285 ;
    RECT 0 208.355 0.070 208.565 ;
    RECT 0 208.635 0.070 208.845 ;
    RECT 0 208.915 0.070 209.125 ;
    RECT 0 209.195 0.070 209.405 ;
    RECT 0 209.475 0.070 209.685 ;
    RECT 0 209.755 0.070 209.965 ;
    RECT 0 210.035 0.070 210.245 ;
    RECT 0 210.315 0.070 210.525 ;
    RECT 0 210.595 0.070 210.805 ;
    RECT 0 210.875 0.070 211.085 ;
    RECT 0 211.155 0.070 211.365 ;
    RECT 0 211.435 0.070 211.645 ;
    RECT 0 211.715 0.070 211.925 ;
    RECT 0 211.995 0.070 212.205 ;
    RECT 0 212.275 0.070 212.485 ;
    RECT 0 212.555 0.070 212.765 ;
    RECT 0 212.835 0.070 213.045 ;
    RECT 0 213.115 0.070 213.325 ;
    RECT 0 213.395 0.070 213.605 ;
    RECT 0 213.675 0.070 213.885 ;
    RECT 0 213.955 0.070 214.165 ;
    RECT 0 214.235 0.070 214.445 ;
    RECT 0 214.515 0.070 214.725 ;
    RECT 0 214.795 0.070 215.005 ;
    RECT 0 215.075 0.070 215.285 ;
    RECT 0 215.355 0.070 215.565 ;
    RECT 0 215.635 0.070 215.845 ;
    RECT 0 215.915 0.070 216.125 ;
    RECT 0 216.195 0.070 216.405 ;
    RECT 0 216.475 0.070 216.685 ;
    RECT 0 216.755 0.070 216.965 ;
    RECT 0 217.035 0.070 217.245 ;
    RECT 0 217.315 0.070 217.525 ;
    RECT 0 217.595 0.070 217.805 ;
    RECT 0 217.875 0.070 218.085 ;
    RECT 0 218.155 0.070 218.365 ;
    RECT 0 218.435 0.070 218.645 ;
    RECT 0 218.715 0.070 218.925 ;
    RECT 0 218.995 0.070 219.205 ;
    RECT 0 219.275 0.070 219.485 ;
    RECT 0 219.555 0.070 219.765 ;
    RECT 0 219.835 0.070 220.045 ;
    RECT 0 220.115 0.070 220.325 ;
    RECT 0 220.395 0.070 220.605 ;
    RECT 0 220.675 0.070 220.885 ;
    RECT 0 220.955 0.070 221.165 ;
    RECT 0 221.235 0.070 221.445 ;
    RECT 0 221.515 0.070 221.725 ;
    RECT 0 221.795 0.070 222.005 ;
    RECT 0 222.075 0.070 222.285 ;
    RECT 0 222.355 0.070 222.565 ;
    RECT 0 222.635 0.070 222.845 ;
    RECT 0 222.915 0.070 223.125 ;
    RECT 0 223.195 0.070 223.405 ;
    RECT 0 223.475 0.070 223.685 ;
    RECT 0 223.755 0.070 223.965 ;
    RECT 0 224.035 0.070 224.245 ;
    RECT 0 224.315 0.070 224.525 ;
    RECT 0 224.595 0.070 224.805 ;
    RECT 0 224.875 0.070 225.085 ;
    RECT 0 225.155 0.070 225.365 ;
    RECT 0 225.435 0.070 225.645 ;
    RECT 0 225.715 0.070 225.925 ;
    RECT 0 225.995 0.070 226.205 ;
    RECT 0 226.275 0.070 226.485 ;
    RECT 0 226.555 0.070 226.765 ;
    RECT 0 226.835 0.070 227.045 ;
    RECT 0 227.115 0.070 227.325 ;
    RECT 0 227.395 0.070 227.605 ;
    RECT 0 227.675 0.070 227.885 ;
    RECT 0 227.955 0.070 228.165 ;
    RECT 0 228.235 0.070 228.445 ;
    RECT 0 228.515 0.070 228.725 ;
    RECT 0 228.795 0.070 229.005 ;
    RECT 0 229.075 0.070 229.285 ;
    RECT 0 229.355 0.070 229.565 ;
    RECT 0 229.635 0.070 229.845 ;
    RECT 0 229.915 0.070 230.125 ;
    RECT 0 230.195 0.070 230.405 ;
    RECT 0 230.475 0.070 230.685 ;
    RECT 0 230.755 0.070 230.965 ;
    RECT 0 231.035 0.070 231.245 ;
    RECT 0 231.315 0.070 231.525 ;
    RECT 0 231.595 0.070 231.805 ;
    RECT 0 231.875 0.070 232.085 ;
    RECT 0 232.155 0.070 232.365 ;
    RECT 0 232.435 0.070 232.645 ;
    RECT 0 232.715 0.070 232.925 ;
    RECT 0 232.995 0.070 233.205 ;
    RECT 0 233.275 0.070 233.485 ;
    RECT 0 233.555 0.070 233.765 ;
    RECT 0 233.835 0.070 234.045 ;
    RECT 0 234.115 0.070 234.325 ;
    RECT 0 234.395 0.070 234.605 ;
    RECT 0 234.675 0.070 234.885 ;
    RECT 0 234.955 0.070 235.165 ;
    RECT 0 235.235 0.070 235.445 ;
    RECT 0 235.515 0.070 235.725 ;
    RECT 0 235.795 0.070 236.005 ;
    RECT 0 236.075 0.070 236.285 ;
    RECT 0 236.355 0.070 236.565 ;
    RECT 0 236.635 0.070 236.845 ;
    RECT 0 236.915 0.070 237.125 ;
    RECT 0 237.195 0.070 237.405 ;
    RECT 0 237.475 0.070 237.685 ;
    RECT 0 237.755 0.070 237.965 ;
    RECT 0 238.035 0.070 238.245 ;
    RECT 0 238.315 0.070 238.525 ;
    RECT 0 238.595 0.070 238.805 ;
    RECT 0 238.875 0.070 239.085 ;
    RECT 0 239.155 0.070 239.365 ;
    RECT 0 239.435 0.070 239.645 ;
    RECT 0 239.715 0.070 239.925 ;
    RECT 0 239.995 0.070 240.205 ;
    RECT 0 240.275 0.070 240.485 ;
    RECT 0 240.555 0.070 240.765 ;
    RECT 0 240.835 0.070 241.045 ;
    RECT 0 241.115 0.070 241.325 ;
    RECT 0 241.395 0.070 241.605 ;
    RECT 0 241.675 0.070 241.885 ;
    RECT 0 241.955 0.070 242.165 ;
    RECT 0 242.235 0.070 242.445 ;
    RECT 0 242.515 0.070 242.725 ;
    RECT 0 242.795 0.070 243.005 ;
    RECT 0 243.075 0.070 243.285 ;
    RECT 0 243.355 0.070 243.565 ;
    RECT 0 243.635 0.070 243.845 ;
    RECT 0 243.915 0.070 244.125 ;
    RECT 0 244.195 0.070 244.405 ;
    RECT 0 244.475 0.070 244.685 ;
    RECT 0 244.755 0.070 244.965 ;
    RECT 0 245.035 0.070 245.245 ;
    RECT 0 245.315 0.070 245.525 ;
    RECT 0 245.595 0.070 245.805 ;
    RECT 0 245.875 0.070 246.085 ;
    RECT 0 246.155 0.070 246.365 ;
    RECT 0 246.435 0.070 246.645 ;
    RECT 0 246.715 0.070 246.925 ;
    RECT 0 246.995 0.070 247.205 ;
    RECT 0 247.275 0.070 247.485 ;
    RECT 0 247.555 0.070 247.765 ;
    RECT 0 247.835 0.070 248.045 ;
    RECT 0 248.115 0.070 248.325 ;
    RECT 0 248.395 0.070 248.605 ;
    RECT 0 248.675 0.070 248.885 ;
    RECT 0 248.955 0.070 249.165 ;
    RECT 0 249.235 0.070 249.445 ;
    RECT 0 249.515 0.070 249.725 ;
    RECT 0 249.795 0.070 250.005 ;
    RECT 0 250.075 0.070 250.285 ;
    RECT 0 250.355 0.070 250.565 ;
    RECT 0 250.635 0.070 250.845 ;
    RECT 0 250.915 0.070 251.125 ;
    RECT 0 251.195 0.070 251.405 ;
    RECT 0 251.475 0.070 251.685 ;
    RECT 0 251.755 0.070 251.965 ;
    RECT 0 252.035 0.070 252.245 ;
    RECT 0 252.315 0.070 252.525 ;
    RECT 0 252.595 0.070 252.805 ;
    RECT 0 252.875 0.070 253.085 ;
    RECT 0 253.155 0.070 253.365 ;
    RECT 0 253.435 0.070 253.645 ;
    RECT 0 253.715 0.070 253.925 ;
    RECT 0 253.995 0.070 254.205 ;
    RECT 0 254.275 0.070 254.485 ;
    RECT 0 254.555 0.070 254.765 ;
    RECT 0 254.835 0.070 255.045 ;
    RECT 0 255.115 0.070 255.325 ;
    RECT 0 255.395 0.070 255.605 ;
    RECT 0 255.675 0.070 255.885 ;
    RECT 0 255.955 0.070 256.165 ;
    RECT 0 256.235 0.070 256.445 ;
    RECT 0 256.515 0.070 256.725 ;
    RECT 0 256.795 0.070 257.005 ;
    RECT 0 257.075 0.070 257.285 ;
    RECT 0 257.355 0.070 257.565 ;
    RECT 0 257.635 0.070 257.845 ;
    RECT 0 257.915 0.070 258.125 ;
    RECT 0 258.195 0.070 258.405 ;
    RECT 0 258.475 0.070 258.685 ;
    RECT 0 258.755 0.070 258.965 ;
    RECT 0 259.035 0.070 259.245 ;
    RECT 0 259.315 0.070 259.525 ;
    RECT 0 259.595 0.070 259.805 ;
    RECT 0 259.875 0.070 260.085 ;
    RECT 0 260.155 0.070 260.365 ;
    RECT 0 260.435 0.070 260.645 ;
    RECT 0 260.715 0.070 260.925 ;
    RECT 0 260.995 0.070 261.205 ;
    RECT 0 261.275 0.070 261.485 ;
    RECT 0 261.555 0.070 261.765 ;
    RECT 0 261.835 0.070 262.045 ;
    RECT 0 262.115 0.070 262.325 ;
    RECT 0 262.395 0.070 262.605 ;
    RECT 0 262.675 0.070 262.885 ;
    RECT 0 262.955 0.070 263.165 ;
    RECT 0 263.235 0.070 263.445 ;
    RECT 0 263.515 0.070 263.725 ;
    RECT 0 263.795 0.070 264.005 ;
    RECT 0 264.075 0.070 264.285 ;
    RECT 0 264.355 0.070 264.565 ;
    RECT 0 264.635 0.070 264.845 ;
    RECT 0 264.915 0.070 265.125 ;
    RECT 0 265.195 0.070 265.405 ;
    RECT 0 265.475 0.070 265.685 ;
    RECT 0 265.755 0.070 265.965 ;
    RECT 0 266.035 0.070 266.245 ;
    RECT 0 266.315 0.070 266.525 ;
    RECT 0 266.595 0.070 266.805 ;
    RECT 0 266.875 0.070 267.085 ;
    RECT 0 267.155 0.070 267.365 ;
    RECT 0 267.435 0.070 267.645 ;
    RECT 0 267.715 0.070 267.925 ;
    RECT 0 267.995 0.070 268.205 ;
    RECT 0 268.275 0.070 268.485 ;
    RECT 0 268.555 0.070 268.765 ;
    RECT 0 268.835 0.070 269.045 ;
    RECT 0 269.115 0.070 269.325 ;
    RECT 0 269.395 0.070 269.605 ;
    RECT 0 269.675 0.070 269.885 ;
    RECT 0 269.955 0.070 270.165 ;
    RECT 0 270.235 0.070 270.445 ;
    RECT 0 270.515 0.070 270.725 ;
    RECT 0 270.795 0.070 271.005 ;
    RECT 0 271.075 0.070 271.285 ;
    RECT 0 271.355 0.070 271.565 ;
    RECT 0 271.635 0.070 271.845 ;
    RECT 0 271.915 0.070 272.125 ;
    RECT 0 272.195 0.070 272.405 ;
    RECT 0 272.475 0.070 272.685 ;
    RECT 0 272.755 0.070 272.965 ;
    RECT 0 273.035 0.070 273.245 ;
    RECT 0 273.315 0.070 273.525 ;
    RECT 0 273.595 0.070 273.805 ;
    RECT 0 273.875 0.070 274.085 ;
    RECT 0 274.155 0.070 274.365 ;
    RECT 0 274.435 0.070 274.645 ;
    RECT 0 274.715 0.070 274.925 ;
    RECT 0 274.995 0.070 275.205 ;
    RECT 0 275.275 0.070 275.485 ;
    RECT 0 275.555 0.070 275.765 ;
    RECT 0 275.835 0.070 276.045 ;
    RECT 0 276.115 0.070 276.325 ;
    RECT 0 276.395 0.070 276.605 ;
    RECT 0 276.675 0.070 276.885 ;
    RECT 0 276.955 0.070 277.165 ;
    RECT 0 277.235 0.070 277.445 ;
    RECT 0 277.515 0.070 277.725 ;
    RECT 0 277.795 0.070 278.005 ;
    RECT 0 278.075 0.070 278.285 ;
    RECT 0 278.355 0.070 278.565 ;
    RECT 0 278.635 0.070 278.845 ;
    RECT 0 278.915 0.070 279.125 ;
    RECT 0 279.195 0.070 279.405 ;
    RECT 0 279.475 0.070 279.685 ;
    RECT 0 279.755 0.070 279.965 ;
    RECT 0 280.035 0.070 280.245 ;
    RECT 0 280.315 0.070 280.525 ;
    RECT 0 280.595 0.070 280.805 ;
    RECT 0 280.875 0.070 281.085 ;
    RECT 0 281.155 0.070 281.365 ;
    RECT 0 281.435 0.070 281.645 ;
    RECT 0 281.715 0.070 281.925 ;
    RECT 0 281.995 0.070 282.205 ;
    RECT 0 282.275 0.070 282.485 ;
    RECT 0 282.555 0.070 282.765 ;
    RECT 0 282.835 0.070 283.045 ;
    RECT 0 283.115 0.070 283.325 ;
    RECT 0 283.395 0.070 283.605 ;
    RECT 0 283.675 0.070 283.885 ;
    RECT 0 283.955 0.070 284.165 ;
    RECT 0 284.235 0.070 284.445 ;
    RECT 0 284.515 0.070 284.725 ;
    RECT 0 284.795 0.070 285.005 ;
    RECT 0 285.075 0.070 285.285 ;
    RECT 0 285.355 0.070 285.565 ;
    RECT 0 285.635 0.070 285.845 ;
    RECT 0 285.915 0.070 286.125 ;
    RECT 0 286.195 0.070 286.405 ;
    RECT 0 286.475 0.070 286.685 ;
    RECT 0 286.755 0.070 286.965 ;
    RECT 0 287.035 0.070 287.245 ;
    RECT 0 287.315 0.070 287.525 ;
    RECT 0 287.595 0.070 287.805 ;
    RECT 0 287.875 0.070 288.085 ;
    RECT 0 288.155 0.070 288.365 ;
    RECT 0 288.435 0.070 288.645 ;
    RECT 0 288.715 0.070 288.925 ;
    RECT 0 288.995 0.070 289.205 ;
    RECT 0 289.275 0.070 289.485 ;
    RECT 0 289.555 0.070 289.765 ;
    RECT 0 289.835 0.070 290.045 ;
    RECT 0 290.115 0.070 290.325 ;
    RECT 0 290.395 0.070 290.605 ;
    RECT 0 290.675 0.070 290.885 ;
    RECT 0 290.955 0.070 291.165 ;
    RECT 0 291.235 0.070 291.445 ;
    RECT 0 291.515 0.070 291.725 ;
    RECT 0 291.795 0.070 292.005 ;
    RECT 0 292.075 0.070 292.285 ;
    RECT 0 292.355 0.070 292.565 ;
    RECT 0 292.635 0.070 292.845 ;
    RECT 0 292.915 0.070 293.125 ;
    RECT 0 293.195 0.070 293.405 ;
    RECT 0 293.475 0.070 293.685 ;
    RECT 0 293.755 0.070 293.965 ;
    RECT 0 294.035 0.070 294.245 ;
    RECT 0 294.315 0.070 294.525 ;
    RECT 0 294.595 0.070 294.805 ;
    RECT 0 294.875 0.070 295.085 ;
    RECT 0 295.155 0.070 295.365 ;
    RECT 0 295.435 0.070 295.645 ;
    RECT 0 295.715 0.070 295.925 ;
    RECT 0 295.995 0.070 296.205 ;
    RECT 0 296.275 0.070 296.485 ;
    RECT 0 296.555 0.070 296.765 ;
    RECT 0 296.835 0.070 297.045 ;
    RECT 0 297.115 0.070 297.325 ;
    RECT 0 297.395 0.070 297.605 ;
    RECT 0 297.675 0.070 297.885 ;
    RECT 0 297.955 0.070 298.165 ;
    RECT 0 298.235 0.070 298.445 ;
    RECT 0 298.515 0.070 298.725 ;
    RECT 0 298.795 0.070 299.005 ;
    RECT 0 299.075 0.070 299.285 ;
    RECT 0 299.355 0.070 299.565 ;
    RECT 0 299.635 0.070 299.845 ;
    RECT 0 299.915 0.070 300.125 ;
    RECT 0 300.195 0.070 300.405 ;
    RECT 0 300.475 0.070 300.685 ;
    RECT 0 300.755 0.070 300.965 ;
    RECT 0 301.035 0.070 301.245 ;
    RECT 0 301.315 0.070 301.525 ;
    RECT 0 301.595 0.070 301.805 ;
    RECT 0 301.875 0.070 302.085 ;
    RECT 0 302.155 0.070 302.365 ;
    RECT 0 302.435 0.070 302.645 ;
    RECT 0 302.715 0.070 302.925 ;
    RECT 0 302.995 0.070 303.205 ;
    RECT 0 303.275 0.070 303.485 ;
    RECT 0 303.555 0.070 303.765 ;
    RECT 0 303.835 0.070 304.045 ;
    RECT 0 304.115 0.070 304.325 ;
    RECT 0 304.395 0.070 304.605 ;
    RECT 0 304.675 0.070 304.885 ;
    RECT 0 304.955 0.070 305.165 ;
    RECT 0 305.235 0.070 305.445 ;
    RECT 0 305.515 0.070 305.725 ;
    RECT 0 305.795 0.070 306.005 ;
    RECT 0 306.075 0.070 306.285 ;
    RECT 0 306.355 0.070 306.565 ;
    RECT 0 306.635 0.070 306.845 ;
    RECT 0 306.915 0.070 307.125 ;
    RECT 0 307.195 0.070 307.405 ;
    RECT 0 307.475 0.070 307.685 ;
    RECT 0 307.755 0.070 307.965 ;
    RECT 0 308.035 0.070 308.245 ;
    RECT 0 308.315 0.070 308.525 ;
    RECT 0 308.595 0.070 308.805 ;
    RECT 0 308.875 0.070 309.085 ;
    RECT 0 309.155 0.070 309.365 ;
    RECT 0 309.435 0.070 309.645 ;
    RECT 0 309.715 0.070 309.925 ;
    RECT 0 309.995 0.070 310.205 ;
    RECT 0 310.275 0.070 310.485 ;
    RECT 0 310.555 0.070 310.765 ;
    RECT 0 310.835 0.070 311.045 ;
    RECT 0 311.115 0.070 311.325 ;
    RECT 0 311.395 0.070 311.605 ;
    RECT 0 311.675 0.070 311.885 ;
    RECT 0 311.955 0.070 312.165 ;
    RECT 0 312.235 0.070 312.445 ;
    RECT 0 312.515 0.070 312.725 ;
    RECT 0 312.795 0.070 313.005 ;
    RECT 0 313.075 0.070 313.285 ;
    RECT 0 313.355 0.070 313.565 ;
    RECT 0 313.635 0.070 313.845 ;
    RECT 0 313.915 0.070 314.125 ;
    RECT 0 314.195 0.070 314.405 ;
    RECT 0 314.475 0.070 314.685 ;
    RECT 0 314.755 0.070 314.965 ;
    RECT 0 315.035 0.070 315.245 ;
    RECT 0 315.315 0.070 315.525 ;
    RECT 0 315.595 0.070 315.805 ;
    RECT 0 315.875 0.070 316.085 ;
    RECT 0 316.155 0.070 316.365 ;
    RECT 0 316.435 0.070 316.645 ;
    RECT 0 316.715 0.070 316.925 ;
    RECT 0 316.995 0.070 317.205 ;
    RECT 0 317.275 0.070 317.485 ;
    RECT 0 317.555 0.070 317.765 ;
    RECT 0 317.835 0.070 318.045 ;
    RECT 0 318.115 0.070 318.325 ;
    RECT 0 318.395 0.070 318.605 ;
    RECT 0 318.675 0.070 318.885 ;
    RECT 0 318.955 0.070 319.165 ;
    RECT 0 319.235 0.070 319.445 ;
    RECT 0 319.515 0.070 319.725 ;
    RECT 0 319.795 0.070 320.005 ;
    RECT 0 320.075 0.070 320.285 ;
    RECT 0 320.355 0.070 320.565 ;
    RECT 0 320.635 0.070 320.845 ;
    RECT 0 320.915 0.070 321.125 ;
    RECT 0 321.195 0.070 321.405 ;
    RECT 0 321.475 0.070 321.685 ;
    RECT 0 321.755 0.070 321.965 ;
    RECT 0 322.035 0.070 322.245 ;
    RECT 0 322.315 0.070 322.525 ;
    RECT 0 322.595 0.070 322.805 ;
    RECT 0 322.875 0.070 323.085 ;
    RECT 0 323.155 0.070 323.365 ;
    RECT 0 323.435 0.070 323.645 ;
    RECT 0 323.715 0.070 323.925 ;
    RECT 0 323.995 0.070 324.205 ;
    RECT 0 324.275 0.070 324.485 ;
    RECT 0 324.555 0.070 361.445 ;
    RECT 0 361.515 0.070 361.725 ;
    RECT 0 361.795 0.070 362.005 ;
    RECT 0 362.075 0.070 362.285 ;
    RECT 0 362.355 0.070 362.565 ;
    RECT 0 362.635 0.070 362.845 ;
    RECT 0 362.915 0.070 363.125 ;
    RECT 0 363.195 0.070 363.405 ;
    RECT 0 363.475 0.070 363.685 ;
    RECT 0 363.755 0.070 363.965 ;
    RECT 0 364.035 0.070 364.245 ;
    RECT 0 364.315 0.070 364.525 ;
    RECT 0 364.595 0.070 364.805 ;
    RECT 0 364.875 0.070 365.085 ;
    RECT 0 365.155 0.070 365.365 ;
    RECT 0 365.435 0.070 365.645 ;
    RECT 0 365.715 0.070 365.925 ;
    RECT 0 365.995 0.070 366.205 ;
    RECT 0 366.275 0.070 366.485 ;
    RECT 0 366.555 0.070 366.765 ;
    RECT 0 366.835 0.070 367.045 ;
    RECT 0 367.115 0.070 367.325 ;
    RECT 0 367.395 0.070 367.605 ;
    RECT 0 367.675 0.070 367.885 ;
    RECT 0 367.955 0.070 368.165 ;
    RECT 0 368.235 0.070 368.445 ;
    RECT 0 368.515 0.070 368.725 ;
    RECT 0 368.795 0.070 369.005 ;
    RECT 0 369.075 0.070 369.285 ;
    RECT 0 369.355 0.070 369.565 ;
    RECT 0 369.635 0.070 369.845 ;
    RECT 0 369.915 0.070 370.125 ;
    RECT 0 370.195 0.070 370.405 ;
    RECT 0 370.475 0.070 370.685 ;
    RECT 0 370.755 0.070 370.965 ;
    RECT 0 371.035 0.070 371.245 ;
    RECT 0 371.315 0.070 371.525 ;
    RECT 0 371.595 0.070 371.805 ;
    RECT 0 371.875 0.070 372.085 ;
    RECT 0 372.155 0.070 372.365 ;
    RECT 0 372.435 0.070 372.645 ;
    RECT 0 372.715 0.070 372.925 ;
    RECT 0 372.995 0.070 373.205 ;
    RECT 0 373.275 0.070 373.485 ;
    RECT 0 373.555 0.070 373.765 ;
    RECT 0 373.835 0.070 374.045 ;
    RECT 0 374.115 0.070 374.325 ;
    RECT 0 374.395 0.070 374.605 ;
    RECT 0 374.675 0.070 374.885 ;
    RECT 0 374.955 0.070 375.165 ;
    RECT 0 375.235 0.070 375.445 ;
    RECT 0 375.515 0.070 375.725 ;
    RECT 0 375.795 0.070 376.005 ;
    RECT 0 376.075 0.070 376.285 ;
    RECT 0 376.355 0.070 376.565 ;
    RECT 0 376.635 0.070 376.845 ;
    RECT 0 376.915 0.070 377.125 ;
    RECT 0 377.195 0.070 377.405 ;
    RECT 0 377.475 0.070 377.685 ;
    RECT 0 377.755 0.070 377.965 ;
    RECT 0 378.035 0.070 378.245 ;
    RECT 0 378.315 0.070 378.525 ;
    RECT 0 378.595 0.070 378.805 ;
    RECT 0 378.875 0.070 379.085 ;
    RECT 0 379.155 0.070 379.365 ;
    RECT 0 379.435 0.070 379.645 ;
    RECT 0 379.715 0.070 379.925 ;
    RECT 0 379.995 0.070 380.205 ;
    RECT 0 380.275 0.070 380.485 ;
    RECT 0 380.555 0.070 380.765 ;
    RECT 0 380.835 0.070 381.045 ;
    RECT 0 381.115 0.070 381.325 ;
    RECT 0 381.395 0.070 381.605 ;
    RECT 0 381.675 0.070 381.885 ;
    RECT 0 381.955 0.070 382.165 ;
    RECT 0 382.235 0.070 382.445 ;
    RECT 0 382.515 0.070 382.725 ;
    RECT 0 382.795 0.070 383.005 ;
    RECT 0 383.075 0.070 383.285 ;
    RECT 0 383.355 0.070 383.565 ;
    RECT 0 383.635 0.070 383.845 ;
    RECT 0 383.915 0.070 384.125 ;
    RECT 0 384.195 0.070 384.405 ;
    RECT 0 384.475 0.070 384.685 ;
    RECT 0 384.755 0.070 384.965 ;
    RECT 0 385.035 0.070 385.245 ;
    RECT 0 385.315 0.070 385.525 ;
    RECT 0 385.595 0.070 385.805 ;
    RECT 0 385.875 0.070 386.085 ;
    RECT 0 386.155 0.070 386.365 ;
    RECT 0 386.435 0.070 386.645 ;
    RECT 0 386.715 0.070 386.925 ;
    RECT 0 386.995 0.070 387.205 ;
    RECT 0 387.275 0.070 387.485 ;
    RECT 0 387.555 0.070 387.765 ;
    RECT 0 387.835 0.070 388.045 ;
    RECT 0 388.115 0.070 388.325 ;
    RECT 0 388.395 0.070 388.605 ;
    RECT 0 388.675 0.070 388.885 ;
    RECT 0 388.955 0.070 389.165 ;
    RECT 0 389.235 0.070 389.445 ;
    RECT 0 389.515 0.070 389.725 ;
    RECT 0 389.795 0.070 390.005 ;
    RECT 0 390.075 0.070 390.285 ;
    RECT 0 390.355 0.070 390.565 ;
    RECT 0 390.635 0.070 390.845 ;
    RECT 0 390.915 0.070 391.125 ;
    RECT 0 391.195 0.070 391.405 ;
    RECT 0 391.475 0.070 391.685 ;
    RECT 0 391.755 0.070 391.965 ;
    RECT 0 392.035 0.070 392.245 ;
    RECT 0 392.315 0.070 392.525 ;
    RECT 0 392.595 0.070 392.805 ;
    RECT 0 392.875 0.070 393.085 ;
    RECT 0 393.155 0.070 393.365 ;
    RECT 0 393.435 0.070 393.645 ;
    RECT 0 393.715 0.070 393.925 ;
    RECT 0 393.995 0.070 394.205 ;
    RECT 0 394.275 0.070 394.485 ;
    RECT 0 394.555 0.070 394.765 ;
    RECT 0 394.835 0.070 395.045 ;
    RECT 0 395.115 0.070 395.325 ;
    RECT 0 395.395 0.070 395.605 ;
    RECT 0 395.675 0.070 395.885 ;
    RECT 0 395.955 0.070 396.165 ;
    RECT 0 396.235 0.070 396.445 ;
    RECT 0 396.515 0.070 396.725 ;
    RECT 0 396.795 0.070 397.005 ;
    RECT 0 397.075 0.070 397.285 ;
    RECT 0 397.355 0.070 397.565 ;
    RECT 0 397.635 0.070 397.845 ;
    RECT 0 397.915 0.070 398.125 ;
    RECT 0 398.195 0.070 398.405 ;
    RECT 0 398.475 0.070 398.685 ;
    RECT 0 398.755 0.070 398.965 ;
    RECT 0 399.035 0.070 399.245 ;
    RECT 0 399.315 0.070 399.525 ;
    RECT 0 399.595 0.070 399.805 ;
    RECT 0 399.875 0.070 400.085 ;
    RECT 0 400.155 0.070 400.365 ;
    RECT 0 400.435 0.070 400.645 ;
    RECT 0 400.715 0.070 400.925 ;
    RECT 0 400.995 0.070 401.205 ;
    RECT 0 401.275 0.070 401.485 ;
    RECT 0 401.555 0.070 401.765 ;
    RECT 0 401.835 0.070 402.045 ;
    RECT 0 402.115 0.070 402.325 ;
    RECT 0 402.395 0.070 402.605 ;
    RECT 0 402.675 0.070 402.885 ;
    RECT 0 402.955 0.070 403.165 ;
    RECT 0 403.235 0.070 403.445 ;
    RECT 0 403.515 0.070 403.725 ;
    RECT 0 403.795 0.070 404.005 ;
    RECT 0 404.075 0.070 404.285 ;
    RECT 0 404.355 0.070 404.565 ;
    RECT 0 404.635 0.070 404.845 ;
    RECT 0 404.915 0.070 405.125 ;
    RECT 0 405.195 0.070 405.405 ;
    RECT 0 405.475 0.070 405.685 ;
    RECT 0 405.755 0.070 405.965 ;
    RECT 0 406.035 0.070 406.245 ;
    RECT 0 406.315 0.070 406.525 ;
    RECT 0 406.595 0.070 406.805 ;
    RECT 0 406.875 0.070 407.085 ;
    RECT 0 407.155 0.070 407.365 ;
    RECT 0 407.435 0.070 407.645 ;
    RECT 0 407.715 0.070 407.925 ;
    RECT 0 407.995 0.070 408.205 ;
    RECT 0 408.275 0.070 408.485 ;
    RECT 0 408.555 0.070 408.765 ;
    RECT 0 408.835 0.070 409.045 ;
    RECT 0 409.115 0.070 409.325 ;
    RECT 0 409.395 0.070 409.605 ;
    RECT 0 409.675 0.070 409.885 ;
    RECT 0 409.955 0.070 410.165 ;
    RECT 0 410.235 0.070 410.445 ;
    RECT 0 410.515 0.070 410.725 ;
    RECT 0 410.795 0.070 411.005 ;
    RECT 0 411.075 0.070 411.285 ;
    RECT 0 411.355 0.070 411.565 ;
    RECT 0 411.635 0.070 411.845 ;
    RECT 0 411.915 0.070 412.125 ;
    RECT 0 412.195 0.070 412.405 ;
    RECT 0 412.475 0.070 412.685 ;
    RECT 0 412.755 0.070 412.965 ;
    RECT 0 413.035 0.070 413.245 ;
    RECT 0 413.315 0.070 413.525 ;
    RECT 0 413.595 0.070 413.805 ;
    RECT 0 413.875 0.070 414.085 ;
    RECT 0 414.155 0.070 414.365 ;
    RECT 0 414.435 0.070 414.645 ;
    RECT 0 414.715 0.070 414.925 ;
    RECT 0 414.995 0.070 415.205 ;
    RECT 0 415.275 0.070 415.485 ;
    RECT 0 415.555 0.070 415.765 ;
    RECT 0 415.835 0.070 416.045 ;
    RECT 0 416.115 0.070 416.325 ;
    RECT 0 416.395 0.070 416.605 ;
    RECT 0 416.675 0.070 416.885 ;
    RECT 0 416.955 0.070 417.165 ;
    RECT 0 417.235 0.070 417.445 ;
    RECT 0 417.515 0.070 417.725 ;
    RECT 0 417.795 0.070 418.005 ;
    RECT 0 418.075 0.070 418.285 ;
    RECT 0 418.355 0.070 418.565 ;
    RECT 0 418.635 0.070 418.845 ;
    RECT 0 418.915 0.070 419.125 ;
    RECT 0 419.195 0.070 419.405 ;
    RECT 0 419.475 0.070 419.685 ;
    RECT 0 419.755 0.070 419.965 ;
    RECT 0 420.035 0.070 420.245 ;
    RECT 0 420.315 0.070 420.525 ;
    RECT 0 420.595 0.070 420.805 ;
    RECT 0 420.875 0.070 421.085 ;
    RECT 0 421.155 0.070 421.365 ;
    RECT 0 421.435 0.070 421.645 ;
    RECT 0 421.715 0.070 421.925 ;
    RECT 0 421.995 0.070 422.205 ;
    RECT 0 422.275 0.070 422.485 ;
    RECT 0 422.555 0.070 422.765 ;
    RECT 0 422.835 0.070 423.045 ;
    RECT 0 423.115 0.070 423.325 ;
    RECT 0 423.395 0.070 423.605 ;
    RECT 0 423.675 0.070 423.885 ;
    RECT 0 423.955 0.070 424.165 ;
    RECT 0 424.235 0.070 424.445 ;
    RECT 0 424.515 0.070 424.725 ;
    RECT 0 424.795 0.070 425.005 ;
    RECT 0 425.075 0.070 425.285 ;
    RECT 0 425.355 0.070 425.565 ;
    RECT 0 425.635 0.070 425.845 ;
    RECT 0 425.915 0.070 426.125 ;
    RECT 0 426.195 0.070 426.405 ;
    RECT 0 426.475 0.070 426.685 ;
    RECT 0 426.755 0.070 426.965 ;
    RECT 0 427.035 0.070 427.245 ;
    RECT 0 427.315 0.070 427.525 ;
    RECT 0 427.595 0.070 427.805 ;
    RECT 0 427.875 0.070 428.085 ;
    RECT 0 428.155 0.070 428.365 ;
    RECT 0 428.435 0.070 428.645 ;
    RECT 0 428.715 0.070 428.925 ;
    RECT 0 428.995 0.070 429.205 ;
    RECT 0 429.275 0.070 429.485 ;
    RECT 0 429.555 0.070 429.765 ;
    RECT 0 429.835 0.070 430.045 ;
    RECT 0 430.115 0.070 430.325 ;
    RECT 0 430.395 0.070 430.605 ;
    RECT 0 430.675 0.070 430.885 ;
    RECT 0 430.955 0.070 431.165 ;
    RECT 0 431.235 0.070 431.445 ;
    RECT 0 431.515 0.070 431.725 ;
    RECT 0 431.795 0.070 432.005 ;
    RECT 0 432.075 0.070 432.285 ;
    RECT 0 432.355 0.070 432.565 ;
    RECT 0 432.635 0.070 432.845 ;
    RECT 0 432.915 0.070 433.125 ;
    RECT 0 433.195 0.070 433.405 ;
    RECT 0 433.475 0.070 433.685 ;
    RECT 0 433.755 0.070 433.965 ;
    RECT 0 434.035 0.070 434.245 ;
    RECT 0 434.315 0.070 434.525 ;
    RECT 0 434.595 0.070 434.805 ;
    RECT 0 434.875 0.070 435.085 ;
    RECT 0 435.155 0.070 435.365 ;
    RECT 0 435.435 0.070 435.645 ;
    RECT 0 435.715 0.070 435.925 ;
    RECT 0 435.995 0.070 436.205 ;
    RECT 0 436.275 0.070 436.485 ;
    RECT 0 436.555 0.070 436.765 ;
    RECT 0 436.835 0.070 437.045 ;
    RECT 0 437.115 0.070 437.325 ;
    RECT 0 437.395 0.070 437.605 ;
    RECT 0 437.675 0.070 437.885 ;
    RECT 0 437.955 0.070 438.165 ;
    RECT 0 438.235 0.070 438.445 ;
    RECT 0 438.515 0.070 438.725 ;
    RECT 0 438.795 0.070 439.005 ;
    RECT 0 439.075 0.070 439.285 ;
    RECT 0 439.355 0.070 439.565 ;
    RECT 0 439.635 0.070 439.845 ;
    RECT 0 439.915 0.070 440.125 ;
    RECT 0 440.195 0.070 440.405 ;
    RECT 0 440.475 0.070 440.685 ;
    RECT 0 440.755 0.070 440.965 ;
    RECT 0 441.035 0.070 441.245 ;
    RECT 0 441.315 0.070 441.525 ;
    RECT 0 441.595 0.070 441.805 ;
    RECT 0 441.875 0.070 442.085 ;
    RECT 0 442.155 0.070 442.365 ;
    RECT 0 442.435 0.070 442.645 ;
    RECT 0 442.715 0.070 442.925 ;
    RECT 0 442.995 0.070 443.205 ;
    RECT 0 443.275 0.070 443.485 ;
    RECT 0 443.555 0.070 443.765 ;
    RECT 0 443.835 0.070 444.045 ;
    RECT 0 444.115 0.070 444.325 ;
    RECT 0 444.395 0.070 444.605 ;
    RECT 0 444.675 0.070 444.885 ;
    RECT 0 444.955 0.070 445.165 ;
    RECT 0 445.235 0.070 445.445 ;
    RECT 0 445.515 0.070 445.725 ;
    RECT 0 445.795 0.070 446.005 ;
    RECT 0 446.075 0.070 446.285 ;
    RECT 0 446.355 0.070 446.565 ;
    RECT 0 446.635 0.070 446.845 ;
    RECT 0 446.915 0.070 447.125 ;
    RECT 0 447.195 0.070 447.405 ;
    RECT 0 447.475 0.070 447.685 ;
    RECT 0 447.755 0.070 447.965 ;
    RECT 0 448.035 0.070 448.245 ;
    RECT 0 448.315 0.070 448.525 ;
    RECT 0 448.595 0.070 448.805 ;
    RECT 0 448.875 0.070 449.085 ;
    RECT 0 449.155 0.070 449.365 ;
    RECT 0 449.435 0.070 449.645 ;
    RECT 0 449.715 0.070 449.925 ;
    RECT 0 449.995 0.070 450.205 ;
    RECT 0 450.275 0.070 450.485 ;
    RECT 0 450.555 0.070 450.765 ;
    RECT 0 450.835 0.070 451.045 ;
    RECT 0 451.115 0.070 451.325 ;
    RECT 0 451.395 0.070 451.605 ;
    RECT 0 451.675 0.070 451.885 ;
    RECT 0 451.955 0.070 452.165 ;
    RECT 0 452.235 0.070 452.445 ;
    RECT 0 452.515 0.070 452.725 ;
    RECT 0 452.795 0.070 453.005 ;
    RECT 0 453.075 0.070 453.285 ;
    RECT 0 453.355 0.070 453.565 ;
    RECT 0 453.635 0.070 453.845 ;
    RECT 0 453.915 0.070 454.125 ;
    RECT 0 454.195 0.070 454.405 ;
    RECT 0 454.475 0.070 454.685 ;
    RECT 0 454.755 0.070 454.965 ;
    RECT 0 455.035 0.070 455.245 ;
    RECT 0 455.315 0.070 455.525 ;
    RECT 0 455.595 0.070 455.805 ;
    RECT 0 455.875 0.070 456.085 ;
    RECT 0 456.155 0.070 456.365 ;
    RECT 0 456.435 0.070 456.645 ;
    RECT 0 456.715 0.070 456.925 ;
    RECT 0 456.995 0.070 457.205 ;
    RECT 0 457.275 0.070 457.485 ;
    RECT 0 457.555 0.070 457.765 ;
    RECT 0 457.835 0.070 458.045 ;
    RECT 0 458.115 0.070 458.325 ;
    RECT 0 458.395 0.070 458.605 ;
    RECT 0 458.675 0.070 458.885 ;
    RECT 0 458.955 0.070 459.165 ;
    RECT 0 459.235 0.070 459.445 ;
    RECT 0 459.515 0.070 459.725 ;
    RECT 0 459.795 0.070 460.005 ;
    RECT 0 460.075 0.070 460.285 ;
    RECT 0 460.355 0.070 460.565 ;
    RECT 0 460.635 0.070 460.845 ;
    RECT 0 460.915 0.070 461.125 ;
    RECT 0 461.195 0.070 461.405 ;
    RECT 0 461.475 0.070 461.685 ;
    RECT 0 461.755 0.070 461.965 ;
    RECT 0 462.035 0.070 462.245 ;
    RECT 0 462.315 0.070 462.525 ;
    RECT 0 462.595 0.070 462.805 ;
    RECT 0 462.875 0.070 463.085 ;
    RECT 0 463.155 0.070 463.365 ;
    RECT 0 463.435 0.070 463.645 ;
    RECT 0 463.715 0.070 463.925 ;
    RECT 0 463.995 0.070 464.205 ;
    RECT 0 464.275 0.070 464.485 ;
    RECT 0 464.555 0.070 464.765 ;
    RECT 0 464.835 0.070 465.045 ;
    RECT 0 465.115 0.070 465.325 ;
    RECT 0 465.395 0.070 465.605 ;
    RECT 0 465.675 0.070 465.885 ;
    RECT 0 465.955 0.070 466.165 ;
    RECT 0 466.235 0.070 466.445 ;
    RECT 0 466.515 0.070 466.725 ;
    RECT 0 466.795 0.070 467.005 ;
    RECT 0 467.075 0.070 467.285 ;
    RECT 0 467.355 0.070 467.565 ;
    RECT 0 467.635 0.070 467.845 ;
    RECT 0 467.915 0.070 468.125 ;
    RECT 0 468.195 0.070 468.405 ;
    RECT 0 468.475 0.070 468.685 ;
    RECT 0 468.755 0.070 468.965 ;
    RECT 0 469.035 0.070 469.245 ;
    RECT 0 469.315 0.070 469.525 ;
    RECT 0 469.595 0.070 469.805 ;
    RECT 0 469.875 0.070 470.085 ;
    RECT 0 470.155 0.070 470.365 ;
    RECT 0 470.435 0.070 470.645 ;
    RECT 0 470.715 0.070 470.925 ;
    RECT 0 470.995 0.070 471.205 ;
    RECT 0 471.275 0.070 471.485 ;
    RECT 0 471.555 0.070 471.765 ;
    RECT 0 471.835 0.070 472.045 ;
    RECT 0 472.115 0.070 472.325 ;
    RECT 0 472.395 0.070 472.605 ;
    RECT 0 472.675 0.070 472.885 ;
    RECT 0 472.955 0.070 473.165 ;
    RECT 0 473.235 0.070 473.445 ;
    RECT 0 473.515 0.070 473.725 ;
    RECT 0 473.795 0.070 474.005 ;
    RECT 0 474.075 0.070 474.285 ;
    RECT 0 474.355 0.070 474.565 ;
    RECT 0 474.635 0.070 474.845 ;
    RECT 0 474.915 0.070 475.125 ;
    RECT 0 475.195 0.070 475.405 ;
    RECT 0 475.475 0.070 475.685 ;
    RECT 0 475.755 0.070 475.965 ;
    RECT 0 476.035 0.070 476.245 ;
    RECT 0 476.315 0.070 476.525 ;
    RECT 0 476.595 0.070 476.805 ;
    RECT 0 476.875 0.070 477.085 ;
    RECT 0 477.155 0.070 477.365 ;
    RECT 0 477.435 0.070 477.645 ;
    RECT 0 477.715 0.070 477.925 ;
    RECT 0 477.995 0.070 478.205 ;
    RECT 0 478.275 0.070 478.485 ;
    RECT 0 478.555 0.070 478.765 ;
    RECT 0 478.835 0.070 479.045 ;
    RECT 0 479.115 0.070 479.325 ;
    RECT 0 479.395 0.070 479.605 ;
    RECT 0 479.675 0.070 479.885 ;
    RECT 0 479.955 0.070 480.165 ;
    RECT 0 480.235 0.070 480.445 ;
    RECT 0 480.515 0.070 480.725 ;
    RECT 0 480.795 0.070 481.005 ;
    RECT 0 481.075 0.070 481.285 ;
    RECT 0 481.355 0.070 481.565 ;
    RECT 0 481.635 0.070 481.845 ;
    RECT 0 481.915 0.070 482.125 ;
    RECT 0 482.195 0.070 482.405 ;
    RECT 0 482.475 0.070 482.685 ;
    RECT 0 482.755 0.070 482.965 ;
    RECT 0 483.035 0.070 483.245 ;
    RECT 0 483.315 0.070 483.525 ;
    RECT 0 483.595 0.070 483.805 ;
    RECT 0 483.875 0.070 484.085 ;
    RECT 0 484.155 0.070 484.365 ;
    RECT 0 484.435 0.070 484.645 ;
    RECT 0 484.715 0.070 484.925 ;
    RECT 0 484.995 0.070 485.205 ;
    RECT 0 485.275 0.070 485.485 ;
    RECT 0 485.555 0.070 485.765 ;
    RECT 0 485.835 0.070 486.045 ;
    RECT 0 486.115 0.070 486.325 ;
    RECT 0 486.395 0.070 486.605 ;
    RECT 0 486.675 0.070 486.885 ;
    RECT 0 486.955 0.070 487.165 ;
    RECT 0 487.235 0.070 487.445 ;
    RECT 0 487.515 0.070 487.725 ;
    RECT 0 487.795 0.070 488.005 ;
    RECT 0 488.075 0.070 488.285 ;
    RECT 0 488.355 0.070 488.565 ;
    RECT 0 488.635 0.070 488.845 ;
    RECT 0 488.915 0.070 489.125 ;
    RECT 0 489.195 0.070 489.405 ;
    RECT 0 489.475 0.070 489.685 ;
    RECT 0 489.755 0.070 489.965 ;
    RECT 0 490.035 0.070 490.245 ;
    RECT 0 490.315 0.070 490.525 ;
    RECT 0 490.595 0.070 490.805 ;
    RECT 0 490.875 0.070 491.085 ;
    RECT 0 491.155 0.070 491.365 ;
    RECT 0 491.435 0.070 491.645 ;
    RECT 0 491.715 0.070 491.925 ;
    RECT 0 491.995 0.070 492.205 ;
    RECT 0 492.275 0.070 492.485 ;
    RECT 0 492.555 0.070 492.765 ;
    RECT 0 492.835 0.070 493.045 ;
    RECT 0 493.115 0.070 493.325 ;
    RECT 0 493.395 0.070 493.605 ;
    RECT 0 493.675 0.070 493.885 ;
    RECT 0 493.955 0.070 494.165 ;
    RECT 0 494.235 0.070 494.445 ;
    RECT 0 494.515 0.070 494.725 ;
    RECT 0 494.795 0.070 495.005 ;
    RECT 0 495.075 0.070 495.285 ;
    RECT 0 495.355 0.070 495.565 ;
    RECT 0 495.635 0.070 495.845 ;
    RECT 0 495.915 0.070 496.125 ;
    RECT 0 496.195 0.070 496.405 ;
    RECT 0 496.475 0.070 496.685 ;
    RECT 0 496.755 0.070 496.965 ;
    RECT 0 497.035 0.070 497.245 ;
    RECT 0 497.315 0.070 497.525 ;
    RECT 0 497.595 0.070 497.805 ;
    RECT 0 497.875 0.070 498.085 ;
    RECT 0 498.155 0.070 498.365 ;
    RECT 0 498.435 0.070 498.645 ;
    RECT 0 498.715 0.070 498.925 ;
    RECT 0 498.995 0.070 499.205 ;
    RECT 0 499.275 0.070 499.485 ;
    RECT 0 499.555 0.070 499.765 ;
    RECT 0 499.835 0.070 500.045 ;
    RECT 0 500.115 0.070 500.325 ;
    RECT 0 500.395 0.070 500.605 ;
    RECT 0 500.675 0.070 500.885 ;
    RECT 0 500.955 0.070 501.165 ;
    RECT 0 501.235 0.070 501.445 ;
    RECT 0 501.515 0.070 501.725 ;
    RECT 0 501.795 0.070 502.005 ;
    RECT 0 502.075 0.070 502.285 ;
    RECT 0 502.355 0.070 502.565 ;
    RECT 0 502.635 0.070 502.845 ;
    RECT 0 502.915 0.070 503.125 ;
    RECT 0 503.195 0.070 503.405 ;
    RECT 0 503.475 0.070 503.685 ;
    RECT 0 503.755 0.070 503.965 ;
    RECT 0 504.035 0.070 504.245 ;
    RECT 0 504.315 0.070 504.525 ;
    RECT 0 504.595 0.070 541.485 ;
    RECT 0 541.555 0.070 541.765 ;
    RECT 0 541.835 0.070 542.045 ;
    RECT 0 542.115 0.070 542.325 ;
    RECT 0 542.395 0.070 542.605 ;
    RECT 0 542.675 0.070 542.885 ;
    RECT 0 542.955 0.070 543.165 ;
    RECT 0 543.235 0.070 543.445 ;
    RECT 0 543.515 0.070 580.405 ;
    RECT 0 580.475 0.070 580.685 ;
    RECT 0 580.755 0.070 580.965 ;
    RECT 0 581.035 0.070 583.800 ;
    LAYER metal4 ;
    RECT 0 0 417.430 1.400 ;
    RECT 0 582.400 417.430 583.800 ;
    RECT 0.000 1.400 1.260 582.400 ;
    RECT 1.540 1.400 2.380 582.400 ;
    RECT 2.660 1.400 3.500 582.400 ;
    RECT 3.780 1.400 4.620 582.400 ;
    RECT 4.900 1.400 5.740 582.400 ;
    RECT 6.020 1.400 6.860 582.400 ;
    RECT 7.140 1.400 7.980 582.400 ;
    RECT 8.260 1.400 9.100 582.400 ;
    RECT 9.380 1.400 10.220 582.400 ;
    RECT 10.500 1.400 11.340 582.400 ;
    RECT 11.620 1.400 12.460 582.400 ;
    RECT 12.740 1.400 13.580 582.400 ;
    RECT 13.860 1.400 14.700 582.400 ;
    RECT 14.980 1.400 15.820 582.400 ;
    RECT 16.100 1.400 16.940 582.400 ;
    RECT 17.220 1.400 18.060 582.400 ;
    RECT 18.340 1.400 19.180 582.400 ;
    RECT 19.460 1.400 20.300 582.400 ;
    RECT 20.580 1.400 21.420 582.400 ;
    RECT 21.700 1.400 22.540 582.400 ;
    RECT 22.820 1.400 23.660 582.400 ;
    RECT 23.940 1.400 24.780 582.400 ;
    RECT 25.060 1.400 25.900 582.400 ;
    RECT 26.180 1.400 27.020 582.400 ;
    RECT 27.300 1.400 28.140 582.400 ;
    RECT 28.420 1.400 29.260 582.400 ;
    RECT 29.540 1.400 30.380 582.400 ;
    RECT 30.660 1.400 31.500 582.400 ;
    RECT 31.780 1.400 32.620 582.400 ;
    RECT 32.900 1.400 33.740 582.400 ;
    RECT 34.020 1.400 34.860 582.400 ;
    RECT 35.140 1.400 35.980 582.400 ;
    RECT 36.260 1.400 37.100 582.400 ;
    RECT 37.380 1.400 38.220 582.400 ;
    RECT 38.500 1.400 39.340 582.400 ;
    RECT 39.620 1.400 40.460 582.400 ;
    RECT 40.740 1.400 41.580 582.400 ;
    RECT 41.860 1.400 42.700 582.400 ;
    RECT 42.980 1.400 43.820 582.400 ;
    RECT 44.100 1.400 44.940 582.400 ;
    RECT 45.220 1.400 46.060 582.400 ;
    RECT 46.340 1.400 47.180 582.400 ;
    RECT 47.460 1.400 48.300 582.400 ;
    RECT 48.580 1.400 49.420 582.400 ;
    RECT 49.700 1.400 50.540 582.400 ;
    RECT 50.820 1.400 51.660 582.400 ;
    RECT 51.940 1.400 52.780 582.400 ;
    RECT 53.060 1.400 53.900 582.400 ;
    RECT 54.180 1.400 55.020 582.400 ;
    RECT 55.300 1.400 56.140 582.400 ;
    RECT 56.420 1.400 57.260 582.400 ;
    RECT 57.540 1.400 58.380 582.400 ;
    RECT 58.660 1.400 59.500 582.400 ;
    RECT 59.780 1.400 60.620 582.400 ;
    RECT 60.900 1.400 61.740 582.400 ;
    RECT 62.020 1.400 62.860 582.400 ;
    RECT 63.140 1.400 63.980 582.400 ;
    RECT 64.260 1.400 65.100 582.400 ;
    RECT 65.380 1.400 66.220 582.400 ;
    RECT 66.500 1.400 67.340 582.400 ;
    RECT 67.620 1.400 68.460 582.400 ;
    RECT 68.740 1.400 69.580 582.400 ;
    RECT 69.860 1.400 70.700 582.400 ;
    RECT 70.980 1.400 71.820 582.400 ;
    RECT 72.100 1.400 72.940 582.400 ;
    RECT 73.220 1.400 74.060 582.400 ;
    RECT 74.340 1.400 75.180 582.400 ;
    RECT 75.460 1.400 76.300 582.400 ;
    RECT 76.580 1.400 77.420 582.400 ;
    RECT 77.700 1.400 78.540 582.400 ;
    RECT 78.820 1.400 79.660 582.400 ;
    RECT 79.940 1.400 80.780 582.400 ;
    RECT 81.060 1.400 81.900 582.400 ;
    RECT 82.180 1.400 83.020 582.400 ;
    RECT 83.300 1.400 84.140 582.400 ;
    RECT 84.420 1.400 85.260 582.400 ;
    RECT 85.540 1.400 86.380 582.400 ;
    RECT 86.660 1.400 87.500 582.400 ;
    RECT 87.780 1.400 88.620 582.400 ;
    RECT 88.900 1.400 89.740 582.400 ;
    RECT 90.020 1.400 90.860 582.400 ;
    RECT 91.140 1.400 91.980 582.400 ;
    RECT 92.260 1.400 93.100 582.400 ;
    RECT 93.380 1.400 94.220 582.400 ;
    RECT 94.500 1.400 95.340 582.400 ;
    RECT 95.620 1.400 96.460 582.400 ;
    RECT 96.740 1.400 97.580 582.400 ;
    RECT 97.860 1.400 98.700 582.400 ;
    RECT 98.980 1.400 99.820 582.400 ;
    RECT 100.100 1.400 100.940 582.400 ;
    RECT 101.220 1.400 102.060 582.400 ;
    RECT 102.340 1.400 103.180 582.400 ;
    RECT 103.460 1.400 104.300 582.400 ;
    RECT 104.580 1.400 105.420 582.400 ;
    RECT 105.700 1.400 106.540 582.400 ;
    RECT 106.820 1.400 107.660 582.400 ;
    RECT 107.940 1.400 108.780 582.400 ;
    RECT 109.060 1.400 109.900 582.400 ;
    RECT 110.180 1.400 111.020 582.400 ;
    RECT 111.300 1.400 112.140 582.400 ;
    RECT 112.420 1.400 113.260 582.400 ;
    RECT 113.540 1.400 114.380 582.400 ;
    RECT 114.660 1.400 115.500 582.400 ;
    RECT 115.780 1.400 116.620 582.400 ;
    RECT 116.900 1.400 117.740 582.400 ;
    RECT 118.020 1.400 118.860 582.400 ;
    RECT 119.140 1.400 119.980 582.400 ;
    RECT 120.260 1.400 121.100 582.400 ;
    RECT 121.380 1.400 122.220 582.400 ;
    RECT 122.500 1.400 123.340 582.400 ;
    RECT 123.620 1.400 124.460 582.400 ;
    RECT 124.740 1.400 125.580 582.400 ;
    RECT 125.860 1.400 126.700 582.400 ;
    RECT 126.980 1.400 127.820 582.400 ;
    RECT 128.100 1.400 128.940 582.400 ;
    RECT 129.220 1.400 130.060 582.400 ;
    RECT 130.340 1.400 131.180 582.400 ;
    RECT 131.460 1.400 132.300 582.400 ;
    RECT 132.580 1.400 133.420 582.400 ;
    RECT 133.700 1.400 134.540 582.400 ;
    RECT 134.820 1.400 135.660 582.400 ;
    RECT 135.940 1.400 136.780 582.400 ;
    RECT 137.060 1.400 137.900 582.400 ;
    RECT 138.180 1.400 139.020 582.400 ;
    RECT 139.300 1.400 140.140 582.400 ;
    RECT 140.420 1.400 141.260 582.400 ;
    RECT 141.540 1.400 142.380 582.400 ;
    RECT 142.660 1.400 143.500 582.400 ;
    RECT 143.780 1.400 144.620 582.400 ;
    RECT 144.900 1.400 145.740 582.400 ;
    RECT 146.020 1.400 146.860 582.400 ;
    RECT 147.140 1.400 147.980 582.400 ;
    RECT 148.260 1.400 149.100 582.400 ;
    RECT 149.380 1.400 150.220 582.400 ;
    RECT 150.500 1.400 151.340 582.400 ;
    RECT 151.620 1.400 152.460 582.400 ;
    RECT 152.740 1.400 153.580 582.400 ;
    RECT 153.860 1.400 154.700 582.400 ;
    RECT 154.980 1.400 155.820 582.400 ;
    RECT 156.100 1.400 156.940 582.400 ;
    RECT 157.220 1.400 158.060 582.400 ;
    RECT 158.340 1.400 159.180 582.400 ;
    RECT 159.460 1.400 160.300 582.400 ;
    RECT 160.580 1.400 161.420 582.400 ;
    RECT 161.700 1.400 162.540 582.400 ;
    RECT 162.820 1.400 163.660 582.400 ;
    RECT 163.940 1.400 164.780 582.400 ;
    RECT 165.060 1.400 165.900 582.400 ;
    RECT 166.180 1.400 167.020 582.400 ;
    RECT 167.300 1.400 168.140 582.400 ;
    RECT 168.420 1.400 169.260 582.400 ;
    RECT 169.540 1.400 170.380 582.400 ;
    RECT 170.660 1.400 171.500 582.400 ;
    RECT 171.780 1.400 172.620 582.400 ;
    RECT 172.900 1.400 173.740 582.400 ;
    RECT 174.020 1.400 174.860 582.400 ;
    RECT 175.140 1.400 175.980 582.400 ;
    RECT 176.260 1.400 177.100 582.400 ;
    RECT 177.380 1.400 178.220 582.400 ;
    RECT 178.500 1.400 179.340 582.400 ;
    RECT 179.620 1.400 180.460 582.400 ;
    RECT 180.740 1.400 181.580 582.400 ;
    RECT 181.860 1.400 182.700 582.400 ;
    RECT 182.980 1.400 183.820 582.400 ;
    RECT 184.100 1.400 184.940 582.400 ;
    RECT 185.220 1.400 186.060 582.400 ;
    RECT 186.340 1.400 187.180 582.400 ;
    RECT 187.460 1.400 188.300 582.400 ;
    RECT 188.580 1.400 189.420 582.400 ;
    RECT 189.700 1.400 190.540 582.400 ;
    RECT 190.820 1.400 191.660 582.400 ;
    RECT 191.940 1.400 192.780 582.400 ;
    RECT 193.060 1.400 193.900 582.400 ;
    RECT 194.180 1.400 195.020 582.400 ;
    RECT 195.300 1.400 196.140 582.400 ;
    RECT 196.420 1.400 197.260 582.400 ;
    RECT 197.540 1.400 198.380 582.400 ;
    RECT 198.660 1.400 199.500 582.400 ;
    RECT 199.780 1.400 200.620 582.400 ;
    RECT 200.900 1.400 201.740 582.400 ;
    RECT 202.020 1.400 202.860 582.400 ;
    RECT 203.140 1.400 203.980 582.400 ;
    RECT 204.260 1.400 205.100 582.400 ;
    RECT 205.380 1.400 206.220 582.400 ;
    RECT 206.500 1.400 207.340 582.400 ;
    RECT 207.620 1.400 208.460 582.400 ;
    RECT 208.740 1.400 209.580 582.400 ;
    RECT 209.860 1.400 210.700 582.400 ;
    RECT 210.980 1.400 211.820 582.400 ;
    RECT 212.100 1.400 212.940 582.400 ;
    RECT 213.220 1.400 214.060 582.400 ;
    RECT 214.340 1.400 215.180 582.400 ;
    RECT 215.460 1.400 216.300 582.400 ;
    RECT 216.580 1.400 217.420 582.400 ;
    RECT 217.700 1.400 218.540 582.400 ;
    RECT 218.820 1.400 219.660 582.400 ;
    RECT 219.940 1.400 220.780 582.400 ;
    RECT 221.060 1.400 221.900 582.400 ;
    RECT 222.180 1.400 223.020 582.400 ;
    RECT 223.300 1.400 224.140 582.400 ;
    RECT 224.420 1.400 225.260 582.400 ;
    RECT 225.540 1.400 226.380 582.400 ;
    RECT 226.660 1.400 227.500 582.400 ;
    RECT 227.780 1.400 228.620 582.400 ;
    RECT 228.900 1.400 229.740 582.400 ;
    RECT 230.020 1.400 230.860 582.400 ;
    RECT 231.140 1.400 231.980 582.400 ;
    RECT 232.260 1.400 233.100 582.400 ;
    RECT 233.380 1.400 234.220 582.400 ;
    RECT 234.500 1.400 235.340 582.400 ;
    RECT 235.620 1.400 236.460 582.400 ;
    RECT 236.740 1.400 237.580 582.400 ;
    RECT 237.860 1.400 238.700 582.400 ;
    RECT 238.980 1.400 239.820 582.400 ;
    RECT 240.100 1.400 240.940 582.400 ;
    RECT 241.220 1.400 242.060 582.400 ;
    RECT 242.340 1.400 243.180 582.400 ;
    RECT 243.460 1.400 244.300 582.400 ;
    RECT 244.580 1.400 245.420 582.400 ;
    RECT 245.700 1.400 246.540 582.400 ;
    RECT 246.820 1.400 247.660 582.400 ;
    RECT 247.940 1.400 248.780 582.400 ;
    RECT 249.060 1.400 249.900 582.400 ;
    RECT 250.180 1.400 251.020 582.400 ;
    RECT 251.300 1.400 252.140 582.400 ;
    RECT 252.420 1.400 253.260 582.400 ;
    RECT 253.540 1.400 254.380 582.400 ;
    RECT 254.660 1.400 255.500 582.400 ;
    RECT 255.780 1.400 256.620 582.400 ;
    RECT 256.900 1.400 257.740 582.400 ;
    RECT 258.020 1.400 258.860 582.400 ;
    RECT 259.140 1.400 259.980 582.400 ;
    RECT 260.260 1.400 261.100 582.400 ;
    RECT 261.380 1.400 262.220 582.400 ;
    RECT 262.500 1.400 263.340 582.400 ;
    RECT 263.620 1.400 264.460 582.400 ;
    RECT 264.740 1.400 265.580 582.400 ;
    RECT 265.860 1.400 266.700 582.400 ;
    RECT 266.980 1.400 267.820 582.400 ;
    RECT 268.100 1.400 268.940 582.400 ;
    RECT 269.220 1.400 270.060 582.400 ;
    RECT 270.340 1.400 271.180 582.400 ;
    RECT 271.460 1.400 272.300 582.400 ;
    RECT 272.580 1.400 273.420 582.400 ;
    RECT 273.700 1.400 274.540 582.400 ;
    RECT 274.820 1.400 275.660 582.400 ;
    RECT 275.940 1.400 276.780 582.400 ;
    RECT 277.060 1.400 277.900 582.400 ;
    RECT 278.180 1.400 279.020 582.400 ;
    RECT 279.300 1.400 280.140 582.400 ;
    RECT 280.420 1.400 281.260 582.400 ;
    RECT 281.540 1.400 282.380 582.400 ;
    RECT 282.660 1.400 283.500 582.400 ;
    RECT 283.780 1.400 284.620 582.400 ;
    RECT 284.900 1.400 285.740 582.400 ;
    RECT 286.020 1.400 286.860 582.400 ;
    RECT 287.140 1.400 287.980 582.400 ;
    RECT 288.260 1.400 289.100 582.400 ;
    RECT 289.380 1.400 290.220 582.400 ;
    RECT 290.500 1.400 291.340 582.400 ;
    RECT 291.620 1.400 292.460 582.400 ;
    RECT 292.740 1.400 293.580 582.400 ;
    RECT 293.860 1.400 294.700 582.400 ;
    RECT 294.980 1.400 295.820 582.400 ;
    RECT 296.100 1.400 296.940 582.400 ;
    RECT 297.220 1.400 298.060 582.400 ;
    RECT 298.340 1.400 299.180 582.400 ;
    RECT 299.460 1.400 300.300 582.400 ;
    RECT 300.580 1.400 301.420 582.400 ;
    RECT 301.700 1.400 302.540 582.400 ;
    RECT 302.820 1.400 303.660 582.400 ;
    RECT 303.940 1.400 304.780 582.400 ;
    RECT 305.060 1.400 305.900 582.400 ;
    RECT 306.180 1.400 307.020 582.400 ;
    RECT 307.300 1.400 308.140 582.400 ;
    RECT 308.420 1.400 309.260 582.400 ;
    RECT 309.540 1.400 310.380 582.400 ;
    RECT 310.660 1.400 311.500 582.400 ;
    RECT 311.780 1.400 312.620 582.400 ;
    RECT 312.900 1.400 313.740 582.400 ;
    RECT 314.020 1.400 314.860 582.400 ;
    RECT 315.140 1.400 315.980 582.400 ;
    RECT 316.260 1.400 317.100 582.400 ;
    RECT 317.380 1.400 318.220 582.400 ;
    RECT 318.500 1.400 319.340 582.400 ;
    RECT 319.620 1.400 320.460 582.400 ;
    RECT 320.740 1.400 321.580 582.400 ;
    RECT 321.860 1.400 322.700 582.400 ;
    RECT 322.980 1.400 323.820 582.400 ;
    RECT 324.100 1.400 324.940 582.400 ;
    RECT 325.220 1.400 326.060 582.400 ;
    RECT 326.340 1.400 327.180 582.400 ;
    RECT 327.460 1.400 328.300 582.400 ;
    RECT 328.580 1.400 329.420 582.400 ;
    RECT 329.700 1.400 330.540 582.400 ;
    RECT 330.820 1.400 331.660 582.400 ;
    RECT 331.940 1.400 332.780 582.400 ;
    RECT 333.060 1.400 333.900 582.400 ;
    RECT 334.180 1.400 335.020 582.400 ;
    RECT 335.300 1.400 336.140 582.400 ;
    RECT 336.420 1.400 337.260 582.400 ;
    RECT 337.540 1.400 338.380 582.400 ;
    RECT 338.660 1.400 339.500 582.400 ;
    RECT 339.780 1.400 340.620 582.400 ;
    RECT 340.900 1.400 341.740 582.400 ;
    RECT 342.020 1.400 342.860 582.400 ;
    RECT 343.140 1.400 343.980 582.400 ;
    RECT 344.260 1.400 345.100 582.400 ;
    RECT 345.380 1.400 346.220 582.400 ;
    RECT 346.500 1.400 347.340 582.400 ;
    RECT 347.620 1.400 348.460 582.400 ;
    RECT 348.740 1.400 349.580 582.400 ;
    RECT 349.860 1.400 350.700 582.400 ;
    RECT 350.980 1.400 351.820 582.400 ;
    RECT 352.100 1.400 352.940 582.400 ;
    RECT 353.220 1.400 354.060 582.400 ;
    RECT 354.340 1.400 355.180 582.400 ;
    RECT 355.460 1.400 356.300 582.400 ;
    RECT 356.580 1.400 357.420 582.400 ;
    RECT 357.700 1.400 358.540 582.400 ;
    RECT 358.820 1.400 359.660 582.400 ;
    RECT 359.940 1.400 360.780 582.400 ;
    RECT 361.060 1.400 361.900 582.400 ;
    RECT 362.180 1.400 363.020 582.400 ;
    RECT 363.300 1.400 364.140 582.400 ;
    RECT 364.420 1.400 365.260 582.400 ;
    RECT 365.540 1.400 366.380 582.400 ;
    RECT 366.660 1.400 367.500 582.400 ;
    RECT 367.780 1.400 368.620 582.400 ;
    RECT 368.900 1.400 369.740 582.400 ;
    RECT 370.020 1.400 370.860 582.400 ;
    RECT 371.140 1.400 371.980 582.400 ;
    RECT 372.260 1.400 373.100 582.400 ;
    RECT 373.380 1.400 374.220 582.400 ;
    RECT 374.500 1.400 375.340 582.400 ;
    RECT 375.620 1.400 376.460 582.400 ;
    RECT 376.740 1.400 377.580 582.400 ;
    RECT 377.860 1.400 378.700 582.400 ;
    RECT 378.980 1.400 379.820 582.400 ;
    RECT 380.100 1.400 380.940 582.400 ;
    RECT 381.220 1.400 382.060 582.400 ;
    RECT 382.340 1.400 383.180 582.400 ;
    RECT 383.460 1.400 384.300 582.400 ;
    RECT 384.580 1.400 385.420 582.400 ;
    RECT 385.700 1.400 386.540 582.400 ;
    RECT 386.820 1.400 387.660 582.400 ;
    RECT 387.940 1.400 388.780 582.400 ;
    RECT 389.060 1.400 389.900 582.400 ;
    RECT 390.180 1.400 391.020 582.400 ;
    RECT 391.300 1.400 392.140 582.400 ;
    RECT 392.420 1.400 393.260 582.400 ;
    RECT 393.540 1.400 394.380 582.400 ;
    RECT 394.660 1.400 395.500 582.400 ;
    RECT 395.780 1.400 396.620 582.400 ;
    RECT 396.900 1.400 397.740 582.400 ;
    RECT 398.020 1.400 398.860 582.400 ;
    RECT 399.140 1.400 399.980 582.400 ;
    RECT 400.260 1.400 401.100 582.400 ;
    RECT 401.380 1.400 402.220 582.400 ;
    RECT 402.500 1.400 403.340 582.400 ;
    RECT 403.620 1.400 404.460 582.400 ;
    RECT 404.740 1.400 405.580 582.400 ;
    RECT 405.860 1.400 406.700 582.400 ;
    RECT 406.980 1.400 407.820 582.400 ;
    RECT 408.100 1.400 408.940 582.400 ;
    RECT 409.220 1.400 410.060 582.400 ;
    RECT 410.340 1.400 411.180 582.400 ;
    RECT 411.460 1.400 412.300 582.400 ;
    RECT 412.580 1.400 413.420 582.400 ;
    RECT 413.700 1.400 414.540 582.400 ;
    RECT 414.820 1.400 415.660 582.400 ;
    RECT 415.940 1.400 417.430 582.400 ;
    LAYER OVERLAP ;
    RECT 0 0 417.430 583.800 ;
  END
END sram_256x512_1rw

END LIBRARY
